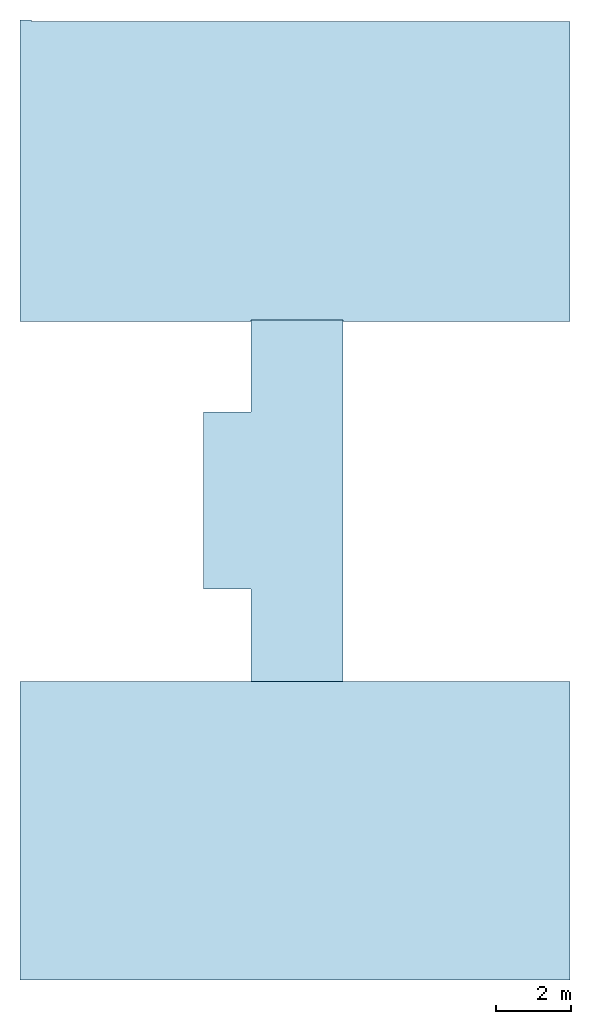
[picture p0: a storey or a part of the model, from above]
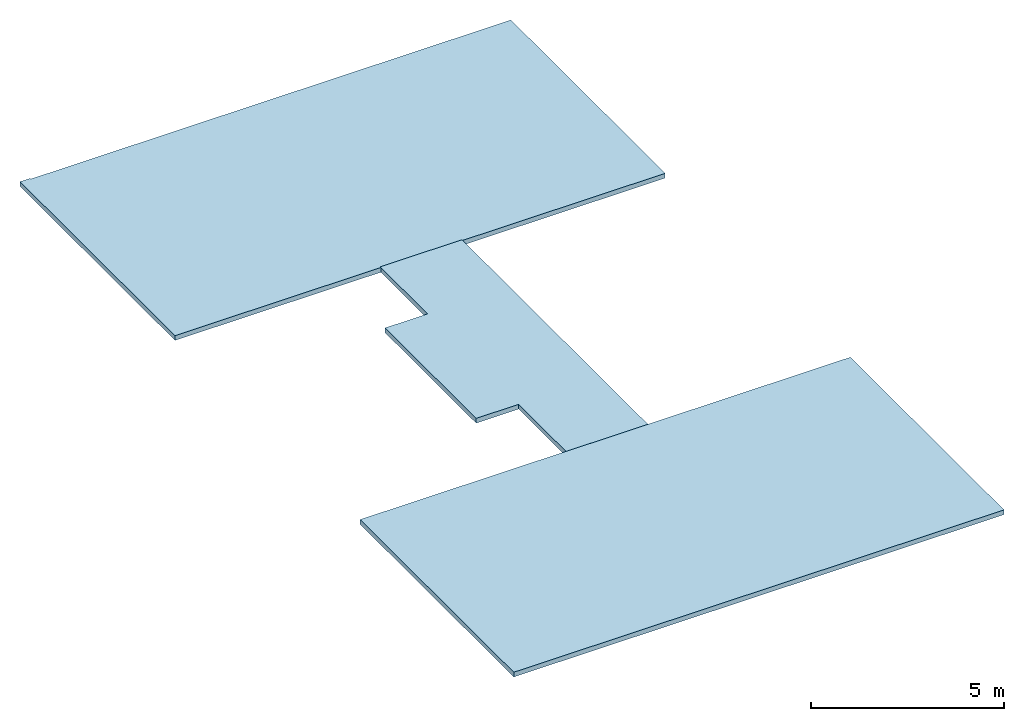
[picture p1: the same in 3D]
Properties of the parts of a building model (IFC2X3), part 1 of 7

# File
Description: ViewDefinition [CoordinationView_V2.0, QuantityTakeOffAddOnView], Option [Elements to export: Visible elements (on all stories)], Option [Partial Structure Display: Entire Model], Option [IFC Domain: All], Option [Structural Function: All Elements], Option [Convert Grid elements: On], Option [Convert IFC Annotations and ARCHICAD 2D elements: Off], Option [Convert 2D symbols of Doors and Windows: Off], Option [Export geometries that Participates in Collision Detection only: On], Option [Split complex elements: Off], Option [Material Preservation: Explode where necessary], Option [Elements in Solid Element Operations: Extruded/revolved], Option [Elements with junctions: Extruded/revolved without junctions], Option [IFC Model position: Survey Point and Project Origin], Option [Curtain Wall export mode: Container Element], Option [Railing export mode: Container Element], Option [Stair export mode: Container Element], Option [Properties To Export: All properties], Option [Space containment: Off], Option [Bounding Box: Off], Option [Geometry to type objects: Off], Option [Element Properties: All], Option [Building Material Properties: Off], Option [Element Parameters: IFC Element Quantities Only], Option [Component Parameters: All], Option [IFC Base Quantities: On], Option [Door Window Parameters: On], Option [IFC Space boundaries: Off], Option [ARCHICAD Zone Categories as IFC Space classification data: Off], Option [Element Classifications: On]
File name: H:\FAU 2022\PUB\entrega 6\CECAP-PMR R06 IFC2X3.ifc
Time: 2022-08-30T10:22:52
Author: Architect
Organization: Building Designer Office
Written by: The EXPRESS Data Manager Version 5.02.0100.09 : 26 Sep 2013
Made in: IFC file generated by GRAPHISOFT ARCHICAD 25.0.0 BRA FULL Windows version (IFC add-on version: 5010 BRA FULL).
Authorization: The authorising person

# IfcProject, CECAP Guarulhos
Description: Residência com Subsídio Governamental

# IfcSite, Local
RefLatitude: -23, -32, 0, 0; RefLongitude: -46, -38, 0, 0; RefElevation: 0 mm
BaseQuantities - GrossPerimeter: 0 mm; GrossArea: 0 m2

# IfcBuilding, Construção
BaseQuantities - GrossFloorArea: 1045.01 m2

# IfcBuildingStorey (5)
In: Construção
BaseQuantities - NetHeight: 2650 mm; GrossHeight: 2650 mm; Height: 2650 mm
Name | Elevation (mm) | GrossFloorArea (m2)
Pavimento Terreo | -2650 | 271.185
Primeiro Pavimento | 0 | 258.197
Segundo Pavimento | 2650 | 257.883
Terceiro Pavimento | 5300 | 257.748
Pavimento Cobertura | 7950 | 0

# IfcSpace: CIRCULAÇÃO (7)
InteriorOrExteriorSpace: INTERNAL
Pset_SpaceCommon - Category: CIRCULAÇÃO
ILUMINAÇÃO E VENTILAÇÃO (Expressão) - Área das Aberturas Projetada: 0; Atende: Atende; Não Atende: Não Atende
REVESTIMENTO DE PAREDE POR ZONA (Expressão) - Número de Linhas: 10; DImensão 1: 0 mm; Dimensão 2: 0 mm; Largura do Rejunte: 10 mm; Altura do Revestimento: 100 mm
RODAPÉ (Expressão) - Comprimento da Barra (m): 2.4; Custo da Barra: 0; Estimativa de Custo: 0
AC_Pset_RenovationAndPhasing - Renovation Status: Existing
BaseQuantities - FinishFloorHeight: 0 mm
ArchiCADQuantities - Elevação ao Piso: 0 mm; Afastamento da Origem: 0 mm; Afastamento do Topo: 0 mm; Perímetro Furos da Planta: 0 mm; Elevação da Base Ao Piso de Origem: 0 mm; Nível Base: 0 mm; Número de Pilares: 0; Número de Luminárias: 0; Número de Objetos: 0; Número de Janelas: 0; Área de Superfície das Janelas: 0 m2; Largura Janelas: 0 mm; Espessura de Pavimento: 0 mm; Redução de área: 1 m2; Extrair Área da Base do Pilar: 0 m2; Extrair Área da Trama: 0 m2; Área Baixa Extraída: 0 m2; Extrair Área da Base da Parede: 0 m2; Área Total Extraída: 0 m2; Inserção da Parede no Lado Posterior da Área de Superfície: 0 m2; Inserção da Parede no Lado da Área de Superfície: 0 m2; Inserção da Parede na Área da Superfície do Topo: 0 m2; Área Extraída da Parede Cortina: 0 m2
AC_Equantity_Selo_de_Zona_01_25 - Perímetro dos Vãos: 0 mm; Largura Combinada das Janelas: 0 mm; Nível do Piso: 0 mm; Espessura do Subpiso: 0 mm; Tamanho de Fonte para Texto de Detalhe (modelo): 300 mm
Name | In | LongName | Classification | Zona - Número de Azulejos Necessários | Quantidade de Barras | ID Dinâmico por Classificação | Height (mm) = FinishCeilingHeight (mm) = ClearHeight (mm) = ArchiCADQuantities, Altura (mm) = Elevação do Topo Ao Piso de Origem (mm) = AC_Equantity_Selo_de_Zona_01_25, Altura (mm) | GrossFloorArea (m2) = NetFloorArea (m2) = SpaceNetFloorAreaBOMA (m2) = SpaceUsableFloorAreaBOMA (m2) = GrossCeilingArea (m2) = NetCeilingArea (m2) = Área (m2) = Área da Superfície do Topo (Líquida) (m2) = Área da Superfície da Base (Líquida) (m2) = Área Calculada (m2) = Área Medida (m2) = Área Líquida Medida (m2) = Área Reduzida (m2) | GrossWallArea (m2) | NetWallArea (m2) = Área de Superfície das Paredes (m2) | GrossPerimeter (mm) = NetPerimeter (mm) = Perímetro Útil da Zona (mm) = Perímetro Bruto Zona (mm) = Perímetro (mm) = Perímetro Útil (mm) | GrossVolume (m3) = NetVolume (m3) = Volume (Líquido) (m3) | Elevação à Origem do Projeto (mm) = Elevação ao 1º Nível de Referência (mm) = Elevação ao 2º Nível de Referência (mm) = Elevação ao Nível do Mar (mm) = Elevação da Base Ao Primeiro Nível de Referência (mm) = Elevação da Base À Cota Zero (mm) = Elevação da Base Ao Nível do Mar (mm) = Elevação da Base Ao Segundo Nível de Referência (mm) | Elevação do Topo ao Primeiro Nível de Referência (mm) = Elevação do Topo À Cota Zero (mm) = Elevação do Topo Ao Nível do Mar (mm) = Elevação do Topo Ao Segundo Nível de Referência (mm) | Área da Superfície da Borda (Líquida) (m2) | Número de Vigas | Número de Portas | Número de Itens de Paredes | Área de Superfície das Portas (m2) | Largura Portas (mm) = Largura Combinada das Portas (mm) | Perímetro Paredes (mm) = Comprimento das Paredes Perímetro (mm) | Número dos Cantos Côncavos | Número de Cantos | Estimativa de Rodapé (ml) (mm)
02 | Pavimento Terreo | ESCADA | Zoneamento (Classificação ARCHICAD); 4A 16 01 04 07 Escada de Uso Comum (NBR 15965-6 4A) | 15630 | 4 | Zoneamento -002 | 2650 | 7.0315 | 21.8576 | 21.8576 | 15630 | 18.6335 | -2650 | 0 | 41.4195 | 2 | 0 | 5 | 0 | 0 | 9050 | 2 | 8 | 9050
33 | Primeiro Pavimento | CORREDOR | Zoneamento (Classificação ARCHICAD); 4A 16 04 01 Corredor (NBR 15965-6 4A) | 25080 | 10 | Zoneamento -004 | 2650 | 20.0698 | 41.925 | 34.365 | 28680 | 53.185 | 0 | 2650 | 76.002 | 6 | 4 | 22 | 7.56 | 3600 | 26812.9 | 10 | 24 | 23212.9
34 | Primeiro Pavimento | ESCADA | Zoneamento (Classificação ARCHICAD); 4A 16 01 04 07 Escada de Uso Comum (NBR 15965-6 4A) | 15630 | 4 | Zoneamento -005 | 5300 | 7.0315 | 21.8576 | 21.8576 | 15630 | 37.2669 | 0 | 5300 | 41.4195 | 2 | 0 | 5 | 0 | 0 | 9050 | 2 | 8 | 9050
33 | Segundo Pavimento | CORREDOR | Zoneamento (Classificação ARCHICAD); 4A 16 04 01 Corredor (NBR 15965-6 4A) | 25080 | 10 | Zoneamento -032 | 2650 | 20.0698 | 41.981 | 34.421 | 28680 | 53.185 | 2650 | 5300 | 76.002 | 6 | 4 | 23 | 7.56 | 3600 | 26812.9 | 10 | 24 | 23212.9
34 | Segundo Pavimento | ESCADA | Zoneamento (Classificação ARCHICAD); 4A 16 01 04 07 Escada de Uso Comum (NBR 15965-6 4A) | 15630 | 4 | Zoneamento -031 | 5300 | 7.0315 | 23.0336 | 23.0336 | 15630 | 37.2669 | 2650 | 7950 | 41.4195 | 2 | 0 | 6 | 0 | 0 | 9050 | 2 | 8 | 9050
33 | Terceiro Pavimento | CORREDOR | Zoneamento (Classificação ARCHICAD); 4A 16 04 01 Corredor (NBR 15965-6 4A) | 25080 | 10 | Zoneamento -060 | 2650 | 20.0698 | 41.292 | 33.732 | 28680 | 53.185 | 5300 | 7950 | 76.002 | 6 | 4 | 22 | 7.56 | 3600 | 26812.9 | 10 | 24 | 23212.9
34 | Terceiro Pavimento | ESCADA | Zoneamento (Classificação ARCHICAD); 4A 16 01 04 07 Escada de Uso Comum (NBR 15965-6 4A) | 15630 | 4 | Zoneamento -041 | 2650 | 7.0315 | 21.29 | 21.29 | 15630 | 18.6335 | 5300 | 7950 | 41.4195 | 3 | 0 | 5 | 0 | 0 | 9050 | 2 | 8 | 9050

# IfcSpace: ESTACIONAMENTO (2)
In: Pavimento Terreo
LongName: ESTACIONAMENTO; InteriorOrExteriorSpace: INTERNAL; Classification: Zoneamento (Classificação ARCHICAD); 4A 19 04 13 Garagem (NBR 15965-6 4A)
Pset_SpaceCommon - Category: ESTACIONAMENTO
ILUMINAÇÃO E VENTILAÇÃO (Expressão) - Área das Aberturas Projetada: 0; Atende: Atende; Não Atende: Não Atende
REVESTIMENTO DE PAREDE POR ZONA (Expressão) - Número de Linhas: 10; Zona - Número de Azulejos Necessários: 45870; DImensão 1: 0 mm; Dimensão 2: 0 mm; Largura do Rejunte: 10 mm; Altura do Revestimento: 100 mm
RODAPÉ (Expressão) - Comprimento da Barra (m): 2.4; Quantidade de Barras: 0; Custo da Barra: 0; Estimativa de Custo: 0; Estimativa de Rodapé (ml): 0 mm
AC_Pset_RenovationAndPhasing - Renovation Status: Existing
BaseQuantities - Height: 2650 mm; FinishCeilingHeight: 2650 mm; FinishFloorHeight: 0 mm; ClearHeight: 2650 mm; GrossFloorArea: 121.248 m2; NetFloorArea: 121.248 m2; SpaceNetFloorAreaBOMA: 121.248 m2; SpaceUsableFloorAreaBOMA: 121.248 m2; GrossCeilingArea: 121.248 m2; NetCeilingArea: 121.248 m2; GrossWallArea: 0 m2; NetWallArea: 0 m2; GrossPerimeter: 45870 mm; NetPerimeter: 45870 mm; GrossVolume: 321.306 m3; NetVolume: 321.306 m3
ArchiCADQuantities - Área: 121.248 m2; Altura: 2650 mm; Volume (Líquido): 321.306 m3; Elevação à Origem do Projeto: -2650 mm; Elevação ao 1º Nível de Referência: -2650 mm; Elevação ao 2º Nível de Referência: -2650 mm; Elevação ao Nível do Mar: -2650 mm; Elevação ao Piso: 0 mm; Afastamento da Origem: 0 mm; Afastamento do Topo: 0 mm; Perímetro Furos da Planta: 0 mm; Elevação do Topo ao Primeiro Nível de Referência: 0 mm; Elevação do Topo Ao Piso de Origem: 2650 mm; Elevação do Topo À Cota Zero: 0 mm; Elevação do Topo Ao Nível do Mar: 0 mm; Elevação do Topo Ao Segundo Nível de Referência: 0 mm; Elevação da Base Ao Primeiro Nível de Referência: -2650 mm; Elevação da Base Ao Piso de Origem: 0 mm; Elevação da Base À Cota Zero: -2650 mm; Elevação da Base Ao Nível do Mar: -2650 mm; Elevação da Base Ao Segundo Nível de Referência: -2650 mm; Área da Superfície do Topo (Líquida): 121.248 m2; Área da Superfície da Borda (Líquida): 121.556 m2; Área da Superfície da Base (Líquida): 121.248 m2; Nível Base: 0 mm; Número de Vigas: 11; Número de Pilares: 6; Número de Portas: 0; Número de Luminárias: 0; Número de Objetos: 0; Número de Janelas: 0; Número de Itens de Paredes: 0; Área Calculada: 121.248 m2; Área Medida: 121.248 m2; Área de Superfície das Janelas: 0 m2; Área de Superfície das Portas: 0 m2; Área de Superfície das Paredes: 0 m2; Largura Portas: 0 mm; Largura Janelas: 0 mm; Perímetro Paredes: 0 mm; Perímetro Útil da Zona: 45870 mm; Perímetro Bruto Zona: 45870 mm; Espessura de Pavimento: 0 mm; Redução de área: 1 m2; Extrair Área da Base do Pilar: 0 m2; Extrair Área da Trama: 0 m2; Área Baixa Extraída: 0 m2; Extrair Área da Base da Parede: 0 m2; Área Líquida Medida: 121.248 m2; Número dos Cantos Côncavos: 0; Número de Cantos: 4; Área Reduzida: 121.248 m2; Área Total Extraída: 0 m2; Inserção da Parede no Lado Posterior da Área de Superfície: 0 m2; Inserção da Parede no Lado da Área de Superfície: 0 m2; Inserção da Parede na Área da Superfície do Topo: 0 m2; Área Extraída da Parede Cortina: 0 m2
AC_Equantity_Selo_de_Zona_01_25 - Perímetro: 45870 mm; Perímetro dos Vãos: 0 mm; Comprimento das Paredes Perímetro: 0 mm; Largura Combinada das Portas: 0 mm; Largura Combinada das Janelas: 0 mm; Nível do Piso: 0 mm; Espessura do Subpiso: 0 mm; Altura: 2650 mm; Perímetro Útil: 45870 mm; Tamanho de Fonte para Texto de Detalhe (modelo): 300 mm
Name | ID Dinâmico por Classificação
04 | Zoneamento -001
03 | Zoneamento -000

# IfcSpace: ÁREA COMUM, 01
In: Pavimento Terreo
LongName: ÁREA COBERTA; InteriorOrExteriorSpace: INTERNAL; Classification: Zoneamento (Classificação ARCHICAD); 4A 16 04 01 Corredor (NBR 15965-6 4A)
Pset_SpaceCommon - Category: ÁREA COMUM
ILUMINAÇÃO E VENTILAÇÃO (Expressão) - Área das Aberturas Projetada: 0; Atende: Atende; Não Atende: Não Atende
REVESTIMENTO DE PAREDE POR ZONA (Expressão) - Número de Linhas: 10; Zona - Número de Azulejos Necessários: 28540; DImensão 1: 0 mm; Dimensão 2: 0 mm; Largura do Rejunte: 10 mm; Altura do Revestimento: 100 mm
RODAPÉ (Expressão) - Comprimento da Barra (m): 2.4; Quantidade de Barras: 11; Custo da Barra: 0; Estimativa de Custo: 0; Estimativa de Rodapé (ml): 26812.9 mm
EXPRESSÕES DE TEXTO (Expressão) - ID Dinâmico por Classificação: Zoneamento -003
AC_Pset_RenovationAndPhasing - Renovation Status: Existing
BaseQuantities - Height: 2650 mm; FinishCeilingHeight: 2650 mm; FinishFloorHeight: 0 mm; ClearHeight: 2650 mm; GrossFloorArea: 20.0831 m2; NetFloorArea: 20.0831 m2; SpaceNetFloorAreaBOMA: 20.0831 m2; SpaceUsableFloorAreaBOMA: 20.0831 m2; GrossCeilingArea: 20.0831 m2; NetCeilingArea: 20.0831 m2; GrossWallArea: 16.991 m2; NetWallArea: 16.991 m2; GrossPerimeter: 28540 mm; NetPerimeter: 28540 mm; GrossVolume: 53.2202 m3; NetVolume: 53.2202 m3
ArchiCADQuantities - Área: 20.0831 m2; Altura: 2650 mm; Volume (Líquido): 53.2202 m3; Elevação à Origem do Projeto: -2650 mm; Elevação ao 1º Nível de Referência: -2650 mm; Elevação ao 2º Nível de Referência: -2650 mm; Elevação ao Nível do Mar: -2650 mm; Elevação ao Piso: 0 mm; Afastamento da Origem: 0 mm; Afastamento do Topo: 0 mm; Perímetro Furos da Planta: 0 mm; Elevação do Topo ao Primeiro Nível de Referência: 0 mm; Elevação do Topo Ao Piso de Origem: 2650 mm; Elevação do Topo À Cota Zero: 0 mm; Elevação do Topo Ao Nível do Mar: 0 mm; Elevação do Topo Ao Segundo Nível de Referência: 0 mm; Elevação da Base Ao Primeiro Nível de Referência: -2650 mm; Elevação da Base Ao Piso de Origem: 0 mm; Elevação da Base À Cota Zero: -2650 mm; Elevação da Base Ao Nível do Mar: -2650 mm; Elevação da Base Ao Segundo Nível de Referência: -2650 mm; Área da Superfície do Topo (Líquida): 20.0831 m2; Área da Superfície da Borda (Líquida): 75.631 m2; Área da Superfície da Base (Líquida): 20.0831 m2; Nível Base: 0 mm; Número de Vigas: 4; Número de Pilares: 0; Número de Portas: 0; Número de Luminárias: 0; Número de Objetos: 0; Número de Janelas: 0; Número de Itens de Paredes: 9; Área Calculada: 20.0831 m2; Área Medida: 20.0831 m2; Área de Superfície das Janelas: 0 m2; Área de Superfície das Portas: 0 m2; Área de Superfície das Paredes: 16.991 m2; Largura Portas: 0 mm; Largura Janelas: 0 mm; Perímetro Paredes: 26812.9 mm; Perímetro Útil da Zona: 28540 mm; Perímetro Bruto Zona: 28540 mm; Espessura de Pavimento: 0 mm; Redução de área: 1 m2; Extrair Área da Base do Pilar: 0 m2; Extrair Área da Trama: 0 m2; Área Baixa Extraída: 0 m2; Extrair Área da Base da Parede: 0 m2; Área Líquida Medida: 20.0831 m2; Número dos Cantos Côncavos: 4; Número de Cantos: 20; Área Reduzida: 20.0831 m2; Área Total Extraída: 0 m2; Inserção da Parede no Lado Posterior da Área de Superfície: 0 m2; Inserção da Parede no Lado da Área de Superfície: 0 m2; Inserção da Parede na Área da Superfície do Topo: 0 m2; Área Extraída da Parede Cortina: 0 m2
AC_Equantity_Selo_de_Zona_01_25 - Perímetro: 28540 mm; Perímetro dos Vãos: 0 mm; Comprimento das Paredes Perímetro: 26812.9 mm; Largura Combinada das Portas: 3600 mm; Largura Combinada das Janelas: 0 mm; Nível do Piso: 0 mm; Espessura do Subpiso: 0 mm; Altura: 2650 mm; Perímetro Útil: 28540 mm; Tamanho de Fonte para Texto de Detalhe (modelo): 300 mm

# IfcSpace: ÁREA PRIVATIVA APTO 01 (7)
In: Primeiro Pavimento
InteriorOrExteriorSpace: INTERNAL
Pset_SpaceCommon - Category: ÁREA PRIVATIVA APTO 01
ILUMINAÇÃO E VENTILAÇÃO (Expressão) - Área das Aberturas Projetada: 0; Atende: Atende; Não Atende: Não Atende
REVESTIMENTO DE PAREDE POR ZONA (Expressão) - Número de Linhas: 10; DImensão 1: 0 mm; Dimensão 2: 0 mm; Largura do Rejunte: 10 mm; Altura do Revestimento: 100 mm
RODAPÉ (Expressão) - Comprimento da Barra (m): 2.4; Custo da Barra: 0; Estimativa de Custo: 0
AC_Pset_RenovationAndPhasing - Renovation Status: Existing
BaseQuantities - Height: 2650 mm; FinishCeilingHeight: 2650 mm; FinishFloorHeight: 0 mm; ClearHeight: 2650 mm
ArchiCADQuantities - Altura: 2650 mm; Elevação à Origem do Projeto: 0 mm; Elevação ao 1º Nível de Referência: 0 mm; Elevação ao 2º Nível de Referência: 0 mm; Elevação ao Nível do Mar: 0 mm; Elevação ao Piso: 0 mm; Afastamento da Origem: 0 mm; Afastamento do Topo: 0 mm; Perímetro Furos da Planta: 0 mm; Elevação do Topo ao Primeiro Nível de Referência: 2650 mm; Elevação do Topo Ao Piso de Origem: 2650 mm; Elevação do Topo À Cota Zero: 2650 mm; Elevação do Topo Ao Nível do Mar: 2650 mm; Elevação do Topo Ao Segundo Nível de Referência: 2650 mm; Elevação da Base Ao Primeiro Nível de Referência: 0 mm; Elevação da Base Ao Piso de Origem: 0 mm; Elevação da Base À Cota Zero: 0 mm; Elevação da Base Ao Nível do Mar: 0 mm; Elevação da Base Ao Segundo Nível de Referência: 0 mm; Nível Base: 0 mm; Número de Pilares: 0; Número de Luminárias: 0; Número de Objetos: 0; Número de Janelas: 0; Área de Superfície das Janelas: 0 m2; Largura Janelas: 0 mm; Espessura de Pavimento: 0 mm; Redução de área: 1 m2; Extrair Área da Base do Pilar: 0 m2; Extrair Área da Trama: 0 m2; Área Baixa Extraída: 0 m2; Extrair Área da Base da Parede: 0 m2; Número dos Cantos Côncavos: 0; Número de Cantos: 4; Área Total Extraída: 0 m2; Inserção da Parede no Lado Posterior da Área de Superfície: 0 m2; Inserção da Parede no Lado da Área de Superfície: 0 m2; Inserção da Parede na Área da Superfície do Topo: 0 m2; Área Extraída da Parede Cortina: 0 m2
AC_Equantity_Selo_de_Zona_01_25 - Perímetro dos Vãos: 0 mm; Nível do Piso: 0 mm; Espessura do Subpiso: 0 mm; Altura: 2650 mm; Tamanho de Fonte para Texto de Detalhe (modelo): 300 mm
Name | LongName | Classification | Zona - Número de Azulejos Necessários | Quantidade de Barras | ID Dinâmico por Classificação | GrossFloorArea (m2) = NetFloorArea (m2) = SpaceNetFloorAreaBOMA (m2) = SpaceUsableFloorAreaBOMA (m2) = GrossCeilingArea (m2) = NetCeilingArea (m2) = Área (m2) = Área da Superfície do Topo (Líquida) (m2) = Área da Superfície da Base (Líquida) (m2) = Área Calculada (m2) = Área Medida (m2) = Área Líquida Medida (m2) = Área Reduzida (m2) | GrossWallArea (m2) | NetWallArea (m2) = Área de Superfície das Paredes (m2) | GrossPerimeter (mm) = NetPerimeter (mm) = Perímetro Útil da Zona (mm) = Perímetro Bruto Zona (mm) = Perímetro (mm) = Perímetro Útil (mm) | GrossVolume (m3) = NetVolume (m3) = Volume (Líquido) (m3) | Área da Superfície da Borda (Líquida) (m2) | Número de Vigas | Número de Portas | Número de Itens de Paredes | Área de Superfície das Portas (m2) | Largura Portas (mm) | Perímetro Paredes (mm) = Comprimento das Paredes Perímetro (mm) | Largura Combinada das Portas (mm) | Largura Combinada das Janelas (mm) | Estimativa de Rodapé (ml) (mm)
06 | SALA | Zoneamento (Classificação ARCHICAD); 4A 19 01 07 Sala de Estar (NBR 15965-6 4A) | 15060 | 4 | Zoneamento -073 | 15.6592 | 23.3628 | 21.4728 | 15959.6 | 41.497 | 42.2928 | 5 | 1 | 5 | 1.89 | 900 | 9809.78 | 710 | 2040 | 8909.78
11 | QUARTO | Zoneamento (Classificação ARCHICAD); 4A 19 01 01 Dormitório (NBR 15965-6 4A) | 11010 | 4 | Zoneamento -074 | 7.12419 | 16.794 | 16.794 | 11010.2 | 18.8791 | 29.177 | 4 | 0 | 2 | 0 | 0 | 8850.18 | 0 | 2080 | 8850.18
10 | QUARTO | Zoneamento (Classificação ARCHICAD); 4A 19 01 01 Dormitório (NBR 15965-6 4A) | 10970 | 4 | Zoneamento -075 | 7.05588 | 16.8413 | 16.8413 | 10970.4 | 18.6981 | 29.0715 | 4 | 0 | 2 | 0 | 0 | 8830.36 | 0 | 2060 | 8830.36
09 | QUARTO | Zoneamento (Classificação ARCHICAD); 4A 19 01 01 Dormitório (NBR 15965-6 4A) | 12311 | 5 | Zoneamento -076 | 9.38311 | 16.6677 | 16.6677 | 12310.4 | 24.8652 | 32.6227 | 3 | 0 | 2 | 0 | 0 | 11330.4 | 0 | 2780 | 11330.4
05 | COZINHA | Zoneamento (Classificação ARCHICAD); 4A 19 01 25 Cozinha (NBR 15965-6 4A) | 12370 | 4 | Zoneamento -077 | 9.17955 | 19.063 | 17.572 | 13079.6 | 24.3258 | 34.6608 | 5 | 1 | 3 | 1.491 | 710 | 9809.78 | 710 | 2040 | 9099.78
07 | WC | Zoneamento (Classificação ARCHICAD); 4A 19 04 07 Banheiro residencial (NBR 15965-6 4A) | 7150 | 3 | Zoneamento -078 | 3.4827 | 19.1359 | 17.6449 | 7859.56 | 9.22916 | 20.8278 | 3 | 1 | 4 | 1.491 | 710 | 7859.56 | 710 | 0 | 7149.56
08 | LAVANDERIA | Zoneamento (Classificação ARCHICAD); 4A 19 04 04 Lavanderia (NBR 15965-6 4A) | 5940 | 2 | Zoneamento -079 | 2.187 | 9.09455 | 9.09455 | 5940 | 5.79555 | 15.741 | 2 | 0 | 3 | 0 | 0 | 3510 | 0 | 0 | 3510

# IfcSpace: ÁREA PRIVATIVA APTO 02 (7)
In: Primeiro Pavimento
InteriorOrExteriorSpace: INTERNAL
Pset_SpaceCommon - Category: ÁREA PRIVATIVA APTO 02
ILUMINAÇÃO E VENTILAÇÃO (Expressão) - Área das Aberturas Projetada: 0; Atende: Atende; Não Atende: Não Atende
REVESTIMENTO DE PAREDE POR ZONA (Expressão) - Número de Linhas: 10; DImensão 1: 0 mm; Dimensão 2: 0 mm; Largura do Rejunte: 10 mm; Altura do Revestimento: 100 mm
RODAPÉ (Expressão) - Comprimento da Barra (m): 2.4; Custo da Barra: 0; Estimativa de Custo: 0
AC_Pset_RenovationAndPhasing - Renovation Status: Existing
BaseQuantities - Height: 2650 mm; FinishCeilingHeight: 2650 mm; FinishFloorHeight: 0 mm; ClearHeight: 2650 mm
ArchiCADQuantities - Altura: 2650 mm; Elevação à Origem do Projeto: 0 mm; Elevação ao 1º Nível de Referência: 0 mm; Elevação ao 2º Nível de Referência: 0 mm; Elevação ao Nível do Mar: 0 mm; Elevação ao Piso: 0 mm; Afastamento da Origem: 0 mm; Afastamento do Topo: 0 mm; Perímetro Furos da Planta: 0 mm; Elevação do Topo ao Primeiro Nível de Referência: 2650 mm; Elevação do Topo Ao Piso de Origem: 2650 mm; Elevação do Topo À Cota Zero: 2650 mm; Elevação do Topo Ao Nível do Mar: 2650 mm; Elevação do Topo Ao Segundo Nível de Referência: 2650 mm; Elevação da Base Ao Primeiro Nível de Referência: 0 mm; Elevação da Base Ao Piso de Origem: 0 mm; Elevação da Base À Cota Zero: 0 mm; Elevação da Base Ao Nível do Mar: 0 mm; Elevação da Base Ao Segundo Nível de Referência: 0 mm; Nível Base: 0 mm; Número de Pilares: 0; Número de Luminárias: 0; Número de Objetos: 0; Número de Janelas: 0; Área de Superfície das Janelas: 0 m2; Largura Janelas: 0 mm; Espessura de Pavimento: 0 mm; Redução de área: 1 m2; Extrair Área da Base do Pilar: 0 m2; Extrair Área da Trama: 0 m2; Área Baixa Extraída: 0 m2; Extrair Área da Base da Parede: 0 m2; Número dos Cantos Côncavos: 0; Número de Cantos: 4; Área Total Extraída: 0 m2; Inserção da Parede no Lado Posterior da Área de Superfície: 0 m2; Inserção da Parede no Lado da Área de Superfície: 0 m2; Inserção da Parede na Área da Superfície do Topo: 0 m2; Área Extraída da Parede Cortina: 0 m2
AC_Equantity_Selo_de_Zona_01_25 - Perímetro dos Vãos: 0 mm; Nível do Piso: 0 mm; Espessura do Subpiso: 0 mm; Altura: 2650 mm; Tamanho de Fonte para Texto de Detalhe (modelo): 300 mm
Name | LongName | Classification | Zona - Número de Azulejos Necessários | Quantidade de Barras | ID Dinâmico por Classificação | GrossFloorArea (m2) = NetFloorArea (m2) = SpaceNetFloorAreaBOMA (m2) = SpaceUsableFloorAreaBOMA (m2) = GrossCeilingArea (m2) = NetCeilingArea (m2) = Área (m2) = Área da Superfície do Topo (Líquida) (m2) = Área da Superfície da Base (Líquida) (m2) = Área Calculada (m2) = Área Medida (m2) = Área Líquida Medida (m2) = Área Reduzida (m2) | GrossWallArea (m2) | NetWallArea (m2) = Área de Superfície das Paredes (m2) | GrossPerimeter (mm) = NetPerimeter (mm) = Perímetro Útil da Zona (mm) = Perímetro Bruto Zona (mm) = Perímetro (mm) = Perímetro Útil (mm) | GrossVolume (m3) = NetVolume (m3) = Volume (Líquido) (m3) | Área da Superfície da Borda (Líquida) (m2) | Número de Vigas | Número de Portas | Número de Itens de Paredes | Área de Superfície das Portas (m2) | Largura Portas (mm) | Perímetro Paredes (mm) = Comprimento das Paredes Perímetro (mm) | Largura Combinada das Portas (mm) | Largura Combinada das Janelas (mm) | Estimativa de Rodapé (ml) (mm)
16 | QUARTO | Zoneamento (Classificação ARCHICAD); 4A 19 01 01 Dormitório (NBR 15965-6 4A) | 12311 | 5 | Zoneamento -066 | 9.38311 | 16.6677 | 16.6677 | 12310.4 | 24.8652 | 32.6227 | 3 | 0 | 2 | 0 | 0 | 11330.4 | 0 | 2780 | 11330.4
17 | QUARTO | Zoneamento (Classificação ARCHICAD); 4A 19 01 01 Dormitório (NBR 15965-6 4A) | 10970 | 4 | Zoneamento -067 | 7.05588 | 16.8413 | 16.8413 | 10970.4 | 18.6981 | 29.0715 | 4 | 0 | 2 | 0 | 0 | 8830.36 | 0 | 2060 | 8830.36
18 | QUARTO | Zoneamento (Classificação ARCHICAD); 4A 19 01 01 Dormitório (NBR 15965-6 4A) | 11010 | 4 | Zoneamento -068 | 7.12419 | 16.794 | 16.794 | 11010.2 | 18.8791 | 29.177 | 4 | 0 | 2 | 0 | 0 | 8850.18 | 0 | 2080 | 8850.18
15 | LAVANDERIA | Zoneamento (Classificação ARCHICAD); 4A 19 04 04 Lavanderia (NBR 15965-6 4A) | 5940 | 2 | Zoneamento -069 | 2.187 | 9.09455 | 9.09455 | 5940 | 5.79555 | 15.741 | 2 | 0 | 3 | 0 | 0 | 3510 | 0 | 0 | 3510
12 | COZINHA | Zoneamento (Classificação ARCHICAD); 4A 19 01 25 Cozinha (NBR 15965-6 4A) | 12370 | 4 | Zoneamento -070 | 9.17955 | 19.063 | 17.572 | 13079.6 | 24.3258 | 34.6608 | 5 | 1 | 3 | 1.491 | 710 | 9809.78 | 710 | 2040 | 9099.78
14 | WC | Zoneamento (Classificação ARCHICAD); 4A 19 04 07 Banheiro residencial (NBR 15965-6 4A) | 7150 | 3 | Zoneamento -071 | 3.4827 | 19.1359 | 17.6449 | 7859.56 | 9.22916 | 20.8278 | 3 | 1 | 4 | 1.491 | 710 | 7859.56 | 710 | 0 | 7149.56
13 | SALA | Zoneamento (Classificação ARCHICAD); 4A 19 01 07 Sala de Estar (NBR 15965-6 4A) | 15060 | 4 | Zoneamento -072 | 15.6592 | 23.3628 | 21.4728 | 15959.6 | 41.497 | 42.2928 | 5 | 1 | 5 | 1.89 | 900 | 9809.78 | 710 | 2040 | 8909.78

# IfcSpace: ÁREA PRIVATIVA APTO 03 (7)
In: Primeiro Pavimento
InteriorOrExteriorSpace: INTERNAL
Pset_SpaceCommon - Category: ÁREA PRIVATIVA APTO 03
ILUMINAÇÃO E VENTILAÇÃO (Expressão) - Área das Aberturas Projetada: 0; Atende: Atende; Não Atende: Não Atende
REVESTIMENTO DE PAREDE POR ZONA (Expressão) - Número de Linhas: 10; DImensão 1: 0 mm; Dimensão 2: 0 mm; Largura do Rejunte: 10 mm; Altura do Revestimento: 100 mm
RODAPÉ (Expressão) - Comprimento da Barra (m): 2.4; Custo da Barra: 0; Estimativa de Custo: 0
AC_Pset_RenovationAndPhasing - Renovation Status: Existing
BaseQuantities - Height: 2650 mm; FinishCeilingHeight: 2650 mm; FinishFloorHeight: 0 mm; ClearHeight: 2650 mm
ArchiCADQuantities - Altura: 2650 mm; Elevação à Origem do Projeto: 0 mm; Elevação ao 1º Nível de Referência: 0 mm; Elevação ao 2º Nível de Referência: 0 mm; Elevação ao Nível do Mar: 0 mm; Elevação ao Piso: 0 mm; Afastamento da Origem: 0 mm; Afastamento do Topo: 0 mm; Perímetro Furos da Planta: 0 mm; Elevação do Topo ao Primeiro Nível de Referência: 2650 mm; Elevação do Topo Ao Piso de Origem: 2650 mm; Elevação do Topo À Cota Zero: 2650 mm; Elevação do Topo Ao Nível do Mar: 2650 mm; Elevação do Topo Ao Segundo Nível de Referência: 2650 mm; Elevação da Base Ao Primeiro Nível de Referência: 0 mm; Elevação da Base Ao Piso de Origem: 0 mm; Elevação da Base À Cota Zero: 0 mm; Elevação da Base Ao Nível do Mar: 0 mm; Elevação da Base Ao Segundo Nível de Referência: 0 mm; Nível Base: 0 mm; Número de Pilares: 0; Número de Luminárias: 0; Número de Objetos: 0; Número de Janelas: 0; Área de Superfície das Janelas: 0 m2; Largura Janelas: 0 mm; Espessura de Pavimento: 0 mm; Redução de área: 1 m2; Extrair Área da Base do Pilar: 0 m2; Extrair Área da Trama: 0 m2; Área Baixa Extraída: 0 m2; Extrair Área da Base da Parede: 0 m2; Número dos Cantos Côncavos: 0; Número de Cantos: 4; Área Total Extraída: 0 m2; Inserção da Parede no Lado Posterior da Área de Superfície: 0 m2; Inserção da Parede no Lado da Área de Superfície: 0 m2; Inserção da Parede na Área da Superfície do Topo: 0 m2; Área Extraída da Parede Cortina: 0 m2
AC_Equantity_Selo_de_Zona_01_25 - Perímetro dos Vãos: 0 mm; Nível do Piso: 0 mm; Espessura do Subpiso: 0 mm; Altura: 2650 mm; Tamanho de Fonte para Texto de Detalhe (modelo): 300 mm
Name | LongName | Classification | Zona - Número de Azulejos Necessários | Quantidade de Barras | ID Dinâmico por Classificação | GrossFloorArea (m2) = NetFloorArea (m2) = SpaceNetFloorAreaBOMA (m2) = SpaceUsableFloorAreaBOMA (m2) = GrossCeilingArea (m2) = NetCeilingArea (m2) = Área (m2) = Área da Superfície do Topo (Líquida) (m2) = Área da Superfície da Base (Líquida) (m2) = Área Calculada (m2) = Área Medida (m2) = Área Líquida Medida (m2) = Área Reduzida (m2) | GrossWallArea (m2) | NetWallArea (m2) = Área de Superfície das Paredes (m2) | GrossPerimeter (mm) = NetPerimeter (mm) = Perímetro Útil da Zona (mm) = Perímetro Bruto Zona (mm) = Perímetro (mm) = Perímetro Útil (mm) | GrossVolume (m3) = NetVolume (m3) = Volume (Líquido) (m3) | Área da Superfície da Borda (Líquida) (m2) | Número de Vigas | Número de Portas | Número de Itens de Paredes | Área de Superfície das Portas (m2) | Largura Portas (mm) | Perímetro Paredes (mm) = Comprimento das Paredes Perímetro (mm) | Largura Combinada das Portas (mm) | Largura Combinada das Janelas (mm) | Estimativa de Rodapé (ml) (mm)
22 | LAVANDERIA | Zoneamento (Classificação ARCHICAD); 4A 19 04 04 Lavanderia (NBR 15965-6 4A) | 5940 | 2 | Zoneamento -093 | 2.187 | 9.09455 | 9.09455 | 5940 | 5.79555 | 15.741 | 2 | 0 | 3 | 0 | 0 | 3510 | 0 | 0 | 3510
19 | COZINHA | Zoneamento (Classificação ARCHICAD); 4A 19 01 25 Cozinha (NBR 15965-6 4A) | 12370 | 4 | Zoneamento -092 | 9.17955 | 19.063 | 17.572 | 13079.6 | 24.3258 | 34.6608 | 5 | 1 | 3 | 1.491 | 710 | 9809.78 | 710 | 2040 | 9099.78
20 | SALA | Zoneamento (Classificação ARCHICAD); 4A 19 01 07 Sala de Estar (NBR 15965-6 4A) | 15060 | 4 | Zoneamento -091 | 15.6592 | 23.4855 | 21.5955 | 15959.6 | 41.497 | 42.2928 | 5 | 1 | 5 | 1.89 | 900 | 9809.78 | 710 | 2040 | 8909.78
25 | QUARTO | Zoneamento (Classificação ARCHICAD); 4A 19 01 01 Dormitório (NBR 15965-6 4A) | 11010 | 4 | Zoneamento -087 | 7.12419 | 16.8871 | 16.8871 | 11010.2 | 18.8791 | 29.177 | 4 | 0 | 2 | 0 | 0 | 8850.18 | 0 | 2080 | 8850.18
24 | QUARTO | Zoneamento (Classificação ARCHICAD); 4A 19 01 01 Dormitório (NBR 15965-6 4A) | 10970 | 4 | Zoneamento -088 | 7.05588 | 16.8413 | 16.8413 | 10970.4 | 18.6981 | 29.0715 | 4 | 0 | 2 | 0 | 0 | 8830.36 | 0 | 2060 | 8830.36
23 | QUARTO | Zoneamento (Classificação ARCHICAD); 4A 19 01 01 Dormitório (NBR 15965-6 4A) | 12311 | 5 | Zoneamento -089 | 9.38311 | 16.6677 | 16.6677 | 12310.4 | 24.8652 | 32.6227 | 3 | 0 | 2 | 0 | 0 | 11330.4 | 0 | 2780 | 11330.4
21 | WC | Zoneamento (Classificação ARCHICAD); 4A 19 04 07 Banheiro residencial (NBR 15965-6 4A) | 7150 | 3 | Zoneamento -090 | 3.4827 | 19.1359 | 17.6449 | 7859.56 | 9.22916 | 20.8278 | 3 | 1 | 4 | 1.491 | 710 | 7859.56 | 710 | 0 | 7149.56

# IfcSpace: ÁREA PRIVATIVA APTO 04 (7)
In: Primeiro Pavimento
InteriorOrExteriorSpace: INTERNAL
Pset_SpaceCommon - Category: ÁREA PRIVATIVA APTO 04
ILUMINAÇÃO E VENTILAÇÃO (Expressão) - Área das Aberturas Projetada: 0; Atende: Atende; Não Atende: Não Atende
REVESTIMENTO DE PAREDE POR ZONA (Expressão) - Número de Linhas: 10; DImensão 1: 0 mm; Dimensão 2: 0 mm; Largura do Rejunte: 10 mm; Altura do Revestimento: 100 mm
RODAPÉ (Expressão) - Comprimento da Barra (m): 2.4; Custo da Barra: 0; Estimativa de Custo: 0
AC_Pset_RenovationAndPhasing - Renovation Status: Existing
BaseQuantities - Height: 2650 mm; FinishCeilingHeight: 2650 mm; FinishFloorHeight: 0 mm; ClearHeight: 2650 mm
ArchiCADQuantities - Altura: 2650 mm; Elevação à Origem do Projeto: 0 mm; Elevação ao 1º Nível de Referência: 0 mm; Elevação ao 2º Nível de Referência: 0 mm; Elevação ao Nível do Mar: 0 mm; Elevação ao Piso: 0 mm; Afastamento da Origem: 0 mm; Afastamento do Topo: 0 mm; Perímetro Furos da Planta: 0 mm; Elevação do Topo ao Primeiro Nível de Referência: 2650 mm; Elevação do Topo Ao Piso de Origem: 2650 mm; Elevação do Topo À Cota Zero: 2650 mm; Elevação do Topo Ao Nível do Mar: 2650 mm; Elevação do Topo Ao Segundo Nível de Referência: 2650 mm; Elevação da Base Ao Primeiro Nível de Referência: 0 mm; Elevação da Base Ao Piso de Origem: 0 mm; Elevação da Base À Cota Zero: 0 mm; Elevação da Base Ao Nível do Mar: 0 mm; Elevação da Base Ao Segundo Nível de Referência: 0 mm; Nível Base: 0 mm; Número de Pilares: 0; Número de Luminárias: 0; Número de Objetos: 0; Número de Janelas: 0; Área de Superfície das Janelas: 0 m2; Largura Janelas: 0 mm; Espessura de Pavimento: 0 mm; Redução de área: 1 m2; Extrair Área da Base do Pilar: 0 m2; Extrair Área da Trama: 0 m2; Área Baixa Extraída: 0 m2; Extrair Área da Base da Parede: 0 m2; Número dos Cantos Côncavos: 0; Número de Cantos: 4; Área Total Extraída: 0 m2; Inserção da Parede no Lado Posterior da Área de Superfície: 0 m2; Inserção da Parede no Lado da Área de Superfície: 0 m2; Inserção da Parede na Área da Superfície do Topo: 0 m2; Área Extraída da Parede Cortina: 0 m2
AC_Equantity_Selo_de_Zona_01_25 - Perímetro dos Vãos: 0 mm; Nível do Piso: 0 mm; Espessura do Subpiso: 0 mm; Altura: 2650 mm; Tamanho de Fonte para Texto de Detalhe (modelo): 300 mm
Name | LongName | Classification | Zona - Número de Azulejos Necessários | Quantidade de Barras | ID Dinâmico por Classificação | GrossFloorArea (m2) = NetFloorArea (m2) = SpaceNetFloorAreaBOMA (m2) = SpaceUsableFloorAreaBOMA (m2) = GrossCeilingArea (m2) = NetCeilingArea (m2) = Área (m2) = Área da Superfície do Topo (Líquida) (m2) = Área da Superfície da Base (Líquida) (m2) = Área Calculada (m2) = Área Medida (m2) = Área Líquida Medida (m2) = Área Reduzida (m2) | GrossWallArea (m2) | NetWallArea (m2) = Área de Superfície das Paredes (m2) | GrossPerimeter (mm) = NetPerimeter (mm) = Perímetro Útil da Zona (mm) = Perímetro Bruto Zona (mm) = Perímetro (mm) = Perímetro Útil (mm) | GrossVolume (m3) = NetVolume (m3) = Volume (Líquido) (m3) | Área da Superfície da Borda (Líquida) (m2) | Número de Vigas | Número de Portas | Número de Itens de Paredes | Área de Superfície das Portas (m2) | Largura Portas (mm) | Perímetro Paredes (mm) = Comprimento das Paredes Perímetro (mm) | Largura Combinada das Portas (mm) | Largura Combinada das Janelas (mm) | Estimativa de Rodapé (ml) (mm)
29 | LAVANDERIA | Zoneamento (Classificação ARCHICAD); 4A 19 04 04 Lavanderia (NBR 15965-6 4A) | 5940 | 2 | Zoneamento -080 | 2.187 | 9.09455 | 9.09455 | 5940 | 5.79555 | 15.741 | 2 | 0 | 3 | 0 | 0 | 3510 | 0 | 0 | 3510
28 | WC | Zoneamento (Classificação ARCHICAD); 4A 19 04 07 Banheiro residencial (NBR 15965-6 4A) | 7150 | 3 | Zoneamento -081 | 3.4827 | 19.1359 | 17.6449 | 7859.56 | 9.22916 | 20.8278 | 3 | 1 | 4 | 1.491 | 710 | 7859.56 | 710 | 0 | 7149.56
26 | COZINHA | Zoneamento (Classificação ARCHICAD); 4A 19 01 25 Cozinha (NBR 15965-6 4A) | 12370 | 4 | Zoneamento -082 | 9.17955 | 19.063 | 17.572 | 13079.6 | 24.3258 | 34.6608 | 5 | 1 | 3 | 1.491 | 710 | 9809.78 | 710 | 2040 | 9099.78
27 | SALA | Zoneamento (Classificação ARCHICAD); 4A 19 01 07 Sala de Estar (NBR 15965-6 4A) | 15060 | 4 | Zoneamento -083 | 15.6592 | 23.4855 | 21.5955 | 15959.6 | 41.497 | 42.2928 | 5 | 1 | 5 | 1.89 | 900 | 9809.78 | 710 | 2040 | 8909.78
30 | QUARTO | Zoneamento (Classificação ARCHICAD); 4A 19 01 01 Dormitório (NBR 15965-6 4A) | 12311 | 5 | Zoneamento -084 | 9.38311 | 16.6677 | 16.6677 | 12310.4 | 24.8652 | 32.6227 | 3 | 0 | 2 | 0 | 0 | 11330.4 | 0 | 2780 | 11330.4
31 | QUARTO | Zoneamento (Classificação ARCHICAD); 4A 19 01 01 Dormitório (NBR 15965-6 4A) | 10970 | 4 | Zoneamento -085 | 7.05588 | 16.8413 | 16.8413 | 10970.4 | 18.6981 | 29.0715 | 4 | 0 | 2 | 0 | 0 | 8830.36 | 0 | 2060 | 8830.36
32 | QUARTO | Zoneamento (Classificação ARCHICAD); 4A 19 01 01 Dormitório (NBR 15965-6 4A) | 11010 | 4 | Zoneamento -086 | 7.12419 | 16.8871 | 16.8871 | 11010.2 | 18.8791 | 29.177 | 4 | 0 | 2 | 0 | 0 | 8850.18 | 0 | 2080 | 8850.18

# IfcSpace: ÁREA PRIVATIVA APTO 05 (7)
In: Segundo Pavimento
InteriorOrExteriorSpace: INTERNAL
Pset_SpaceCommon - Category: ÁREA PRIVATIVA APTO 05
ILUMINAÇÃO E VENTILAÇÃO (Expressão) - Área das Aberturas Projetada: 0; Atende: Atende; Não Atende: Não Atende
REVESTIMENTO DE PAREDE POR ZONA (Expressão) - Número de Linhas: 10; DImensão 1: 0 mm; Dimensão 2: 0 mm; Largura do Rejunte: 10 mm; Altura do Revestimento: 100 mm
RODAPÉ (Expressão) - Comprimento da Barra (m): 2.4; Custo da Barra: 0; Estimativa de Custo: 0
AC_Pset_RenovationAndPhasing - Renovation Status: Existing
BaseQuantities - Height: 2650 mm; FinishCeilingHeight: 2650 mm; FinishFloorHeight: 0 mm; ClearHeight: 2650 mm
ArchiCADQuantities - Altura: 2650 mm; Elevação à Origem do Projeto: 2650 mm; Elevação ao 1º Nível de Referência: 2650 mm; Elevação ao 2º Nível de Referência: 2650 mm; Elevação ao Nível do Mar: 2650 mm; Elevação ao Piso: 0 mm; Afastamento da Origem: 0 mm; Afastamento do Topo: 0 mm; Perímetro Furos da Planta: 0 mm; Elevação do Topo ao Primeiro Nível de Referência: 5300 mm; Elevação do Topo Ao Piso de Origem: 2650 mm; Elevação do Topo À Cota Zero: 5300 mm; Elevação do Topo Ao Nível do Mar: 5300 mm; Elevação do Topo Ao Segundo Nível de Referência: 5300 mm; Elevação da Base Ao Primeiro Nível de Referência: 2650 mm; Elevação da Base Ao Piso de Origem: 0 mm; Elevação da Base À Cota Zero: 2650 mm; Elevação da Base Ao Nível do Mar: 2650 mm; Elevação da Base Ao Segundo Nível de Referência: 2650 mm; Nível Base: 0 mm; Número de Pilares: 0; Número de Luminárias: 0; Número de Objetos: 0; Número de Janelas: 0; Área de Superfície das Janelas: 0 m2; Largura Janelas: 0 mm; Espessura de Pavimento: 0 mm; Redução de área: 1 m2; Extrair Área da Base do Pilar: 0 m2; Extrair Área da Trama: 0 m2; Área Baixa Extraída: 0 m2; Extrair Área da Base da Parede: 0 m2; Número dos Cantos Côncavos: 0; Número de Cantos: 4; Área Total Extraída: 0 m2; Inserção da Parede no Lado Posterior da Área de Superfície: 0 m2; Inserção da Parede no Lado da Área de Superfície: 0 m2; Inserção da Parede na Área da Superfície do Topo: 0 m2; Área Extraída da Parede Cortina: 0 m2
AC_Equantity_Selo_de_Zona_01_25 - Perímetro dos Vãos: 0 mm; Nível do Piso: 0 mm; Espessura do Subpiso: 0 mm; Altura: 2650 mm; Tamanho de Fonte para Texto de Detalhe (modelo): 300 mm
Name | LongName | Classification | Zona - Número de Azulejos Necessários | Quantidade de Barras | ID Dinâmico por Classificação | GrossFloorArea (m2) = NetFloorArea (m2) = SpaceNetFloorAreaBOMA (m2) = SpaceUsableFloorAreaBOMA (m2) = GrossCeilingArea (m2) = NetCeilingArea (m2) = Área (m2) = Área da Superfície do Topo (Líquida) (m2) = Área da Superfície da Base (Líquida) (m2) = Área Calculada (m2) = Área Medida (m2) = Área Líquida Medida (m2) = Área Reduzida (m2) | GrossWallArea (m2) | NetWallArea (m2) = Área de Superfície das Paredes (m2) | GrossPerimeter (mm) = NetPerimeter (mm) = Perímetro Útil da Zona (mm) = Perímetro Bruto Zona (mm) = Perímetro (mm) = Perímetro Útil (mm) | GrossVolume (m3) = NetVolume (m3) = Volume (Líquido) (m3) | Área da Superfície da Borda (Líquida) (m2) | Número de Vigas | Número de Portas | Número de Itens de Paredes | Área de Superfície das Portas (m2) | Largura Portas (mm) | Perímetro Paredes (mm) = Comprimento das Paredes Perímetro (mm) | Largura Combinada das Portas (mm) | Largura Combinada das Janelas (mm) | Estimativa de Rodapé (ml) (mm)
17 | LAVANDERIA | Zoneamento (Classificação ARCHICAD); 4A 19 04 04 Lavanderia (NBR 15965-6 4A) | 5940 | 2 | Zoneamento -025 | 2.187 | 9.09455 | 9.09455 | 5940 | 5.79555 | 15.741 | 2 | 0 | 3 | 0 | 0 | 3510 | 0 | 0 | 3510
09 | SALA | Zoneamento (Classificação ARCHICAD); 4A 19 01 07 Sala de Estar (NBR 15965-6 4A) | 15060 | 4 | Zoneamento -024 | 15.6592 | 23.3628 | 21.4728 | 15959.6 | 41.497 | 42.2928 | 5 | 1 | 5 | 1.89 | 900 | 9809.78 | 710 | 2040 | 8909.78
31 | QUARTO | Zoneamento (Classificação ARCHICAD); 4A 19 01 01 Dormitório (NBR 15965-6 4A) | 11010 | 4 | Zoneamento -028 | 7.12419 | 16.794 | 16.794 | 11010.2 | 18.8791 | 29.177 | 4 | 0 | 2 | 0 | 0 | 8850.18 | 0 | 2080 | 8850.18
13 | WC | Zoneamento (Classificação ARCHICAD); 4A 19 04 07 Banheiro residencial (NBR 15965-6 4A) | 7150 | 3 | Zoneamento -029 | 3.4827 | 19.1359 | 17.6449 | 7859.56 | 9.22916 | 20.8278 | 3 | 1 | 4 | 1.491 | 710 | 7859.56 | 710 | 0 | 7149.56
05 | COZINHA | Zoneamento (Classificação ARCHICAD); 4A 19 01 25 Cozinha (NBR 15965-6 4A) | 12370 | 4 | Zoneamento -026 | 9.17955 | 19.063 | 17.572 | 13079.6 | 24.3258 | 34.6608 | 5 | 1 | 3 | 1.491 | 710 | 9809.78 | 710 | 2040 | 9099.78
27 | QUARTO | Zoneamento (Classificação ARCHICAD); 4A 19 01 01 Dormitório (NBR 15965-6 4A) | 10970 | 4 | Zoneamento -027 | 7.05588 | 16.8413 | 16.8413 | 10970.4 | 18.6981 | 29.0715 | 4 | 0 | 2 | 0 | 0 | 8830.36 | 0 | 2060 | 8830.36
23 | QUARTO | Zoneamento (Classificação ARCHICAD); 4A 19 01 01 Dormitório (NBR 15965-6 4A) | 12311 | 5 | Zoneamento -030 | 9.38311 | 16.6677 | 16.6677 | 12310.4 | 24.8652 | 32.6227 | 3 | 0 | 2 | 0 | 0 | 11330.4 | 0 | 2780 | 11330.4

# IfcSpace: ÁREA PRIVATIVA APTO 06 (7)
In: Segundo Pavimento
InteriorOrExteriorSpace: INTERNAL
Pset_SpaceCommon - Category: ÁREA PRIVATIVA APTO 06
ILUMINAÇÃO E VENTILAÇÃO (Expressão) - Área das Aberturas Projetada: 0; Atende: Atende; Não Atende: Não Atende
REVESTIMENTO DE PAREDE POR ZONA (Expressão) - Número de Linhas: 10; DImensão 1: 0 mm; Dimensão 2: 0 mm; Largura do Rejunte: 10 mm; Altura do Revestimento: 100 mm
RODAPÉ (Expressão) - Comprimento da Barra (m): 2.4; Custo da Barra: 0; Estimativa de Custo: 0
AC_Pset_RenovationAndPhasing - Renovation Status: Existing
BaseQuantities - Height: 2650 mm; FinishCeilingHeight: 2650 mm; FinishFloorHeight: 0 mm; ClearHeight: 2650 mm
ArchiCADQuantities - Altura: 2650 mm; Elevação à Origem do Projeto: 2650 mm; Elevação ao 1º Nível de Referência: 2650 mm; Elevação ao 2º Nível de Referência: 2650 mm; Elevação ao Nível do Mar: 2650 mm; Elevação ao Piso: 0 mm; Afastamento da Origem: 0 mm; Afastamento do Topo: 0 mm; Perímetro Furos da Planta: 0 mm; Elevação do Topo ao Primeiro Nível de Referência: 5300 mm; Elevação do Topo Ao Piso de Origem: 2650 mm; Elevação do Topo À Cota Zero: 5300 mm; Elevação do Topo Ao Nível do Mar: 5300 mm; Elevação do Topo Ao Segundo Nível de Referência: 5300 mm; Elevação da Base Ao Primeiro Nível de Referência: 2650 mm; Elevação da Base Ao Piso de Origem: 0 mm; Elevação da Base À Cota Zero: 2650 mm; Elevação da Base Ao Nível do Mar: 2650 mm; Elevação da Base Ao Segundo Nível de Referência: 2650 mm; Nível Base: 0 mm; Número de Pilares: 0; Número de Luminárias: 0; Número de Objetos: 0; Número de Janelas: 0; Área de Superfície das Janelas: 0 m2; Largura Janelas: 0 mm; Espessura de Pavimento: 0 mm; Redução de área: 1 m2; Extrair Área da Base do Pilar: 0 m2; Extrair Área da Trama: 0 m2; Área Baixa Extraída: 0 m2; Extrair Área da Base da Parede: 0 m2; Número dos Cantos Côncavos: 0; Número de Cantos: 4; Área Total Extraída: 0 m2; Inserção da Parede no Lado Posterior da Área de Superfície: 0 m2; Inserção da Parede no Lado da Área de Superfície: 0 m2; Inserção da Parede na Área da Superfície do Topo: 0 m2; Área Extraída da Parede Cortina: 0 m2
AC_Equantity_Selo_de_Zona_01_25 - Perímetro dos Vãos: 0 mm; Nível do Piso: 0 mm; Espessura do Subpiso: 0 mm; Altura: 2650 mm; Tamanho de Fonte para Texto de Detalhe (modelo): 300 mm
Name | LongName | Classification | Zona - Número de Azulejos Necessários | Quantidade de Barras | ID Dinâmico por Classificação | GrossFloorArea (m2) = NetFloorArea (m2) = SpaceNetFloorAreaBOMA (m2) = SpaceUsableFloorAreaBOMA (m2) = GrossCeilingArea (m2) = NetCeilingArea (m2) = Área (m2) = Área da Superfície do Topo (Líquida) (m2) = Área da Superfície da Base (Líquida) (m2) = Área Calculada (m2) = Área Medida (m2) = Área Líquida Medida (m2) = Área Reduzida (m2) | GrossWallArea (m2) | NetWallArea (m2) = Área de Superfície das Paredes (m2) | GrossPerimeter (mm) = NetPerimeter (mm) = Perímetro Útil da Zona (mm) = Perímetro Bruto Zona (mm) = Perímetro (mm) = Perímetro Útil (mm) | GrossVolume (m3) = NetVolume (m3) = Volume (Líquido) (m3) | Área da Superfície da Borda (Líquida) (m2) | Número de Vigas | Número de Portas | Número de Itens de Paredes | Área de Superfície das Portas (m2) | Largura Portas (mm) | Perímetro Paredes (mm) = Comprimento das Paredes Perímetro (mm) | Largura Combinada das Portas (mm) | Largura Combinada das Janelas (mm) | Estimativa de Rodapé (ml) (mm)
13 | WC | Zoneamento (Classificação ARCHICAD); 4A 19 04 07 Banheiro residencial (NBR 15965-6 4A) | 7150 | 3 | Zoneamento -015 | 3.4827 | 19.1359 | 17.6449 | 7859.56 | 9.22916 | 20.8278 | 3 | 1 | 4 | 1.491 | 710 | 7859.56 | 710 | 0 | 7149.56
23 | QUARTO | Zoneamento (Classificação ARCHICAD); 4A 19 01 01 Dormitório (NBR 15965-6 4A) | 12311 | 5 | Zoneamento -014 | 9.38311 | 16.6677 | 16.6677 | 12310.4 | 24.8652 | 32.6227 | 3 | 0 | 2 | 0 | 0 | 11330.4 | 0 | 2780 | 11330.4
05 | COZINHA | Zoneamento (Classificação ARCHICAD); 4A 19 01 25 Cozinha (NBR 15965-6 4A) | 12370 | 4 | Zoneamento -016 | 9.17955 | 19.063 | 17.572 | 13079.6 | 24.3258 | 34.6608 | 5 | 1 | 3 | 1.491 | 710 | 9809.78 | 710 | 2040 | 9099.78
09 | SALA | Zoneamento (Classificação ARCHICAD); 4A 19 01 07 Sala de Estar (NBR 15965-6 4A) | 15060 | 4 | Zoneamento -017 | 15.6592 | 23.3628 | 21.4728 | 15959.6 | 41.497 | 42.2928 | 5 | 1 | 5 | 1.89 | 900 | 9809.78 | 710 | 2040 | 8909.78
17 | LAVANDERIA | Zoneamento (Classificação ARCHICAD); 4A 19 04 04 Lavanderia (NBR 15965-6 4A) | 5940 | 2 | Zoneamento -035 | 2.187 | 9.09455 | 9.09455 | 5940 | 5.79555 | 15.741 | 2 | 0 | 3 | 0 | 0 | 3510 | 0 | 0 | 3510
27 | QUARTO | Zoneamento (Classificação ARCHICAD); 4A 19 01 01 Dormitório (NBR 15965-6 4A) | 10970 | 4 | Zoneamento -034 | 7.05588 | 16.8413 | 16.8413 | 10970.4 | 18.6981 | 29.0715 | 4 | 0 | 2 | 0 | 0 | 8830.36 | 0 | 2060 | 8830.36
31 | QUARTO | Zoneamento (Classificação ARCHICAD); 4A 19 01 01 Dormitório (NBR 15965-6 4A) | 11010 | 4 | Zoneamento -033 | 7.12419 | 16.794 | 16.794 | 11010.2 | 18.8791 | 29.177 | 4 | 0 | 2 | 0 | 0 | 8850.18 | 0 | 2080 | 8850.18

# IfcSpace: ÁREA PRIVATIVA APTO 07 (7)
In: Segundo Pavimento
InteriorOrExteriorSpace: INTERNAL
Pset_SpaceCommon - Category: ÁREA PRIVATIVA APTO 07
ILUMINAÇÃO E VENTILAÇÃO (Expressão) - Área das Aberturas Projetada: 0; Atende: Atende; Não Atende: Não Atende
REVESTIMENTO DE PAREDE POR ZONA (Expressão) - Número de Linhas: 10; DImensão 1: 0 mm; Dimensão 2: 0 mm; Largura do Rejunte: 10 mm; Altura do Revestimento: 100 mm
RODAPÉ (Expressão) - Comprimento da Barra (m): 2.4; Custo da Barra: 0; Estimativa de Custo: 0
AC_Pset_RenovationAndPhasing - Renovation Status: Existing
BaseQuantities - Height: 2650 mm; FinishCeilingHeight: 2650 mm; FinishFloorHeight: 0 mm; ClearHeight: 2650 mm
ArchiCADQuantities - Altura: 2650 mm; Elevação à Origem do Projeto: 2650 mm; Elevação ao 1º Nível de Referência: 2650 mm; Elevação ao 2º Nível de Referência: 2650 mm; Elevação ao Nível do Mar: 2650 mm; Elevação ao Piso: 0 mm; Afastamento da Origem: 0 mm; Afastamento do Topo: 0 mm; Perímetro Furos da Planta: 0 mm; Elevação do Topo ao Primeiro Nível de Referência: 5300 mm; Elevação do Topo Ao Piso de Origem: 2650 mm; Elevação do Topo À Cota Zero: 5300 mm; Elevação do Topo Ao Nível do Mar: 5300 mm; Elevação do Topo Ao Segundo Nível de Referência: 5300 mm; Elevação da Base Ao Primeiro Nível de Referência: 2650 mm; Elevação da Base Ao Piso de Origem: 0 mm; Elevação da Base À Cota Zero: 2650 mm; Elevação da Base Ao Nível do Mar: 2650 mm; Elevação da Base Ao Segundo Nível de Referência: 2650 mm; Nível Base: 0 mm; Número de Pilares: 0; Número de Luminárias: 0; Número de Objetos: 0; Número de Janelas: 0; Área de Superfície das Janelas: 0 m2; Largura Janelas: 0 mm; Espessura de Pavimento: 0 mm; Redução de área: 1 m2; Extrair Área da Base do Pilar: 0 m2; Extrair Área da Trama: 0 m2; Área Baixa Extraída: 0 m2; Extrair Área da Base da Parede: 0 m2; Número dos Cantos Côncavos: 0; Número de Cantos: 4; Área Total Extraída: 0 m2; Inserção da Parede no Lado Posterior da Área de Superfície: 0 m2; Inserção da Parede no Lado da Área de Superfície: 0 m2; Inserção da Parede na Área da Superfície do Topo: 0 m2; Área Extraída da Parede Cortina: 0 m2
AC_Equantity_Selo_de_Zona_01_25 - Perímetro dos Vãos: 0 mm; Nível do Piso: 0 mm; Espessura do Subpiso: 0 mm; Altura: 2650 mm; Tamanho de Fonte para Texto de Detalhe (modelo): 300 mm
Name | LongName | Classification | Zona - Número de Azulejos Necessários | Quantidade de Barras | ID Dinâmico por Classificação | GrossFloorArea (m2) = NetFloorArea (m2) = SpaceNetFloorAreaBOMA (m2) = SpaceUsableFloorAreaBOMA (m2) = GrossCeilingArea (m2) = NetCeilingArea (m2) = Área (m2) = Área da Superfície do Topo (Líquida) (m2) = Área da Superfície da Base (Líquida) (m2) = Área Calculada (m2) = Área Medida (m2) = Área Líquida Medida (m2) = Área Reduzida (m2) | GrossWallArea (m2) | NetWallArea (m2) = Área de Superfície das Paredes (m2) | GrossPerimeter (mm) = NetPerimeter (mm) = Perímetro Útil da Zona (mm) = Perímetro Bruto Zona (mm) = Perímetro (mm) = Perímetro Útil (mm) | GrossVolume (m3) = NetVolume (m3) = Volume (Líquido) (m3) | Área da Superfície da Borda (Líquida) (m2) | Número de Vigas | Número de Portas | Número de Itens de Paredes | Área de Superfície das Portas (m2) | Largura Portas (mm) | Perímetro Paredes (mm) = Comprimento das Paredes Perímetro (mm) | Largura Combinada das Portas (mm) | Largura Combinada das Janelas (mm) | Estimativa de Rodapé (ml) (mm)
13 | WC | Zoneamento (Classificação ARCHICAD); 4A 19 04 07 Banheiro residencial (NBR 15965-6 4A) | 7150 | 3 | Zoneamento -019 | 3.4827 | 19.1359 | 17.6449 | 7859.56 | 9.22916 | 20.8278 | 3 | 1 | 4 | 1.491 | 710 | 7859.56 | 710 | 0 | 7149.56
05 | COZINHA | Zoneamento (Classificação ARCHICAD); 4A 19 01 25 Cozinha (NBR 15965-6 4A) | 12370 | 4 | Zoneamento -022 | 9.17955 | 19.063 | 17.572 | 13079.6 | 24.3258 | 34.6608 | 5 | 1 | 3 | 1.491 | 710 | 9809.78 | 710 | 2040 | 9099.78
09 | SALA | Zoneamento (Classificação ARCHICAD); 4A 19 01 07 Sala de Estar (NBR 15965-6 4A) | 15060 | 4 | Zoneamento -013 | 15.6592 | 23.4855 | 21.5955 | 15959.6 | 41.497 | 42.2928 | 5 | 1 | 5 | 1.89 | 900 | 9809.78 | 710 | 2040 | 8909.78
27 | QUARTO | Zoneamento (Classificação ARCHICAD); 4A 19 01 01 Dormitório (NBR 15965-6 4A) | 10970 | 4 | Zoneamento -021 | 7.05588 | 16.8413 | 16.8413 | 10970.4 | 18.6981 | 29.0715 | 4 | 0 | 2 | 0 | 0 | 8830.36 | 0 | 2060 | 8830.36
31 | QUARTO | Zoneamento (Classificação ARCHICAD); 4A 19 01 01 Dormitório (NBR 15965-6 4A) | 11010 | 4 | Zoneamento -020 | 7.12419 | 16.8871 | 16.8871 | 11010.2 | 18.8791 | 29.177 | 4 | 0 | 2 | 0 | 0 | 8850.18 | 0 | 2080 | 8850.18
17 | LAVANDERIA | Zoneamento (Classificação ARCHICAD); 4A 19 04 04 Lavanderia (NBR 15965-6 4A) | 5940 | 2 | Zoneamento -023 | 2.187 | 9.09455 | 9.09455 | 5940 | 5.79555 | 15.741 | 2 | 0 | 3 | 0 | 0 | 3510 | 0 | 0 | 3510
23 | QUARTO | Zoneamento (Classificação ARCHICAD); 4A 19 01 01 Dormitório (NBR 15965-6 4A) | 12311 | 5 | Zoneamento -018 | 9.38311 | 16.6677 | 16.6677 | 12310.4 | 24.8652 | 32.6227 | 3 | 0 | 2 | 0 | 0 | 11330.4 | 0 | 2780 | 11330.4

# IfcSpace: ÁREA PRIVATIVA APTO 08 (7)
In: Segundo Pavimento
InteriorOrExteriorSpace: INTERNAL
Pset_SpaceCommon - Category: ÁREA PRIVATIVA APTO 08
ILUMINAÇÃO E VENTILAÇÃO (Expressão) - Área das Aberturas Projetada: 0; Atende: Atende; Não Atende: Não Atende
REVESTIMENTO DE PAREDE POR ZONA (Expressão) - Número de Linhas: 10; DImensão 1: 0 mm; Dimensão 2: 0 mm; Largura do Rejunte: 10 mm; Altura do Revestimento: 100 mm
RODAPÉ (Expressão) - Comprimento da Barra (m): 2.4; Custo da Barra: 0; Estimativa de Custo: 0
AC_Pset_RenovationAndPhasing - Renovation Status: Existing
BaseQuantities - Height: 2650 mm; FinishCeilingHeight: 2650 mm; FinishFloorHeight: 0 mm; ClearHeight: 2650 mm
ArchiCADQuantities - Altura: 2650 mm; Elevação à Origem do Projeto: 2650 mm; Elevação ao 1º Nível de Referência: 2650 mm; Elevação ao 2º Nível de Referência: 2650 mm; Elevação ao Nível do Mar: 2650 mm; Elevação ao Piso: 0 mm; Afastamento da Origem: 0 mm; Afastamento do Topo: 0 mm; Perímetro Furos da Planta: 0 mm; Elevação do Topo ao Primeiro Nível de Referência: 5300 mm; Elevação do Topo Ao Piso de Origem: 2650 mm; Elevação do Topo À Cota Zero: 5300 mm; Elevação do Topo Ao Nível do Mar: 5300 mm; Elevação do Topo Ao Segundo Nível de Referência: 5300 mm; Elevação da Base Ao Primeiro Nível de Referência: 2650 mm; Elevação da Base Ao Piso de Origem: 0 mm; Elevação da Base À Cota Zero: 2650 mm; Elevação da Base Ao Nível do Mar: 2650 mm; Elevação da Base Ao Segundo Nível de Referência: 2650 mm; Nível Base: 0 mm; Número de Pilares: 0; Número de Luminárias: 0; Número de Objetos: 0; Número de Janelas: 0; Área de Superfície das Janelas: 0 m2; Largura Janelas: 0 mm; Espessura de Pavimento: 0 mm; Redução de área: 1 m2; Extrair Área da Base do Pilar: 0 m2; Extrair Área da Trama: 0 m2; Área Baixa Extraída: 0 m2; Extrair Área da Base da Parede: 0 m2; Número dos Cantos Côncavos: 0; Número de Cantos: 4; Área Total Extraída: 0 m2; Inserção da Parede no Lado Posterior da Área de Superfície: 0 m2; Inserção da Parede no Lado da Área de Superfície: 0 m2; Inserção da Parede na Área da Superfície do Topo: 0 m2; Área Extraída da Parede Cortina: 0 m2
AC_Equantity_Selo_de_Zona_01_25 - Perímetro dos Vãos: 0 mm; Nível do Piso: 0 mm; Espessura do Subpiso: 0 mm; Altura: 2650 mm; Tamanho de Fonte para Texto de Detalhe (modelo): 300 mm
Name | LongName | Classification | Zona - Número de Azulejos Necessários | Quantidade de Barras | ID Dinâmico por Classificação | GrossFloorArea (m2) = NetFloorArea (m2) = SpaceNetFloorAreaBOMA (m2) = SpaceUsableFloorAreaBOMA (m2) = GrossCeilingArea (m2) = NetCeilingArea (m2) = Área (m2) = Área da Superfície do Topo (Líquida) (m2) = Área da Superfície da Base (Líquida) (m2) = Área Calculada (m2) = Área Medida (m2) = Área Líquida Medida (m2) = Área Reduzida (m2) | GrossWallArea (m2) | NetWallArea (m2) = Área de Superfície das Paredes (m2) | GrossPerimeter (mm) = NetPerimeter (mm) = Perímetro Útil da Zona (mm) = Perímetro Bruto Zona (mm) = Perímetro (mm) = Perímetro Útil (mm) | GrossVolume (m3) = NetVolume (m3) = Volume (Líquido) (m3) | Área da Superfície da Borda (Líquida) (m2) | Número de Vigas | Número de Portas | Número de Itens de Paredes | Área de Superfície das Portas (m2) | Largura Portas (mm) | Perímetro Paredes (mm) = Comprimento das Paredes Perímetro (mm) | Largura Combinada das Portas (mm) | Largura Combinada das Janelas (mm) | Estimativa de Rodapé (ml) (mm)
31 | QUARTO | Zoneamento (Classificação ARCHICAD); 4A 19 01 01 Dormitório (NBR 15965-6 4A) | 11010 | 4 | Zoneamento -009 | 7.12419 | 16.8871 | 16.8871 | 11010.2 | 18.8791 | 29.177 | 4 | 0 | 2 | 0 | 0 | 8850.18 | 0 | 2080 | 8850.18
27 | QUARTO | Zoneamento (Classificação ARCHICAD); 4A 19 01 01 Dormitório (NBR 15965-6 4A) | 10970 | 4 | Zoneamento -008 | 7.05588 | 16.8413 | 16.8413 | 10970.4 | 18.6981 | 29.0715 | 4 | 0 | 2 | 0 | 0 | 8830.36 | 0 | 2060 | 8830.36
17 | LAVANDERIA | Zoneamento (Classificação ARCHICAD); 4A 19 04 04 Lavanderia (NBR 15965-6 4A) | 5940 | 2 | Zoneamento -007 | 2.187 | 9.09455 | 9.09455 | 5940 | 5.79555 | 15.741 | 2 | 0 | 3 | 0 | 0 | 3510 | 0 | 0 | 3510
23 | QUARTO | Zoneamento (Classificação ARCHICAD); 4A 19 01 01 Dormitório (NBR 15965-6 4A) | 12311 | 5 | Zoneamento -012 | 9.38311 | 16.6677 | 16.6677 | 12310.4 | 24.8652 | 32.6227 | 3 | 0 | 2 | 0 | 0 | 11330.4 | 0 | 2780 | 11330.4
13 | WC | Zoneamento (Classificação ARCHICAD); 4A 19 04 07 Banheiro residencial (NBR 15965-6 4A) | 7150 | 3 | Zoneamento -011 | 3.4827 | 19.1359 | 17.6449 | 7859.56 | 9.22916 | 20.8278 | 3 | 1 | 4 | 1.491 | 710 | 7859.56 | 710 | 0 | 7149.56
09 | SALA | Zoneamento (Classificação ARCHICAD); 4A 19 01 07 Sala de Estar (NBR 15965-6 4A) | 15060 | 4 | Zoneamento -010 | 15.6592 | 23.4855 | 21.5955 | 15959.6 | 41.497 | 42.2928 | 5 | 1 | 5 | 1.89 | 900 | 9809.78 | 710 | 2040 | 8909.78
05 | COZINHA | Zoneamento (Classificação ARCHICAD); 4A 19 01 25 Cozinha (NBR 15965-6 4A) | 12370 | 4 | Zoneamento -006 | 9.17955 | 19.063 | 17.572 | 13079.6 | 24.3258 | 34.6608 | 5 | 1 | 3 | 1.491 | 710 | 9809.78 | 710 | 2040 | 9099.78

# IfcSpace: ÁREA PRIVATIVA APTO 09 (7)
In: Terceiro Pavimento
InteriorOrExteriorSpace: INTERNAL
Pset_SpaceCommon - Category: ÁREA PRIVATIVA APTO 09
ILUMINAÇÃO E VENTILAÇÃO (Expressão) - Área das Aberturas Projetada: 0; Atende: Atende; Não Atende: Não Atende
REVESTIMENTO DE PAREDE POR ZONA (Expressão) - Número de Linhas: 10; DImensão 1: 0 mm; Dimensão 2: 0 mm; Largura do Rejunte: 10 mm; Altura do Revestimento: 100 mm
RODAPÉ (Expressão) - Comprimento da Barra (m): 2.4; Custo da Barra: 0; Estimativa de Custo: 0
AC_Pset_RenovationAndPhasing - Renovation Status: Existing
BaseQuantities - Height: 2650 mm; FinishCeilingHeight: 2650 mm; FinishFloorHeight: 0 mm; ClearHeight: 2650 mm
ArchiCADQuantities - Altura: 2650 mm; Elevação à Origem do Projeto: 5300 mm; Elevação ao 1º Nível de Referência: 5300 mm; Elevação ao 2º Nível de Referência: 5300 mm; Elevação ao Nível do Mar: 5300 mm; Elevação ao Piso: 0 mm; Afastamento da Origem: 0 mm; Afastamento do Topo: 0 mm; Perímetro Furos da Planta: 0 mm; Elevação do Topo ao Primeiro Nível de Referência: 7950 mm; Elevação do Topo Ao Piso de Origem: 2650 mm; Elevação do Topo À Cota Zero: 7950 mm; Elevação do Topo Ao Nível do Mar: 7950 mm; Elevação do Topo Ao Segundo Nível de Referência: 7950 mm; Elevação da Base Ao Primeiro Nível de Referência: 5300 mm; Elevação da Base Ao Piso de Origem: 0 mm; Elevação da Base À Cota Zero: 5300 mm; Elevação da Base Ao Nível do Mar: 5300 mm; Elevação da Base Ao Segundo Nível de Referência: 5300 mm; Nível Base: 0 mm; Número de Pilares: 0; Número de Luminárias: 0; Número de Objetos: 0; Número de Janelas: 0; Área de Superfície das Janelas: 0 m2; Largura Janelas: 0 mm; Espessura de Pavimento: 0 mm; Redução de área: 1 m2; Extrair Área da Base do Pilar: 0 m2; Extrair Área da Trama: 0 m2; Área Baixa Extraída: 0 m2; Extrair Área da Base da Parede: 0 m2; Número dos Cantos Côncavos: 0; Número de Cantos: 4; Área Total Extraída: 0 m2; Inserção da Parede no Lado Posterior da Área de Superfície: 0 m2; Inserção da Parede no Lado da Área de Superfície: 0 m2; Inserção da Parede na Área da Superfície do Topo: 0 m2; Área Extraída da Parede Cortina: 0 m2
AC_Equantity_Selo_de_Zona_01_25 - Perímetro dos Vãos: 0 mm; Nível do Piso: 0 mm; Espessura do Subpiso: 0 mm; Altura: 2650 mm; Tamanho de Fonte para Texto de Detalhe (modelo): 300 mm
Name | LongName | Classification | Zona - Número de Azulejos Necessários | Quantidade de Barras | ID Dinâmico por Classificação | GrossFloorArea (m2) = NetFloorArea (m2) = SpaceNetFloorAreaBOMA (m2) = SpaceUsableFloorAreaBOMA (m2) = GrossCeilingArea (m2) = NetCeilingArea (m2) = Área (m2) = Área da Superfície do Topo (Líquida) (m2) = Área da Superfície da Base (Líquida) (m2) = Área Calculada (m2) = Área Medida (m2) = Área Líquida Medida (m2) = Área Reduzida (m2) | GrossWallArea (m2) | NetWallArea (m2) = Área de Superfície das Paredes (m2) | GrossPerimeter (mm) = NetPerimeter (mm) = Perímetro Útil da Zona (mm) = Perímetro Bruto Zona (mm) = Perímetro (mm) = Perímetro Útil (mm) | GrossVolume (m3) = NetVolume (m3) = Volume (Líquido) (m3) | Área da Superfície da Borda (Líquida) (m2) | Número de Vigas | Número de Portas | Número de Itens de Paredes | Área de Superfície das Portas (m2) | Largura Portas (mm) | Perímetro Paredes (mm) = Comprimento das Paredes Perímetro (mm) | Largura Combinada das Portas (mm) | Largura Combinada das Janelas (mm) | Estimativa de Rodapé (ml) (mm)
13 | WC | Zoneamento (Classificação ARCHICAD); 4A 19 04 07 Banheiro residencial (NBR 15965-6 4A) | 7150 | 3 | Zoneamento -059 | 3.4827 | 19.1359 | 17.6449 | 7859.56 | 9.22916 | 20.8278 | 3 | 1 | 4 | 1.491 | 710 | 7859.56 | 710 | 0 | 7149.56
31 | QUARTO | Zoneamento (Classificação ARCHICAD); 4A 19 01 01 Dormitório (NBR 15965-6 4A) | 11010 | 4 | Zoneamento -058 | 7.12419 | 16.794 | 16.794 | 11010.2 | 18.8791 | 29.177 | 4 | 0 | 2 | 0 | 0 | 8850.18 | 0 | 2080 | 8850.18
23 | QUARTO | Zoneamento (Classificação ARCHICAD); 4A 19 01 01 Dormitório (NBR 15965-6 4A) | 12311 | 5 | Zoneamento -061 | 9.38311 | 16.6677 | 16.6677 | 12310.4 | 24.8652 | 32.6227 | 3 | 0 | 2 | 0 | 0 | 11330.4 | 0 | 2780 | 11330.4
05 | COZINHA | Zoneamento (Classificação ARCHICAD); 4A 19 01 25 Cozinha (NBR 15965-6 4A) | 12370 | 4 | Zoneamento -062 | 9.17955 | 19.063 | 17.572 | 13079.6 | 24.3258 | 34.6608 | 5 | 1 | 3 | 1.491 | 710 | 9809.78 | 710 | 2040 | 9099.78
27 | QUARTO | Zoneamento (Classificação ARCHICAD); 4A 19 01 01 Dormitório (NBR 15965-6 4A) | 10970 | 4 | Zoneamento -057 | 7.05588 | 16.8413 | 16.8413 | 10970.4 | 18.6981 | 29.0715 | 4 | 0 | 2 | 0 | 0 | 8830.36 | 0 | 2060 | 8830.36
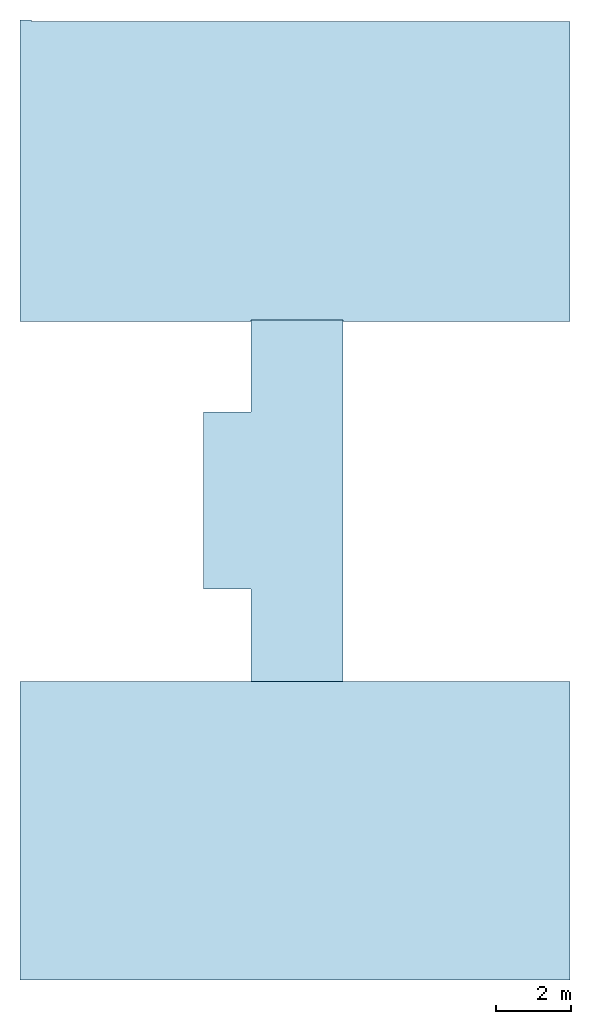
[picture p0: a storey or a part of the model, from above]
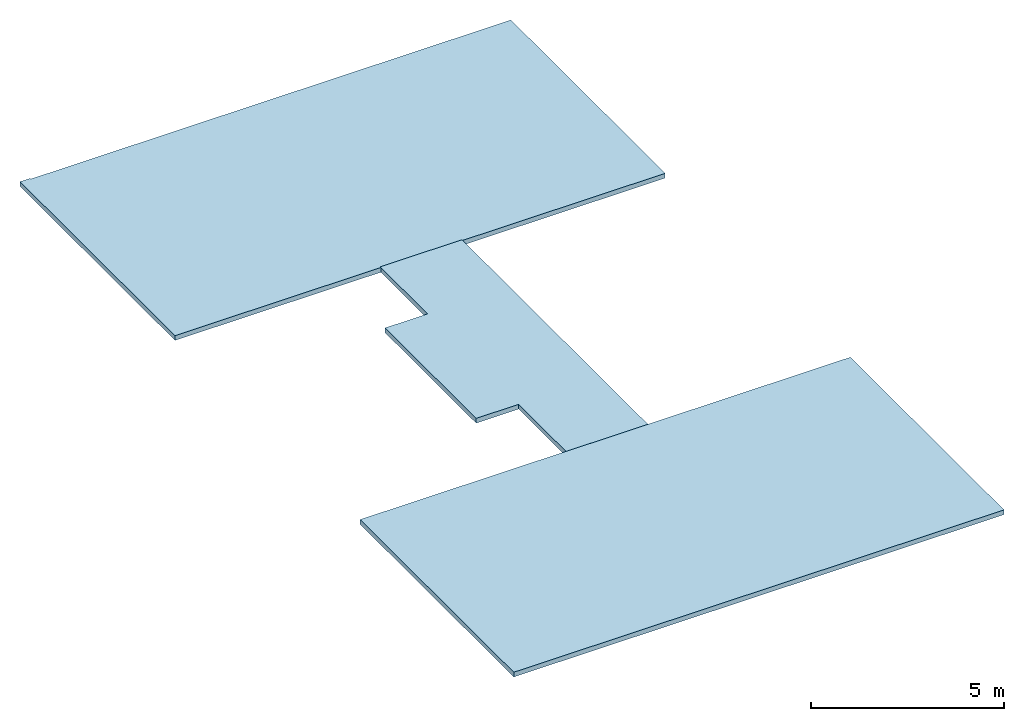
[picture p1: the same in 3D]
Properties of the parts of a building model (IFC2X3), part 2 of 7

# IfcSpace: ÁREA PRIVATIVA APTO 09 (7)
Name | LongName | Classification | Zona - Número de Azulejos Necessários | Quantidade de Barras | ID Dinâmico por Classificação | GrossFloorArea (m2) = NetFloorArea (m2) = SpaceNetFloorAreaBOMA (m2) = SpaceUsableFloorAreaBOMA (m2) = GrossCeilingArea (m2) = NetCeilingArea (m2) = Área (m2) = Área da Superfície do Topo (Líquida) (m2) = Área da Superfície da Base (Líquida) (m2) = Área Calculada (m2) = Área Medida (m2) = Área Líquida Medida (m2) = Área Reduzida (m2) | GrossWallArea (m2) | NetWallArea (m2) = Área de Superfície das Paredes (m2) | GrossPerimeter (mm) = NetPerimeter (mm) = Perímetro Útil da Zona (mm) = Perímetro Bruto Zona (mm) = Perímetro (mm) = Perímetro Útil (mm) | GrossVolume (m3) = NetVolume (m3) = Volume (Líquido) (m3) | Área da Superfície da Borda (Líquida) (m2) | Número de Vigas | Número de Portas | Número de Itens de Paredes | Área de Superfície das Portas (m2) | Largura Portas (mm) | Perímetro Paredes (mm) = Comprimento das Paredes Perímetro (mm) | Largura Combinada das Portas (mm) | Largura Combinada das Janelas (mm) | Estimativa de Rodapé (ml) (mm)
17 | LAVANDERIA | Zoneamento (Classificação ARCHICAD); 4A 19 04 04 Lavanderia (NBR 15965-6 4A) | 5940 | 2 | Zoneamento -056 | 2.187 | 9.09455 | 9.09455 | 5940 | 5.79555 | 15.741 | 2 | 0 | 3 | 0 | 0 | 3510 | 0 | 0 | 3510
09 | SALA | Zoneamento (Classificação ARCHICAD); 4A 19 01 07 Sala de Estar (NBR 15965-6 4A) | 15060 | 4 | Zoneamento -055 | 15.6592 | 23.3628 | 21.4728 | 15959.6 | 41.497 | 42.2928 | 5 | 1 | 5 | 1.89 | 900 | 9809.78 | 710 | 2040 | 8909.78

# IfcSpace: ÁREA PRIVATIVA APTO 10 (7)
In: Terceiro Pavimento
InteriorOrExteriorSpace: INTERNAL
Pset_SpaceCommon - Category: ÁREA PRIVATIVA APTO 10
ILUMINAÇÃO E VENTILAÇÃO (Expressão) - Área das Aberturas Projetada: 0; Atende: Atende; Não Atende: Não Atende
REVESTIMENTO DE PAREDE POR ZONA (Expressão) - Número de Linhas: 10; DImensão 1: 0 mm; Dimensão 2: 0 mm; Largura do Rejunte: 10 mm; Altura do Revestimento: 100 mm
RODAPÉ (Expressão) - Comprimento da Barra (m): 2.4; Custo da Barra: 0; Estimativa de Custo: 0
AC_Pset_RenovationAndPhasing - Renovation Status: Existing
BaseQuantities - Height: 2650 mm; FinishCeilingHeight: 2650 mm; FinishFloorHeight: 0 mm; ClearHeight: 2650 mm
ArchiCADQuantities - Altura: 2650 mm; Elevação à Origem do Projeto: 5300 mm; Elevação ao 1º Nível de Referência: 5300 mm; Elevação ao 2º Nível de Referência: 5300 mm; Elevação ao Nível do Mar: 5300 mm; Elevação ao Piso: 0 mm; Afastamento da Origem: 0 mm; Afastamento do Topo: 0 mm; Perímetro Furos da Planta: 0 mm; Elevação do Topo ao Primeiro Nível de Referência: 7950 mm; Elevação do Topo Ao Piso de Origem: 2650 mm; Elevação do Topo À Cota Zero: 7950 mm; Elevação do Topo Ao Nível do Mar: 7950 mm; Elevação do Topo Ao Segundo Nível de Referência: 7950 mm; Elevação da Base Ao Primeiro Nível de Referência: 5300 mm; Elevação da Base Ao Piso de Origem: 0 mm; Elevação da Base À Cota Zero: 5300 mm; Elevação da Base Ao Nível do Mar: 5300 mm; Elevação da Base Ao Segundo Nível de Referência: 5300 mm; Nível Base: 0 mm; Número de Pilares: 0; Número de Luminárias: 0; Número de Objetos: 0; Número de Janelas: 0; Área de Superfície das Janelas: 0 m2; Largura Janelas: 0 mm; Espessura de Pavimento: 0 mm; Redução de área: 1 m2; Extrair Área da Base do Pilar: 0 m2; Extrair Área da Trama: 0 m2; Área Baixa Extraída: 0 m2; Extrair Área da Base da Parede: 0 m2; Número dos Cantos Côncavos: 0; Número de Cantos: 4; Área Total Extraída: 0 m2; Inserção da Parede no Lado Posterior da Área de Superfície: 0 m2; Inserção da Parede no Lado da Área de Superfície: 0 m2; Inserção da Parede na Área da Superfície do Topo: 0 m2; Área Extraída da Parede Cortina: 0 m2
AC_Equantity_Selo_de_Zona_01_25 - Perímetro dos Vãos: 0 mm; Nível do Piso: 0 mm; Espessura do Subpiso: 0 mm; Altura: 2650 mm; Tamanho de Fonte para Texto de Detalhe (modelo): 300 mm
Name | LongName | Classification | Zona - Número de Azulejos Necessários | Quantidade de Barras | ID Dinâmico por Classificação | GrossFloorArea (m2) = NetFloorArea (m2) = SpaceNetFloorAreaBOMA (m2) = SpaceUsableFloorAreaBOMA (m2) = GrossCeilingArea (m2) = NetCeilingArea (m2) = Área (m2) = Área da Superfície do Topo (Líquida) (m2) = Área da Superfície da Base (Líquida) (m2) = Área Calculada (m2) = Área Medida (m2) = Área Líquida Medida (m2) = Área Reduzida (m2) | GrossWallArea (m2) | NetWallArea (m2) = Área de Superfície das Paredes (m2) | GrossPerimeter (mm) = NetPerimeter (mm) = Perímetro Útil da Zona (mm) = Perímetro Bruto Zona (mm) = Perímetro (mm) = Perímetro Útil (mm) | GrossVolume (m3) = NetVolume (m3) = Volume (Líquido) (m3) | Área da Superfície da Borda (Líquida) (m2) | Número de Vigas | Número de Portas | Número de Itens de Paredes | Área de Superfície das Portas (m2) | Largura Portas (mm) | Perímetro Paredes (mm) = Comprimento das Paredes Perímetro (mm) | Largura Combinada das Portas (mm) | Largura Combinada das Janelas (mm) | Estimativa de Rodapé (ml) (mm)
31 | QUARTO | Zoneamento (Classificação ARCHICAD); 4A 19 01 01 Dormitório (NBR 15965-6 4A) | 11010 | 4 | Zoneamento -064 | 7.12419 | 16.794 | 16.794 | 11010.2 | 18.8791 | 29.177 | 4 | 0 | 2 | 0 | 0 | 8850.18 | 0 | 2080 | 8850.18
13 | WC | Zoneamento (Classificação ARCHICAD); 4A 19 04 07 Banheiro residencial (NBR 15965-6 4A) | 7150 | 3 | Zoneamento -063 | 3.4827 | 19.1359 | 17.6449 | 7859.56 | 9.22916 | 20.8278 | 3 | 1 | 4 | 1.491 | 710 | 7859.56 | 710 | 0 | 7149.56
09 | SALA | Zoneamento (Classificação ARCHICAD); 4A 19 01 07 Sala de Estar (NBR 15965-6 4A) | 15060 | 4 | Zoneamento -049 | 15.6592 | 23.3628 | 21.4728 | 15959.6 | 41.497 | 42.2928 | 5 | 1 | 5 | 1.89 | 900 | 9809.78 | 710 | 2040 | 8909.78
17 | LAVANDERIA | Zoneamento (Classificação ARCHICAD); 4A 19 04 04 Lavanderia (NBR 15965-6 4A) | 5940 | 2 | Zoneamento -048 | 2.187 | 9.09455 | 9.09455 | 5940 | 5.79555 | 15.741 | 2 | 0 | 3 | 0 | 0 | 3510 | 0 | 0 | 3510
05 | COZINHA | Zoneamento (Classificação ARCHICAD); 4A 19 01 25 Cozinha (NBR 15965-6 4A) | 12370 | 4 | Zoneamento -047 | 9.17955 | 19.063 | 17.572 | 13079.6 | 24.3258 | 34.6608 | 5 | 1 | 3 | 1.491 | 710 | 9809.78 | 710 | 2040 | 9099.78
27 | QUARTO | Zoneamento (Classificação ARCHICAD); 4A 19 01 01 Dormitório (NBR 15965-6 4A) | 10970 | 4 | Zoneamento -046 | 7.05588 | 16.8413 | 16.8413 | 10970.4 | 18.6981 | 29.0715 | 4 | 0 | 2 | 0 | 0 | 8830.36 | 0 | 2060 | 8830.36
23 | QUARTO | Zoneamento (Classificação ARCHICAD); 4A 19 01 01 Dormitório (NBR 15965-6 4A) | 12311 | 5 | Zoneamento -045 | 9.38311 | 16.6677 | 16.6677 | 12310.4 | 24.8652 | 32.6227 | 3 | 0 | 2 | 0 | 0 | 11330.4 | 0 | 2780 | 11330.4

# IfcSpace: ÁREA PRIVATIVA APTO 11 (7)
In: Terceiro Pavimento
InteriorOrExteriorSpace: INTERNAL
Pset_SpaceCommon - Category: ÁREA PRIVATIVA APTO 11
ILUMINAÇÃO E VENTILAÇÃO (Expressão) - Área das Aberturas Projetada: 0; Atende: Atende; Não Atende: Não Atende
REVESTIMENTO DE PAREDE POR ZONA (Expressão) - Número de Linhas: 10; DImensão 1: 0 mm; Dimensão 2: 0 mm; Largura do Rejunte: 10 mm; Altura do Revestimento: 100 mm
RODAPÉ (Expressão) - Comprimento da Barra (m): 2.4; Custo da Barra: 0; Estimativa de Custo: 0
AC_Pset_RenovationAndPhasing - Renovation Status: Existing
BaseQuantities - Height: 2650 mm; FinishCeilingHeight: 2650 mm; FinishFloorHeight: 0 mm; ClearHeight: 2650 mm
ArchiCADQuantities - Altura: 2650 mm; Elevação à Origem do Projeto: 5300 mm; Elevação ao 1º Nível de Referência: 5300 mm; Elevação ao 2º Nível de Referência: 5300 mm; Elevação ao Nível do Mar: 5300 mm; Elevação ao Piso: 0 mm; Afastamento da Origem: 0 mm; Afastamento do Topo: 0 mm; Perímetro Furos da Planta: 0 mm; Elevação do Topo ao Primeiro Nível de Referência: 7950 mm; Elevação do Topo Ao Piso de Origem: 2650 mm; Elevação do Topo À Cota Zero: 7950 mm; Elevação do Topo Ao Nível do Mar: 7950 mm; Elevação do Topo Ao Segundo Nível de Referência: 7950 mm; Elevação da Base Ao Primeiro Nível de Referência: 5300 mm; Elevação da Base Ao Piso de Origem: 0 mm; Elevação da Base À Cota Zero: 5300 mm; Elevação da Base Ao Nível do Mar: 5300 mm; Elevação da Base Ao Segundo Nível de Referência: 5300 mm; Nível Base: 0 mm; Número de Pilares: 0; Número de Luminárias: 0; Número de Objetos: 0; Número de Janelas: 0; Área de Superfície das Janelas: 0 m2; Largura Janelas: 0 mm; Espessura de Pavimento: 0 mm; Redução de área: 1 m2; Extrair Área da Base do Pilar: 0 m2; Extrair Área da Trama: 0 m2; Área Baixa Extraída: 0 m2; Extrair Área da Base da Parede: 0 m2; Número dos Cantos Côncavos: 0; Número de Cantos: 4; Área Total Extraída: 0 m2; Inserção da Parede no Lado Posterior da Área de Superfície: 0 m2; Inserção da Parede no Lado da Área de Superfície: 0 m2; Inserção da Parede na Área da Superfície do Topo: 0 m2; Área Extraída da Parede Cortina: 0 m2
AC_Equantity_Selo_de_Zona_01_25 - Perímetro dos Vãos: 0 mm; Nível do Piso: 0 mm; Espessura do Subpiso: 0 mm; Altura: 2650 mm; Tamanho de Fonte para Texto de Detalhe (modelo): 300 mm
Name | LongName | Classification | Zona - Número de Azulejos Necessários | Quantidade de Barras | ID Dinâmico por Classificação | GrossFloorArea (m2) = NetFloorArea (m2) = SpaceNetFloorAreaBOMA (m2) = SpaceUsableFloorAreaBOMA (m2) = GrossCeilingArea (m2) = NetCeilingArea (m2) = Área (m2) = Área da Superfície do Topo (Líquida) (m2) = Área da Superfície da Base (Líquida) (m2) = Área Calculada (m2) = Área Medida (m2) = Área Líquida Medida (m2) = Área Reduzida (m2) | GrossWallArea (m2) | NetWallArea (m2) = Área de Superfície das Paredes (m2) | GrossPerimeter (mm) = NetPerimeter (mm) = Perímetro Útil da Zona (mm) = Perímetro Bruto Zona (mm) = Perímetro (mm) = Perímetro Útil (mm) | GrossVolume (m3) = NetVolume (m3) = Volume (Líquido) (m3) | Área da Superfície da Borda (Líquida) (m2) | Número de Vigas | Número de Portas | Número de Itens de Paredes | Área de Superfície das Portas (m2) | Largura Portas (mm) | Perímetro Paredes (mm) = Comprimento das Paredes Perímetro (mm) | Largura Combinada das Portas (mm) | Largura Combinada das Janelas (mm) | Estimativa de Rodapé (ml) (mm)
27 | QUARTO | Zoneamento (Classificação ARCHICAD); 4A 19 01 01 Dormitório (NBR 15965-6 4A) | 10970 | 4 | Zoneamento -053 | 7.05588 | 16.8415 | 16.8415 | 10970.4 | 18.6981 | 29.0715 | 4 | 0 | 2 | 0 | 0 | 8830.36 | 0 | 2060 | 8830.36
17 | LAVANDERIA | Zoneamento (Classificação ARCHICAD); 4A 19 04 04 Lavanderia (NBR 15965-6 4A) | 5940 | 2 | Zoneamento -065 | 2.187 | 9.09455 | 9.09455 | 5940 | 5.79555 | 15.741 | 2 | 0 | 3 | 0 | 0 | 3510 | 0 | 0 | 3510
05 | COZINHA | Zoneamento (Classificação ARCHICAD); 4A 19 01 25 Cozinha (NBR 15965-6 4A) | 12370 | 4 | Zoneamento -054 | 9.17955 | 19.063 | 17.572 | 13079.6 | 24.3258 | 34.6608 | 5 | 1 | 3 | 1.491 | 710 | 9809.78 | 710 | 2040 | 9099.78
31 | QUARTO | Zoneamento (Classificação ARCHICAD); 4A 19 01 01 Dormitório (NBR 15965-6 4A) | 11010 | 4 | Zoneamento -052 | 7.12419 | 16.8872 | 16.8872 | 11010.2 | 18.8791 | 29.177 | 4 | 0 | 2 | 0 | 0 | 8850.18 | 0 | 2080 | 8850.18
13 | WC | Zoneamento (Classificação ARCHICAD); 4A 19 04 07 Banheiro residencial (NBR 15965-6 4A) | 7150 | 3 | Zoneamento -051 | 3.4827 | 19.1359 | 17.6449 | 7859.56 | 9.22916 | 20.8278 | 3 | 1 | 4 | 1.491 | 710 | 7859.56 | 710 | 0 | 7149.56
23 | QUARTO | Zoneamento (Classificação ARCHICAD); 4A 19 01 01 Dormitório (NBR 15965-6 4A) | 12311 | 5 | Zoneamento -050 | 9.38311 | 16.6678 | 16.6678 | 12310.4 | 24.8652 | 32.6227 | 3 | 0 | 2 | 0 | 0 | 11330.4 | 0 | 2780 | 11330.4
09 | SALA | Zoneamento (Classificação ARCHICAD); 4A 19 01 07 Sala de Estar (NBR 15965-6 4A) | 15060 | 4 | Zoneamento -044 | 15.6592 | 23.4855 | 21.5955 | 15959.6 | 41.497 | 42.2928 | 5 | 1 | 5 | 1.89 | 900 | 9809.78 | 710 | 2040 | 8909.78

# IfcSpace: ÁREA PRIVATIVA APTO 12 (7)
In: Terceiro Pavimento
InteriorOrExteriorSpace: INTERNAL
Pset_SpaceCommon - Category: ÁREA PRIVATIVA APTO 12
ILUMINAÇÃO E VENTILAÇÃO (Expressão) - Área das Aberturas Projetada: 0; Atende: Atende; Não Atende: Não Atende
REVESTIMENTO DE PAREDE POR ZONA (Expressão) - Número de Linhas: 10; DImensão 1: 0 mm; Dimensão 2: 0 mm; Largura do Rejunte: 10 mm; Altura do Revestimento: 100 mm
RODAPÉ (Expressão) - Comprimento da Barra (m): 2.4; Custo da Barra: 0; Estimativa de Custo: 0
AC_Pset_RenovationAndPhasing - Renovation Status: Existing
BaseQuantities - Height: 2650 mm; FinishCeilingHeight: 2650 mm; FinishFloorHeight: 0 mm; ClearHeight: 2650 mm
ArchiCADQuantities - Altura: 2650 mm; Elevação à Origem do Projeto: 5300 mm; Elevação ao 1º Nível de Referência: 5300 mm; Elevação ao 2º Nível de Referência: 5300 mm; Elevação ao Nível do Mar: 5300 mm; Elevação ao Piso: 0 mm; Afastamento da Origem: 0 mm; Afastamento do Topo: 0 mm; Perímetro Furos da Planta: 0 mm; Elevação do Topo ao Primeiro Nível de Referência: 7950 mm; Elevação do Topo Ao Piso de Origem: 2650 mm; Elevação do Topo À Cota Zero: 7950 mm; Elevação do Topo Ao Nível do Mar: 7950 mm; Elevação do Topo Ao Segundo Nível de Referência: 7950 mm; Elevação da Base Ao Primeiro Nível de Referência: 5300 mm; Elevação da Base Ao Piso de Origem: 0 mm; Elevação da Base À Cota Zero: 5300 mm; Elevação da Base Ao Nível do Mar: 5300 mm; Elevação da Base Ao Segundo Nível de Referência: 5300 mm; Nível Base: 0 mm; Número de Pilares: 0; Número de Luminárias: 0; Número de Objetos: 0; Número de Janelas: 0; Área de Superfície das Janelas: 0 m2; Largura Janelas: 0 mm; Espessura de Pavimento: 0 mm; Redução de área: 1 m2; Extrair Área da Base do Pilar: 0 m2; Extrair Área da Trama: 0 m2; Área Baixa Extraída: 0 m2; Extrair Área da Base da Parede: 0 m2; Número dos Cantos Côncavos: 0; Número de Cantos: 4; Área Total Extraída: 0 m2; Inserção da Parede no Lado Posterior da Área de Superfície: 0 m2; Inserção da Parede no Lado da Área de Superfície: 0 m2; Inserção da Parede na Área da Superfície do Topo: 0 m2; Área Extraída da Parede Cortina: 0 m2
AC_Equantity_Selo_de_Zona_01_25 - Perímetro dos Vãos: 0 mm; Nível do Piso: 0 mm; Espessura do Subpiso: 0 mm; Altura: 2650 mm; Tamanho de Fonte para Texto de Detalhe (modelo): 300 mm
Name | LongName | Classification | Zona - Número de Azulejos Necessários | Quantidade de Barras | ID Dinâmico por Classificação | GrossFloorArea (m2) = NetFloorArea (m2) = SpaceNetFloorAreaBOMA (m2) = SpaceUsableFloorAreaBOMA (m2) = GrossCeilingArea (m2) = NetCeilingArea (m2) = Área (m2) = Área da Superfície do Topo (Líquida) (m2) = Área da Superfície da Base (Líquida) (m2) = Área Calculada (m2) = Área Medida (m2) = Área Líquida Medida (m2) = Área Reduzida (m2) | GrossWallArea (m2) | NetWallArea (m2) = Área de Superfície das Paredes (m2) | GrossPerimeter (mm) = NetPerimeter (mm) = Perímetro Útil da Zona (mm) = Perímetro Bruto Zona (mm) = Perímetro (mm) = Perímetro Útil (mm) | GrossVolume (m3) = NetVolume (m3) = Volume (Líquido) (m3) | Área da Superfície da Borda (Líquida) (m2) | Número de Vigas | Número de Portas | Número de Itens de Paredes | Área de Superfície das Portas (m2) | Largura Portas (mm) | Perímetro Paredes (mm) = Comprimento das Paredes Perímetro (mm) | Largura Combinada das Portas (mm) | Largura Combinada das Janelas (mm) | Estimativa de Rodapé (ml) (mm)
23 | QUARTO | Zoneamento (Classificação ARCHICAD); 4A 19 01 01 Dormitório (NBR 15965-6 4A) | 12311 | 5 | Zoneamento -043 | 9.38311 | 16.6677 | 16.6677 | 12310.4 | 24.8652 | 32.6227 | 3 | 0 | 2 | 0 | 0 | 11330.4 | 0 | 2780 | 11330.4
13 | WC | Zoneamento (Classificação ARCHICAD); 4A 19 04 07 Banheiro residencial (NBR 15965-6 4A) | 7150 | 3 | Zoneamento -042 | 3.4827 | 19.1359 | 17.6449 | 7859.56 | 9.22916 | 20.8278 | 3 | 1 | 4 | 1.491 | 710 | 7859.56 | 710 | 0 | 7149.56
09 | SALA | Zoneamento (Classificação ARCHICAD); 4A 19 01 07 Sala de Estar (NBR 15965-6 4A) | 15060 | 4 | Zoneamento -040 | 15.6592 | 23.4855 | 21.5955 | 15959.6 | 41.497 | 42.2928 | 5 | 1 | 5 | 1.89 | 900 | 9809.78 | 710 | 2040 | 8909.78
31 | QUARTO | Zoneamento (Classificação ARCHICAD); 4A 19 01 01 Dormitório (NBR 15965-6 4A) | 11010 | 4 | Zoneamento -039 | 7.12419 | 16.8871 | 16.8871 | 11010.2 | 18.8791 | 29.177 | 4 | 0 | 2 | 0 | 0 | 8850.18 | 0 | 2080 | 8850.18
27 | QUARTO | Zoneamento (Classificação ARCHICAD); 4A 19 01 01 Dormitório (NBR 15965-6 4A) | 10970 | 4 | Zoneamento -038 | 7.05588 | 16.8413 | 16.8413 | 10970.4 | 18.6981 | 29.0715 | 4 | 0 | 2 | 0 | 0 | 8830.36 | 0 | 2060 | 8830.36
17 | LAVANDERIA | Zoneamento (Classificação ARCHICAD); 4A 19 04 04 Lavanderia (NBR 15965-6 4A) | 5940 | 2 | Zoneamento -037 | 2.187 | 9.09455 | 9.09455 | 5940 | 5.79555 | 15.741 | 2 | 0 | 3 | 0 | 0 | 3510 | 0 | 0 | 3510
05 | COZINHA | Zoneamento (Classificação ARCHICAD); 4A 19 01 25 Cozinha (NBR 15965-6 4A) | 12370 | 4 | Zoneamento -036 | 9.17955 | 19.063 | 17.572 | 13079.6 | 24.3258 | 34.6608 | 5 | 1 | 3 | 1.491 | 710 | 9809.78 | 710 | 2040 | 9099.78

# IfcBeam: Concreto Armado Moldado in Loco - Estrutural 150 x 300 (22)
Classification: Viga (Classificação ARCHICAD); 3E 12 06 02 00 Viga (NBR 15965-5 3E); Material: Concreto Armado Moldado in Loco - Estrutural
ESTRUTURA (Expressão) - Custo por Volume (m3): 0; Estimativa de Custo Total por Volume: 0; Estimativa de Custo Total por Volume (R$): 0,00 R$
SUPERFÍCIES (Mapas) - Superfície do Topo (Geral): Concreto - 03; Superfície da Base (Geral): Concreto - 03
AC_Pset_RenovationAndPhasing - Renovation Status: Existing
Pset_BeamCommon - LoadBearing: yes; Reference: Concreto Armado Moldado in Loco - Estrutural 150 x 300
Component Properties - Concreto Armado Moldado in Loco - Estrutural, Tipo de Componente: Núcleo
BaseQuantities - Width: 150 mm; Depth: 300 mm; CrossSectionArea: 0.045 m2
ArchiCADQuantities - Altura: 300 mm; Largura: 150 mm; Elevação ao Piso: 2500 mm; Afastamento da Origem: 2500 mm; Elevação do Topo Ao Piso de Origem: 2500 mm; Elevação da Base Ao Piso de Origem: 2200 mm; Altura do Corte Transversal no Topo/Terminação (perpendicular): 300 mm; Altura do Corte Transversal na Base/Início (perpendicular): 300 mm; Largura do Corte Transversal no Topo/Terminação (perpendicular): 150 mm; Largura do Corte Transversal na Base/Início (perpendicular): 150 mm; Altura do Corte Transversal no Topo/Terminação (corte): 300 mm; Altura do Corte Transversal na Base/Início (corte): 300 mm; Largura do Corte Transversal no Topo/Terminação (corte): 150 mm; Largura do Corte Transversal na Base/Início (corte): 150 mm; Número de Segmentos: 1; Número Furo: 0; Área da Borda do Furo: 0 m2; Área de Superfície dos Furos: 0 m2; Volume Furos: 0 m3; Afastamento Eixo a partir do Centro: 0 mm
Component Quantities - Concreto Armado Moldado in Loco - Estrutural, Espessura do Componente: 150 mm; Concreto Armado Moldado in Loco - Estrutural, Altura do Componente Retangular: 300 mm; Concreto Armado Moldado in Loco - Estrutural, Largura do Componente Retangular: 150 mm; Concreto Armado Moldado in Loco - Estrutural, Área de Seção Transversal do Componente: 0.045 m2
Name | In | ID Dinâmico por Classificação | IsExternal | Concreto Armado Moldado in Loco - Estrutural, Carbono Incorporado | Concreto Armado Moldado in Loco - Estrutural, Energia Incorporada (MJ) | NetSurfaceAreaExtrudedSides (m2) = OuterSurfaceArea (m2) | Length (mm) = Comprimento 3D (mm) | TotalSurfaceArea (m2) = GrossSurfaceArea (m2) = NetSurfaceArea (m2) | GrossVolume (m3) = Volume (Bruto) (m3) | NetVolume (m3) = Volume (Líquido) (m3) = Volume (Condicional) (m3) = Concreto Armado Moldado in Loco - Estrutural, Volume Componente (Líquido) (m3) = Concreto Armado Moldado in Loco - Estrutural, Volume do componente (Bruto) (m3) = Concreto Armado Moldado in Loco - Estrutural, Volume Componente (Condicional) (m3) | Área (m2) = Área da Superfície do Topo (Líquida) (m2) = Área da Superfície da Base (Líquida) (m2) = Área da Superfície do Topo (Geral) (m2) = Área da Superfície da Base (Geral) (m2) | Elevação à Origem do Projeto (mm) = Elevação ao 1º Nível de Referência (mm) = Elevação ao 2º Nível de Referência (mm) = Elevação ao Nível do Mar (mm) = Elevação do Topo ao Primeiro Nível de Referência (mm) = Elevação do Topo À Cota Zero (mm) = Elevação do Topo Ao Nível do Mar (mm) = Elevação do Topo Ao Segundo Nível de Referência (mm) | Área da Superfície (m2) | Elevação da Base Ao Primeiro Nível de Referência (mm) = Elevação da Base À Cota Zero (mm) = Elevação da Base Ao Nível do Mar (mm) = Elevação da Base Ao Segundo Nível de Referência (mm) | Área do Corte Transversal na Base/Início (m2) | Altura do Corte Transversal no Topo/Terminação (m2) | Área da Superfície das Extremidades da Viga (m2) | Área da Superfície do Lado Esquerdo da Viga (Líquida) (m2) | Comprimento Esquerda (mm) | Comprimento Direita (mm) | Área da Superfície do Lado Direito da Viga (Líquida) (m2) | Concreto Armado Moldado in Loco - Estrutural, Massa (kg) | Concreto Armado Moldado in Loco - Estrutural, Área de Componente Projetada (Líquida) (m2) = Concreto Armado Moldado in Loco - Estrutural, Área de Componente Projetada (Bruta) (m2)
VIGA-036 | Pavimento Terreo | Viga -036 | yes | 174.719 (kgCO₂) | 1682.21 | 6.01648 | 6729.98 | 6.10648 | 0.354824 | 0.300824 | 1.00275 | -150 | 6.29396 | -450 | 0.0524786 | 0.045 | 0.0974786 | 2.01899 | 7929.98 | 7839.98 | 1.99199 | 721.978 | 2.01899
VIGA-033 | Pavimento Terreo | Viga -033 | yes | 175.633 (kgCO₂) | 1691.02 | 6.04798 | 6764.98 | 6.13798 | 0.356399 | 0.302399 | 1.008 | -150 | 6.32546 | -450 | 0.045 | 0.0524786 | 0.0974786 | 2.02949 | 7964.98 | 7874.98 | 2.00249 | 725.758 | 2.02949
VIGA-032 | Pavimento Terreo | Viga -032 | yes | 174.457 (kgCO₂) | 1679.69 | 6.00748 | 6674.98 | 6.09748 | 0.358424 | 0.300374 | 1.00125 | -150 | 6.27748 | -450 | 0.045 | 0 | 0.045 | 2.00249 | 7874.98 | 7874.98 | 2.00249 | 720.898 | 2.00249
VIGA-031 | Pavimento Terreo | Viga -031 | yes | 177.725 (kgCO₂) | 1711.15 | 6.12 | 6800 | 6.21 | 0.36 | 0.306 | 1.02 | -150 | 6.39 | -450 | 0.045 | 0.045 | 0.09 | 2.04 | 8000 | 8000 | 2.04 | 734.4 | 2.04
VIGA-035 | Pavimento Terreo | Viga -035 | yes | 173.542 (kgCO₂) | 1670.88 | 5.97598 | 6639.98 | 6.06598 | 0.356849 | 0.298799 | 0.995997 | -150 | 6.24598 | -450 | 0 | 0.045 | 0.045 | 1.99199 | 7839.98 | 7839.98 | 1.99199 | 717.118 | 1.99199
VIGA-034 | Pavimento Terreo | Viga -034 | yes | 173.542 (kgCO₂) | 1670.88 | 5.97598 | 6639.98 | 6.06598 | 0.356849 | 0.298799 | 0.995997 | -150 | 6.24598 | -450 | 0 | 0.045 | 0.045 | 1.99199 | 7839.98 | 7839.98 | 1.99199 | 717.118 | 1.99199
APTO4-VIGA-009 | Primeiro Pavimento | Viga -009 | yes | 174.719 (kgCO₂) | 1682.21 | 6.01648 | 6729.98 | 6.10648 | 0.356849 | 0.300824 | 1.00275 | 2500 | 6.31348 | 2200 | 0.0225 | 0.045 | 0.0675 | 1.99199 | 7929.98 | 7929.98 | 2.01899 | 721.978 | 2.01899
APTO2-VIGA-009 | Primeiro Pavimento | Viga -009 | yes | 174.719 (kgCO₂) | 1682.21 | 6.01648 | 6729.98 | 6.10648 | 0.356849 | 0.300824 | 1.00275 | 2500 | 6.31348 | 2200 | 0.0225 | 0.045 | 0.0675 | 2.01899 | 7929.98 | 7929.98 | 1.99199 | 721.978 | 2.01899
APTO3-VIGA-009 | Primeiro Pavimento | Viga -009 | yes | 174.719 (kgCO₂) | 1682.21 | 6.01648 | 6729.98 | 6.10648 | 0.356849 | 0.300824 | 1.00275 | 2500 | 6.31348 | 2200 | 0.0225 | 0.045 | 0.0675 | 2.01899 | 7929.98 | 7929.98 | 1.99199 | 721.978 | 2.01899
APTO1-VIGA-009 | Primeiro Pavimento | Viga -009 | yes | 174.719 (kgCO₂) | 1682.21 | 6.01648 | 6729.98 | 6.10648 | 0.356849 | 0.300824 | 1.00275 | 2500 | 6.31348 | 2200 | 0.0225 | 0.045 | 0.0675 | 1.99199 | 7929.98 | 7929.98 | 2.01899 | 721.978 | 2.01899
CIRC1-VIGA-012 | Primeiro Pavimento | Viga -012 | no | 174.719 (kgCO₂) | 1682.21 | 6.01648 | 6729.98 | 6.10648 | 0.356849 | 0.300824 | 1.00275 | 2500 | 6.31348 | 2200 | 0.0225 | 0.045 | 0.0675 | 1.99199 | 7929.98 | 7929.98 | 2.01899 | 721.978 | 2.01899
VIGA-037 | Primeiro Pavimento | Viga -037 | no | 156.685 (kgCO₂) | 1508.58 | 5.3955 | 5995 | 5.4855 | 0.352125 | 0.269775 | 0.89925 | 2500 | 6.2055 | 2200 | 0 | 0.045 | 0.045 | 1.7985 | 7825 | 7825 | 1.7985 | 647.46 | 1.7985
APTO5-VIGA-009 | Segundo Pavimento | Viga -009 | yes | 174.719 (kgCO₂) | 1682.21 | 6.01648 | 6729.98 | 6.10648 | 0.356849 | 0.300824 | 1.00275 | 5150 | 6.31348 | 4850 | 0.0225 | 0.045 | 0.0675 | 1.99199 | 7929.98 | 7929.98 | 2.01899 | 721.978 | 2.01899
APTO6-VIGA-009 | Segundo Pavimento | Viga -009 | yes | 174.719 (kgCO₂) | 1682.21 | 6.01648 | 6729.98 | 6.10648 | 0.356849 | 0.300824 | 1.00275 | 5150 | 6.31348 | 4850 | 0.0225 | 0.045 | 0.0675 | 2.01899 | 7929.98 | 7929.98 | 1.99199 | 721.978 | 2.01899
APTO7-VIGA-009 | Segundo Pavimento | Viga -009 | yes | 174.719 (kgCO₂) | 1682.21 | 6.01648 | 6729.98 | 6.10648 | 0.356849 | 0.300824 | 1.00275 | 5150 | 6.31348 | 4850 | 0.0225 | 0.045 | 0.0675 | 2.01899 | 7929.98 | 7929.98 | 1.99199 | 721.978 | 2.01899
APTO8-VIGA-009 | Segundo Pavimento | Viga -009 | yes | 174.719 (kgCO₂) | 1682.21 | 6.01648 | 6729.98 | 6.10648 | 0.356849 | 0.300824 | 1.00275 | 5150 | 6.31348 | 4850 | 0.0225 | 0.045 | 0.0675 | 1.99199 | 7929.98 | 7929.98 | 2.01899 | 721.978 | 2.01899
CIRC2-VIGA-012 | Segundo Pavimento | Viga -012 | no | 174.719 (kgCO₂) | 1682.21 | 6.01648 | 6729.98 | 6.10648 | 0.356849 | 0.300824 | 1.00275 | 5150 | 6.31348 | 4850 | 0.0225 | 0.045 | 0.0675 | 1.99199 | 7929.98 | 7929.98 | 2.01899 | 721.978 | 2.01899
CIRC3-VIGA-012 | Terceiro Pavimento | Viga -012 | no | 174.719 (kgCO₂) | 1682.21 | 6.01648 | 6729.98 | 6.10648 | 0.356849 | 0.300824 | 1.00275 | 7800 | 6.31348 | 7500 | 0.0225 | 0.045 | 0.0675 | 1.99199 | 7929.98 | 7929.98 | 2.01899 | 721.978 | 2.01899
APTO9-VIGA-009 | Terceiro Pavimento | Viga -009 | yes | 174.719 (kgCO₂) | 1682.21 | 6.01648 | 6729.98 | 6.10648 | 0.356849 | 0.300824 | 1.00275 | 7800 | 6.31348 | 7500 | 0.0225 | 0.045 | 0.0675 | 1.99199 | 7929.98 | 7929.98 | 2.01899 | 721.978 | 2.01899
APTO10-VIGA-009 | Terceiro Pavimento | Viga -009 | yes | 174.719 (kgCO₂) | 1682.21 | 6.01648 | 6729.98 | 6.10648 | 0.356849 | 0.300824 | 1.00275 | 7800 | 6.31348 | 7500 | 0.0225 | 0.045 | 0.0675 | 2.01899 | 7929.98 | 7929.98 | 1.99199 | 721.978 | 2.01899
APTO11-VIGA-009 | Terceiro Pavimento | Viga -009 | yes | 174.719 (kgCO₂) | 1682.21 | 6.01648 | 6729.98 | 6.10648 | 0.356849 | 0.300824 | 1.00275 | 7800 | 6.31348 | 7500 | 0.0225 | 0.045 | 0.0675 | 2.01899 | 7929.98 | 7929.98 | 1.99199 | 721.978 | 2.01899
APTO12-VIGA-009 | Terceiro Pavimento | Viga -009 | yes | 174.719 (kgCO₂) | 1682.21 | 6.01648 | 6729.98 | 6.10648 | 0.356849 | 0.300824 | 1.00275 | 7800 | 6.31348 | 7500 | 0.0225 | 0.045 | 0.0675 | 1.99199 | 7929.98 | 7929.98 | 2.01899 | 721.978 | 2.01899

# IfcBeam: Concreto Armado Moldado in Loco - Estrutural 190 x 300 (9)
Classification: Viga (Classificação ARCHICAD); 3E 12 06 02 00 Viga (NBR 15965-5 3E); Material: Concreto Armado Moldado in Loco - Estrutural
ESTRUTURA (Expressão) - Custo por Volume (m3): 0; Estimativa de Custo Total por Volume: 0; Estimativa de Custo Total por Volume (R$): 0,00 R$
SUPERFÍCIES (Mapas) - Superfície do Topo (Geral): Concreto - 03; Superfície da Base (Geral): Concreto - 03
AC_Pset_RenovationAndPhasing - Renovation Status: Existing
Pset_BeamCommon - LoadBearing: yes; IsExternal: yes; Reference: Concreto Armado Moldado in Loco - Estrutural 190 x 300
Component Properties - Concreto Armado Moldado in Loco - Estrutural, Tipo de Componente: Núcleo
BaseQuantities - Width: 190 mm; Depth: 300 mm; CrossSectionArea: 0.057 m2
ArchiCADQuantities - Altura: 300 mm; Largura: 190 mm; Altura do Corte Transversal no Topo/Terminação (perpendicular): 300 mm; Altura do Corte Transversal na Base/Início (perpendicular): 300 mm; Largura do Corte Transversal no Topo/Terminação (perpendicular): 190 mm; Largura do Corte Transversal na Base/Início (perpendicular): 190 mm; Altura do Corte Transversal no Topo/Terminação (corte): 300 mm; Altura do Corte Transversal na Base/Início (corte): 300 mm; Largura do Corte Transversal no Topo/Terminação (corte): 190 mm; Largura do Corte Transversal na Base/Início (corte): 190 mm; Número de Segmentos: 1; Número Furo: 0; Área da Borda do Furo: 0 m2; Área de Superfície dos Furos: 0 m2; Volume Furos: 0 m3; Afastamento Eixo a partir do Centro: 0 mm
Component Quantities - Concreto Armado Moldado in Loco - Estrutural, Espessura do Componente: 190 mm; Concreto Armado Moldado in Loco - Estrutural, Altura do Componente Retangular: 300 mm; Concreto Armado Moldado in Loco - Estrutural, Largura do Componente Retangular: 190 mm; Concreto Armado Moldado in Loco - Estrutural, Área de Seção Transversal do Componente: 0.057 m2
Name | In | ID Dinâmico por Classificação | Concreto Armado Moldado in Loco - Estrutural, Carbono Incorporado | Concreto Armado Moldado in Loco - Estrutural, Energia Incorporada (MJ) | NetSurfaceAreaExtrudedSides (m2) = OuterSurfaceArea (m2) | Length (mm) = Comprimento 3D (mm) = Comprimento Esquerda (mm) = Comprimento Direita (mm) | TotalSurfaceArea (m2) = GrossSurfaceArea (m2) = NetSurfaceArea (m2) = Área da Superfície (m2) | GrossVolume (m3) = Volume (Bruto) (m3) | NetVolume (m3) = Volume (Líquido) (m3) = Volume (Condicional) (m3) = Concreto Armado Moldado in Loco - Estrutural, Volume Componente (Líquido) (m3) = Concreto Armado Moldado in Loco - Estrutural, Volume do componente (Bruto) (m3) = Concreto Armado Moldado in Loco - Estrutural, Volume Componente (Condicional) (m3) | Área (m2) = Área da Superfície do Topo (Líquida) (m2) = Área da Superfície da Base (Líquida) (m2) = Área da Superfície do Topo (Geral) (m2) = Área da Superfície da Base (Geral) (m2) | Elevação à Origem do Projeto (mm) = Elevação ao 1º Nível de Referência (mm) = Elevação ao 2º Nível de Referência (mm) = Elevação ao Nível do Mar (mm) | Elevação ao Piso (mm) = Afastamento da Origem (mm) | Elevação do Topo ao Primeiro Nível de Referência (mm) = Elevação do Topo À Cota Zero (mm) = Elevação do Topo Ao Nível do Mar (mm) = Elevação do Topo Ao Segundo Nível de Referência (mm) | Elevação do Topo Ao Piso de Origem (mm) | Elevação da Base Ao Primeiro Nível de Referência (mm) = Elevação da Base À Cota Zero (mm) = Elevação da Base Ao Nível do Mar (mm) = Elevação da Base Ao Segundo Nível de Referência (mm) | Elevação da Base Ao Piso de Origem (mm) | Área do Corte Transversal na Base/Início (m2) = Altura do Corte Transversal no Topo/Terminação (m2) | Área da Superfície das Extremidades da Viga (m2) | Área da Superfície do Lado Esquerdo da Viga (Líquida) (m2) = Área da Superfície do Lado Direito da Viga (Líquida) (m2) = Concreto Armado Moldado in Loco - Estrutural, Área de Componente Projetada (Líquida) (m2) = Concreto Armado Moldado in Loco - Estrutural, Área de Componente Projetada (Bruta) (m2) | Concreto Armado Moldado in Loco - Estrutural, Massa (kg)
VIGA-030 | Primeiro Pavimento | Viga -030 | 123.153 (kgCO₂) | 1185.73 | 3.6456 | 3720 | 3.7596 | 0.21204 | 0.21204 | 0.7068 | -300 | -300 | -150 | -150 | -450 | -450 | 0.057 | 0.114 | 1.116 | 508.896
VIGA-029 | Primeiro Pavimento | Viga -029 | 123.153 (kgCO₂) | 1185.73 | 3.6456 | 3720 | 3.7596 | 0.21204 | 0.21204 | 0.7068 | -300 | -300 | -150 | -150 | -450 | -450 | 0.057 | 0.114 | 1.116 | 508.896
CIRC1-VIGA-011 | Primeiro Pavimento | Viga -011 | 123.153 (kgCO₂) | 1185.73 | 3.6456 | 3720 | 3.7596 | 0.21204 | 0.21204 | 0.7068 | 2350 | 2350 | 2500 | 2500 | 2200 | 2200 | 0.057 | 0.114 | 1.116 | 508.896
CIRC1-VIGA-010 | Primeiro Pavimento | Viga -010 | 123.153 (kgCO₂) | 1185.73 | 3.6456 | 3720 | 3.7596 | 0.21204 | 0.21204 | 0.7068 | 2350 | 2350 | 2500 | 2500 | 2200 | 2200 | 0.057 | 0.114 | 1.116 | 508.896
CIRC2-VIGA-010 | Segundo Pavimento | Viga -010 | 123.153 (kgCO₂) | 1185.73 | 3.6456 | 3720 | 3.7596 | 0.21204 | 0.21204 | 0.7068 | 5000 | 2350 | 5150 | 2500 | 4850 | 2200 | 0.057 | 0.114 | 1.116 | 508.896
CIRC2-VIGA-011 | Segundo Pavimento | Viga -011 | 123.153 (kgCO₂) | 1185.73 | 3.6456 | 3720 | 3.7596 | 0.21204 | 0.21204 | 0.7068 | 5000 | 2350 | 5150 | 2500 | 4850 | 2200 | 0.057 | 0.114 | 1.116 | 508.896
CIRC3-VIGA-016 | Terceiro Pavimento | Viga -016 | 123.153 (kgCO₂) | 1185.73 | 3.6456 | 3720 | 3.7596 | 0.21204 | 0.21204 | 0.7068 | 7650 | 2350 | 7800 | 2500 | 7500 | 2200 | 0.057 | 0.114 | 1.116 | 508.896
CIRC3-VIGA-018 | Terceiro Pavimento | Viga -018 | 123.153 (kgCO₂) | 1185.73 | 3.6456 | 3720 | 3.7596 | 0.21204 | 0.21204 | 0.7068 | 7650 | 2350 | 7800 | 2500 | 7500 | 2200 | 0.057 | 0.114 | 1.116 | 508.896
CIRC3-VIGA-017 | Terceiro Pavimento | Viga -017 | 143.678 (kgCO₂) | 1383.35 | 4.2532 | 4340 | 4.3672 | 0.26904 | 0.24738 | 0.8246 | 7650 | 2350 | 7800 | 2500 | 7500 | 2200 | 0 | 0 | 1.302 | 593.712

# IfcBeam: Concreto Armado Moldado in Loco - Estrutural 90 x 300 (112)
Classification: Viga (Classificação ARCHICAD); 3E 12 06 02 00 Viga (NBR 15965-5 3E); Material: Concreto Armado Moldado in Loco - Estrutural
ESTRUTURA (Expressão) - Custo por Volume (m3): 0; Estimativa de Custo Total por Volume: 0; Estimativa de Custo Total por Volume (R$): 0,00 R$
SUPERFÍCIES (Mapas) - Superfície do Topo (Geral): Concreto - 03; Superfície da Base (Geral): Concreto - 03
AC_Pset_RenovationAndPhasing - Renovation Status: Existing
Pset_BeamCommon - LoadBearing: yes; Reference: Concreto Armado Moldado in Loco - Estrutural 90 x 300
Component Properties - Concreto Armado Moldado in Loco - Estrutural, Tipo de Componente: Núcleo
BaseQuantities - Width: 90 mm; Depth: 300 mm; CrossSectionArea: 0.027 m2
ArchiCADQuantities - Altura: 300 mm; Largura: 90 mm; Elevação ao Piso: 2500 mm; Afastamento da Origem: 2500 mm; Elevação do Topo Ao Piso de Origem: 2500 mm; Elevação da Base Ao Piso de Origem: 2200 mm; Altura do Corte Transversal no Topo/Terminação (perpendicular): 300 mm; Altura do Corte Transversal na Base/Início (perpendicular): 300 mm; Largura do Corte Transversal no Topo/Terminação (perpendicular): 90 mm; Largura do Corte Transversal na Base/Início (perpendicular): 90 mm; Altura do Corte Transversal no Topo/Terminação (corte): 300 mm; Altura do Corte Transversal na Base/Início (corte): 300 mm; Largura do Corte Transversal no Topo/Terminação (corte): 90 mm; Largura do Corte Transversal na Base/Início (corte): 90 mm; Número de Segmentos: 1; Número Furo: 0; Área da Borda do Furo: 0 m2; Área de Superfície dos Furos: 0 m2; Volume Furos: 0 m3; Afastamento Eixo a partir do Centro: 0 mm
Component Quantities - Concreto Armado Moldado in Loco - Estrutural, Espessura do Componente: 90 mm; Concreto Armado Moldado in Loco - Estrutural, Altura do Componente Retangular: 300 mm; Concreto Armado Moldado in Loco - Estrutural, Largura do Componente Retangular: 90 mm; Concreto Armado Moldado in Loco - Estrutural, Área de Seção Transversal do Componente: 0.027 m2
Name | In | ID Dinâmico por Classificação | IsExternal | Concreto Armado Moldado in Loco - Estrutural, Carbono Incorporado | Concreto Armado Moldado in Loco - Estrutural, Energia Incorporada (MJ) | NetSurfaceAreaExtrudedSides (m2) = OuterSurfaceArea (m2) | Length (mm) = Comprimento 3D (mm) | TotalSurfaceArea (m2) = GrossSurfaceArea (m2) = NetSurfaceArea (m2) | GrossVolume (m3) = Volume (Bruto) (m3) | NetVolume (m3) = Volume (Líquido) (m3) = Volume (Condicional) (m3) = Concreto Armado Moldado in Loco - Estrutural, Volume Componente (Líquido) (m3) = Concreto Armado Moldado in Loco - Estrutural, Volume do componente (Bruto) (m3) = Concreto Armado Moldado in Loco - Estrutural, Volume Componente (Condicional) (m3) | Área (m2) = Área da Superfície do Topo (Líquida) (m2) = Área da Superfície da Base (Líquida) (m2) = Área da Superfície do Topo (Geral) (m2) = Área da Superfície da Base (Geral) (m2) | Elevação à Origem do Projeto (mm) = Elevação ao 1º Nível de Referência (mm) = Elevação ao 2º Nível de Referência (mm) = Elevação ao Nível do Mar (mm) = Elevação do Topo ao Primeiro Nível de Referência (mm) = Elevação do Topo À Cota Zero (mm) = Elevação do Topo Ao Nível do Mar (mm) = Elevação do Topo Ao Segundo Nível de Referência (mm) | Área da Superfície (m2) | Elevação da Base Ao Primeiro Nível de Referência (mm) = Elevação da Base À Cota Zero (mm) = Elevação da Base Ao Nível do Mar (mm) = Elevação da Base Ao Segundo Nível de Referência (mm) | Área do Corte Transversal na Base/Início (m2) | Altura do Corte Transversal no Topo/Terminação (m2) | Área da Superfície das Extremidades da Viga (m2) | Área da Superfície do Lado Esquerdo da Viga (Líquida) (m2) | Comprimento Esquerda (mm) | Comprimento Direita (mm) | Área da Superfície do Lado Direito da Viga (Líquida) (m2) | Concreto Armado Moldado in Loco - Estrutural, Massa (kg) | Concreto Armado Moldado in Loco - Estrutural, Área de Componente Projetada (Líquida) (m2) = Concreto Armado Moldado in Loco - Estrutural, Área de Componente Projetada (Bruta) (m2)
VIGA-041 | Pavimento Terreo | Viga -041 | yes | 226.678 (kgCO₂) | 2182.47 | 11.2749 | 14530 | 11.3289 | 0.390285 | 0.390285 | 1.30095 | -150 | 11.3544 | -450 | 0.027 | 0.0524786 | 0.0794786 | 4.359 | 14530 | 14380 | 4.314 | 936.684 | 4.359
VIGA-042 | Pavimento Terreo | Viga -042 | yes | 220.797 (kgCO₂) | 2125.85 | 10.9824 | 14080 | 11.0364 | 0.39231 | 0.38016 | 1.2672 | -150 | 11.0904 | -450 | 0 | 0 | 0 | 4.224 | 14380 | 14380 | 4.224 | 912.384 | 4.224
VIGA-043 | Pavimento Terreo | Viga -043 | yes | 220.797 (kgCO₂) | 2125.85 | 10.9824 | 14080 | 11.0364 | 0.39231 | 0.38016 | 1.2672 | -150 | 11.0904 | -450 | 0 | 0 | 0 | 4.224 | 14380 | 14380 | 4.224 | 912.384 | 4.224
VIGA-044 | Pavimento Terreo | Viga -044 | yes | 220.797 (kgCO₂) | 2125.85 | 10.9824 | 14080 | 11.0364 | 0.39231 | 0.38016 | 1.2672 | -150 | 11.0904 | -450 | 0 | 0 | 0 | 4.224 | 14380 | 14380 | 4.224 | 912.384 | 4.224
VIGA-045 | Pavimento Terreo | Viga -045 | yes | 220.797 (kgCO₂) | 2125.85 | 10.9824 | 14080 | 11.0364 | 0.39231 | 0.38016 | 1.2672 | -150 | 11.0904 | -450 | 0 | 0 | 0 | 4.224 | 14380 | 14380 | 4.224 | 912.384 | 4.224
VIGA-046 | Pavimento Terreo | Viga -046 | yes | 220.797 (kgCO₂) | 2125.85 | 10.9824 | 14080 | 11.0364 | 0.39231 | 0.38016 | 1.2672 | -150 | 11.0904 | -450 | 0 | 0 | 0 | 4.224 | 14380 | 14380 | 4.224 | 912.384 | 4.224
VIGA-019 | Pavimento Terreo | Viga -019 | yes | 220.797 (kgCO₂) | 2125.85 | 10.9824 | 14080 | 11.0364 | 0.39231 | 0.38016 | 1.2672 | -150 | 11.0904 | -450 | 0 | 0 | 0 | 4.224 | 14380 | 14380 | 4.224 | 912.384 | 4.224
VIGA-020 | Pavimento Terreo | Viga -020 | yes | 223.543 (kgCO₂) | 2152.29 | 11.1489 | 14530 | 11.2029 | 0.39231 | 0.384888 | 1.28296 | -150 | 11.3709 | -450 | 0.0105063 | 0.0105063 | 0.0210126 | 4.224 | 14530 | 14530 | 4.359 | 923.731 | 4.359
VIGA-021 | Pavimento Terreo | Viga -021 | yes | 220.797 (kgCO₂) | 2125.85 | 10.9824 | 14080 | 11.0364 | 0.390285 | 0.38016 | 1.2672 | -150 | 11.0904 | -450 | 0 | 0 | 0 | 4.224 | 14305 | 14305 | 4.224 | 912.384 | 4.224
VIGA-022 | Pavimento Terreo | Viga -022 | yes | 220.797 (kgCO₂) | 2125.85 | 10.9824 | 14080 | 11.0364 | 0.390285 | 0.38016 | 1.2672 | -150 | 11.0904 | -450 | 0 | 0 | 0 | 4.224 | 14305 | 14305 | 4.224 | 912.384 | 4.224
VIGA-023 | Pavimento Terreo | Viga -023 | yes | 220.797 (kgCO₂) | 2125.85 | 10.9824 | 14080 | 11.0364 | 0.390285 | 0.38016 | 1.2672 | -150 | 11.0904 | -450 | 0 | 0 | 0 | 4.224 | 14305 | 14305 | 4.224 | 912.384 | 4.224
VIGA-024 | Pavimento Terreo | Viga -024 | yes | 220.797 (kgCO₂) | 2125.85 | 10.9824 | 14080 | 11.0364 | 0.390285 | 0.38016 | 1.2672 | -150 | 11.0904 | -450 | 0 | 0 | 0 | 4.224 | 14305 | 14305 | 4.224 | 912.384 | 4.224
VIGA-025 | Pavimento Terreo | Viga -025 | yes | 220.797 (kgCO₂) | 2125.85 | 10.9824 | 14080 | 11.0364 | 0.390285 | 0.38016 | 1.2672 | -150 | 11.0904 | -450 | 0 | 0 | 0 | 4.224 | 14305 | 14305 | 4.224 | 912.384 | 4.224
VIGA-026 | Pavimento Terreo | Viga -026 | yes | 220.797 (kgCO₂) | 2125.85 | 10.9824 | 14080 | 11.0364 | 0.390285 | 0.38016 | 1.2672 | -150 | 11.0904 | -450 | 0 | 0 | 0 | 4.224 | 14305 | 14305 | 4.224 | 912.384 | 4.224
VIGA-027 | Pavimento Terreo | Viga -027 | yes | 220.797 (kgCO₂) | 2125.85 | 10.9824 | 14080 | 11.0364 | 0.390285 | 0.38016 | 1.2672 | -150 | 11.0904 | -450 | 0 | 0 | 0 | 4.224 | 14305 | 14305 | 4.224 | 912.384 | 4.224
VIGA-028 | Pavimento Terreo | Viga -028 | yes | 224.325 (kgCO₂) | 2159.83 | 11.1579 | 14380 | 11.2119 | 0.390285 | 0.386235 | 1.28745 | -150 | 11.2374 | -450 | 0 | 0.0524786 | 0.0524786 | 4.269 | 14230 | 14380 | 4.314 | 926.964 | 4.314
APTO4-VIGA-007 | Primeiro Pavimento | Viga -007 | no | 111.575 (kgCO₂) | 1074.25 | 5.5497 | 7115 | 5.6037 | 0.19413 | 0.192105 | 0.64035 | 2500 | 5.6037 | 2200 | 0 | 0.027 | 0.027 | 2.1345 | 7190 | 7190 | 2.1345 | 461.052 | 2.1345
APTO4-VIGA-006 | Primeiro Pavimento | Viga -006 | no | 111.575 (kgCO₂) | 1074.25 | 5.5497 | 7115 | 5.6037 | 0.19413 | 0.192105 | 0.64035 | 2500 | 5.6037 | 2200 | 0 | 0.027 | 0.027 | 2.1345 | 7190 | 7190 | 2.1345 | 461.052 | 2.1345
APTO4-VIGA-008 | Primeiro Pavimento | Viga -008 | yes | 112.751 (kgCO₂) | 1085.57 | 5.6082 | 7190 | 5.6622 | 0.19413 | 0.19413 | 0.6471 | 2500 | 5.6622 | 2200 | 0.027 | 0.027 | 0.054 | 2.157 | 7190 | 7190 | 2.157 | 465.912 | 2.157
APTO4-VIGA-005 | Primeiro Pavimento | Viga -005 | no | 111.575 (kgCO₂) | 1074.25 | 5.5497 | 7115 | 5.6037 | 0.19413 | 0.192105 | 0.64035 | 2500 | 5.6037 | 2200 | 0 | 0.027 | 0.027 | 2.1345 | 7190 | 7190 | 2.1345 | 461.052 | 2.1345
APTO4-VIGA-004 | Primeiro Pavimento | Viga -004 | no | 111.575 (kgCO₂) | 1074.25 | 5.5497 | 7115 | 5.6037 | 0.19413 | 0.192105 | 0.64035 | 2500 | 5.6037 | 2200 | 0 | 0.027 | 0.027 | 2.1345 | 7190 | 7190 | 2.1345 | 461.052 | 2.1345
APTO4-VIGA-003 | Primeiro Pavimento | Viga -003 | no | 111.575 (kgCO₂) | 1074.25 | 5.5497 | 7115 | 5.6037 | 0.19413 | 0.192105 | 0.64035 | 2500 | 5.6037 | 2200 | 0 | 0.027 | 0.027 | 2.1345 | 7190 | 7190 | 2.1345 | 461.052 | 2.1345
APTO4-VIGA-002 | Primeiro Pavimento | Viga -002 | no | 111.575 (kgCO₂) | 1074.25 | 5.5497 | 7115 | 5.6037 | 0.19413 | 0.192105 | 0.64035 | 2500 | 5.6037 | 2200 | 0 | 0.027 | 0.027 | 2.1345 | 7190 | 7190 | 2.1345 | 461.052 | 2.1345
APTO4-VIGA-001 | Primeiro Pavimento | Viga -001 | yes | 112.032 (kgCO₂) | 1078.66 | 5.57745 | 7190 | 5.63145 | 0.19413 | 0.192893 | 0.642977 | 2500 | 5.65395 | 2200 | 0.0105063 | 0.027 | 0.0375063 | 2.1345 | 7190 | 7190 | 2.157 | 462.943 | 2.157
APTO2-VIGA-001 | Primeiro Pavimento | Viga -001 | yes | 111.314 (kgCO₂) | 1071.74 | 5.54671 | 7190 | 5.60071 | 0.19413 | 0.191656 | 0.638853 | 2500 | 5.64571 | 2200 | 0.0105063 | 0.0105063 | 0.0210126 | 2.157 | 7190 | 7190 | 2.112 | 459.974 | 2.157
APTO2-VIGA-002 | Primeiro Pavimento | Viga -002 | no | 110.398 (kgCO₂) | 1062.93 | 5.4912 | 7040 | 5.5452 | 0.19413 | 0.19008 | 0.6336 | 2500 | 5.5452 | 2200 | 0 | 0 | 0 | 2.112 | 7190 | 7190 | 2.112 | 456.192 | 2.112
APTO2-VIGA-003 | Primeiro Pavimento | Viga -003 | no | 110.398 (kgCO₂) | 1062.93 | 5.4912 | 7040 | 5.5452 | 0.19413 | 0.19008 | 0.6336 | 2500 | 5.5452 | 2200 | 0 | 0 | 0 | 2.112 | 7190 | 7190 | 2.112 | 456.192 | 2.112
APTO2-VIGA-004 | Primeiro Pavimento | Viga -004 | no | 110.398 (kgCO₂) | 1062.93 | 5.4912 | 7040 | 5.5452 | 0.19413 | 0.19008 | 0.6336 | 2500 | 5.5452 | 2200 | 0 | 0 | 0 | 2.112 | 7190 | 7190 | 2.112 | 456.192 | 2.112
APTO2-VIGA-005 | Primeiro Pavimento | Viga -005 | no | 110.398 (kgCO₂) | 1062.93 | 5.4912 | 7040 | 5.5452 | 0.19413 | 0.19008 | 0.6336 | 2500 | 5.5452 | 2200 | 0 | 0 | 0 | 2.112 | 7190 | 7190 | 2.112 | 456.192 | 2.112
APTO2-VIGA-008 | Primeiro Pavimento | Viga -008 | yes | 112.751 (kgCO₂) | 1085.57 | 5.6082 | 7190 | 5.6622 | 0.19413 | 0.19413 | 0.6471 | 2500 | 5.6622 | 2200 | 0.027 | 0.027 | 0.054 | 2.157 | 7190 | 7190 | 2.157 | 465.912 | 2.157
APTO2-VIGA-006 | Primeiro Pavimento | Viga -006 | no | 110.398 (kgCO₂) | 1062.93 | 5.4912 | 7040 | 5.5452 | 0.19413 | 0.19008 | 0.6336 | 2500 | 5.5452 | 2200 | 0 | 0 | 0 | 2.112 | 7190 | 7190 | 2.112 | 456.192 | 2.112
APTO2-VIGA-007 | Primeiro Pavimento | Viga -007 | no | 110.398 (kgCO₂) | 1062.93 | 5.4912 | 7040 | 5.5452 | 0.19413 | 0.19008 | 0.6336 | 2500 | 5.5452 | 2200 | 0 | 0 | 0 | 2.112 | 7190 | 7190 | 2.112 | 456.192 | 2.112
APTO3-VIGA-001 | Primeiro Pavimento | Viga -001 | yes | 112.032 (kgCO₂) | 1078.66 | 5.57745 | 7190 | 5.63145 | 0.19413 | 0.192893 | 0.642977 | 2500 | 5.65395 | 2200 | 0.0105063 | 0.027 | 0.0375063 | 2.157 | 7190 | 7190 | 2.1345 | 462.943 | 2.157
APTO3-VIGA-002 | Primeiro Pavimento | Viga -002 | no | 111.575 (kgCO₂) | 1074.25 | 5.5497 | 7115 | 5.6037 | 0.19413 | 0.192105 | 0.64035 | 2500 | 5.6037 | 2200 | 0 | 0.027 | 0.027 | 2.1345 | 7190 | 7190 | 2.1345 | 461.052 | 2.1345
APTO3-VIGA-003 | Primeiro Pavimento | Viga -003 | no | 111.575 (kgCO₂) | 1074.25 | 5.5497 | 7115 | 5.6037 | 0.19413 | 0.192105 | 0.64035 | 2500 | 5.6037 | 2200 | 0 | 0.027 | 0.027 | 2.1345 | 7190 | 7190 | 2.1345 | 461.052 | 2.1345
APTO3-VIGA-004 | Primeiro Pavimento | Viga -004 | no | 111.575 (kgCO₂) | 1074.25 | 5.5497 | 7115 | 5.6037 | 0.19413 | 0.192105 | 0.64035 | 2500 | 5.6037 | 2200 | 0 | 0.027 | 0.027 | 2.1345 | 7190 | 7190 | 2.1345 | 461.052 | 2.1345
APTO3-VIGA-005 | Primeiro Pavimento | Viga -005 | no | 111.575 (kgCO₂) | 1074.25 | 5.5497 | 7115 | 5.6037 | 0.19413 | 0.192105 | 0.64035 | 2500 | 5.6037 | 2200 | 0 | 0.027 | 0.027 | 2.1345 | 7190 | 7190 | 2.1345 | 461.052 | 2.1345
APTO3-VIGA-008 | Primeiro Pavimento | Viga -008 | yes | 112.751 (kgCO₂) | 1085.57 | 5.6082 | 7190 | 5.6622 | 0.19413 | 0.19413 | 0.6471 | 2500 | 5.6622 | 2200 | 0.027 | 0.027 | 0.054 | 2.157 | 7190 | 7190 | 2.157 | 465.912 | 2.157
APTO3-VIGA-006 | Primeiro Pavimento | Viga -006 | no | 111.575 (kgCO₂) | 1074.25 | 5.5497 | 7115 | 5.6037 | 0.19413 | 0.192105 | 0.64035 | 2500 | 5.6037 | 2200 | 0 | 0.027 | 0.027 | 2.1345 | 7190 | 7190 | 2.1345 | 461.052 | 2.1345
APTO3-VIGA-007 | Primeiro Pavimento | Viga -007 | no | 111.575 (kgCO₂) | 1074.25 | 5.5497 | 7115 | 5.6037 | 0.19413 | 0.192105 | 0.64035 | 2500 | 5.6037 | 2200 | 0 | 0.027 | 0.027 | 2.1345 | 7190 | 7190 | 2.1345 | 461.052 | 2.1345
APTO1-VIGA-007 | Primeiro Pavimento | Viga -007 | no | 110.398 (kgCO₂) | 1062.93 | 5.4912 | 7040 | 5.5452 | 0.19413 | 0.19008 | 0.6336 | 2500 | 5.5452 | 2200 | 0 | 0 | 0 | 2.112 | 7190 | 7190 | 2.112 | 456.192 | 2.112
APTO1-VIGA-006 | Primeiro Pavimento | Viga -006 | no | 110.398 (kgCO₂) | 1062.93 | 5.4912 | 7040 | 5.5452 | 0.19413 | 0.19008 | 0.6336 | 2500 | 5.5452 | 2200 | 0 | 0 | 0 | 2.112 | 7190 | 7190 | 2.112 | 456.192 | 2.112
APTO1-VIGA-008 | Primeiro Pavimento | Viga -008 | yes | 111.575 (kgCO₂) | 1074.25 | 5.5497 | 7115 | 5.6037 | 0.19413 | 0.192105 | 0.64035 | 2500 | 5.6037 | 2200 | 0.027 | 0 | 0.027 | 2.1345 | 7190 | 7190 | 2.1345 | 461.052 | 2.1345
APTO1-VIGA-005 | Primeiro Pavimento | Viga -005 | no | 110.398 (kgCO₂) | 1062.93 | 5.4912 | 7040 | 5.5452 | 0.19413 | 0.19008 | 0.6336 | 2500 | 5.5452 | 2200 | 0 | 0 | 0 | 2.112 | 7190 | 7190 | 2.112 | 456.192 | 2.112
APTO1-VIGA-004 | Primeiro Pavimento | Viga -004 | no | 110.398 (kgCO₂) | 1062.93 | 5.4912 | 7040 | 5.5452 | 0.19413 | 0.19008 | 0.6336 | 2500 | 5.5452 | 2200 | 0 | 0 | 0 | 2.112 | 7190 | 7190 | 2.112 | 456.192 | 2.112
APTO1-VIGA-003 | Primeiro Pavimento | Viga -003 | no | 110.398 (kgCO₂) | 1062.93 | 5.4912 | 7040 | 5.5452 | 0.19413 | 0.19008 | 0.6336 | 2500 | 5.5452 | 2200 | 0 | 0 | 0 | 2.112 | 7190 | 7190 | 2.112 | 456.192 | 2.112
APTO1-VIGA-002 | Primeiro Pavimento | Viga -002 | no | 110.398 (kgCO₂) | 1062.93 | 5.4912 | 7040 | 5.5452 | 0.19413 | 0.19008 | 0.6336 | 2500 | 5.5452 | 2200 | 0 | 0 | 0 | 2.112 | 7190 | 7190 | 2.112 | 456.192 | 2.112
APTO1-VIGA-001 | Primeiro Pavimento | Viga -001 | yes | 111.314 (kgCO₂) | 1071.74 | 5.54671 | 7190 | 5.60071 | 0.19413 | 0.191656 | 0.638853 | 2500 | 5.64571 | 2200 | 0.0105063 | 0.0105063 | 0.0210126 | 2.112 | 7190 | 7190 | 2.157 | 459.974 | 2.157
APTO5-VIGA-001 | Segundo Pavimento | Viga -001 | yes | 111.314 (kgCO₂) | 1071.74 | 5.54671 | 7190 | 5.60071 | 0.19413 | 0.191656 | 0.638853 | 5150 | 5.64571 | 4850 | 0.0105063 | 0.0105063 | 0.0210126 | 2.112 | 7190 | 7190 | 2.157 | 459.974 | 2.157
APTO5-VIGA-002 | Segundo Pavimento | Viga -002 | no | 110.398 (kgCO₂) | 1062.93 | 5.4912 | 7040 | 5.5452 | 0.19413 | 0.19008 | 0.6336 | 5150 | 5.5452 | 4850 | 0 | 0 | 0 | 2.112 | 7190 | 7190 | 2.112 | 456.192 | 2.112
APTO5-VIGA-003 | Segundo Pavimento | Viga -003 | no | 110.398 (kgCO₂) | 1062.93 | 5.4912 | 7040 | 5.5452 | 0.19413 | 0.19008 | 0.6336 | 5150 | 5.5452 | 4850 | 0 | 0 | 0 | 2.112 | 7190 | 7190 | 2.112 | 456.192 | 2.112
APTO5-VIGA-004 | Segundo Pavimento | Viga -004 | no | 110.398 (kgCO₂) | 1062.93 | 5.4912 | 7040 | 5.5452 | 0.19413 | 0.19008 | 0.6336 | 5150 | 5.5452 | 4850 | 0 | 0 | 0 | 2.112 | 7190 | 7190 | 2.112 | 456.192 | 2.112
APTO5-VIGA-005 | Segundo Pavimento | Viga -005 | no | 110.398 (kgCO₂) | 1062.93 | 5.4912 | 7040 | 5.5452 | 0.19413 | 0.19008 | 0.6336 | 5150 | 5.5452 | 4850 | 0 | 0 | 0 | 2.112 | 7190 | 7190 | 2.112 | 456.192 | 2.112
APTO5-VIGA-008 | Segundo Pavimento | Viga -008 | yes | 111.575 (kgCO₂) | 1074.25 | 5.5497 | 7115 | 5.6037 | 0.19413 | 0.192105 | 0.64035 | 5150 | 5.6037 | 4850 | 0.027 | 0 | 0.027 | 2.1345 | 7190 | 7190 | 2.1345 | 461.052 | 2.1345
APTO5-VIGA-006 | Segundo Pavimento | Viga -006 | no | 110.398 (kgCO₂) | 1062.93 | 5.4912 | 7040 | 5.5452 | 0.19413 | 0.19008 | 0.6336 | 5150 | 5.5452 | 4850 | 0 | 0 | 0 | 2.112 | 7190 | 7190 | 2.112 | 456.192 | 2.112
APTO5-VIGA-007 | Segundo Pavimento | Viga -007 | no | 110.398 (kgCO₂) | 1062.93 | 5.4912 | 7040 | 5.5452 | 0.19413 | 0.19008 | 0.6336 | 5150 | 5.5452 | 4850 | 0 | 0 | 0 | 2.112 | 7190 | 7190 | 2.112 | 456.192 | 2.112
APTO6-VIGA-001 | Segundo Pavimento | Viga -001 | yes | 111.314 (kgCO₂) | 1071.74 | 5.54671 | 7190 | 5.60071 | 0.19413 | 0.191656 | 0.638853 | 5150 | 5.64571 | 4850 | 0.0105063 | 0.0105063 | 0.0210126 | 2.157 | 7190 | 7190 | 2.112 | 459.974 | 2.157
APTO6-VIGA-002 | Segundo Pavimento | Viga -002 | no | 110.398 (kgCO₂) | 1062.93 | 5.4912 | 7040 | 5.5452 | 0.19413 | 0.19008 | 0.6336 | 5150 | 5.5452 | 4850 | 0 | 0 | 0 | 2.112 | 7190 | 7190 | 2.112 | 456.192 | 2.112
APTO6-VIGA-003 | Segundo Pavimento | Viga -003 | no | 110.398 (kgCO₂) | 1062.93 | 5.4912 | 7040 | 5.5452 | 0.19413 | 0.19008 | 0.6336 | 5150 | 5.5452 | 4850 | 0 | 0 | 0 | 2.112 | 7190 | 7190 | 2.112 | 456.192 | 2.112
APTO6-VIGA-004 | Segundo Pavimento | Viga -004 | no | 110.398 (kgCO₂) | 1062.93 | 5.4912 | 7040 | 5.5452 | 0.19413 | 0.19008 | 0.6336 | 5150 | 5.5452 | 4850 | 0 | 0 | 0 | 2.112 | 7190 | 7190 | 2.112 | 456.192 | 2.112
APTO6-VIGA-005 | Segundo Pavimento | Viga -005 | no | 110.398 (kgCO₂) | 1062.93 | 5.4912 | 7040 | 5.5452 | 0.19413 | 0.19008 | 0.6336 | 5150 | 5.5452 | 4850 | 0 | 0 | 0 | 2.112 | 7190 | 7190 | 2.112 | 456.192 | 2.112
APTO6-VIGA-008 | Segundo Pavimento | Viga -008 | yes | 112.751 (kgCO₂) | 1085.57 | 5.6082 | 7190 | 5.6622 | 0.19413 | 0.19413 | 0.6471 | 5150 | 5.6622 | 4850 | 0.027 | 0.027 | 0.054 | 2.157 | 7190 | 7190 | 2.157 | 465.912 | 2.157
APTO6-VIGA-006 | Segundo Pavimento | Viga -006 | no | 110.398 (kgCO₂) | 1062.93 | 5.4912 | 7040 | 5.5452 | 0.19413 | 0.19008 | 0.6336 | 5150 | 5.5452 | 4850 | 0 | 0 | 0 | 2.112 | 7190 | 7190 | 2.112 | 456.192 | 2.112
APTO6-VIGA-007 | Segundo Pavimento | Viga -007 | no | 110.398 (kgCO₂) | 1062.93 | 5.4912 | 7040 | 5.5452 | 0.19413 | 0.19008 | 0.6336 | 5150 | 5.5452 | 4850 | 0 | 0 | 0 | 2.112 | 7190 | 7190 | 2.112 | 456.192 | 2.112
APTO7-VIGA-001 | Segundo Pavimento | Viga -001 | yes | 112.032 (kgCO₂) | 1078.66 | 5.57745 | 7190 | 5.63145 | 0.19413 | 0.192893 | 0.642977 | 5150 | 5.65395 | 4850 | 0.0105063 | 0.027 | 0.0375063 | 2.157 | 7190 | 7190 | 2.1345 | 462.943 | 2.157
APTO7-VIGA-002 | Segundo Pavimento | Viga -002 | no | 111.575 (kgCO₂) | 1074.25 | 5.5497 | 7115 | 5.6037 | 0.19413 | 0.192105 | 0.64035 | 5150 | 5.6037 | 4850 | 0 | 0.027 | 0.027 | 2.1345 | 7190 | 7190 | 2.1345 | 461.052 | 2.1345
APTO7-VIGA-003 | Segundo Pavimento | Viga -003 | no | 111.575 (kgCO₂) | 1074.25 | 5.5497 | 7115 | 5.6037 | 0.19413 | 0.192105 | 0.64035 | 5150 | 5.6037 | 4850 | 0 | 0.027 | 0.027 | 2.1345 | 7190 | 7190 | 2.1345 | 461.052 | 2.1345
APTO7-VIGA-004 | Segundo Pavimento | Viga -004 | no | 111.575 (kgCO₂) | 1074.25 | 5.5497 | 7115 | 5.6037 | 0.19413 | 0.192105 | 0.64035 | 5150 | 5.6037 | 4850 | 0 | 0.027 | 0.027 | 2.1345 | 7190 | 7190 | 2.1345 | 461.052 | 2.1345
APTO7-VIGA-005 | Segundo Pavimento | Viga -005 | no | 111.575 (kgCO₂) | 1074.25 | 5.5497 | 7115 | 5.6037 | 0.19413 | 0.192105 | 0.64035 | 5150 | 5.6037 | 4850 | 0 | 0.027 | 0.027 | 2.1345 | 7190 | 7190 | 2.1345 | 461.052 | 2.1345
APTO7-VIGA-008 | Segundo Pavimento | Viga -008 | yes | 112.751 (kgCO₂) | 1085.57 | 5.6082 | 7190 | 5.6622 | 0.19413 | 0.19413 | 0.6471 | 5150 | 5.6622 | 4850 | 0.027 | 0.027 | 0.054 | 2.157 | 7190 | 7190 | 2.157 | 465.912 | 2.157
APTO7-VIGA-006 | Segundo Pavimento | Viga -006 | no | 111.575 (kgCO₂) | 1074.25 | 5.5497 | 7115 | 5.6037 | 0.19413 | 0.192105 | 0.64035 | 5150 | 5.6037 | 4850 | 0 | 0.027 | 0.027 | 2.1345 | 7190 | 7190 | 2.1345 | 461.052 | 2.1345
APTO7-VIGA-007 | Segundo Pavimento | Viga -007 | no | 111.575 (kgCO₂) | 1074.25 | 5.5497 | 7115 | 5.6037 | 0.19413 | 0.192105 | 0.64035 | 5150 | 5.6037 | 4850 | 0 | 0.027 | 0.027 | 2.1345 | 7190 | 7190 | 2.1345 | 461.052 | 2.1345
APTO8-VIGA-001 | Segundo Pavimento | Viga -001 | yes | 112.032 (kgCO₂) | 1078.66 | 5.57745 | 7190 | 5.63145 | 0.19413 | 0.192893 | 0.642977 | 5150 | 5.65395 | 4850 | 0.0105063 | 0.027 | 0.0375063 | 2.1345 | 7190 | 7190 | 2.157 | 462.943 | 2.157
APTO8-VIGA-002 | Segundo Pavimento | Viga -002 | no | 111.575 (kgCO₂) | 1074.25 | 5.5497 | 7115 | 5.6037 | 0.19413 | 0.192105 | 0.64035 | 5150 | 5.6037 | 4850 | 0 | 0.027 | 0.027 | 2.1345 | 7190 | 7190 | 2.1345 | 461.052 | 2.1345
APTO8-VIGA-003 | Segundo Pavimento | Viga -003 | no | 111.575 (kgCO₂) | 1074.25 | 5.5497 | 7115 | 5.6037 | 0.19413 | 0.192105 | 0.64035 | 5150 | 5.6037 | 4850 | 0 | 0.027 | 0.027 | 2.1345 | 7190 | 7190 | 2.1345 | 461.052 | 2.1345
APTO8-VIGA-004 | Segundo Pavimento | Viga -004 | no | 111.575 (kgCO₂) | 1074.25 | 5.5497 | 7115 | 5.6037 | 0.19413 | 0.192105 | 0.64035 | 5150 | 5.6037 | 4850 | 0 | 0.027 | 0.027 | 2.1345 | 7190 | 7190 | 2.1345 | 461.052 | 2.1345
APTO8-VIGA-005 | Segundo Pavimento | Viga -005 | no | 111.575 (kgCO₂) | 1074.25 | 5.5497 | 7115 | 5.6037 | 0.19413 | 0.192105 | 0.64035 | 5150 | 5.6037 | 4850 | 0 | 0.027 | 0.027 | 2.1345 | 7190 | 7190 | 2.1345 | 461.052 | 2.1345
APTO8-VIGA-008 | Segundo Pavimento | Viga -008 | yes | 112.751 (kgCO₂) | 1085.57 | 5.6082 | 7190 | 5.6622 | 0.19413 | 0.19413 | 0.6471 | 5150 | 5.6622 | 4850 | 0.027 | 0.027 | 0.054 | 2.157 | 7190 | 7190 | 2.157 | 465.912 | 2.157
APTO8-VIGA-006 | Segundo Pavimento | Viga -006 | no | 111.575 (kgCO₂) | 1074.25 | 5.5497 | 7115 | 5.6037 | 0.19413 | 0.192105 | 0.64035 | 5150 | 5.6037 | 4850 | 0 | 0.027 | 0.027 | 2.1345 | 7190 | 7190 | 2.1345 | 461.052 | 2.1345
APTO8-VIGA-007 | Segundo Pavimento | Viga -007 | no | 111.575 (kgCO₂) | 1074.25 | 5.5497 | 7115 | 5.6037 | 0.19413 | 0.192105 | 0.64035 | 5150 | 5.6037 | 4850 | 0 | 0.027 | 0.027 | 2.1345 | 7190 | 7190 | 2.1345 | 461.052 | 2.1345
APTO9-VIGA-001 | Terceiro Pavimento | Viga -001 | yes | 111.314 (kgCO₂) | 1071.74 | 5.54671 | 7190 | 5.60071 | 0.19413 | 0.191656 | 0.638853 | 7800 | 5.64571 | 7500 | 0.0105063 | 0.0105063 | 0.0210126 | 2.112 | 7190 | 7190 | 2.157 | 459.974 | 2.157
APTO9-VIGA-002 | Terceiro Pavimento | Viga -002 | no | 110.398 (kgCO₂) | 1062.93 | 5.4912 | 7040 | 5.5452 | 0.19413 | 0.19008 | 0.6336 | 7800 | 5.5452 | 7500 | 0 | 0 | 0 | 2.112 | 7190 | 7190 | 2.112 | 456.192 | 2.112
APTO9-VIGA-003 | Terceiro Pavimento | Viga -003 | no | 110.398 (kgCO₂) | 1062.93 | 5.4912 | 7040 | 5.5452 | 0.19413 | 0.19008 | 0.6336 | 7800 | 5.5452 | 7500 | 0 | 0 | 0 | 2.112 | 7190 | 7190 | 2.112 | 456.192 | 2.112
APTO9-VIGA-004 | Terceiro Pavimento | Viga -004 | no | 110.398 (kgCO₂) | 1062.93 | 5.4912 | 7040 | 5.5452 | 0.19413 | 0.19008 | 0.6336 | 7800 | 5.5452 | 7500 | 0 | 0 | 0 | 2.112 | 7190 | 7190 | 2.112 | 456.192 | 2.112
APTO9-VIGA-005 | Terceiro Pavimento | Viga -005 | no | 110.398 (kgCO₂) | 1062.93 | 5.4912 | 7040 | 5.5452 | 0.19413 | 0.19008 | 0.6336 | 7800 | 5.5452 | 7500 | 0 | 0 | 0 | 2.112 | 7190 | 7190 | 2.112 | 456.192 | 2.112
APTO9-VIGA-008 | Terceiro Pavimento | Viga -008 | yes | 111.575 (kgCO₂) | 1074.25 | 5.5497 | 7115 | 5.6037 | 0.19413 | 0.192105 | 0.64035 | 7800 | 5.6037 | 7500 | 0.027 | 0 | 0.027 | 2.1345 | 7190 | 7190 | 2.1345 | 461.052 | 2.1345
APTO9-VIGA-006 | Terceiro Pavimento | Viga -006 | no | 110.398 (kgCO₂) | 1062.93 | 5.4912 | 7040 | 5.5452 | 0.19413 | 0.19008 | 0.6336 | 7800 | 5.5452 | 7500 | 0 | 0 | 0 | 2.112 | 7190 | 7190 | 2.112 | 456.192 | 2.112
APTO9-VIGA-007 | Terceiro Pavimento | Viga -007 | no | 110.398 (kgCO₂) | 1062.93 | 5.4912 | 7040 | 5.5452 | 0.19413 | 0.19008 | 0.6336 | 7800 | 5.5452 | 7500 | 0 | 0 | 0 | 2.112 | 7190 | 7190 | 2.112 | 456.192 | 2.112
APTO10-VIGA-001 | Terceiro Pavimento | Viga -001 | yes | 111.314 (kgCO₂) | 1071.74 | 5.54671 | 7190 | 5.60071 | 0.19413 | 0.191656 | 0.638853 | 7800 | 5.64571 | 7500 | 0.0105063 | 0.0105063 | 0.0210126 | 2.157 | 7190 | 7190 | 2.112 | 459.974 | 2.157
APTO10-VIGA-002 | Terceiro Pavimento | Viga -002 | no | 110.398 (kgCO₂) | 1062.93 | 5.4912 | 7040 | 5.5452 | 0.19413 | 0.19008 | 0.6336 | 7800 | 5.5452 | 7500 | 0 | 0 | 0 | 2.112 | 7190 | 7190 | 2.112 | 456.192 | 2.112
APTO10-VIGA-003 | Terceiro Pavimento | Viga -003 | no | 110.398 (kgCO₂) | 1062.93 | 5.4912 | 7040 | 5.5452 | 0.19413 | 0.19008 | 0.6336 | 7800 | 5.5452 | 7500 | 0 | 0 | 0 | 2.112 | 7190 | 7190 | 2.112 | 456.192 | 2.112
APTO10-VIGA-004 | Terceiro Pavimento | Viga -004 | no | 110.398 (kgCO₂) | 1062.93 | 5.4912 | 7040 | 5.5452 | 0.19413 | 0.19008 | 0.6336 | 7800 | 5.5452 | 7500 | 0 | 0 | 0 | 2.112 | 7190 | 7190 | 2.112 | 456.192 | 2.112
APTO10-VIGA-005 | Terceiro Pavimento | Viga -005 | no | 110.398 (kgCO₂) | 1062.93 | 5.4912 | 7040 | 5.5452 | 0.19413 | 0.19008 | 0.6336 | 7800 | 5.5452 | 7500 | 0 | 0 | 0 | 2.112 | 7190 | 7190 | 2.112 | 456.192 | 2.112
APTO10-VIGA-008 | Terceiro Pavimento | Viga -008 | yes | 112.751 (kgCO₂) | 1085.57 | 5.6082 | 7190 | 5.6622 | 0.19413 | 0.19413 | 0.6471 | 7800 | 5.6622 | 7500 | 0.027 | 0.027 | 0.054 | 2.157 | 7190 | 7190 | 2.157 | 465.912 | 2.157
APTO10-VIGA-006 | Terceiro Pavimento | Viga -006 | no | 110.398 (kgCO₂) | 1062.93 | 5.4912 | 7040 | 5.5452 | 0.19413 | 0.19008 | 0.6336 | 7800 | 5.5452 | 7500 | 0 | 0 | 0 | 2.112 | 7190 | 7190 | 2.112 | 456.192 | 2.112
APTO10-VIGA-007 | Terceiro Pavimento | Viga -007 | no | 110.398 (kgCO₂) | 1062.93 | 5.4912 | 7040 | 5.5452 | 0.19413 | 0.19008 | 0.6336 | 7800 | 5.5452 | 7500 | 0 | 0 | 0 | 2.112 | 7190 | 7190 | 2.112 | 456.192 | 2.112
APTO11-VIGA-001 | Terceiro Pavimento | Viga -001 | yes | 112.032 (kgCO₂) | 1078.66 | 5.57745 | 7190 | 5.63145 | 0.19413 | 0.192893 | 0.642977 | 7800 | 5.65395 | 7500 | 0.0105063 | 0.027 | 0.0375063 | 2.157 | 7190 | 7190 | 2.1345 | 462.943 | 2.157
APTO11-VIGA-002 | Terceiro Pavimento | Viga -002 | no | 111.575 (kgCO₂) | 1074.25 | 5.5497 | 7115 | 5.6037 | 0.19413 | 0.192105 | 0.64035 | 7800 | 5.6037 | 7500 | 0 | 0.027 | 0.027 | 2.1345 | 7190 | 7190 | 2.1345 | 461.052 | 2.1345
APTO11-VIGA-003 | Terceiro Pavimento | Viga -003 | no | 111.575 (kgCO₂) | 1074.25 | 5.5497 | 7115 | 5.6037 | 0.19413 | 0.192105 | 0.64035 | 7800 | 5.6037 | 7500 | 0 | 0.027 | 0.027 | 2.1345 | 7190 | 7190 | 2.1345 | 461.052 | 2.1345
APTO11-VIGA-004 | Terceiro Pavimento | Viga -004 | no | 111.575 (kgCO₂) | 1074.25 | 5.5497 | 7115 | 5.6037 | 0.19413 | 0.192105 | 0.64035 | 7800 | 5.6037 | 7500 | 0 | 0.027 | 0.027 | 2.1345 | 7190 | 7190 | 2.1345 | 461.052 | 2.1345
APTO11-VIGA-005 | Terceiro Pavimento | Viga -005 | no | 111.575 (kgCO₂) | 1074.25 | 5.5497 | 7115 | 5.6037 | 0.19413 | 0.192105 | 0.64035 | 7800 | 5.6037 | 7500 | 0 | 0.027 | 0.027 | 2.1345 | 7190 | 7190 | 2.1345 | 461.052 | 2.1345
APTO11-VIGA-008 | Terceiro Pavimento | Viga -008 | yes | 112.751 (kgCO₂) | 1085.57 | 5.6082 | 7190 | 5.6622 | 0.19413 | 0.19413 | 0.6471 | 7800 | 5.6622 | 7500 | 0.027 | 0.027 | 0.054 | 2.157 | 7190 | 7190 | 2.157 | 465.912 | 2.157
APTO11-VIGA-006 | Terceiro Pavimento | Viga -006 | no | 111.575 (kgCO₂) | 1074.25 | 5.5497 | 7115 | 5.6037 | 0.19413 | 0.192105 | 0.64035 | 7800 | 5.6037 | 7500 | 0 | 0.027 | 0.027 | 2.1345 | 7190 | 7190 | 2.1345 | 461.052 | 2.1345
APTO11-VIGA-007 | Terceiro Pavimento | Viga -007 | no | 111.575 (kgCO₂) | 1074.25 | 5.5497 | 7115 | 5.6037 | 0.19413 | 0.192105 | 0.64035 | 7800 | 5.6037 | 7500 | 0 | 0.027 | 0.027 | 2.1345 | 7190 | 7190 | 2.1345 | 461.052 | 2.1345
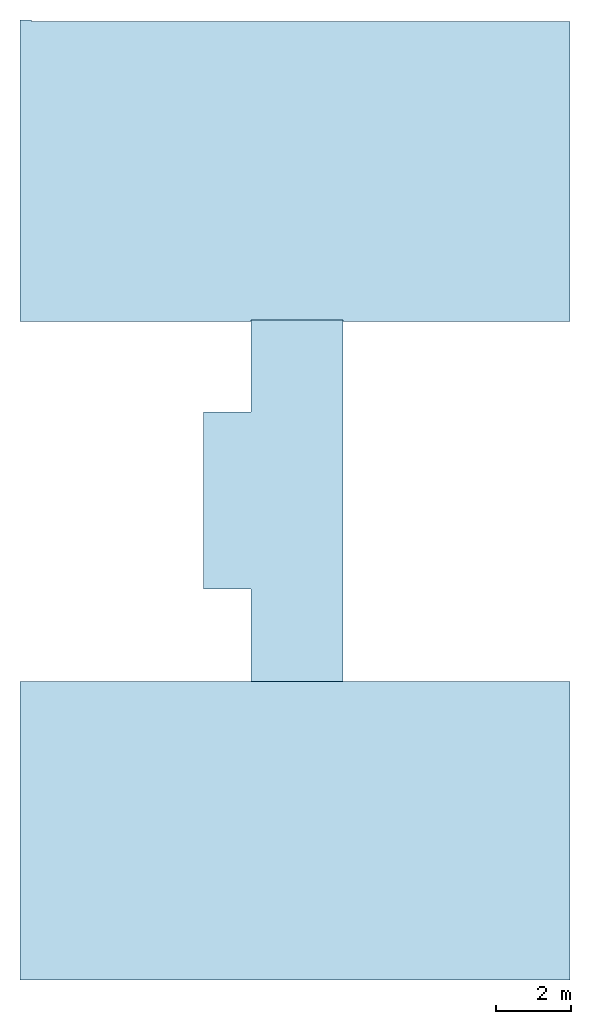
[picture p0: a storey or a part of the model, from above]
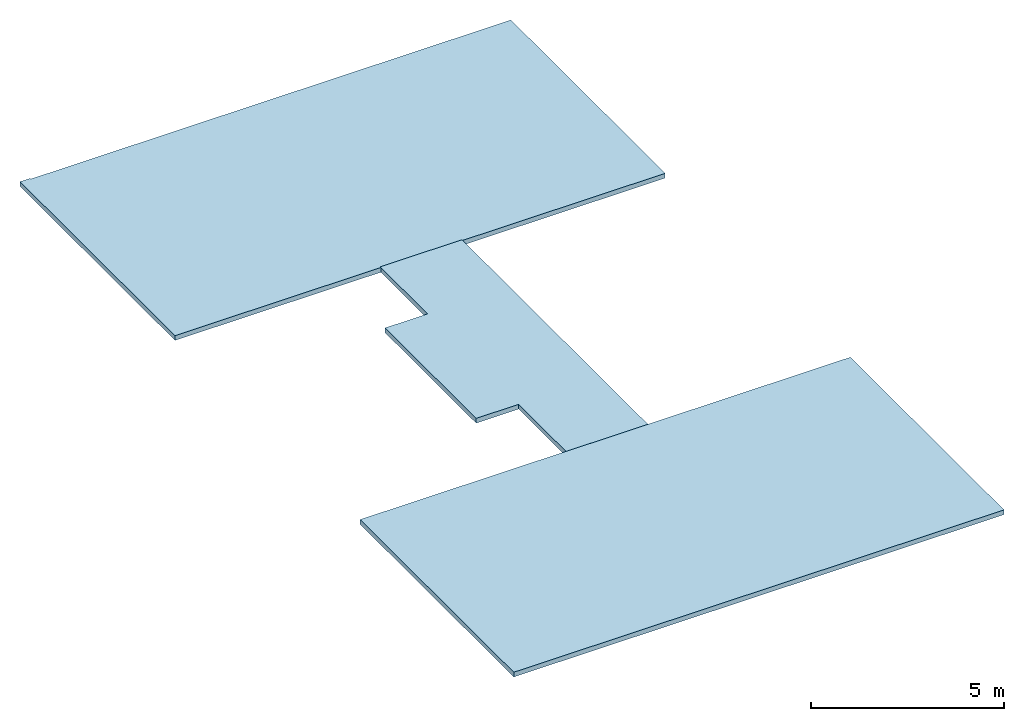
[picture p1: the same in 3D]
Properties of the parts of a building model (IFC2X3), part 3 of 7

# IfcBeam: Concreto Armado Moldado in Loco - Estrutural 90 x 300 (112)
Name | In | ID Dinâmico por Classificação | IsExternal | Concreto Armado Moldado in Loco - Estrutural, Carbono Incorporado | Concreto Armado Moldado in Loco - Estrutural, Energia Incorporada (MJ) | NetSurfaceAreaExtrudedSides (m2) = OuterSurfaceArea (m2) | Length (mm) = Comprimento 3D (mm) | TotalSurfaceArea (m2) = GrossSurfaceArea (m2) = NetSurfaceArea (m2) | GrossVolume (m3) = Volume (Bruto) (m3) | NetVolume (m3) = Volume (Líquido) (m3) = Volume (Condicional) (m3) = Concreto Armado Moldado in Loco - Estrutural, Volume Componente (Líquido) (m3) = Concreto Armado Moldado in Loco - Estrutural, Volume do componente (Bruto) (m3) = Concreto Armado Moldado in Loco - Estrutural, Volume Componente (Condicional) (m3) | Área (m2) = Área da Superfície do Topo (Líquida) (m2) = Área da Superfície da Base (Líquida) (m2) = Área da Superfície do Topo (Geral) (m2) = Área da Superfície da Base (Geral) (m2) | Elevação à Origem do Projeto (mm) = Elevação ao 1º Nível de Referência (mm) = Elevação ao 2º Nível de Referência (mm) = Elevação ao Nível do Mar (mm) = Elevação do Topo ao Primeiro Nível de Referência (mm) = Elevação do Topo À Cota Zero (mm) = Elevação do Topo Ao Nível do Mar (mm) = Elevação do Topo Ao Segundo Nível de Referência (mm) | Área da Superfície (m2) | Elevação da Base Ao Primeiro Nível de Referência (mm) = Elevação da Base À Cota Zero (mm) = Elevação da Base Ao Nível do Mar (mm) = Elevação da Base Ao Segundo Nível de Referência (mm) | Área do Corte Transversal na Base/Início (m2) | Altura do Corte Transversal no Topo/Terminação (m2) | Área da Superfície das Extremidades da Viga (m2) | Área da Superfície do Lado Esquerdo da Viga (Líquida) (m2) | Comprimento Esquerda (mm) | Comprimento Direita (mm) | Área da Superfície do Lado Direito da Viga (Líquida) (m2) | Concreto Armado Moldado in Loco - Estrutural, Massa (kg) | Concreto Armado Moldado in Loco - Estrutural, Área de Componente Projetada (Líquida) (m2) = Concreto Armado Moldado in Loco - Estrutural, Área de Componente Projetada (Bruta) (m2)
APTO12-VIGA-001 | Terceiro Pavimento | Viga -001 | yes | 112.032 (kgCO₂) | 1078.66 | 5.57745 | 7190 | 5.63145 | 0.19413 | 0.192893 | 0.642977 | 7800 | 5.65395 | 7500 | 0.0105063 | 0.027 | 0.0375063 | 2.1345 | 7190 | 7190 | 2.157 | 462.943 | 2.157
APTO12-VIGA-002 | Terceiro Pavimento | Viga -002 | no | 111.575 (kgCO₂) | 1074.25 | 5.5497 | 7115 | 5.6037 | 0.19413 | 0.192105 | 0.64035 | 7800 | 5.6037 | 7500 | 0 | 0.027 | 0.027 | 2.1345 | 7190 | 7190 | 2.1345 | 461.052 | 2.1345
APTO12-VIGA-003 | Terceiro Pavimento | Viga -003 | no | 111.575 (kgCO₂) | 1074.25 | 5.5497 | 7115 | 5.6037 | 0.19413 | 0.192105 | 0.64035 | 7800 | 5.6037 | 7500 | 0 | 0.027 | 0.027 | 2.1345 | 7190 | 7190 | 2.1345 | 461.052 | 2.1345
APTO12-VIGA-004 | Terceiro Pavimento | Viga -004 | no | 111.575 (kgCO₂) | 1074.25 | 5.5497 | 7115 | 5.6037 | 0.19413 | 0.192105 | 0.64035 | 7800 | 5.6037 | 7500 | 0 | 0.027 | 0.027 | 2.1345 | 7190 | 7190 | 2.1345 | 461.052 | 2.1345
APTO12-VIGA-005 | Terceiro Pavimento | Viga -005 | no | 111.575 (kgCO₂) | 1074.25 | 5.5497 | 7115 | 5.6037 | 0.19413 | 0.192105 | 0.64035 | 7800 | 5.6037 | 7500 | 0 | 0.027 | 0.027 | 2.1345 | 7190 | 7190 | 2.1345 | 461.052 | 2.1345
APTO12-VIGA-008 | Terceiro Pavimento | Viga -008 | yes | 112.751 (kgCO₂) | 1085.57 | 5.6082 | 7190 | 5.6622 | 0.19413 | 0.19413 | 0.6471 | 7800 | 5.6622 | 7500 | 0.027 | 0.027 | 0.054 | 2.157 | 7190 | 7190 | 2.157 | 465.912 | 2.157
APTO12-VIGA-006 | Terceiro Pavimento | Viga -006 | no | 111.575 (kgCO₂) | 1074.25 | 5.5497 | 7115 | 5.6037 | 0.19413 | 0.192105 | 0.64035 | 7800 | 5.6037 | 7500 | 0 | 0.027 | 0.027 | 2.1345 | 7190 | 7190 | 2.1345 | 461.052 | 2.1345
APTO12-VIGA-007 | Terceiro Pavimento | Viga -007 | no | 111.575 (kgCO₂) | 1074.25 | 5.5497 | 7115 | 5.6037 | 0.19413 | 0.192105 | 0.64035 | 7800 | 5.6037 | 7500 | 0 | 0.027 | 0.027 | 2.1345 | 7190 | 7190 | 2.1345 | 461.052 | 2.1345

# IfcBuildingElementPart (432)
Name | In | Material | Carbono Incorporado | Energia Incorporada (MJ) | Massa (kg) | Volume Componente (Líquido) (m3) = Volume do componente (Bruto) (m3)
64 x Alumínio | Primeiro Pavimento | Alumínio | 276.408 (kgCO₂) | 4677.22 | 30.1756 | 0.010777
64 x Vidro | Primeiro Pavimento | Vidro | 13.5335 (kgCO₂) | 223.08 | 14.872 | 0.0059488
4 x Alumínio | Primeiro Pavimento | Alumínio | 270.586 (kgCO₂) | 4578.7 | 29.54 | 0.01055
4 x Vidro | Primeiro Pavimento | Vidro | 13.9239 (kgCO₂) | 229.515 | 15.301 | 0.0061204
4 x Alumínio | Primeiro Pavimento | Alumínio | 272.484 (kgCO₂) | 4610.82 | 29.7472 | 0.010624
4 x Vidro | Primeiro Pavimento | Vidro | 14.1842 (kgCO₂) | 233.805 | 15.587 | 0.0062348
64 x Alumínio | Segundo Pavimento | Alumínio | 276.408 (kgCO₂) | 4677.22 | 30.1756 | 0.010777
64 x Vidro | Segundo Pavimento | Vidro | 13.5335 (kgCO₂) | 223.08 | 14.872 | 0.0059488
4 x Alumínio | Segundo Pavimento | Alumínio | 270.586 (kgCO₂) | 4578.7 | 29.54 | 0.01055
4 x Vidro | Segundo Pavimento | Vidro | 13.9239 (kgCO₂) | 229.515 | 15.301 | 0.0061204
4 x Alumínio | Segundo Pavimento | Alumínio | 272.484 (kgCO₂) | 4610.82 | 29.7472 | 0.010624
4 x Vidro | Segundo Pavimento | Vidro | 14.1842 (kgCO₂) | 233.805 | 15.587 | 0.0062348
64 x Alumínio | Terceiro Pavimento | Alumínio | 276.408 (kgCO₂) | 4677.22 | 30.1756 | 0.010777
64 x Vidro | Terceiro Pavimento | Vidro | 13.5335 (kgCO₂) | 223.08 | 14.872 | 0.0059488
4 x Alumínio | Terceiro Pavimento | Alumínio | 272.484 (kgCO₂) | 4610.82 | 29.7472 | 0.010624
4 x Vidro | Terceiro Pavimento | Vidro | 14.1842 (kgCO₂) | 233.805 | 15.587 | 0.0062348
4 x Alumínio | Terceiro Pavimento | Alumínio | 270.586 (kgCO₂) | 4578.7 | 29.54 | 0.01055
4 x Vidro | Terceiro Pavimento | Vidro | 13.9239 (kgCO₂) | 229.515 | 15.301 | 0.0061204

# IfcColumn: Concreto Armado Moldado in Loco - Estrutural 600 x 150 (48)
Classification: Pilar (Classificação ARCHICAD); 3E 12 10 02 02 Pilar (NBR 15965-5 3E); Material: Concreto Armado Moldado in Loco - Estrutural
ESTRUTURA (Expressão) - Custo por Volume (m3): 0
AC_Pset_RenovationAndPhasing - Renovation Status: Existing
Pset_ColumnCommon - LoadBearing: yes; Reference: Concreto Armado Moldado in Loco - Estrutural 600 x 150
Component Properties - Concreto Armado Moldado in Loco - Estrutural, Carbono Incorporado: 138.521 (kgCO₂); Concreto Armado Moldado in Loco - Estrutural, Energia Incorporada: 1333.69 MJ; Concreto Armado Moldado in Loco - Estrutural, Tipo de Componente: Núcleo
BaseQuantities - Length: 2650 mm; Width: 600 mm; Depth: 150 mm; CrossSectionArea: 0.09 m2; OuterSurfaceArea: 3.975 m2; TotalSurfaceArea: 4.155 m2; GrossSurfaceArea: 4.155 m2; GrossVolume: 0.2385 m3; NetVolume: 0.2385 m3
ArchiCADQuantities - Área: 0.09 m2; Altura: 2650 mm; Volume (Líquido): 0.2385 m3; Largura: 600 mm; Elevação ao Piso: 0 mm; Afastamento da Origem: 0 mm; Afastamento do Topo: 0 mm; Área da Superfície: 3.975 m2; Comprimento 3D: 2650 mm; Volume (Bruto): 0.2385 m3; Elevação do Topo Ao Piso de Origem: 2650 mm; Elevação da Base Ao Piso de Origem: 0 mm; Altura do Corte Transversal no Topo/Terminação (perpendicular): 150 mm; Altura do Corte Transversal na Base/Início (perpendicular): 150 mm; Largura do Corte Transversal no Topo/Terminação (perpendicular): 600 mm; Largura do Corte Transversal na Base/Início (perpendicular): 600 mm; Altura do Corte Transversal no Topo/Terminação (corte): 150 mm; Altura do Corte Transversal na Base/Início (corte): 150 mm; Largura do Corte Transversal no Topo/Terminação (corte): 600 mm; Largura do Corte Transversal na Base/Início (corte): 600 mm; Área do Corte Transversal na Base/Início: 0.09 m2; Altura do Corte Transversal no Topo/Terminação: 0.09 m2; Número de Segmentos: 1; Área da Superfície do Topo (Líquida): 0.09 m2; Área da Superfície da Base (Líquida): 3.975 m2; Área da Superfície do Topo (Bruta): 0.09 m2; Diâmetro / Altura do Núcleo: 150 mm; Volume do Núcleo do Pilar (Líquido): 0.2385 m3; Largura Núcleo: 600 mm; Área da Superfície do Núcleo do Pilar (Bruta, sem Topo/Base): 3.975 m2; Área da Superfície do Topo do Núcleo do Pilar (Bruta): 0.09 m2; Área da Superfície da Base do Núcleo do Pilar (Bruta): 0.09 m2; Volume do Núcleo do Pilar (Bruto): 0.2385 m3; Área de Superfície do Revestimento do Pilar (Bruta, sem Topo/Base): 0 m2; Área da Superfície do Topo do Revestimento do Pilar (Bruta): 0 m2; Área da Superfíciena da Base do Revestimento do Pilar (Bruta): 0 m2; Volume do Revestimento do Pilar (Bruto): 0 m3; Altura máxima do pilar: 2650 mm; Altura mínima do pilar: 2650 mm; Área da Superfície da Base do Núcleo do Pilar (Líquida): 0.09 m2; Área da Superfície do Núcleo do Pilar (Líquida, sem Topo/Base): 3.975 m2; Área da Superfície do Topo do Núcleo do Pilar (Líquida): 0.09 m2; Área da Superfície da Base do Revestimento do Pilar (Líquida): 0 m2; Área da Superfície do Revestimento do Pilar (Líquida): 0 m2; Área da Superfície do Topo do Revestimento do Pilar (Líquida): 0 m2; Perímetro do Perfil da Coluna (base): 1500 mm; Volume do Revestimento do Pilar (Líquido): 0 m3
Component Quantities - Concreto Armado Moldado in Loco - Estrutural, Massa: 572.4 kg; Concreto Armado Moldado in Loco - Estrutural, Espessura do Componente: 600 mm; Concreto Armado Moldado in Loco - Estrutural, Altura do Componente Retangular: 150 mm; Concreto Armado Moldado in Loco - Estrutural, Largura do Componente Retangular: 600 mm; Concreto Armado Moldado in Loco - Estrutural, Área de Seção Transversal do Componente: 0.09 m2; Concreto Armado Moldado in Loco - Estrutural, Volume Componente (Líquido): 0.2385 m3; Concreto Armado Moldado in Loco - Estrutural, Volume do componente (Bruto): 0.2385 m3
Name | In | ID Dinâmico por Classificação | IsExternal | Elevação à Origem do Projeto (mm) = Elevação ao 1º Nível de Referência (mm) = Elevação ao 2º Nível de Referência (mm) = Elevação ao Nível do Mar (mm) = Elevação da Base Ao Primeiro Nível de Referência (mm) = Elevação da Base À Cota Zero (mm) = Elevação da Base Ao Nível do Mar (mm) = Elevação da Base Ao Segundo Nível de Referência (mm) | Elevação do Topo ao Primeiro Nível de Referência (mm) = Elevação do Topo À Cota Zero (mm) = Elevação do Topo Ao Nível do Mar (mm) = Elevação do Topo Ao Segundo Nível de Referência (mm)
PILAR-017 | Pavimento Terreo | Pilar -017 | yes | -2650 | 0
PILAR-015 | Pavimento Terreo | Pilar -015 | yes | -2650 | 0
PILAR-006 | Pavimento Terreo | Pilar -006 | yes | -2650 | 0
PILAR-007 | Pavimento Terreo | Pilar -007 | yes | -2650 | 0
PILAR-016 | Pavimento Terreo | Pilar -016 | yes | -2650 | 0
PILAR-011 | Pavimento Terreo | Pilar -011 | yes | -2650 | 0
PILAR-010 | Pavimento Terreo | Pilar -010 | yes | -2650 | 0
PILAR-009 | Pavimento Terreo | Pilar -009 | yes | -2650 | 0
PILAR-008 | Pavimento Terreo | Pilar -008 | yes | -2650 | 0
PILAR-013 | Pavimento Terreo | Pilar -013 | yes | -2650 | 0
PILAR-014 | Pavimento Terreo | Pilar -014 | yes | -2650 | 0
PILAR-012 | Pavimento Terreo | Pilar -012 | yes | -2650 | 0
APTO4-PILAR-001 | Primeiro Pavimento | Pilar -001 | yes | 0 | 2650
APTO4-PILAR-000 | Primeiro Pavimento | Pilar -000 | yes | 0 | 2650
APTO2-PILAR-000 | Primeiro Pavimento | Pilar -000 | yes | 0 | 2650
APTO2-PILAR-001 | Primeiro Pavimento | Pilar -001 | yes | 0 | 2650
APTO3-PILAR-000 | Primeiro Pavimento | Pilar -000 | yes | 0 | 2650
APTO3-PILAR-001 | Primeiro Pavimento | Pilar -001 | yes | 0 | 2650
APTO1-PILAR-001 | Primeiro Pavimento | Pilar -001 | yes | 0 | 2650
APTO1-PILAR-000 | Primeiro Pavimento | Pilar -000 | yes | 0 | 2650
CIRC1-PILAR-004 | Primeiro Pavimento | Pilar -004 | no | 0 | 2650
CIRC1-PILAR-002 | Primeiro Pavimento | Pilar -002 | no | 0 | 2650
CIRC1-PILAR-003 | Primeiro Pavimento | Pilar -003 | no | 0 | 2650
CIRC1-PILAR-005 | Primeiro Pavimento | Pilar -005 | no | 0 | 2650
CIRC2-PILAR-004 | Segundo Pavimento | Pilar -004 | no | 2650 | 5300
APTO5-PILAR-000 | Segundo Pavimento | Pilar -000 | yes | 2650 | 5300
APTO5-PILAR-001 | Segundo Pavimento | Pilar -001 | yes | 2650 | 5300
CIRC2-PILAR-003 | Segundo Pavimento | Pilar -003 | no | 2650 | 5300
CIRC2-PILAR-005 | Segundo Pavimento | Pilar -005 | no | 2650 | 5300
APTO6-PILAR-000 | Segundo Pavimento | Pilar -000 | yes | 2650 | 5300
APTO6-PILAR-001 | Segundo Pavimento | Pilar -001 | yes | 2650 | 5300
APTO7-PILAR-000 | Segundo Pavimento | Pilar -000 | yes | 2650 | 5300
APTO7-PILAR-001 | Segundo Pavimento | Pilar -001 | yes | 2650 | 5300
APTO8-PILAR-000 | Segundo Pavimento | Pilar -000 | yes | 2650 | 5300
APTO8-PILAR-001 | Segundo Pavimento | Pilar -001 | yes | 2650 | 5300
CIRC2-PILAR-002 | Segundo Pavimento | Pilar -002 | no | 2650 | 5300
CIRC3-PILAR-002 | Terceiro Pavimento | Pilar -002 | no | 5300 | 7950
CIRC3-PILAR-004 | Terceiro Pavimento | Pilar -004 | no | 5300 | 7950
CIRC3-PILAR-003 | Terceiro Pavimento | Pilar -003 | no | 5300 | 7950
CIRC3-PILAR-005 | Terceiro Pavimento | Pilar -005 | no | 5300 | 7950
APTO9-PILAR-000 | Terceiro Pavimento | Pilar -000 | yes | 5300 | 7950
APTO9-PILAR-001 | Terceiro Pavimento | Pilar -001 | yes | 5300 | 7950
APTO10-PILAR-000 | Terceiro Pavimento | Pilar -000 | yes | 5300 | 7950
APTO10-PILAR-001 | Terceiro Pavimento | Pilar -001 | yes | 5300 | 7950
APTO11-PILAR-000 | Terceiro Pavimento | Pilar -000 | yes | 5300 | 7950
APTO11-PILAR-001 | Terceiro Pavimento | Pilar -001 | yes | 5300 | 7950
APTO12-PILAR-000 | Terceiro Pavimento | Pilar -000 | yes | 5300 | 7950
APTO12-PILAR-001 | Terceiro Pavimento | Pilar -001 | yes | 5300 | 7950

# IfcDoor: Porta 25 (30)
Type - OperationType: SINGLE_SWING_LEFT; ParameterTakesPrecedence: no; Sizeable: no
Type - Door Lining Properties - LiningThickness: 50 mm
Type - Door Panel Properties - Panel 1 - PanelDepth: 30 mm; PanelOperation: SWINGING; PanelWidth: 1; PanelPosition: MIDDLE
OverallHeight: 2100 mm; Classification: Porta (Classificação ARCHICAD); 3E 20 02 02 04 Porta de girar (NBR 15965-5 3E)
Pset_DoorCommon - ThermalTransmittance: 0
CLASSIFICAÇÕES GERAIS - Transmissão Sonora: 0
INFORMAÇÕES DO PRODUTO - Data de Aquisição: DD/MM/YYYY
FABRICAÇÃO - Data de Fabricação: DD/MM/YYYY; Site do Produto: www.graphisoft.com
GARANTIA - Ínicio da Garantia: DD/MM/YYYY; Fim da Garantia: DD/MM/YYYY
AC_Pset_RenovationAndPhasing - Renovation Status: Existing
BaseQuantities - Height: 2100 mm
ArchiCADQuantities - Altura: 2100 mm; Elevação ao Piso: 0 mm; Afastamento da Origem: 0 mm; Elevação do Topo Ao Piso de Origem: 2100 mm; P/J Altura do Vão no Lado Oposto do Requadro: 2100 mm; P/J Altura do Vão no Lado do Requadro: 2100 mm; P/J Altura do Vão Nominal no Lado Oposto do Requadro: 2100 mm; P/J Altura do Vão Nominal no Lado do Requadro: 2100 mm; Altura da Soleira/Peitoril ou Padieira: 0 mm; P/J Altura Nominal do Parapeito: 0 mm; P/J Altura do Parapeito no Lado do Requadro: 0 mm; P/J Altura do Parapeito no Lado Oposto do Requadro: 0 mm; P/J Altura Nominal da Padieira: 2100 mm; P/J Altura da Padiera no Lado Oposto do Requadro: 2100 mm; P/J Altura da Padiera no Lado do Requadro: 2100 mm
AC_Equantity_Porta_25 - Altura: 2100 mm; Dimensão Z: 1000 mm; Nível da Base: 1000 mm; Nível do Topo: 0 mm; Altura Peitoril ao Piso Atual: 0 mm; Abertura para o Núcleo da Parede: 0 mm; Nova Largura Direita da Trama de Parede: 150 mm; Nova Largura Esquerda da Trama de Parede: 150 mm; Altura Ombro: 1840 mm; Luz Lateral com 1 Largura (gs_sidelight_width_right): 0 mm; Luz Lateral com 1 Largura (gs_sidelight_width_right_half): 150 mm; Luz Lateral com 1 Largura (gs_sidelight_width_right_orig): 300 mm; Luz Lateral com 1 Altura de Soleira: 0 mm; Luz Lateral com 2 Larguras (gs_sidelight_width_left): 0 mm; Luz Lateral com 2 Larguras (gs_sidelight_width_left_half): 300 mm; Luz Lateral com 2 Larguras (gs_sidelight_width_left_orig): 600 mm; Luz Lateral com 2 Alturas de Soleira: 0 mm; Altura Bandeira: 300 mm; Distância Eixo Pivot: 275 mm; Tolerância Lateral 1: 0 mm; Tolerância Lateral 1 Inferior: 0 mm; Tolerância Base Luz Lateral Base1: 0 mm; Tolerância Lateral 2: 0 mm; Tolerância Lateral 2 Inferior: 0 mm; Tolerância Base 2 Luz Lateral: 0 mm; Tolerância Superior: 0 mm; Tolerância Inferior: 0 mm; Altura de Vão: 2100 mm; Altura Face de Vão: 2100 mm; Altura Unidade: 2100 mm; Altura Saída: 2050 mm; Altura Nominal da Folha: 2060 mm; Espessura Batente: 115 mm; Espessura Interior Moldura: 115 mm; Afastam. Folha: 0 mm; Largura Batente: 50 mm; Batente Sobredimensionado: 10 mm; Espessura do Batente Externo: 10 mm; Largura Moldura Lado 1: 40 mm; Largura Moldura Meio Lado 1: 40 mm; Largura Moldura Inferior Lado 1: 40 mm; Largura Batente Lado 2: 40 mm; Largura Moldura Meio Lado 2: 40 mm; Largura Moldura Inferior Lado 2: 40 mm; Largura Moldura Bandeira (gs_frame_width_transom): 40 mm; Largura Batente Cimo: 40 mm; Espessura Porta de Paragem: 32 mm; Largura Porta de Paragem: 16 mm; Largura Rebaixo: 10 mm; Profundidade do Rebaixo da folha em 3D: 30 mm; Largura do Rebaixo da Luz Lateral e Bandeira: 10 mm; Profund. de Rebaixo da Luz Lateral e Bandeira: 18 mm; Espessura Folha: 30 mm; Largura Batente Folha Lateral: 100 mm; Largura Moldura Folha Direita: 100 mm; Largura Moldura Folha Esquerda: 100 mm; Largura Batente Folha Inferior: 200 mm; Largura Batente Folha Superior: 100 mm; Largura Folha Interna: 25 mm; Recorte inferior da folha: 0 mm; Largura Grelha (gs_grid_w): 12 mm; Espessura Grelha (gs_grid_thk): 25 mm; Espessura Vidro: 12 mm; Altura Maçaneta: 1000 mm; Posição Maçaneta: 50 mm; Altura Proteção Borda: 100 mm; Altura Divisão Horizontal Luz Lateral Lado 1: 900 mm; Altura Divisão Horizontal Luz Lateral Lado 2: 900 mm; Altura Divisão Horizontal Bandeira Meio: 900 mm; Altura Divisão Horizontal Bandeira Lado 1: 900 mm; Altura Divisão Horizontal Bandeira Lado 2: 900 mm; Espessura Batente Luz Lateral e Bandeira: 44 mm; Largura Moldura Bandeira (gs_sash_width): 67 mm; Largura batente Painel Lateral: 67 mm; Largura Grelha (gw): 20 mm; Espessura Grelha (gth): 25 mm; Largura Divisão Luz Lateral: 40 mm; Espessura Divisão Luz Lateral: 40 mm; Largura Arquitrave Principal: 20 mm; Largura Lado 1 (gs_tw_right_out): 70 mm; Largura Lado 2 (gs_tw_left_out): 50 mm; Largura Topo (gs_tw_top_out): 50 mm; Espessura de Parede (gs_trim_thk_out): 19 mm; Espessura na Abertura da Parede (gs_trim_width_out): 25 mm; Paralelas (gs_trim_offs_out): 15 mm; Bordo (gs_trim_jambext_nosing_out): 50 mm; Saliência Superior (gs_trimov_top_left_out): 0 mm; Saliência Superior (gs_trimov_top_right_out): 0 mm; Largura Lado 1 (gs_tw_right_in): 70 mm; Largura Lado 2 (gs_tw_left_in): 50 mm; Largura Topo (gs_tw_top_in): 50 mm; Espessura de Parede (gs_trim_thk_in): 19 mm; Espessura na Abertura da Parede (gs_trim_width_in): 25 mm; Paralelas (gs_trim_offs_in): 15 mm; Bordo (gs_trim_jambext_nosing_in): 50 mm; Saliência Superior (gs_trimov_top_left_in): 0 mm; Saliência Superior (gs_trimov_top_right_in): 0 mm; Espessura Soleira: 12 mm; Largura Soleira: 10 mm; Espessura Externa Soleira: 5.80738 mm; Testeira Externa Soleira: 10 mm; Avanço Soleira Interna: 10 mm; Saliência Lateral Externo: 0 mm; Saliência Lateral Interno: 0 mm; Espessura Peitoril: 100 mm; Espessura Lateral da Frente Peitoril: 15 mm; Elevação Peitoril: 5 mm; Recobrimento Goteira Peitoril: 20 mm; Largura Goteira Peitoril: 30 mm; Testeira Peitoril: 45 mm; Avanço Lateral Peitoril 1: 0 mm; Avanço Lateral Peitoril 2: 0 mm; Inclinação do Parapeito: 35 mm; Largura Topo Parapeito: 10 mm; Altura Topo Peitoril: 10 mm; Inclin. Peitoril da Parede: 0 mm; Profund. Vão Posterior (gs_sill_holeDepthBehind): 0 mm; Largura Peitoril: 80 mm; Espessura do Tijolo (gs_brick_sill_br_thk): 65 mm; Espessura de Argamassa (gs_brick_sill_mort_thk): 15 mm; Largura Peitoril Int.: 100 mm; Espessura Peitoril Int.: 25 mm; Peitoril Int. Arredondado: 30 mm; Avanço Lateral Peitoril Interno 1: 0 mm; Avanço Lateral Peitoril Interno 2: 0 mm; Inclinação do Parapeito Int.: 0 mm; Altura Perfil: 65 mm; Espessura Perfil: 110 mm; Altura Painel: 2088 mm; Afast. Interior: 20 mm; Profund. Fechamento: 0 mm; Largura Batente Extra: 40 mm; Espess. Batente Extra: 30 mm; Largura Barra:: 30 mm; Comprim. Vara Suspensa: 20 mm; Raio Vara Suspensa: 5 mm; Distância Painel: 6 mm; Saliência Exterior: 0 mm; Largura Painel Interior: 120 mm; Comprim. Abertura 3D: 1500 mm; Comprim. Fechado 3D: 0 mm; Comprimento 1 Abertura 3D: 560 mm; Comprimento 2 Abertura 3D: 140 mm; Altura Abertura 3D: 1500 mm; Altura Fechado 3D: 0 mm; Espessura Painel: 50 mm; Largura Estrutura Painel: 50 mm; Largura Moldura Inferior: 50 mm; Largura Painel: 388 mm; Espess. de Enchimento de Painel: 10 mm; Espessura da Veneziana: 10 mm; Largura Grelha Ventilação: 40 mm; Largura Divisor Moldura Horiz.: 50 mm; Largura de Divisor Moldura Vert.: 50 mm; Raio do Vão: 10 mm; Largura Bordo Vertical: 100 mm; Largura Estrutura Z: 50 mm; Espessura Estrutura Z: 25 mm; Espess. Placas Verticais: 25 mm; Espess. Placas Horizontais: 25 mm; Largura Aprox. Placas Verticais: 80 mm; Largura Aprox. Placas Horizontais: 115 mm; Altura Caixa (gs_shutRoll_boxHeight): 200 mm; Profund. Caixa (gs_shutRoll_boxWidth): 150 mm; Afast. Caixa Esq.: 0 mm; Afast. Caixa Dir.: 0 mm; Profund. Anteparos: 72.5 mm; Distância da Parede (gs_shutRoll_distFromWall): 0 mm; Distância da Padieira (gs_shutRoll_distFromHead): 0 mm; Largura da Ripa: 50 mm; Altura Caixa (gs_shutLam_boxHeight): 200 mm; Profund. Caixa (gs_shutLam_boxWidth): 150 mm; Largura Capa: 0 mm; Distância da Parede (gs_shutLam_distFromWall): 0 mm; Distância da Padieira (gs_shutLam_distFromHead): 0 mm; Largura Segmento (gs_shutLam_segmentWidth): 60 mm; Altura Caixa (gs_shutLam2_boxHeight): 60 mm; Largura Caixa: 60 mm; Distância da Janela: 60 mm; Distância da Padieira (gs_shutLam2_distFromHead): 60 mm; Altura do Eixo da Caixa da Padieira: 0 mm; Largura Segmento (gs_shutLam2_segmentWidth): 60 mm; Distância entre Arco e Porta: 0 mm; Arco Alvenaria Avanço Lado 1: 0 mm; Arco Alvenaria Avanço Lado 2: 0 mm; Espelho do Arco de Alvenaria: 30 mm; Projeção do Arco de Alvenaria: 0 mm; Altura do Arco de Alvenaria: 250 mm; Profundidade do Arco de Alvenaria: 120 mm; Profund. Vão Posterior (gs_masonry_arch_rearHoleDepth): 0 mm; Espessura do Tijolo (gs_masonry_arch_brick_thk): 65 mm; Espessura de Argamassa (gs_masonry_arch_mort_thk): 10 mm; Largura Fecho: 100 mm; Sobredimensão Fecho: 0 mm; Projeção Fecho: 10 mm; Profund. Face de Vão (gs_wido_sill): 0 mm; Profund. Face de Vão (AC_wido_sill): 0 mm; Profund. Ombreira: 60 mm; Profund. Ombreira Lado 2: 60 mm; Profund. Ombreira Inferior Lado 1: 60 mm; Profund. Ombreira Inferior Lado 2: 60 mm; Profund. Ombreira Interior Lado 2 (gs_reveal_splayed_innerLeft): 60 mm; Profund. Ombreira Interior (gs_reveal_splayed_innerRight): 60 mm; Profund. Ombreira Interior (gs_reveal_double_innerRight): 60 mm; Profund. Ombreira Interior Lado 2 (gs_reveal_double_innerLeft): 60 mm; Profund. Ombreira Interior Inferior Lado 1: 60 mm; Profund. Ombreira Interior Inferior Lado 2: 60 mm; Profund. do Topo: 60 mm; Profundidade Peitoril: 60 mm; Profund. Peitoril Lado 1: 60 mm; Profund. Peitoril Lado 2: 60 mm; Profundidade Padieira Interior (gs_reveal_splayed_innerTop): 60 mm; Profundidade Peitoril Interior (gs_reveal_splayed_innerBottom): 0 mm; Profundidade Padieira Interior (gs_reveal_double_innerTop): 60 mm; Profundidade Peitoril Interior (gs_reveal_double_innerBottom): 0 mm; Profund. Peitoril Interior Lado 1: 0 mm; Profund. Peitoril Interior Lado 2: 0 mm; Profund. Batente Exterior: 80 mm; Limite Espess. Reboco: 40 mm; Distância de Camada do Encerram.: 0 mm; Largura do Fecho: 38 mm; Espessura do Fecho: 100 mm; Espessura da Camada: 25 mm; Espessura do Perfil: 150 mm; Espessura Personal.: 15 mm; Saliência Camada para Espess. Batente: 0 mm; Sobred. Abertura Esquerda: 0 mm; Sobred. Direita Abertura: 0 mm; Sobred. Topo Abertura: 0 mm; Sobred. Base Abertura: 0 mm; Largura Abertura 3D: 0 mm; Largura Abertura em 3D no Lado 2: 0 mm; Largura Abertura 2D: 0 mm; Largura Abertura em 2D no Lado 2: 0 mm; Distância Abertura 1 Caixilho Principal Lado 1: 0 mm; Distância Abertura 2 Caixilho Principal Lado 1: 0 mm; Distância Abertura 1 Caixilho Principal Lado 2: 0 mm; Distância Abertura 2 Caixilho Principal Lado 2: 0 mm; Distância Abertura 1 Bandeira Meio: 0 mm; Distância Abertura 2 Bandeira Meio: 0 mm; Distância Abertura 1 Bandeira Lado 1: 0 mm; Distância Abertura 2 Bandeira Lado 1: 0 mm; Distância Abertura 1 Bandeira Lado 2: 0 mm; Distância Abertura 2 Bandeira Lado 2: 0 mm; Largura 2 de Lado de Abertura: 200 mm; Largura 1 de Lado de Abertura: 100 mm; Profund. Lado de Abertura: 1000 mm; Largura 2 de Lado Oposto: 100 mm; Largura 1 de Lado Oposto: 100 mm; Profund. Lado Oposto: 1000 mm; Sobred. Abertura Esq. AC: 0 mm; Sobred. Abertura Dir. AC: 0 mm; Sobred. Padieira AC: 0 mm; Sobred. Abertura Base AC: 0 mm; ID Afastamento X: 0 mm; ID Afastamento Y: 0 mm; Afastamento X Texto Personalizado: 0 mm; Afastasmento Y Texto Personalizado: 0 mm; Afastamento X Largura da Folha: 0 mm; Afastamento Y Largura da Folha: 0 mm
Name | In | OverallWidth (mm) = Width (mm) = ArchiCADQuantities, Largura (mm) = P/J Largura do Vão no Lado Oposto do Requadro (mm) = P/J Largura do Vão no Lado do Requadro (mm) = P/J Largura do Vão Nominal no Lado Oposto do Requadro (mm) = P/J Largura do Vão Nominal no Lado do Requadro (mm) = AC_Equantity_Porta_25, Largura (mm) = Largura de Vão (mm) = Largura Face de Vão (mm) = Largura Unidade (mm) | IsExternal | Localização do Produto no Projeto | ID de Aberturas com Master ID | ID Dinâmico por Classificação | Perimeter (mm) | Area (m2) = P/J Área de Superfície Nominal do Vão (m2) = Área da Superfície da Abertura no Lado do Requadro da J/P (m2) = Área da Superfície da Abertura no Lado Oposto ao Requadro da J/P (m2) = P/J Área da Superfície do Vão Nominal no Lado do Requadro (m2) = P/J Área da Superfície do Vão Nominal no Lado Oposto do Requadro (m2) | Volume (m3) = NetVolume (m3) = Volume (Líquido) (m3) = Component, Volume Componente (Líquido) (m3) = Component, Volume do componente (Bruto) (m3) | Depth (mm) = Espessura da Parede (mm) = Espessura do Batente (mm) = Espessura Moldura Real (mm) | Elevação à Origem do Projeto (mm) = Elevação ao 1º Nível de Referência (mm) = Elevação ao 2º Nível de Referência (mm) = Elevação ao Nível do Mar (mm) | Área da Superfície (m2) = Área da Superfície da Base (Líquida) (m2) = Abertura Área da Superfície L/D (m2) | Elevação do Topo ao Primeiro Nível de Referência (mm) = Elevação do Topo À Cota Zero (mm) = Elevação do Topo Ao Nível do Mar (mm) = Elevação do Topo Ao Segundo Nível de Referência (mm) | Elevação da Base Ao Primeiro Nível de Referência (mm) = Elevação da Base À Cota Zero (mm) = Elevação da Base Ao Nível do Mar (mm) = Elevação da Base Ao Segundo Nível de Referência (mm) | Elevação da Base Ao Piso de Origem (mm) | Abertura Volume de Vão L/D (m3) = P/J Volume Nominal da Abertura (m3) | Largura Saída (mm) | Largura Nominal da Folha (mm) | Largura Nominal da Folha no Lado 1 (mm)
APTO4-PORTA-001 | Primeiro Pavimento | 900 | no | Projeto: CECAP GuarulhosLocal: Piso: Primeiro Pavimento Cômodo: | APTO4-001 | Porta -001 | 6000 | 1.89 | 0.0592503 | 40 | 0 | 4.51191 | 2100 | -2.44929e-15 | -2.44929e-15 | 0.0756 | 800 | 820 | 360
APTO4-PORTA-003 | Primeiro Pavimento | 710 | no | Projeto: CECAP GuarulhosLocal: Piso: Primeiro Pavimento Cômodo: WC | APTO4-28003 | Porta -003 | 5620 | 1.491 | 0.0592103 | 90 | 0 | 4.17951 | 2100 | -5.51091e-15 | -5.51091e-15 | 0.13419 | 610 | 630 | 315
APTO4-PORTA-004 | Primeiro Pavimento | 900 | yes | Projeto: CECAP GuarulhosLocal: Piso: Primeiro Pavimento Cômodo: SALA | APTO4-27004 | Porta -004 | 6000 | 1.89 | 0.0842503 | 140 | 0 | 5.54191 | 2100 | -8.57253e-15 | -8.57253e-15 | 0.2646 | 800 | 820 | 360
APTO3-PORTA-002 | Primeiro Pavimento | 900 | no | Projeto: CECAP GuarulhosLocal: Piso: Primeiro Pavimento Cômodo: | APTO3-002 | Porta -002 | 6000 | 1.89 | 0.0592503 | 40 | 0 | 4.51191 | 2100 | -2.44929e-15 | -2.44929e-15 | 0.0756 | 800 | 820 | 360
APTO3-PORTA-000 | Primeiro Pavimento | 900 | no | Projeto: CECAP GuarulhosLocal: Piso: Primeiro Pavimento Cômodo: | APTO3-000 | Porta -000 | 6000 | 1.89 | 0.0592503 | 40 | 0 | 4.51191 | 2100 | -2.44929e-15 | -2.44929e-15 | 0.0756 | 800 | 820 | 360
APTO2-PORTA-002 | Primeiro Pavimento | 900 | no | Projeto: CECAP GuarulhosLocal: Piso: Primeiro Pavimento Cômodo: | APTO2-002 | Porta -002 | 6000 | 1.89 | 0.0592503 | 40 | 0 | 4.51191 | 2100 | -2.44929e-15 | -2.44929e-15 | 0.0756 | 800 | 820 | 360
APTO2-PORTA-000 | Primeiro Pavimento | 900 | no | Projeto: CECAP GuarulhosLocal: Piso: Primeiro Pavimento Cômodo: | APTO2-000 | Porta -000 | 6000 | 1.89 | 0.0592503 | 40 | 0 | 4.51191 | 2100 | -2.44929e-15 | -2.44929e-15 | 0.0756 | 800 | 820 | 360
APTO1-PORTA-001 | Primeiro Pavimento | 900 | no | Projeto: CECAP GuarulhosLocal: Piso: Primeiro Pavimento Cômodo: | APTO1-001 | Porta -001 | 6000 | 1.89 | 0.0592503 | 40 | 0 | 4.51191 | 2100 | -2.44929e-15 | -2.44929e-15 | 0.0756 | 800 | 820 | 360
APTO1-PORTA-004 | Primeiro Pavimento | 900 | yes | Projeto: CECAP GuarulhosLocal: Piso: Primeiro Pavimento Cômodo: SALA | APTO1-06004 | Porta -004 | 6000 | 1.89 | 0.0842503 | 140 | 0 | 5.54191 | 2100 | -8.57253e-15 | -8.57253e-15 | 0.2646 | 800 | 820 | 360
APTO1-PORTA-003 | Primeiro Pavimento | 710 | no | Projeto: CECAP GuarulhosLocal: Piso: Primeiro Pavimento Cômodo: WC | APTO1-07003 | Porta -003 | 5620 | 1.491 | 0.0592103 | 90 | 0 | 4.17951 | 2100 | -5.51091e-15 | -5.51091e-15 | 0.13419 | 610 | 630 | 315
APTO5-PORTA-001 | Segundo Pavimento | 900 | no | Projeto: CECAP GuarulhosLocal: Piso: Segundo Pavimento Cômodo: | APTO5-001 | Porta -001 | 6000 | 1.89 | 0.0592503 | 40 | 2650 | 4.51191 | 4750 | 2650 | 0 | 0.0756 | 800 | 820 | 360
APTO5-PORTA-003 | Segundo Pavimento | 710 | no | Projeto: CECAP GuarulhosLocal: Piso: Segundo Pavimento Cômodo: WC | APTO5-13003 | Porta -003 | 5620 | 1.491 | 0.0592103 | 90 | 2650 | 4.17951 | 4750 | 2650 | 0 | 0.13419 | 610 | 630 | 315
APTO5-PORTA-004 | Segundo Pavimento | 900 | yes | Projeto: CECAP GuarulhosLocal: Piso: Segundo Pavimento Cômodo: SALA | APTO5-09004 | Porta -004 | 6000 | 1.89 | 0.0842503 | 140 | 2650 | 5.54191 | 4750 | 2650 | 0 | 0.2646 | 800 | 820 | 360
APTO6-PORTA-002 | Segundo Pavimento | 900 | no | Projeto: CECAP GuarulhosLocal: Piso: Segundo Pavimento Cômodo: | APTO6-002 | Porta -002 | 6000 | 1.89 | 0.0592503 | 40 | 2650 | 4.51191 | 4750 | 2650 | 0 | 0.0756 | 800 | 820 | 360
APTO6-PORTA-000 | Segundo Pavimento | 900 | no | Projeto: CECAP GuarulhosLocal: Piso: Segundo Pavimento Cômodo: | APTO6-000 | Porta -000 | 6000 | 1.89 | 0.0592503 | 40 | 2650 | 4.51191 | 4750 | 2650 | 0 | 0.0756 | 800 | 820 | 360
APTO7-PORTA-002 | Segundo Pavimento | 900 | no | Projeto: CECAP GuarulhosLocal: Piso: Segundo Pavimento Cômodo: | APTO7-002 | Porta -002 | 6000 | 1.89 | 0.0592503 | 40 | 2650 | 4.51191 | 4750 | 2650 | 0 | 0.0756 | 800 | 820 | 360
APTO7-PORTA-000 | Segundo Pavimento | 900 | no | Projeto: CECAP GuarulhosLocal: Piso: Segundo Pavimento Cômodo: | APTO7-000 | Porta -000 | 6000 | 1.89 | 0.0592503 | 40 | 2650 | 4.51191 | 4750 | 2650 | 0 | 0.0756 | 800 | 820 | 360
APTO8-PORTA-003 | Segundo Pavimento | 710 | no | Projeto: CECAP GuarulhosLocal: Piso: Segundo Pavimento Cômodo: WC | APTO8-13003 | Porta -003 | 5620 | 1.491 | 0.0592103 | 90 | 2650 | 4.17951 | 4750 | 2650 | 0 | 0.13419 | 610 | 630 | 315
APTO8-PORTA-004 | Segundo Pavimento | 900 | yes | Projeto: CECAP GuarulhosLocal: Piso: Segundo Pavimento Cômodo: CORREDOR | APTO8-33004 | Porta -004 | 6000 | 1.89 | 0.0842503 | 140 | 2650 | 5.54191 | 4750 | 2650 | 0 | 0.2646 | 800 | 820 | 360
APTO8-PORTA-001 | Segundo Pavimento | 900 | no | Projeto: CECAP GuarulhosLocal: Piso: Segundo Pavimento Cômodo: | APTO8-001 | Porta -001 | 6000 | 1.89 | 0.0592503 | 40 | 2650 | 4.51191 | 4750 | 2650 | 0 | 0.0756 | 800 | 820 | 360
APTO9-PORTA-003 | Terceiro Pavimento | 710 | no | Projeto: CECAP GuarulhosLocal: Piso: Terceiro Pavimento Cômodo: WC | APTO9-13003 | Porta -003 | 5620 | 1.491 | 0.0592103 | 90 | 5300 | 4.17951 | 7400 | 5300 | 0 | 0.13419 | 610 | 630 | 315
APTO9-PORTA-004 | Terceiro Pavimento | 900 | yes | Projeto: CECAP GuarulhosLocal: Piso: Terceiro Pavimento Cômodo: SALA | APTO9-09004 | Porta -004 | 6000 | 1.89 | 0.0842503 | 140 | 5300 | 5.54191 | 7400 | 5300 | 0 | 0.2646 | 800 | 820 | 360
APTO9-PORTA-001 | Terceiro Pavimento | 900 | no | Projeto: CECAP GuarulhosLocal: Piso: Terceiro Pavimento Cômodo: | APTO9-001 | Porta -001 | 6000 | 1.89 | 0.0592503 | 40 | 5300 | 4.51191 | 7400 | 5300 | 0 | 0.0756 | 800 | 820 | 360
APTO10-PORTA-002 | Terceiro Pavimento | 900 | no | Projeto: CECAP GuarulhosLocal: Piso: Terceiro Pavimento Cômodo: | APTO10-002 | Porta -002 | 6000 | 1.89 | 0.0592503 | 40 | 5300 | 4.51191 | 7400 | 5300 | 0 | 0.0756 | 800 | 820 | 360
APTO10-PORTA-000 | Terceiro Pavimento | 900 | no | Projeto: CECAP GuarulhosLocal: Piso: Terceiro Pavimento Cômodo: | APTO10-000 | Porta -000 | 6000 | 1.89 | 0.0592503 | 40 | 5300 | 4.51191 | 7400 | 5300 | 0 | 0.0756 | 800 | 820 | 360
APTO11-PORTA-002 | Terceiro Pavimento | 900 | no | Projeto: CECAP GuarulhosLocal: Piso: Terceiro Pavimento Cômodo: | APTO11-002 | Porta -002 | 6000 | 1.89 | 0.0592503 | 40 | 5300 | 4.51191 | 7400 | 5300 | 0 | 0.0756 | 800 | 820 | 360
APTO11-PORTA-000 | Terceiro Pavimento | 900 | no | Projeto: CECAP GuarulhosLocal: Piso: Terceiro Pavimento Cômodo: | APTO11-000 | Porta -000 | 6000 | 1.89 | 0.0592503 | 40 | 5300 | 4.51191 | 7400 | 5300 | 0 | 0.0756 | 800 | 820 | 360
APTO12-PORTA-003 | Terceiro Pavimento | 710 | no | Projeto: CECAP GuarulhosLocal: Piso: Terceiro Pavimento Cômodo: WC | APTO12-13003 | Porta -003 | 5620 | 1.491 | 0.0592103 | 90 | 5300 | 4.17951 | 7400 | 5300 | 0 | 0.13419 | 610 | 630 | 315
APTO12-PORTA-004 | Terceiro Pavimento | 900 | yes | Projeto: CECAP GuarulhosLocal: Piso: Terceiro Pavimento Cômodo: SALA | APTO12-09004 | Porta -004 | 6000 | 1.89 | 0.0842503 | 140 | 5300 | 5.54191 | 7400 | 5300 | 0 | 0.2646 | 800 | 820 | 360
APTO12-PORTA-001 | Terceiro Pavimento | 900 | no | Projeto: CECAP GuarulhosLocal: Piso: Terceiro Pavimento Cômodo: | APTO12-001 | Porta -001 | 6000 | 1.89 | 0.0592503 | 40 | 5300 | 4.51191 | 7400 | 5300 | 0 | 0.0756 | 800 | 820 | 360

# IfcDoor: Porta 25 (30)
Type - OperationType: SINGLE_SWING_RIGHT; ParameterTakesPrecedence: no; Sizeable: no
Type - Door Lining Properties - LiningThickness: 50 mm
Type - Door Panel Properties - Panel 1 - PanelDepth: 30 mm; PanelOperation: SWINGING; PanelWidth: 1; PanelPosition: MIDDLE
OverallHeight: 2100 mm; Classification: Porta (Classificação ARCHICAD); 3E 20 02 02 04 Porta de girar (NBR 15965-5 3E)
Pset_DoorCommon - ThermalTransmittance: 0
CLASSIFICAÇÕES GERAIS - Transmissão Sonora: 0
INFORMAÇÕES DO PRODUTO - Data de Aquisição: DD/MM/YYYY
FABRICAÇÃO - Data de Fabricação: DD/MM/YYYY; Site do Produto: www.graphisoft.com
GARANTIA - Ínicio da Garantia: DD/MM/YYYY; Fim da Garantia: DD/MM/YYYY
AC_Pset_RenovationAndPhasing - Renovation Status: Existing
BaseQuantities - Height: 2100 mm
ArchiCADQuantities - Altura: 2100 mm; Elevação ao Piso: 0 mm; Afastamento da Origem: 0 mm; Elevação do Topo Ao Piso de Origem: 2100 mm; P/J Altura do Vão no Lado Oposto do Requadro: 2100 mm; P/J Altura do Vão no Lado do Requadro: 2100 mm; P/J Altura do Vão Nominal no Lado Oposto do Requadro: 2100 mm; P/J Altura do Vão Nominal no Lado do Requadro: 2100 mm; Altura da Soleira/Peitoril ou Padieira: 0 mm; P/J Altura Nominal do Parapeito: 0 mm; P/J Altura do Parapeito no Lado do Requadro: 0 mm; P/J Altura do Parapeito no Lado Oposto do Requadro: 0 mm; P/J Altura Nominal da Padieira: 2100 mm; P/J Altura da Padiera no Lado Oposto do Requadro: 2100 mm; P/J Altura da Padiera no Lado do Requadro: 2100 mm
AC_Equantity_Porta_25 - Altura: 2100 mm; Dimensão Z: 1000 mm; Nível da Base: 1000 mm; Nível do Topo: 0 mm; Altura Peitoril ao Piso Atual: 0 mm; Abertura para o Núcleo da Parede: 0 mm; Nova Largura Direita da Trama de Parede: 150 mm; Nova Largura Esquerda da Trama de Parede: 150 mm; Altura Ombro: 1840 mm; Luz Lateral com 1 Largura (gs_sidelight_width_right): 0 mm; Luz Lateral com 1 Largura (gs_sidelight_width_right_half): 150 mm; Luz Lateral com 1 Largura (gs_sidelight_width_right_orig): 300 mm; Luz Lateral com 1 Altura de Soleira: 0 mm; Luz Lateral com 2 Larguras (gs_sidelight_width_left): 0 mm; Luz Lateral com 2 Larguras (gs_sidelight_width_left_half): 300 mm; Luz Lateral com 2 Larguras (gs_sidelight_width_left_orig): 600 mm; Luz Lateral com 2 Alturas de Soleira: 0 mm; Altura Bandeira: 300 mm; Distância Eixo Pivot: 275 mm; Tolerância Lateral 1: 0 mm; Tolerância Lateral 1 Inferior: 0 mm; Tolerância Base Luz Lateral Base1: 0 mm; Tolerância Lateral 2: 0 mm; Tolerância Lateral 2 Inferior: 0 mm; Tolerância Base 2 Luz Lateral: 0 mm; Tolerância Superior: 0 mm; Tolerância Inferior: 0 mm; Altura de Vão: 2100 mm; Altura Face de Vão: 2100 mm; Altura Unidade: 2100 mm; Altura Saída: 2050 mm; Altura Nominal da Folha: 2060 mm; Espessura Batente: 115 mm; Espessura Interior Moldura: 115 mm; Afastam. Folha: 0 mm; Largura Batente: 50 mm; Batente Sobredimensionado: 10 mm; Espessura do Batente Externo: 10 mm; Largura Moldura Lado 1: 40 mm; Largura Moldura Meio Lado 1: 40 mm; Largura Moldura Inferior Lado 1: 40 mm; Largura Batente Lado 2: 40 mm; Largura Moldura Meio Lado 2: 40 mm; Largura Moldura Inferior Lado 2: 40 mm; Largura Moldura Bandeira (gs_frame_width_transom): 40 mm; Largura Batente Cimo: 40 mm; Espessura Porta de Paragem: 32 mm; Largura Porta de Paragem: 16 mm; Largura Rebaixo: 10 mm; Profundidade do Rebaixo da folha em 3D: 30 mm; Largura do Rebaixo da Luz Lateral e Bandeira: 10 mm; Profund. de Rebaixo da Luz Lateral e Bandeira: 18 mm; Espessura Folha: 30 mm; Largura Batente Folha Lateral: 100 mm; Largura Moldura Folha Direita: 100 mm; Largura Moldura Folha Esquerda: 100 mm; Largura Batente Folha Inferior: 200 mm; Largura Batente Folha Superior: 100 mm; Largura Folha Interna: 25 mm; Recorte inferior da folha: 0 mm; Largura Grelha (gs_grid_w): 12 mm; Espessura Grelha (gs_grid_thk): 25 mm; Espessura Vidro: 12 mm; Altura Maçaneta: 1000 mm; Posição Maçaneta: 50 mm; Altura Proteção Borda: 100 mm; Altura Divisão Horizontal Luz Lateral Lado 1: 900 mm; Altura Divisão Horizontal Luz Lateral Lado 2: 900 mm; Altura Divisão Horizontal Bandeira Meio: 900 mm; Altura Divisão Horizontal Bandeira Lado 1: 900 mm; Altura Divisão Horizontal Bandeira Lado 2: 900 mm; Espessura Batente Luz Lateral e Bandeira: 44 mm; Largura Moldura Bandeira (gs_sash_width): 67 mm; Largura batente Painel Lateral: 67 mm; Largura Grelha (gw): 20 mm; Espessura Grelha (gth): 25 mm; Largura Divisão Luz Lateral: 40 mm; Espessura Divisão Luz Lateral: 40 mm; Largura Arquitrave Principal: 20 mm; Largura Lado 1 (gs_tw_right_out): 70 mm; Largura Lado 2 (gs_tw_left_out): 50 mm; Largura Topo (gs_tw_top_out): 50 mm; Espessura de Parede (gs_trim_thk_out): 19 mm; Espessura na Abertura da Parede (gs_trim_width_out): 25 mm; Paralelas (gs_trim_offs_out): 15 mm; Bordo (gs_trim_jambext_nosing_out): 50 mm; Saliência Superior (gs_trimov_top_left_out): 0 mm; Saliência Superior (gs_trimov_top_right_out): 0 mm; Largura Lado 1 (gs_tw_right_in): 70 mm; Largura Lado 2 (gs_tw_left_in): 50 mm; Largura Topo (gs_tw_top_in): 50 mm; Espessura de Parede (gs_trim_thk_in): 19 mm; Espessura na Abertura da Parede (gs_trim_width_in): 25 mm; Paralelas (gs_trim_offs_in): 15 mm; Bordo (gs_trim_jambext_nosing_in): 50 mm; Saliência Superior (gs_trimov_top_left_in): 0 mm; Saliência Superior (gs_trimov_top_right_in): 0 mm; Espessura Soleira: 12 mm; Largura Soleira: 10 mm; Espessura Externa Soleira: 5.80738 mm; Testeira Externa Soleira: 10 mm; Avanço Soleira Interna: 10 mm; Saliência Lateral Externo: 0 mm; Saliência Lateral Interno: 0 mm; Espessura Peitoril: 100 mm; Espessura Lateral da Frente Peitoril: 15 mm; Elevação Peitoril: 5 mm; Recobrimento Goteira Peitoril: 20 mm; Largura Goteira Peitoril: 30 mm; Testeira Peitoril: 45 mm; Avanço Lateral Peitoril 1: 0 mm; Avanço Lateral Peitoril 2: 0 mm; Inclinação do Parapeito: 35 mm; Largura Topo Parapeito: 10 mm; Altura Topo Peitoril: 10 mm; Inclin. Peitoril da Parede: 0 mm; Profund. Vão Posterior (gs_sill_holeDepthBehind): 0 mm; Largura Peitoril: 80 mm; Espessura do Tijolo (gs_brick_sill_br_thk): 65 mm; Espessura de Argamassa (gs_brick_sill_mort_thk): 15 mm; Largura Peitoril Int.: 100 mm; Espessura Peitoril Int.: 25 mm; Peitoril Int. Arredondado: 30 mm; Avanço Lateral Peitoril Interno 1: 0 mm; Avanço Lateral Peitoril Interno 2: 0 mm; Inclinação do Parapeito Int.: 0 mm; Altura Perfil: 65 mm; Espessura Perfil: 110 mm; Altura Painel: 2088 mm; Afast. Interior: 20 mm; Profund. Fechamento: 0 mm; Largura Batente Extra: 40 mm; Espess. Batente Extra: 30 mm; Largura Barra:: 30 mm; Comprim. Vara Suspensa: 20 mm; Raio Vara Suspensa: 5 mm; Distância Painel: 6 mm; Saliência Exterior: 0 mm; Largura Painel Interior: 120 mm; Comprim. Abertura 3D: 1500 mm; Comprim. Fechado 3D: 0 mm; Comprimento 1 Abertura 3D: 560 mm; Comprimento 2 Abertura 3D: 140 mm; Altura Abertura 3D: 1500 mm; Altura Fechado 3D: 0 mm; Espessura Painel: 50 mm; Largura Estrutura Painel: 50 mm; Largura Moldura Inferior: 50 mm; Largura Painel: 388 mm; Espess. de Enchimento de Painel: 10 mm; Espessura da Veneziana: 10 mm; Largura Grelha Ventilação: 40 mm; Largura Divisor Moldura Horiz.: 50 mm; Largura de Divisor Moldura Vert.: 50 mm; Raio do Vão: 10 mm; Largura Bordo Vertical: 100 mm; Largura Estrutura Z: 50 mm; Espessura Estrutura Z: 25 mm; Espess. Placas Verticais: 25 mm; Espess. Placas Horizontais: 25 mm; Largura Aprox. Placas Verticais: 80 mm; Largura Aprox. Placas Horizontais: 115 mm; Altura Caixa (gs_shutRoll_boxHeight): 200 mm; Profund. Caixa (gs_shutRoll_boxWidth): 150 mm; Afast. Caixa Esq.: 0 mm; Afast. Caixa Dir.: 0 mm; Profund. Anteparos: 72.5 mm; Distância da Parede (gs_shutRoll_distFromWall): 0 mm; Distância da Padieira (gs_shutRoll_distFromHead): 0 mm; Largura da Ripa: 50 mm; Altura Caixa (gs_shutLam_boxHeight): 200 mm; Profund. Caixa (gs_shutLam_boxWidth): 150 mm; Largura Capa: 0 mm; Distância da Parede (gs_shutLam_distFromWall): 0 mm; Distância da Padieira (gs_shutLam_distFromHead): 0 mm; Largura Segmento (gs_shutLam_segmentWidth): 60 mm; Altura Caixa (gs_shutLam2_boxHeight): 60 mm; Largura Caixa: 60 mm; Distância da Janela: 60 mm; Distância da Padieira (gs_shutLam2_distFromHead): 60 mm; Altura do Eixo da Caixa da Padieira: 0 mm; Largura Segmento (gs_shutLam2_segmentWidth): 60 mm; Distância entre Arco e Porta: 0 mm; Arco Alvenaria Avanço Lado 1: 0 mm; Arco Alvenaria Avanço Lado 2: 0 mm; Espelho do Arco de Alvenaria: 30 mm; Projeção do Arco de Alvenaria: 0 mm; Altura do Arco de Alvenaria: 250 mm; Profundidade do Arco de Alvenaria: 120 mm; Profund. Vão Posterior (gs_masonry_arch_rearHoleDepth): 0 mm; Espessura do Tijolo (gs_masonry_arch_brick_thk): 65 mm; Espessura de Argamassa (gs_masonry_arch_mort_thk): 10 mm; Largura Fecho: 100 mm; Sobredimensão Fecho: 0 mm; Projeção Fecho: 10 mm; Profund. Face de Vão (gs_wido_sill): 0 mm; Profund. Face de Vão (AC_wido_sill): 0 mm; Profund. Ombreira: 60 mm; Profund. Ombreira Lado 2: 60 mm; Profund. Ombreira Inferior Lado 1: 60 mm; Profund. Ombreira Inferior Lado 2: 60 mm; Profund. Ombreira Interior Lado 2 (gs_reveal_splayed_innerLeft): 60 mm; Profund. Ombreira Interior (gs_reveal_splayed_innerRight): 60 mm; Profund. Ombreira Interior (gs_reveal_double_innerRight): 60 mm; Profund. Ombreira Interior Lado 2 (gs_reveal_double_innerLeft): 60 mm; Profund. Ombreira Interior Inferior Lado 1: 60 mm; Profund. Ombreira Interior Inferior Lado 2: 60 mm; Profund. do Topo: 60 mm; Profundidade Peitoril: 60 mm; Profund. Peitoril Lado 1: 60 mm; Profund. Peitoril Lado 2: 60 mm; Profundidade Padieira Interior (gs_reveal_splayed_innerTop): 60 mm; Profundidade Peitoril Interior (gs_reveal_splayed_innerBottom): 0 mm; Profundidade Padieira Interior (gs_reveal_double_innerTop): 60 mm; Profundidade Peitoril Interior (gs_reveal_double_innerBottom): 0 mm; Profund. Peitoril Interior Lado 1: 0 mm; Profund. Peitoril Interior Lado 2: 0 mm; Profund. Batente Exterior: 80 mm; Limite Espess. Reboco: 40 mm; Distância de Camada do Encerram.: 0 mm; Largura do Fecho: 38 mm; Espessura do Fecho: 100 mm; Espessura da Camada: 25 mm; Espessura do Perfil: 150 mm; Espessura Personal.: 15 mm; Saliência Camada para Espess. Batente: 0 mm; Sobred. Abertura Esquerda: 0 mm; Sobred. Direita Abertura: 0 mm; Sobred. Topo Abertura: 0 mm; Sobred. Base Abertura: 0 mm; Largura Abertura 3D: 0 mm; Largura Abertura em 3D no Lado 2: 0 mm; Largura Abertura 2D: 0 mm; Largura Abertura em 2D no Lado 2: 0 mm; Distância Abertura 1 Caixilho Principal Lado 1: 0 mm; Distância Abertura 2 Caixilho Principal Lado 1: 0 mm; Distância Abertura 1 Caixilho Principal Lado 2: 0 mm; Distância Abertura 2 Caixilho Principal Lado 2: 0 mm; Distância Abertura 1 Bandeira Meio: 0 mm; Distância Abertura 2 Bandeira Meio: 0 mm; Distância Abertura 1 Bandeira Lado 1: 0 mm; Distância Abertura 2 Bandeira Lado 1: 0 mm; Distância Abertura 1 Bandeira Lado 2: 0 mm; Distância Abertura 2 Bandeira Lado 2: 0 mm; Largura 2 de Lado de Abertura: 200 mm; Largura 1 de Lado de Abertura: 100 mm; Profund. Lado de Abertura: 1000 mm; Largura 2 de Lado Oposto: 100 mm; Largura 1 de Lado Oposto: 100 mm; Profund. Lado Oposto: 1000 mm; Sobred. Abertura Esq. AC: 0 mm; Sobred. Abertura Dir. AC: 0 mm; Sobred. Padieira AC: 0 mm; Sobred. Abertura Base AC: 0 mm; ID Afastamento X: 0 mm; ID Afastamento Y: 0 mm; Afastamento X Texto Personalizado: 0 mm; Afastasmento Y Texto Personalizado: 0 mm; Afastamento X Largura da Folha: 0 mm; Afastamento Y Largura da Folha: 0 mm
Name | In | OverallWidth (mm) = Width (mm) = ArchiCADQuantities, Largura (mm) = P/J Largura do Vão no Lado Oposto do Requadro (mm) = P/J Largura do Vão no Lado do Requadro (mm) = P/J Largura do Vão Nominal no Lado Oposto do Requadro (mm) = P/J Largura do Vão Nominal no Lado do Requadro (mm) = AC_Equantity_Porta_25, Largura (mm) = Largura de Vão (mm) = Largura Face de Vão (mm) = Largura Unidade (mm) | IsExternal | Localização do Produto no Projeto | ID de Aberturas com Master ID | ID Dinâmico por Classificação | Perimeter (mm) | Area (m2) = P/J Área de Superfície Nominal do Vão (m2) = Área da Superfície da Abertura no Lado do Requadro da J/P (m2) = Área da Superfície da Abertura no Lado Oposto ao Requadro da J/P (m2) = P/J Área da Superfície do Vão Nominal no Lado do Requadro (m2) = P/J Área da Superfície do Vão Nominal no Lado Oposto do Requadro (m2) | Volume (m3) = NetVolume (m3) = Volume (Líquido) (m3) = Component, Volume Componente (Líquido) (m3) = Component, Volume do componente (Bruto) (m3) | Depth (mm) = Espessura da Parede (mm) = Espessura do Batente (mm) = Espessura Moldura Real (mm) | Elevação à Origem do Projeto (mm) = Elevação ao 1º Nível de Referência (mm) = Elevação ao 2º Nível de Referência (mm) = Elevação ao Nível do Mar (mm) | Área da Superfície (m2) = Área da Superfície da Base (Líquida) (m2) = Abertura Área da Superfície L/D (m2) | Elevação do Topo ao Primeiro Nível de Referência (mm) = Elevação do Topo À Cota Zero (mm) = Elevação do Topo Ao Nível do Mar (mm) = Elevação do Topo Ao Segundo Nível de Referência (mm) | Elevação da Base Ao Primeiro Nível de Referência (mm) = Elevação da Base À Cota Zero (mm) = Elevação da Base Ao Nível do Mar (mm) = Elevação da Base Ao Segundo Nível de Referência (mm) | Elevação da Base Ao Piso de Origem (mm) | Abertura Volume de Vão L/D (m3) = P/J Volume Nominal da Abertura (m3) | Largura Saída (mm) | Largura Nominal da Folha (mm) | Largura Nominal da Folha no Lado 1 (mm)
APTO4-PORTA-002 | Primeiro Pavimento | 900 | no | Projeto: CECAP GuarulhosLocal: Piso: Primeiro Pavimento Cômodo: | APTO4-002 | Porta -002 | 6000 | 1.89 | 0.0592503 | 40 | 0 | 4.51191 | 2100 | -2.44929e-15 | -2.44929e-15 | 0.0756 | 800 | 820 | 360
APTO4-PORTA-000 | Primeiro Pavimento | 900 | no | Projeto: CECAP GuarulhosLocal: Piso: Primeiro Pavimento Cômodo: | APTO4-000 | Porta -000 | 6000 | 1.89 | 0.0592503 | 40 | 0 | 4.51191 | 2100 | -2.44929e-15 | -2.44929e-15 | 0.0756 | 800 | 820 | 360
APTO3-PORTA-001 | Primeiro Pavimento | 900 | no | Projeto: CECAP GuarulhosLocal: Piso: Primeiro Pavimento Cômodo: | APTO3-001 | Porta -001 | 6000 | 1.89 | 0.0592503 | 40 | 0 | 4.51191 | 2100 | -2.44929e-15 | -2.44929e-15 | 0.0756 | 800 | 820 | 360
APTO2-PORTA-003 | Primeiro Pavimento | 710 | no | Projeto: CECAP GuarulhosLocal: Piso: Primeiro Pavimento Cômodo: WC | APTO2-14003 | Porta -003 | 5620 | 1.491 | 0.0592103 | 90 | 0 | 4.17951 | 2100 | -5.51091e-15 | -5.51091e-15 | 0.13419 | 610 | 630 | 315
APTO2-PORTA-004 | Primeiro Pavimento | 900 | yes | Projeto: CECAP GuarulhosLocal: Piso: Primeiro Pavimento Cômodo: SALA | APTO2-13004 | Porta -004 | 6000 | 1.89 | 0.0842503 | 140 | 0 | 5.54191 | 2100 | -8.57253e-15 | -8.57253e-15 | 0.2646 | 800 | 820 | 360
APTO2-PORTA-001 | Primeiro Pavimento | 900 | no | Projeto: CECAP GuarulhosLocal: Piso: Primeiro Pavimento Cômodo: | APTO2-001 | Porta -001 | 6000 | 1.89 | 0.0592503 | 40 | 0 | 4.51191 | 2100 | -2.44929e-15 | -2.44929e-15 | 0.0756 | 800 | 820 | 360
APTO3-PORTA-003 | Primeiro Pavimento | 710 | no | Projeto: CECAP GuarulhosLocal: Piso: Primeiro Pavimento Cômodo: WC | APTO3-21003 | Porta -003 | 5620 | 1.491 | 0.0592103 | 90 | 0 | 4.17951 | 2100 | -5.51091e-15 | -5.51091e-15 | 0.13419 | 610 | 630 | 315
APTO3-PORTA-004 | Primeiro Pavimento | 900 | yes | Projeto: CECAP GuarulhosLocal: Piso: Primeiro Pavimento Cômodo: SALA | APTO3-20004 | Porta -004 | 6000 | 1.89 | 0.0842503 | 140 | 0 | 5.54191 | 2100 | -8.57253e-15 | -8.57253e-15 | 0.2646 | 800 | 820 | 360
APTO1-PORTA-002 | Primeiro Pavimento | 900 | no | Projeto: CECAP GuarulhosLocal: Piso: Primeiro Pavimento Cômodo: | APTO1-002 | Porta -002 | 6000 | 1.89 | 0.0592503 | 40 | 0 | 4.51191 | 2100 | -2.44929e-15 | -2.44929e-15 | 0.0756 | 800 | 820 | 360
APTO1-PORTA-000 | Primeiro Pavimento | 900 | no | Projeto: CECAP GuarulhosLocal: Piso: Primeiro Pavimento Cômodo: | APTO1-000 | Porta -000 | 6000 | 1.89 | 0.0592503 | 40 | 0 | 4.51191 | 2100 | -2.44929e-15 | -2.44929e-15 | 0.0756 | 800 | 820 | 360
APTO5-PORTA-002 | Segundo Pavimento | 900 | no | Projeto: CECAP GuarulhosLocal: Piso: Segundo Pavimento Cômodo: | APTO5-002 | Porta -002 | 6000 | 1.89 | 0.0592503 | 40 | 2650 | 4.51191 | 4750 | 2650 | 0 | 0.0756 | 800 | 820 | 360
APTO5-PORTA-000 | Segundo Pavimento | 900 | no | Projeto: CECAP GuarulhosLocal: Piso: Segundo Pavimento Cômodo: | APTO5-000 | Porta -000 | 6000 | 1.89 | 0.0592503 | 40 | 2650 | 4.51191 | 4750 | 2650 | 0 | 0.0756 | 800 | 820 | 360
APTO6-PORTA-003 | Segundo Pavimento | 710 | no | Projeto: CECAP GuarulhosLocal: Piso: Segundo Pavimento Cômodo: WC | APTO6-13003 | Porta -003 | 5620 | 1.491 | 0.0592103 | 90 | 2650 | 4.17951 | 4750 | 2650 | 0 | 0.13419 | 610 | 630 | 315
APTO6-PORTA-004 | Segundo Pavimento | 900 | yes | Projeto: CECAP GuarulhosLocal: Piso: Segundo Pavimento Cômodo: SALA | APTO6-09004 | Porta -004 | 6000 | 1.89 | 0.0842503 | 140 | 2650 | 5.54191 | 4750 | 2650 | 0 | 0.2646 | 800 | 820 | 360
APTO6-PORTA-001 | Segundo Pavimento | 900 | no | Projeto: CECAP GuarulhosLocal: Piso: Segundo Pavimento Cômodo: | APTO6-001 | Porta -001 | 6000 | 1.89 | 0.0592503 | 40 | 2650 | 4.51191 | 4750 | 2650 | 0 | 0.0756 | 800 | 820 | 360
APTO7-PORTA-003 | Segundo Pavimento | 710 | no | Projeto: CECAP GuarulhosLocal: Piso: Segundo Pavimento Cômodo: WC | APTO7-13003 | Porta -003 | 5620 | 1.491 | 0.0592103 | 90 | 2650 | 4.17951 | 4750 | 2650 | 0 | 0.13419 | 610 | 630 | 315
APTO7-PORTA-004 | Segundo Pavimento | 900 | yes | Projeto: CECAP GuarulhosLocal: Piso: Segundo Pavimento Cômodo: SALA | APTO7-09004 | Porta -004 | 6000 | 1.89 | 0.0842503 | 140 | 2650 | 5.54191 | 4750 | 2650 | 0 | 0.2646 | 800 | 820 | 360
APTO7-PORTA-001 | Segundo Pavimento | 900 | no | Projeto: CECAP GuarulhosLocal: Piso: Segundo Pavimento Cômodo: | APTO7-001 | Porta -001 | 6000 | 1.89 | 0.0592503 | 40 | 2650 | 4.51191 | 4750 | 2650 | 0 | 0.0756 | 800 | 820 | 360
APTO8-PORTA-002 | Segundo Pavimento | 900 | no | Projeto: CECAP GuarulhosLocal: Piso: Segundo Pavimento Cômodo: | APTO8-002 | Porta -002 | 6000 | 1.89 | 0.0592503 | 40 | 2650 | 4.51191 | 4750 | 2650 | 0 | 0.0756 | 800 | 820 | 360
APTO8-PORTA-000 | Segundo Pavimento | 900 | no | Projeto: CECAP GuarulhosLocal: Piso: Segundo Pavimento Cômodo: | APTO8-000 | Porta -000 | 6000 | 1.89 | 0.0592503 | 40 | 2650 | 4.51191 | 4750 | 2650 | 0 | 0.0756 | 800 | 820 | 360
APTO9-PORTA-002 | Terceiro Pavimento | 900 | no | Projeto: CECAP GuarulhosLocal: Piso: Terceiro Pavimento Cômodo: | APTO9-002 | Porta -002 | 6000 | 1.89 | 0.0592503 | 40 | 5300 | 4.51191 | 7400 | 5300 | 0 | 0.0756 | 800 | 820 | 360
APTO9-PORTA-000 | Terceiro Pavimento | 900 | no | Projeto: CECAP GuarulhosLocal: Piso: Terceiro Pavimento Cômodo: | APTO9-000 | Porta -000 | 6000 | 1.89 | 0.0592503 | 40 | 5300 | 4.51191 | 7400 | 5300 | 0 | 0.0756 | 800 | 820 | 360
APTO10-PORTA-003 | Terceiro Pavimento | 710 | no | Projeto: CECAP GuarulhosLocal: Piso: Terceiro Pavimento Cômodo: WC | APTO10-13003 | Porta -003 | 5620 | 1.491 | 0.0592103 | 90 | 5300 | 4.17951 | 7400 | 5300 | 0 | 0.13419 | 610 | 630 | 315
APTO10-PORTA-004 | Terceiro Pavimento | 900 | yes | Projeto: CECAP GuarulhosLocal: Piso: Terceiro Pavimento Cômodo: SALA | APTO10-09004 | Porta -004 | 6000 | 1.89 | 0.0842503 | 140 | 5300 | 5.54191 | 7400 | 5300 | 0 | 0.2646 | 800 | 820 | 360
APTO10-PORTA-001 | Terceiro Pavimento | 900 | no | Projeto: CECAP GuarulhosLocal: Piso: Terceiro Pavimento Cômodo: | APTO10-001 | Porta -001 | 6000 | 1.89 | 0.0592503 | 40 | 5300 | 4.51191 | 7400 | 5300 | 0 | 0.0756 | 800 | 820 | 360
APTO11-PORTA-003 | Terceiro Pavimento | 710 | no | Projeto: CECAP GuarulhosLocal: Piso: Terceiro Pavimento Cômodo: WC | APTO11-13003 | Porta -003 | 5620 | 1.491 | 0.0592103 | 90 | 5300 | 4.17951 | 7400 | 5300 | 0 | 0.13419 | 610 | 630 | 315
APTO11-PORTA-004 | Terceiro Pavimento | 900 | yes | Projeto: CECAP GuarulhosLocal: Piso: Terceiro Pavimento Cômodo: SALA | APTO11-09004 | Porta -004 | 6000 | 1.89 | 0.0842503 | 140 | 5300 | 5.54191 | 7400 | 5300 | 0 | 0.2646 | 800 | 820 | 360
APTO11-PORTA-001 | Terceiro Pavimento | 900 | no | Projeto: CECAP GuarulhosLocal: Piso: Terceiro Pavimento Cômodo: | APTO11-001 | Porta -001 | 6000 | 1.89 | 0.0592503 | 40 | 5300 | 4.51191 | 7400 | 5300 | 0 | 0.0756 | 800 | 820 | 360
APTO12-PORTA-002 | Terceiro Pavimento | 900 | no | Projeto: CECAP GuarulhosLocal: Piso: Terceiro Pavimento Cômodo: | APTO12-002 | Porta -002 | 6000 | 1.89 | 0.0592503 | 40 | 5300 | 4.51191 | 7400 | 5300 | 0 | 0.0756 | 800 | 820 | 360
APTO12-PORTA-000 | Terceiro Pavimento | 900 | no | Projeto: CECAP GuarulhosLocal: Piso: Terceiro Pavimento Cômodo: | APTO12-000 | Porta -000 | 6000 | 1.89 | 0.0592503 | 40 | 5300 | 4.51191 | 7400 | 5300 | 0 | 0.0756 | 800 | 820 | 360

# IfcMember: IfcMember (9)
Classification: Estrutura de Escada (Classificação ARCHICAD); Material: Concreto - Estrutural
AC_Pset_RenovationAndPhasing - Renovation Status: Existing
ArchiCADQuantities - Espessura: 150 mm; Espessura Secundária: 150 mm
Name | In | Localização do Produto no Projeto | ID Dinâmico por Classificação | Concreto - Estrutural, Carbono Incorporado | Concreto - Estrutural, Energia Incorporada (MJ) | GrossVolume (m3) = NetVolume (m3) = Volume (Líquido) (m3) = Concreto - Estrutural, Volume Componente (Líquido) (m3) = Concreto - Estrutural, Volume do componente (Bruto) (m3) | Largura (mm) | Elevação à Origem do Projeto (mm) = Elevação ao 1º Nível de Referência (mm) = Elevação ao 2º Nível de Referência (mm) = Elevação ao Nível do Mar (mm) | Elevação ao Piso (mm) = Afastamento da Origem (mm) | Afastamento do Topo (mm) | Área da Superfície (m2) = Área da Superfície da Base (Líquida) (m2) = Área da Superfície Total (m2) | Comprimento 3D (mm) | Elevação do Topo ao Primeiro Nível de Referência (mm) = Elevação do Topo À Cota Zero (mm) = Elevação do Topo Ao Nível do Mar (mm) = Elevação do Topo Ao Segundo Nível de Referência (mm) | Elevação do Topo Ao Piso de Origem (mm) | Elevação da Base Ao Primeiro Nível de Referência (mm) = Elevação da Base À Cota Zero (mm) = Elevação da Base Ao Nível do Mar (mm) = Elevação da Base Ao Segundo Nível de Referência (mm) | Elevação da Base Ao Piso de Origem (mm) | Altura 3D Estrutura da Escada (mm) | Concreto - Estrutural, Massa (kg)
Lance - 005 | Pavimento Terreo | Projeto: CECAP GuarulhosLocal: Piso: Pavimento Terreo Cômodo: ESCADA | Estrutura de Escada - 005 | 150.64 (kgCO₂) | 1460.75 | 0.330787 | 1120 | -139.667 | 2510.33 | 2.22045e-13 | 4.89426 | 1569.11 | -239.667 | 2410.33 | -939.429 | 1710.57 | 699.762 | 760.81
Lance - 007 | Pavimento Terreo | Projeto: CECAP GuarulhosLocal: Piso: Pavimento Terreo Cômodo: ESCADA | Estrutura de Escada - 007 | 171.083 (kgCO₂) | 1658.99 | 0.375676 | 975 | -1052.48 | 1597.52 | -3351.24 | 5.37195 | 1932.54 | -976.857 | 1673.14 | -1930.57 | 719.429 | 953.714 | 864.056
Lance - 005 | Pavimento Terreo | Projeto: CECAP GuarulhosLocal: Piso: Pavimento Terreo Cômodo: ESCADA | Estrutura de Escada - 005 | 126.338 (kgCO₂) | 1225.09 | 0.277421 | 1120 | -2152.5 | 497.5 | -1787.5 | 4.1049 | 977.679 | -2070 | 580 | -2700 | -50 | 630 | 638.068
CIRC1-Lance - 005 | Primeiro Pavimento | Projeto: CECAP GuarulhosLocal: Piso: Primeiro Pavimento Cômodo: ESCADA | Estrutura de Escada - 005 | 150.64 (kgCO₂) | 1460.75 | 0.330787 | 1120 | 2510.33 | 2510.33 | 0 | 4.89426 | 1569.11 | 2410.33 | 2410.33 | 1710.57 | 1710.57 | 699.762 | 760.81
CIRC1-Lance - 007 | Primeiro Pavimento | Projeto: CECAP GuarulhosLocal: Piso: Primeiro Pavimento Cômodo: ESCADA | Estrutura de Escada - 007 | 171.777 (kgCO₂) | 1665.72 | 0.3772 | 975 | 1563.81 | 1563.81 | -762.667 | 5.38476 | 1936.29 | 1640.57 | 1640.57 | 680 | 680 | 960.571 | 867.561
CIRC1-Lance - 005 | Primeiro Pavimento | Projeto: CECAP GuarulhosLocal: Piso: Primeiro Pavimento Cômodo: ESCADA | Estrutura de Escada - 005 | 126.338 (kgCO₂) | 1225.09 | 0.277421 | 1120 | 497.5 | 497.5 | -1787.5 | 4.1049 | 977.679 | 580 | 580 | -50 | -50 | 630 | 638.068
CIRC2-Lance - 005 | Segundo Pavimento | Projeto: CECAP GuarulhosLocal: Piso: Segundo Pavimento Cômodo: ESCADA | Estrutura de Escada - 005 | 150.64 (kgCO₂) | 1460.75 | 0.330787 | 1120 | 5160.33 | 2510.33 | 0 | 4.89426 | 1569.11 | 5060.33 | 2410.33 | 4360.57 | 1710.57 | 699.762 | 760.81
CIRC2-Lance - 007 | Segundo Pavimento | Projeto: CECAP GuarulhosLocal: Piso: Segundo Pavimento Cômodo: ESCADA | Estrutura de Escada - 007 | 171.777 (kgCO₂) | 1665.72 | 0.3772 | 975 | 4213.81 | 1563.81 | -762.667 | 5.38476 | 1936.29 | 4290.57 | 1640.57 | 3330 | 680 | 960.571 | 867.561
CIRC2-Lance - 005 | Segundo Pavimento | Projeto: CECAP GuarulhosLocal: Piso: Segundo Pavimento Cômodo: ESCADA | Estrutura de Escada - 005 | 126.338 (kgCO₂) | 1225.09 | 0.277421 | 1120 | 3147.5 | 497.5 | -1787.5 | 4.1049 | 977.679 | 3230 | 580 | 2600 | -50 | 630 | 638.068

# IfcMember: Montante 50 x 50 (216)
Type - PredefinedType: MULLION
Classification: Estrutura de Parede Cortina (Classificação ARCHICAD); Material: Alumínio
INFORMAÇÕES DO PRODUTO - Data de Aquisição: DD/MM/YYYY
FABRICAÇÃO - Data de Fabricação: DD/MM/YYYY; Site do Produto: www.graphisoft.com
GARANTIA - Ínicio da Garantia: DD/MM/YYYY; Fim da Garantia: DD/MM/YYYY
AC_Pset_RenovationAndPhasing - Renovation Status: Não definido
Component Properties - Alumínio, Carbono Incorporado: 54.1814 (kgCO₂); Alumínio, Energia Incorporada: 916.825 MJ
BaseQuantities - Length: 845 mm; CrossSectionArea: 0.0025 m2; OuterSurfaceArea: 0.169 m2; TotalSurfaceArea: 0.174 m2; GrossSurfaceArea: 0.174 m2; GrossVolume: 0.0021125 m3; NetVolume: 0.0021125 m3
ArchiCADQuantities - Volume (Líquido): 0.0021125 m3; Largura: 50 mm; Área da Superfície: 0.174 m2; Área da Superfície da Base (Líquida): 0.174 m2; Profundidade da Moldura: 50 mm; Comprimento de Moldura: 845 mm
AC_Equantity_Perfil_Pele_de_Vidro - Dimensão 1: 50 mm; Dimensão 2: 50 mm; Altura: 845 mm; Nível da Base: 1000 mm; Nível do Topo: 0 mm; Espessura Conexão: 0 mm; Profundidade da Conexão: 20 mm; Largura Moldura: 50 mm; Espessura Estrutura: 50 mm; Profundidade Fundo Estrutura: 50 mm; Afastamento Lado Estrutura: 25 mm
Component Quantities - Alumínio, Massa: 5.915 kg; Alumínio, Volume Componente (Líquido): 0.0021125 m3; Alumínio, Volume do componente (Bruto): 0.0021125 m3
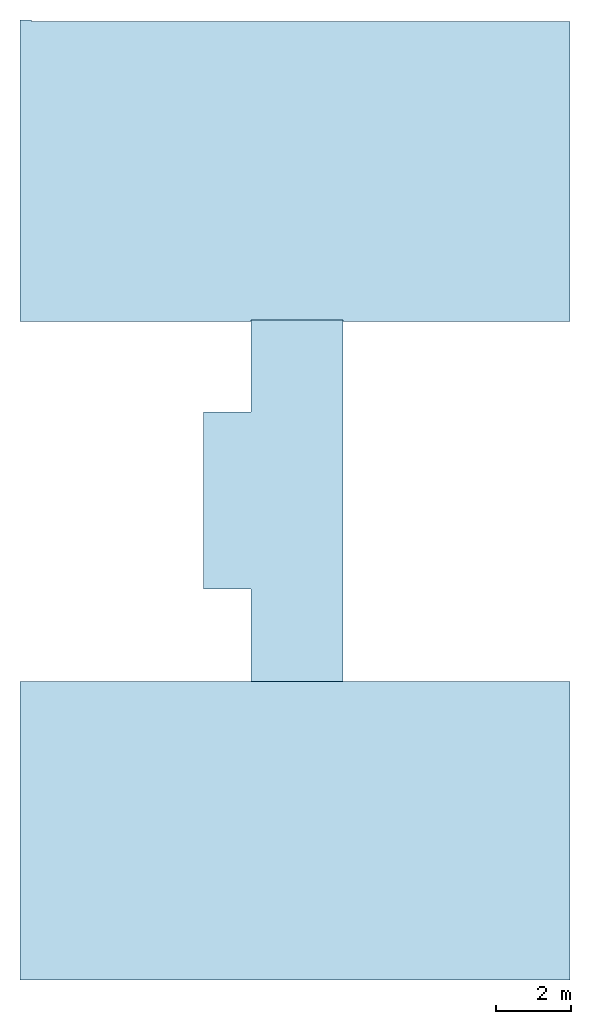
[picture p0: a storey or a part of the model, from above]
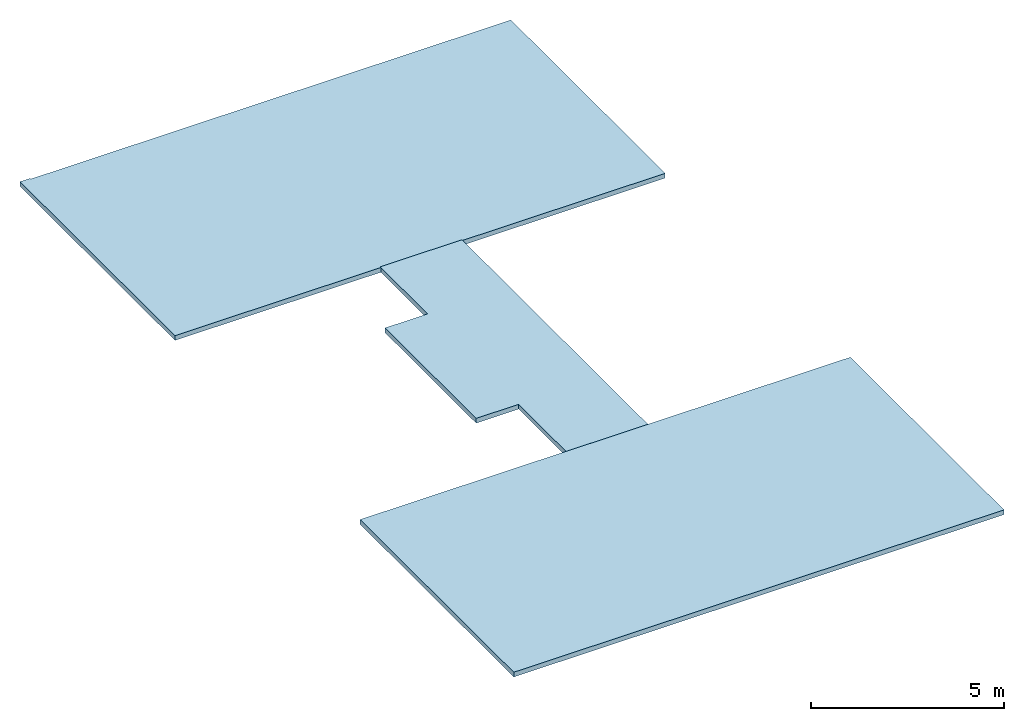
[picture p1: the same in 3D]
Properties of the parts of a building model (IFC2X3), part 4 of 7

# IfcMember: Montante 50 x 50 (216)
Name | In | Localização do Produto no Projeto | ID Dinâmico por Classificação | Elevação à Origem do Projeto (mm) = Elevação ao 1º Nível de Referência (mm) = Elevação ao 2º Nível de Referência (mm) = Elevação ao Nível do Mar (mm) = Elevação da Base Ao Primeiro Nível de Referência (mm) = Elevação da Base À Cota Zero (mm) = Elevação da Base Ao Nível do Mar (mm) = Elevação da Base Ao Segundo Nível de Referência (mm) | Elevação ao Piso (mm) = Afastamento da Origem (mm) = Elevação da Base Ao Piso de Origem (mm) | Elevação do Topo ao Primeiro Nível de Referência (mm) = Elevação do Topo À Cota Zero (mm) = Elevação do Topo Ao Nível do Mar (mm) = Elevação do Topo Ao Segundo Nível de Referência (mm) | Elevação do Topo Ao Piso de Origem (mm)
APTO4-PC-Est-Mnt-430 | Primeiro Pavimento | Projeto: CECAP GuarulhosLocal: Piso: Primeiro Pavimento Cômodo: | Estrutura de Parede Cortina -Est-Mnt-430 | 1355.02 | 1355.02 | 2200.02 | 2200.02
APTO4-PC-Est-Mnt-485 | Primeiro Pavimento | Projeto: CECAP GuarulhosLocal: Piso: Primeiro Pavimento Cômodo: | Estrutura de Parede Cortina -Est-Mnt-485 | 1355.02 | 1355.02 | 2200.02 | 2200.02
APTO4-PC-Est-Mnt-486 | Primeiro Pavimento | Projeto: CECAP GuarulhosLocal: Piso: Primeiro Pavimento Cômodo: | Estrutura de Parede Cortina -Est-Mnt-486 | 1355.02 | 1355.02 | 2200.02 | 2200.02
APTO4-PC-Est-Mnt-428 | Primeiro Pavimento | Projeto: CECAP GuarulhosLocal: Piso: Primeiro Pavimento Cômodo: | Estrutura de Parede Cortina -Est-Mnt-428 | 1355.02 | 1355.02 | 2200.02 | 2200.02
APTO4-PC-Est-Mnt-487 | Primeiro Pavimento | Projeto: CECAP GuarulhosLocal: Piso: Primeiro Pavimento Cômodo: | Estrutura de Parede Cortina -Est-Mnt-487 | 1355.02 | 1355.02 | 2200.02 | 2200.02
APTO4-PC-Est-Mnt-488 | Primeiro Pavimento | Projeto: CECAP GuarulhosLocal: Piso: Primeiro Pavimento Cômodo: | Estrutura de Parede Cortina -Est-Mnt-488 | 1355.02 | 1355.02 | 2200.02 | 2200.02
APTO4-PC-Est-Mnt-522 | Primeiro Pavimento | Projeto: CECAP GuarulhosLocal: Piso: Primeiro Pavimento Cômodo: | Estrutura de Parede Cortina -Est-Mnt-522 | 1355.02 | 1355.02 | 2200.02 | 2200.02
APTO4-PC-Est-Mnt-429 | Primeiro Pavimento | Projeto: CECAP GuarulhosLocal: Piso: Primeiro Pavimento Cômodo: | Estrutura de Parede Cortina -Est-Mnt-429 | 1355.02 | 1355.02 | 2200.02 | 2200.02
APTO4-PC-Est-Mnt-427 | Primeiro Pavimento | Projeto: CECAP GuarulhosLocal: Piso: Primeiro Pavimento Cômodo: | Estrutura de Parede Cortina -Est-Mnt-427 | 1355.02 | 1355.02 | 2200.02 | 2200.02
APTO4-PC-Est-Mnt-426 | Primeiro Pavimento | Projeto: CECAP GuarulhosLocal: Piso: Primeiro Pavimento Cômodo: | Estrutura de Parede Cortina -Est-Mnt-426 | 1355.02 | 1355.02 | 2200.02 | 2200.02
APTO4-PC-Est-Mnt-430 | Primeiro Pavimento | Projeto: CECAP GuarulhosLocal: Piso: Primeiro Pavimento Cômodo: | Estrutura de Parede Cortina -Est-Mnt-430 | 1355 | 1355 | 2200 | 2200
APTO4-PC-Est-Mnt-485 | Primeiro Pavimento | Projeto: CECAP GuarulhosLocal: Piso: Primeiro Pavimento Cômodo: | Estrutura de Parede Cortina -Est-Mnt-485 | 1355 | 1355 | 2200 | 2200
APTO4-PC-Est-Mnt-486 | Primeiro Pavimento | Projeto: CECAP GuarulhosLocal: Piso: Primeiro Pavimento Cômodo: | Estrutura de Parede Cortina -Est-Mnt-486 | 1355 | 1355 | 2200 | 2200
APTO4-PC-Est-Mnt-428 | Primeiro Pavimento | Projeto: CECAP GuarulhosLocal: Piso: Primeiro Pavimento Cômodo: | Estrutura de Parede Cortina -Est-Mnt-428 | 1355 | 1355 | 2200 | 2200
APTO4-PC-Est-Mnt-560 | Primeiro Pavimento | Projeto: CECAP GuarulhosLocal: Piso: Primeiro Pavimento Cômodo: | Estrutura de Parede Cortina -Est-Mnt-560 | 1355 | 1355 | 2200 | 2200
APTO4-PC-Est-Mnt-429 | Primeiro Pavimento | Projeto: CECAP GuarulhosLocal: Piso: Primeiro Pavimento Cômodo: | Estrutura de Parede Cortina -Est-Mnt-429 | 1355 | 1355 | 2200 | 2200
APTO4-PC-Est-Mnt-427 | Primeiro Pavimento | Projeto: CECAP GuarulhosLocal: Piso: Primeiro Pavimento Cômodo: | Estrutura de Parede Cortina -Est-Mnt-427 | 1355 | 1355 | 2200 | 2200
APTO4-PC-Est-Mnt-426 | Primeiro Pavimento | Projeto: CECAP GuarulhosLocal: Piso: Primeiro Pavimento Cômodo: | Estrutura de Parede Cortina -Est-Mnt-426 | 1355 | 1355 | 2200 | 2200
APTO3-PC-Est-Mnt-430 | Primeiro Pavimento | Projeto: CECAP GuarulhosLocal: Piso: Primeiro Pavimento Cômodo: | Estrutura de Parede Cortina -Est-Mnt-430 | 1355.02 | 1355.02 | 2200.02 | 2200.02
APTO3-PC-Est-Mnt-485 | Primeiro Pavimento | Projeto: CECAP GuarulhosLocal: Piso: Primeiro Pavimento Cômodo: | Estrutura de Parede Cortina -Est-Mnt-485 | 1355.02 | 1355.02 | 2200.02 | 2200.02
APTO3-PC-Est-Mnt-486 | Primeiro Pavimento | Projeto: CECAP GuarulhosLocal: Piso: Primeiro Pavimento Cômodo: | Estrutura de Parede Cortina -Est-Mnt-486 | 1355.02 | 1355.02 | 2200.02 | 2200.02
APTO3-PC-Est-Mnt-428 | Primeiro Pavimento | Projeto: CECAP GuarulhosLocal: Piso: Primeiro Pavimento Cômodo: | Estrutura de Parede Cortina -Est-Mnt-428 | 1355.02 | 1355.02 | 2200.02 | 2200.02
APTO3-PC-Est-Mnt-487 | Primeiro Pavimento | Projeto: CECAP GuarulhosLocal: Piso: Primeiro Pavimento Cômodo: | Estrutura de Parede Cortina -Est-Mnt-487 | 1355.02 | 1355.02 | 2200.02 | 2200.02
APTO3-PC-Est-Mnt-488 | Primeiro Pavimento | Projeto: CECAP GuarulhosLocal: Piso: Primeiro Pavimento Cômodo: | Estrutura de Parede Cortina -Est-Mnt-488 | 1355.02 | 1355.02 | 2200.02 | 2200.02
APTO3-PC-Est-Mnt-522 | Primeiro Pavimento | Projeto: CECAP GuarulhosLocal: Piso: Primeiro Pavimento Cômodo: | Estrutura de Parede Cortina -Est-Mnt-522 | 1355.02 | 1355.02 | 2200.02 | 2200.02
APTO3-PC-Est-Mnt-429 | Primeiro Pavimento | Projeto: CECAP GuarulhosLocal: Piso: Primeiro Pavimento Cômodo: | Estrutura de Parede Cortina -Est-Mnt-429 | 1355.02 | 1355.02 | 2200.02 | 2200.02
APTO3-PC-Est-Mnt-427 | Primeiro Pavimento | Projeto: CECAP GuarulhosLocal: Piso: Primeiro Pavimento Cômodo: | Estrutura de Parede Cortina -Est-Mnt-427 | 1355.02 | 1355.02 | 2200.02 | 2200.02
APTO3-PC-Est-Mnt-426 | Primeiro Pavimento | Projeto: CECAP GuarulhosLocal: Piso: Primeiro Pavimento Cômodo: | Estrutura de Parede Cortina -Est-Mnt-426 | 1355.02 | 1355.02 | 2200.02 | 2200.02
APTO2-PC-Est-Mnt-430 | Primeiro Pavimento | Projeto: CECAP GuarulhosLocal: Piso: Primeiro Pavimento Cômodo: | Estrutura de Parede Cortina -Est-Mnt-430 | 1355 | 1355 | 2200 | 2200
APTO2-PC-Est-Mnt-485 | Primeiro Pavimento | Projeto: CECAP GuarulhosLocal: Piso: Primeiro Pavimento Cômodo: | Estrutura de Parede Cortina -Est-Mnt-485 | 1355 | 1355 | 2200 | 2200
APTO2-PC-Est-Mnt-486 | Primeiro Pavimento | Projeto: CECAP GuarulhosLocal: Piso: Primeiro Pavimento Cômodo: | Estrutura de Parede Cortina -Est-Mnt-486 | 1355 | 1355 | 2200 | 2200
APTO2-PC-Est-Mnt-428 | Primeiro Pavimento | Projeto: CECAP GuarulhosLocal: Piso: Primeiro Pavimento Cômodo: | Estrutura de Parede Cortina -Est-Mnt-428 | 1355 | 1355 | 2200 | 2200
APTO2-PC-Est-Mnt-560 | Primeiro Pavimento | Projeto: CECAP GuarulhosLocal: Piso: Primeiro Pavimento Cômodo: | Estrutura de Parede Cortina -Est-Mnt-560 | 1355 | 1355 | 2200 | 2200
APTO2-PC-Est-Mnt-429 | Primeiro Pavimento | Projeto: CECAP GuarulhosLocal: Piso: Primeiro Pavimento Cômodo: | Estrutura de Parede Cortina -Est-Mnt-429 | 1355 | 1355 | 2200 | 2200
APTO2-PC-Est-Mnt-427 | Primeiro Pavimento | Projeto: CECAP GuarulhosLocal: Piso: Primeiro Pavimento Cômodo: | Estrutura de Parede Cortina -Est-Mnt-427 | 1355 | 1355 | 2200 | 2200
APTO2-PC-Est-Mnt-426 | Primeiro Pavimento | Projeto: CECAP GuarulhosLocal: Piso: Primeiro Pavimento Cômodo: | Estrutura de Parede Cortina -Est-Mnt-426 | 1355 | 1355 | 2200 | 2200
APTO2-PC-Est-Mnt-430 | Primeiro Pavimento | Projeto: CECAP GuarulhosLocal: Piso: Primeiro Pavimento Cômodo: | Estrutura de Parede Cortina -Est-Mnt-430 | 1355.02 | 1355.02 | 2200.02 | 2200.02
APTO2-PC-Est-Mnt-485 | Primeiro Pavimento | Projeto: CECAP GuarulhosLocal: Piso: Primeiro Pavimento Cômodo: | Estrutura de Parede Cortina -Est-Mnt-485 | 1355.02 | 1355.02 | 2200.02 | 2200.02
APTO2-PC-Est-Mnt-486 | Primeiro Pavimento | Projeto: CECAP GuarulhosLocal: Piso: Primeiro Pavimento Cômodo: | Estrutura de Parede Cortina -Est-Mnt-486 | 1355.02 | 1355.02 | 2200.02 | 2200.02
APTO2-PC-Est-Mnt-428 | Primeiro Pavimento | Projeto: CECAP GuarulhosLocal: Piso: Primeiro Pavimento Cômodo: | Estrutura de Parede Cortina -Est-Mnt-428 | 1355.02 | 1355.02 | 2200.02 | 2200.02
APTO2-PC-Est-Mnt-487 | Primeiro Pavimento | Projeto: CECAP GuarulhosLocal: Piso: Primeiro Pavimento Cômodo: | Estrutura de Parede Cortina -Est-Mnt-487 | 1355.02 | 1355.02 | 2200.02 | 2200.02
APTO2-PC-Est-Mnt-488 | Primeiro Pavimento | Projeto: CECAP GuarulhosLocal: Piso: Primeiro Pavimento Cômodo: | Estrutura de Parede Cortina -Est-Mnt-488 | 1355.02 | 1355.02 | 2200.02 | 2200.02
APTO2-PC-Est-Mnt-522 | Primeiro Pavimento | Projeto: CECAP GuarulhosLocal: Piso: Primeiro Pavimento Cômodo: | Estrutura de Parede Cortina -Est-Mnt-522 | 1355.02 | 1355.02 | 2200.02 | 2200.02
APTO2-PC-Est-Mnt-429 | Primeiro Pavimento | Projeto: CECAP GuarulhosLocal: Piso: Primeiro Pavimento Cômodo: | Estrutura de Parede Cortina -Est-Mnt-429 | 1355.02 | 1355.02 | 2200.02 | 2200.02
APTO2-PC-Est-Mnt-427 | Primeiro Pavimento | Projeto: CECAP GuarulhosLocal: Piso: Primeiro Pavimento Cômodo: | Estrutura de Parede Cortina -Est-Mnt-427 | 1355.02 | 1355.02 | 2200.02 | 2200.02
APTO2-PC-Est-Mnt-426 | Primeiro Pavimento | Projeto: CECAP GuarulhosLocal: Piso: Primeiro Pavimento Cômodo: | Estrutura de Parede Cortina -Est-Mnt-426 | 1355.02 | 1355.02 | 2200.02 | 2200.02
APTO3-PC-Est-Mnt-430 | Primeiro Pavimento | Projeto: CECAP GuarulhosLocal: Piso: Primeiro Pavimento Cômodo: | Estrutura de Parede Cortina -Est-Mnt-430 | 1355 | 1355 | 2200 | 2200
APTO3-PC-Est-Mnt-485 | Primeiro Pavimento | Projeto: CECAP GuarulhosLocal: Piso: Primeiro Pavimento Cômodo: | Estrutura de Parede Cortina -Est-Mnt-485 | 1355 | 1355 | 2200 | 2200
APTO3-PC-Est-Mnt-486 | Primeiro Pavimento | Projeto: CECAP GuarulhosLocal: Piso: Primeiro Pavimento Cômodo: | Estrutura de Parede Cortina -Est-Mnt-486 | 1355 | 1355 | 2200 | 2200
APTO3-PC-Est-Mnt-428 | Primeiro Pavimento | Projeto: CECAP GuarulhosLocal: Piso: Primeiro Pavimento Cômodo: | Estrutura de Parede Cortina -Est-Mnt-428 | 1355 | 1355 | 2200 | 2200
APTO3-PC-Est-Mnt-560 | Primeiro Pavimento | Projeto: CECAP GuarulhosLocal: Piso: Primeiro Pavimento Cômodo: | Estrutura de Parede Cortina -Est-Mnt-560 | 1355 | 1355 | 2200 | 2200
APTO3-PC-Est-Mnt-429 | Primeiro Pavimento | Projeto: CECAP GuarulhosLocal: Piso: Primeiro Pavimento Cômodo: | Estrutura de Parede Cortina -Est-Mnt-429 | 1355 | 1355 | 2200 | 2200
APTO3-PC-Est-Mnt-427 | Primeiro Pavimento | Projeto: CECAP GuarulhosLocal: Piso: Primeiro Pavimento Cômodo: | Estrutura de Parede Cortina -Est-Mnt-427 | 1355 | 1355 | 2200 | 2200
APTO3-PC-Est-Mnt-426 | Primeiro Pavimento | Projeto: CECAP GuarulhosLocal: Piso: Primeiro Pavimento Cômodo: | Estrutura de Parede Cortina -Est-Mnt-426 | 1355 | 1355 | 2200 | 2200
APTO1-PC-Est-Mnt-426 | Primeiro Pavimento | Projeto: CECAP GuarulhosLocal: Piso: Primeiro Pavimento Cômodo: | Estrutura de Parede Cortina -Est-Mnt-426 | 1355.02 | 1355.02 | 2200.02 | 2200.02
APTO1-PC-Est-Mnt-427 | Primeiro Pavimento | Projeto: CECAP GuarulhosLocal: Piso: Primeiro Pavimento Cômodo: | Estrutura de Parede Cortina -Est-Mnt-427 | 1355.02 | 1355.02 | 2200.02 | 2200.02
APTO1-PC-Est-Mnt-429 | Primeiro Pavimento | Projeto: CECAP GuarulhosLocal: Piso: Primeiro Pavimento Cômodo: | Estrutura de Parede Cortina -Est-Mnt-429 | 1355.02 | 1355.02 | 2200.02 | 2200.02
APTO1-PC-Est-Mnt-522 | Primeiro Pavimento | Projeto: CECAP GuarulhosLocal: Piso: Primeiro Pavimento Cômodo: | Estrutura de Parede Cortina -Est-Mnt-522 | 1355.02 | 1355.02 | 2200.02 | 2200.02
APTO1-PC-Est-Mnt-488 | Primeiro Pavimento | Projeto: CECAP GuarulhosLocal: Piso: Primeiro Pavimento Cômodo: | Estrutura de Parede Cortina -Est-Mnt-488 | 1355.02 | 1355.02 | 2200.02 | 2200.02
APTO1-PC-Est-Mnt-487 | Primeiro Pavimento | Projeto: CECAP GuarulhosLocal: Piso: Primeiro Pavimento Cômodo: | Estrutura de Parede Cortina -Est-Mnt-487 | 1355.02 | 1355.02 | 2200.02 | 2200.02
APTO1-PC-Est-Mnt-428 | Primeiro Pavimento | Projeto: CECAP GuarulhosLocal: Piso: Primeiro Pavimento Cômodo: | Estrutura de Parede Cortina -Est-Mnt-428 | 1355.02 | 1355.02 | 2200.02 | 2200.02
APTO1-PC-Est-Mnt-486 | Primeiro Pavimento | Projeto: CECAP GuarulhosLocal: Piso: Primeiro Pavimento Cômodo: | Estrutura de Parede Cortina -Est-Mnt-486 | 1355.02 | 1355.02 | 2200.02 | 2200.02
APTO1-PC-Est-Mnt-485 | Primeiro Pavimento | Projeto: CECAP GuarulhosLocal: Piso: Primeiro Pavimento Cômodo: | Estrutura de Parede Cortina -Est-Mnt-485 | 1355.02 | 1355.02 | 2200.02 | 2200.02
APTO1-PC-Est-Mnt-430 | Primeiro Pavimento | Projeto: CECAP GuarulhosLocal: Piso: Primeiro Pavimento Cômodo: | Estrutura de Parede Cortina -Est-Mnt-430 | 1355.02 | 1355.02 | 2200.02 | 2200.02
APTO1-PC-Est-Mnt-426 | Primeiro Pavimento | Projeto: CECAP GuarulhosLocal: Piso: Primeiro Pavimento Cômodo: | Estrutura de Parede Cortina -Est-Mnt-426 | 1355 | 1355 | 2200 | 2200
APTO1-PC-Est-Mnt-427 | Primeiro Pavimento | Projeto: CECAP GuarulhosLocal: Piso: Primeiro Pavimento Cômodo: | Estrutura de Parede Cortina -Est-Mnt-427 | 1355 | 1355 | 2200 | 2200
APTO1-PC-Est-Mnt-429 | Primeiro Pavimento | Projeto: CECAP GuarulhosLocal: Piso: Primeiro Pavimento Cômodo: | Estrutura de Parede Cortina -Est-Mnt-429 | 1355 | 1355 | 2200 | 2200
APTO1-PC-Est-Mnt-560 | Primeiro Pavimento | Projeto: CECAP GuarulhosLocal: Piso: Primeiro Pavimento Cômodo: | Estrutura de Parede Cortina -Est-Mnt-560 | 1355 | 1355 | 2200 | 2200
APTO1-PC-Est-Mnt-428 | Primeiro Pavimento | Projeto: CECAP GuarulhosLocal: Piso: Primeiro Pavimento Cômodo: | Estrutura de Parede Cortina -Est-Mnt-428 | 1355 | 1355 | 2200 | 2200
APTO1-PC-Est-Mnt-486 | Primeiro Pavimento | Projeto: CECAP GuarulhosLocal: Piso: Primeiro Pavimento Cômodo: | Estrutura de Parede Cortina -Est-Mnt-486 | 1355 | 1355 | 2200 | 2200
APTO1-PC-Est-Mnt-485 | Primeiro Pavimento | Projeto: CECAP GuarulhosLocal: Piso: Primeiro Pavimento Cômodo: | Estrutura de Parede Cortina -Est-Mnt-485 | 1355 | 1355 | 2200 | 2200
APTO1-PC-Est-Mnt-430 | Primeiro Pavimento | Projeto: CECAP GuarulhosLocal: Piso: Primeiro Pavimento Cômodo: | Estrutura de Parede Cortina -Est-Mnt-430 | 1355 | 1355 | 2200 | 2200
APTO5-PC-Est-Mnt-430 | Segundo Pavimento | Projeto: CECAP GuarulhosLocal: Piso: Segundo Pavimento Cômodo: | Estrutura de Parede Cortina -Est-Mnt-430 | 4005.02 | 1355.02 | 4850.02 | 2200.02
APTO5-PC-Est-Mnt-485 | Segundo Pavimento | Projeto: CECAP GuarulhosLocal: Piso: Segundo Pavimento Cômodo: | Estrutura de Parede Cortina -Est-Mnt-485 | 4005.02 | 1355.02 | 4850.02 | 2200.02
APTO5-PC-Est-Mnt-486 | Segundo Pavimento | Projeto: CECAP GuarulhosLocal: Piso: Segundo Pavimento Cômodo: | Estrutura de Parede Cortina -Est-Mnt-486 | 4005.02 | 1355.02 | 4850.02 | 2200.02
APTO5-PC-Est-Mnt-428 | Segundo Pavimento | Projeto: CECAP GuarulhosLocal: Piso: Segundo Pavimento Cômodo: | Estrutura de Parede Cortina -Est-Mnt-428 | 4005.02 | 1355.02 | 4850.02 | 2200.02
APTO5-PC-Est-Mnt-487 | Segundo Pavimento | Projeto: CECAP GuarulhosLocal: Piso: Segundo Pavimento Cômodo: | Estrutura de Parede Cortina -Est-Mnt-487 | 4005.02 | 1355.02 | 4850.02 | 2200.02
APTO5-PC-Est-Mnt-488 | Segundo Pavimento | Projeto: CECAP GuarulhosLocal: Piso: Segundo Pavimento Cômodo: | Estrutura de Parede Cortina -Est-Mnt-488 | 4005.02 | 1355.02 | 4850.02 | 2200.02
APTO5-PC-Est-Mnt-522 | Segundo Pavimento | Projeto: CECAP GuarulhosLocal: Piso: Segundo Pavimento Cômodo: | Estrutura de Parede Cortina -Est-Mnt-522 | 4005.02 | 1355.02 | 4850.02 | 2200.02
APTO5-PC-Est-Mnt-429 | Segundo Pavimento | Projeto: CECAP GuarulhosLocal: Piso: Segundo Pavimento Cômodo: | Estrutura de Parede Cortina -Est-Mnt-429 | 4005.02 | 1355.02 | 4850.02 | 2200.02
APTO5-PC-Est-Mnt-427 | Segundo Pavimento | Projeto: CECAP GuarulhosLocal: Piso: Segundo Pavimento Cômodo: | Estrutura de Parede Cortina -Est-Mnt-427 | 4005.02 | 1355.02 | 4850.02 | 2200.02
APTO5-PC-Est-Mnt-426 | Segundo Pavimento | Projeto: CECAP GuarulhosLocal: Piso: Segundo Pavimento Cômodo: | Estrutura de Parede Cortina -Est-Mnt-426 | 4005.02 | 1355.02 | 4850.02 | 2200.02
APTO5-PC-Est-Mnt-430 | Segundo Pavimento | Projeto: CECAP GuarulhosLocal: Piso: Segundo Pavimento Cômodo: | Estrutura de Parede Cortina -Est-Mnt-430 | 4005 | 1355 | 4850 | 2200
APTO5-PC-Est-Mnt-485 | Segundo Pavimento | Projeto: CECAP GuarulhosLocal: Piso: Segundo Pavimento Cômodo: | Estrutura de Parede Cortina -Est-Mnt-485 | 4005 | 1355 | 4850 | 2200
APTO5-PC-Est-Mnt-486 | Segundo Pavimento | Projeto: CECAP GuarulhosLocal: Piso: Segundo Pavimento Cômodo: | Estrutura de Parede Cortina -Est-Mnt-486 | 4005 | 1355 | 4850 | 2200
APTO5-PC-Est-Mnt-428 | Segundo Pavimento | Projeto: CECAP GuarulhosLocal: Piso: Segundo Pavimento Cômodo: | Estrutura de Parede Cortina -Est-Mnt-428 | 4005 | 1355 | 4850 | 2200
APTO5-PC-Est-Mnt-560 | Segundo Pavimento | Projeto: CECAP GuarulhosLocal: Piso: Segundo Pavimento Cômodo: | Estrutura de Parede Cortina -Est-Mnt-560 | 4005 | 1355 | 4850 | 2200
APTO5-PC-Est-Mnt-429 | Segundo Pavimento | Projeto: CECAP GuarulhosLocal: Piso: Segundo Pavimento Cômodo: | Estrutura de Parede Cortina -Est-Mnt-429 | 4005 | 1355 | 4850 | 2200
APTO5-PC-Est-Mnt-427 | Segundo Pavimento | Projeto: CECAP GuarulhosLocal: Piso: Segundo Pavimento Cômodo: | Estrutura de Parede Cortina -Est-Mnt-427 | 4005 | 1355 | 4850 | 2200
APTO5-PC-Est-Mnt-426 | Segundo Pavimento | Projeto: CECAP GuarulhosLocal: Piso: Segundo Pavimento Cômodo: | Estrutura de Parede Cortina -Est-Mnt-426 | 4005 | 1355 | 4850 | 2200
APTO6-PC-Est-Mnt-430 | Segundo Pavimento | Projeto: CECAP GuarulhosLocal: Piso: Segundo Pavimento Cômodo: | Estrutura de Parede Cortina -Est-Mnt-430 | 4005 | 1355 | 4850 | 2200
APTO6-PC-Est-Mnt-485 | Segundo Pavimento | Projeto: CECAP GuarulhosLocal: Piso: Segundo Pavimento Cômodo: | Estrutura de Parede Cortina -Est-Mnt-485 | 4005 | 1355 | 4850 | 2200
APTO6-PC-Est-Mnt-486 | Segundo Pavimento | Projeto: CECAP GuarulhosLocal: Piso: Segundo Pavimento Cômodo: | Estrutura de Parede Cortina -Est-Mnt-486 | 4005 | 1355 | 4850 | 2200
APTO6-PC-Est-Mnt-428 | Segundo Pavimento | Projeto: CECAP GuarulhosLocal: Piso: Segundo Pavimento Cômodo: | Estrutura de Parede Cortina -Est-Mnt-428 | 4005 | 1355 | 4850 | 2200
APTO6-PC-Est-Mnt-560 | Segundo Pavimento | Projeto: CECAP GuarulhosLocal: Piso: Segundo Pavimento Cômodo: | Estrutura de Parede Cortina -Est-Mnt-560 | 4005 | 1355 | 4850 | 2200
APTO6-PC-Est-Mnt-429 | Segundo Pavimento | Projeto: CECAP GuarulhosLocal: Piso: Segundo Pavimento Cômodo: | Estrutura de Parede Cortina -Est-Mnt-429 | 4005 | 1355 | 4850 | 2200
APTO6-PC-Est-Mnt-427 | Segundo Pavimento | Projeto: CECAP GuarulhosLocal: Piso: Segundo Pavimento Cômodo: | Estrutura de Parede Cortina -Est-Mnt-427 | 4005 | 1355 | 4850 | 2200
APTO6-PC-Est-Mnt-426 | Segundo Pavimento | Projeto: CECAP GuarulhosLocal: Piso: Segundo Pavimento Cômodo: | Estrutura de Parede Cortina -Est-Mnt-426 | 4005 | 1355 | 4850 | 2200
APTO6-PC-Est-Mnt-430 | Segundo Pavimento | Projeto: CECAP GuarulhosLocal: Piso: Segundo Pavimento Cômodo: | Estrutura de Parede Cortina -Est-Mnt-430 | 4005.02 | 1355.02 | 4850.02 | 2200.02
APTO6-PC-Est-Mnt-485 | Segundo Pavimento | Projeto: CECAP GuarulhosLocal: Piso: Segundo Pavimento Cômodo: | Estrutura de Parede Cortina -Est-Mnt-485 | 4005.02 | 1355.02 | 4850.02 | 2200.02
APTO6-PC-Est-Mnt-486 | Segundo Pavimento | Projeto: CECAP GuarulhosLocal: Piso: Segundo Pavimento Cômodo: | Estrutura de Parede Cortina -Est-Mnt-486 | 4005.02 | 1355.02 | 4850.02 | 2200.02
APTO6-PC-Est-Mnt-428 | Segundo Pavimento | Projeto: CECAP GuarulhosLocal: Piso: Segundo Pavimento Cômodo: | Estrutura de Parede Cortina -Est-Mnt-428 | 4005.02 | 1355.02 | 4850.02 | 2200.02
APTO6-PC-Est-Mnt-487 | Segundo Pavimento | Projeto: CECAP GuarulhosLocal: Piso: Segundo Pavimento Cômodo: | Estrutura de Parede Cortina -Est-Mnt-487 | 4005.02 | 1355.02 | 4850.02 | 2200.02
APTO6-PC-Est-Mnt-488 | Segundo Pavimento | Projeto: CECAP GuarulhosLocal: Piso: Segundo Pavimento Cômodo: | Estrutura de Parede Cortina -Est-Mnt-488 | 4005.02 | 1355.02 | 4850.02 | 2200.02
APTO6-PC-Est-Mnt-522 | Segundo Pavimento | Projeto: CECAP GuarulhosLocal: Piso: Segundo Pavimento Cômodo: | Estrutura de Parede Cortina -Est-Mnt-522 | 4005.02 | 1355.02 | 4850.02 | 2200.02
APTO6-PC-Est-Mnt-429 | Segundo Pavimento | Projeto: CECAP GuarulhosLocal: Piso: Segundo Pavimento Cômodo: | Estrutura de Parede Cortina -Est-Mnt-429 | 4005.02 | 1355.02 | 4850.02 | 2200.02
APTO6-PC-Est-Mnt-427 | Segundo Pavimento | Projeto: CECAP GuarulhosLocal: Piso: Segundo Pavimento Cômodo: | Estrutura de Parede Cortina -Est-Mnt-427 | 4005.02 | 1355.02 | 4850.02 | 2200.02
APTO6-PC-Est-Mnt-426 | Segundo Pavimento | Projeto: CECAP GuarulhosLocal: Piso: Segundo Pavimento Cômodo: | Estrutura de Parede Cortina -Est-Mnt-426 | 4005.02 | 1355.02 | 4850.02 | 2200.02
APTO7-PC-Est-Mnt-430 | Segundo Pavimento | Projeto: CECAP GuarulhosLocal: Piso: Segundo Pavimento Cômodo: | Estrutura de Parede Cortina -Est-Mnt-430 | 4005 | 1355 | 4850 | 2200
APTO7-PC-Est-Mnt-485 | Segundo Pavimento | Projeto: CECAP GuarulhosLocal: Piso: Segundo Pavimento Cômodo: | Estrutura de Parede Cortina -Est-Mnt-485 | 4005 | 1355 | 4850 | 2200
APTO7-PC-Est-Mnt-486 | Segundo Pavimento | Projeto: CECAP GuarulhosLocal: Piso: Segundo Pavimento Cômodo: | Estrutura de Parede Cortina -Est-Mnt-486 | 4005 | 1355 | 4850 | 2200
APTO7-PC-Est-Mnt-428 | Segundo Pavimento | Projeto: CECAP GuarulhosLocal: Piso: Segundo Pavimento Cômodo: | Estrutura de Parede Cortina -Est-Mnt-428 | 4005 | 1355 | 4850 | 2200
APTO7-PC-Est-Mnt-560 | Segundo Pavimento | Projeto: CECAP GuarulhosLocal: Piso: Segundo Pavimento Cômodo: | Estrutura de Parede Cortina -Est-Mnt-560 | 4005 | 1355 | 4850 | 2200
APTO7-PC-Est-Mnt-429 | Segundo Pavimento | Projeto: CECAP GuarulhosLocal: Piso: Segundo Pavimento Cômodo: | Estrutura de Parede Cortina -Est-Mnt-429 | 4005 | 1355 | 4850 | 2200
APTO7-PC-Est-Mnt-427 | Segundo Pavimento | Projeto: CECAP GuarulhosLocal: Piso: Segundo Pavimento Cômodo: | Estrutura de Parede Cortina -Est-Mnt-427 | 4005 | 1355 | 4850 | 2200
APTO7-PC-Est-Mnt-426 | Segundo Pavimento | Projeto: CECAP GuarulhosLocal: Piso: Segundo Pavimento Cômodo: | Estrutura de Parede Cortina -Est-Mnt-426 | 4005 | 1355 | 4850 | 2200
APTO7-PC-Est-Mnt-430 | Segundo Pavimento | Projeto: CECAP GuarulhosLocal: Piso: Segundo Pavimento Cômodo: | Estrutura de Parede Cortina -Est-Mnt-430 | 4005.02 | 1355.02 | 4850.02 | 2200.02
APTO7-PC-Est-Mnt-485 | Segundo Pavimento | Projeto: CECAP GuarulhosLocal: Piso: Segundo Pavimento Cômodo: | Estrutura de Parede Cortina -Est-Mnt-485 | 4005.02 | 1355.02 | 4850.02 | 2200.02
APTO7-PC-Est-Mnt-486 | Segundo Pavimento | Projeto: CECAP GuarulhosLocal: Piso: Segundo Pavimento Cômodo: | Estrutura de Parede Cortina -Est-Mnt-486 | 4005.02 | 1355.02 | 4850.02 | 2200.02
APTO7-PC-Est-Mnt-428 | Segundo Pavimento | Projeto: CECAP GuarulhosLocal: Piso: Segundo Pavimento Cômodo: | Estrutura de Parede Cortina -Est-Mnt-428 | 4005.02 | 1355.02 | 4850.02 | 2200.02
APTO7-PC-Est-Mnt-487 | Segundo Pavimento | Projeto: CECAP GuarulhosLocal: Piso: Segundo Pavimento Cômodo: | Estrutura de Parede Cortina -Est-Mnt-487 | 4005.02 | 1355.02 | 4850.02 | 2200.02
APTO7-PC-Est-Mnt-488 | Segundo Pavimento | Projeto: CECAP GuarulhosLocal: Piso: Segundo Pavimento Cômodo: | Estrutura de Parede Cortina -Est-Mnt-488 | 4005.02 | 1355.02 | 4850.02 | 2200.02
APTO7-PC-Est-Mnt-522 | Segundo Pavimento | Projeto: CECAP GuarulhosLocal: Piso: Segundo Pavimento Cômodo: | Estrutura de Parede Cortina -Est-Mnt-522 | 4005.02 | 1355.02 | 4850.02 | 2200.02
APTO7-PC-Est-Mnt-429 | Segundo Pavimento | Projeto: CECAP GuarulhosLocal: Piso: Segundo Pavimento Cômodo: | Estrutura de Parede Cortina -Est-Mnt-429 | 4005.02 | 1355.02 | 4850.02 | 2200.02
APTO7-PC-Est-Mnt-427 | Segundo Pavimento | Projeto: CECAP GuarulhosLocal: Piso: Segundo Pavimento Cômodo: | Estrutura de Parede Cortina -Est-Mnt-427 | 4005.02 | 1355.02 | 4850.02 | 2200.02
APTO7-PC-Est-Mnt-426 | Segundo Pavimento | Projeto: CECAP GuarulhosLocal: Piso: Segundo Pavimento Cômodo: | Estrutura de Parede Cortina -Est-Mnt-426 | 4005.02 | 1355.02 | 4850.02 | 2200.02
APTO8-PC-Est-Mnt-430 | Segundo Pavimento | Projeto: CECAP GuarulhosLocal: Piso: Segundo Pavimento Cômodo: | Estrutura de Parede Cortina -Est-Mnt-430 | 4005 | 1355 | 4850 | 2200
APTO8-PC-Est-Mnt-485 | Segundo Pavimento | Projeto: CECAP GuarulhosLocal: Piso: Segundo Pavimento Cômodo: | Estrutura de Parede Cortina -Est-Mnt-485 | 4005 | 1355 | 4850 | 2200
APTO8-PC-Est-Mnt-486 | Segundo Pavimento | Projeto: CECAP GuarulhosLocal: Piso: Segundo Pavimento Cômodo: | Estrutura de Parede Cortina -Est-Mnt-486 | 4005 | 1355 | 4850 | 2200
APTO8-PC-Est-Mnt-428 | Segundo Pavimento | Projeto: CECAP GuarulhosLocal: Piso: Segundo Pavimento Cômodo: | Estrutura de Parede Cortina -Est-Mnt-428 | 4005 | 1355 | 4850 | 2200
APTO8-PC-Est-Mnt-560 | Segundo Pavimento | Projeto: CECAP GuarulhosLocal: Piso: Segundo Pavimento Cômodo: | Estrutura de Parede Cortina -Est-Mnt-560 | 4005 | 1355 | 4850 | 2200
APTO8-PC-Est-Mnt-429 | Segundo Pavimento | Projeto: CECAP GuarulhosLocal: Piso: Segundo Pavimento Cômodo: | Estrutura de Parede Cortina -Est-Mnt-429 | 4005 | 1355 | 4850 | 2200
APTO8-PC-Est-Mnt-427 | Segundo Pavimento | Projeto: CECAP GuarulhosLocal: Piso: Segundo Pavimento Cômodo: | Estrutura de Parede Cortina -Est-Mnt-427 | 4005 | 1355 | 4850 | 2200
APTO8-PC-Est-Mnt-426 | Segundo Pavimento | Projeto: CECAP GuarulhosLocal: Piso: Segundo Pavimento Cômodo: | Estrutura de Parede Cortina -Est-Mnt-426 | 4005 | 1355 | 4850 | 2200
APTO8-PC-Est-Mnt-430 | Segundo Pavimento | Projeto: CECAP GuarulhosLocal: Piso: Segundo Pavimento Cômodo: | Estrutura de Parede Cortina -Est-Mnt-430 | 4005.02 | 1355.02 | 4850.02 | 2200.02
APTO8-PC-Est-Mnt-485 | Segundo Pavimento | Projeto: CECAP GuarulhosLocal: Piso: Segundo Pavimento Cômodo: | Estrutura de Parede Cortina -Est-Mnt-485 | 4005.02 | 1355.02 | 4850.02 | 2200.02
APTO8-PC-Est-Mnt-486 | Segundo Pavimento | Projeto: CECAP GuarulhosLocal: Piso: Segundo Pavimento Cômodo: | Estrutura de Parede Cortina -Est-Mnt-486 | 4005.02 | 1355.02 | 4850.02 | 2200.02
APTO8-PC-Est-Mnt-428 | Segundo Pavimento | Projeto: CECAP GuarulhosLocal: Piso: Segundo Pavimento Cômodo: | Estrutura de Parede Cortina -Est-Mnt-428 | 4005.02 | 1355.02 | 4850.02 | 2200.02
APTO8-PC-Est-Mnt-487 | Segundo Pavimento | Projeto: CECAP GuarulhosLocal: Piso: Segundo Pavimento Cômodo: | Estrutura de Parede Cortina -Est-Mnt-487 | 4005.02 | 1355.02 | 4850.02 | 2200.02
APTO8-PC-Est-Mnt-488 | Segundo Pavimento | Projeto: CECAP GuarulhosLocal: Piso: Segundo Pavimento Cômodo: | Estrutura de Parede Cortina -Est-Mnt-488 | 4005.02 | 1355.02 | 4850.02 | 2200.02
APTO8-PC-Est-Mnt-522 | Segundo Pavimento | Projeto: CECAP GuarulhosLocal: Piso: Segundo Pavimento Cômodo: | Estrutura de Parede Cortina -Est-Mnt-522 | 4005.02 | 1355.02 | 4850.02 | 2200.02
APTO8-PC-Est-Mnt-429 | Segundo Pavimento | Projeto: CECAP GuarulhosLocal: Piso: Segundo Pavimento Cômodo: | Estrutura de Parede Cortina -Est-Mnt-429 | 4005.02 | 1355.02 | 4850.02 | 2200.02
APTO8-PC-Est-Mnt-427 | Segundo Pavimento | Projeto: CECAP GuarulhosLocal: Piso: Segundo Pavimento Cômodo: | Estrutura de Parede Cortina -Est-Mnt-427 | 4005.02 | 1355.02 | 4850.02 | 2200.02
APTO8-PC-Est-Mnt-426 | Segundo Pavimento | Projeto: CECAP GuarulhosLocal: Piso: Segundo Pavimento Cômodo: | Estrutura de Parede Cortina -Est-Mnt-426 | 4005.02 | 1355.02 | 4850.02 | 2200.02
APTO9-PC-Est-Mnt-430 | Terceiro Pavimento | Projeto: CECAP GuarulhosLocal: Piso: Terceiro Pavimento Cômodo: | Estrutura de Parede Cortina -Est-Mnt-430 | 6655 | 1355 | 7500 | 2200
APTO9-PC-Est-Mnt-485 | Terceiro Pavimento | Projeto: CECAP GuarulhosLocal: Piso: Terceiro Pavimento Cômodo: | Estrutura de Parede Cortina -Est-Mnt-485 | 6655 | 1355 | 7500 | 2200
APTO9-PC-Est-Mnt-486 | Terceiro Pavimento | Projeto: CECAP GuarulhosLocal: Piso: Terceiro Pavimento Cômodo: | Estrutura de Parede Cortina -Est-Mnt-486 | 6655 | 1355 | 7500 | 2200
APTO9-PC-Est-Mnt-428 | Terceiro Pavimento | Projeto: CECAP GuarulhosLocal: Piso: Terceiro Pavimento Cômodo: | Estrutura de Parede Cortina -Est-Mnt-428 | 6655 | 1355 | 7500 | 2200
APTO9-PC-Est-Mnt-560 | Terceiro Pavimento | Projeto: CECAP GuarulhosLocal: Piso: Terceiro Pavimento Cômodo: | Estrutura de Parede Cortina -Est-Mnt-560 | 6655 | 1355 | 7500 | 2200
APTO9-PC-Est-Mnt-429 | Terceiro Pavimento | Projeto: CECAP GuarulhosLocal: Piso: Terceiro Pavimento Cômodo: | Estrutura de Parede Cortina -Est-Mnt-429 | 6655 | 1355 | 7500 | 2200
APTO9-PC-Est-Mnt-427 | Terceiro Pavimento | Projeto: CECAP GuarulhosLocal: Piso: Terceiro Pavimento Cômodo: | Estrutura de Parede Cortina -Est-Mnt-427 | 6655 | 1355 | 7500 | 2200
APTO9-PC-Est-Mnt-426 | Terceiro Pavimento | Projeto: CECAP GuarulhosLocal: Piso: Terceiro Pavimento Cômodo: | Estrutura de Parede Cortina -Est-Mnt-426 | 6655 | 1355 | 7500 | 2200
APTO9-PC-Est-Mnt-430 | Terceiro Pavimento | Projeto: CECAP GuarulhosLocal: Piso: Terceiro Pavimento Cômodo: | Estrutura de Parede Cortina -Est-Mnt-430 | 6655.02 | 1355.02 | 7500.02 | 2200.02
APTO9-PC-Est-Mnt-485 | Terceiro Pavimento | Projeto: CECAP GuarulhosLocal: Piso: Terceiro Pavimento Cômodo: | Estrutura de Parede Cortina -Est-Mnt-485 | 6655.02 | 1355.02 | 7500.02 | 2200.02
APTO9-PC-Est-Mnt-486 | Terceiro Pavimento | Projeto: CECAP GuarulhosLocal: Piso: Terceiro Pavimento Cômodo: | Estrutura de Parede Cortina -Est-Mnt-486 | 6655.02 | 1355.02 | 7500.02 | 2200.02
APTO9-PC-Est-Mnt-428 | Terceiro Pavimento | Projeto: CECAP GuarulhosLocal: Piso: Terceiro Pavimento Cômodo: | Estrutura de Parede Cortina -Est-Mnt-428 | 6655.02 | 1355.02 | 7500.02 | 2200.02
APTO9-PC-Est-Mnt-487 | Terceiro Pavimento | Projeto: CECAP GuarulhosLocal: Piso: Terceiro Pavimento Cômodo: | Estrutura de Parede Cortina -Est-Mnt-487 | 6655.02 | 1355.02 | 7500.02 | 2200.02
APTO9-PC-Est-Mnt-488 | Terceiro Pavimento | Projeto: CECAP GuarulhosLocal: Piso: Terceiro Pavimento Cômodo: | Estrutura de Parede Cortina -Est-Mnt-488 | 6655.02 | 1355.02 | 7500.02 | 2200.02
APTO9-PC-Est-Mnt-522 | Terceiro Pavimento | Projeto: CECAP GuarulhosLocal: Piso: Terceiro Pavimento Cômodo: | Estrutura de Parede Cortina -Est-Mnt-522 | 6655.02 | 1355.02 | 7500.02 | 2200.02
APTO9-PC-Est-Mnt-429 | Terceiro Pavimento | Projeto: CECAP GuarulhosLocal: Piso: Terceiro Pavimento Cômodo: | Estrutura de Parede Cortina -Est-Mnt-429 | 6655.02 | 1355.02 | 7500.02 | 2200.02
APTO9-PC-Est-Mnt-427 | Terceiro Pavimento | Projeto: CECAP GuarulhosLocal: Piso: Terceiro Pavimento Cômodo: | Estrutura de Parede Cortina -Est-Mnt-427 | 6655.02 | 1355.02 | 7500.02 | 2200.02
APTO9-PC-Est-Mnt-426 | Terceiro Pavimento | Projeto: CECAP GuarulhosLocal: Piso: Terceiro Pavimento Cômodo: | Estrutura de Parede Cortina -Est-Mnt-426 | 6655.02 | 1355.02 | 7500.02 | 2200.02
APTO10-PC-Est-Mnt-430 | Terceiro Pavimento | Projeto: CECAP GuarulhosLocal: Piso: Terceiro Pavimento Cômodo: | Estrutura de Parede Cortina -Est-Mnt-430 | 6655 | 1355 | 7500 | 2200
APTO10-PC-Est-Mnt-485 | Terceiro Pavimento | Projeto: CECAP GuarulhosLocal: Piso: Terceiro Pavimento Cômodo: | Estrutura de Parede Cortina -Est-Mnt-485 | 6655 | 1355 | 7500 | 2200
APTO10-PC-Est-Mnt-486 | Terceiro Pavimento | Projeto: CECAP GuarulhosLocal: Piso: Terceiro Pavimento Cômodo: | Estrutura de Parede Cortina -Est-Mnt-486 | 6655 | 1355 | 7500 | 2200
APTO10-PC-Est-Mnt-428 | Terceiro Pavimento | Projeto: CECAP GuarulhosLocal: Piso: Terceiro Pavimento Cômodo: | Estrutura de Parede Cortina -Est-Mnt-428 | 6655 | 1355 | 7500 | 2200
APTO10-PC-Est-Mnt-560 | Terceiro Pavimento | Projeto: CECAP GuarulhosLocal: Piso: Terceiro Pavimento Cômodo: | Estrutura de Parede Cortina -Est-Mnt-560 | 6655 | 1355 | 7500 | 2200
APTO10-PC-Est-Mnt-429 | Terceiro Pavimento | Projeto: CECAP GuarulhosLocal: Piso: Terceiro Pavimento Cômodo: | Estrutura de Parede Cortina -Est-Mnt-429 | 6655 | 1355 | 7500 | 2200
APTO10-PC-Est-Mnt-427 | Terceiro Pavimento | Projeto: CECAP GuarulhosLocal: Piso: Terceiro Pavimento Cômodo: | Estrutura de Parede Cortina -Est-Mnt-427 | 6655 | 1355 | 7500 | 2200
APTO10-PC-Est-Mnt-426 | Terceiro Pavimento | Projeto: CECAP GuarulhosLocal: Piso: Terceiro Pavimento Cômodo: | Estrutura de Parede Cortina -Est-Mnt-426 | 6655 | 1355 | 7500 | 2200
APTO10-PC-Est-Mnt-430 | Terceiro Pavimento | Projeto: CECAP GuarulhosLocal: Piso: Terceiro Pavimento Cômodo: | Estrutura de Parede Cortina -Est-Mnt-430 | 6655.02 | 1355.02 | 7500.02 | 2200.02
APTO10-PC-Est-Mnt-485 | Terceiro Pavimento | Projeto: CECAP GuarulhosLocal: Piso: Terceiro Pavimento Cômodo: | Estrutura de Parede Cortina -Est-Mnt-485 | 6655.02 | 1355.02 | 7500.02 | 2200.02
APTO10-PC-Est-Mnt-486 | Terceiro Pavimento | Projeto: CECAP GuarulhosLocal: Piso: Terceiro Pavimento Cômodo: | Estrutura de Parede Cortina -Est-Mnt-486 | 6655.02 | 1355.02 | 7500.02 | 2200.02
APTO10-PC-Est-Mnt-428 | Terceiro Pavimento | Projeto: CECAP GuarulhosLocal: Piso: Terceiro Pavimento Cômodo: | Estrutura de Parede Cortina -Est-Mnt-428 | 6655.02 | 1355.02 | 7500.02 | 2200.02
APTO10-PC-Est-Mnt-487 | Terceiro Pavimento | Projeto: CECAP GuarulhosLocal: Piso: Terceiro Pavimento Cômodo: | Estrutura de Parede Cortina -Est-Mnt-487 | 6655.02 | 1355.02 | 7500.02 | 2200.02
APTO10-PC-Est-Mnt-488 | Terceiro Pavimento | Projeto: CECAP GuarulhosLocal: Piso: Terceiro Pavimento Cômodo: | Estrutura de Parede Cortina -Est-Mnt-488 | 6655.02 | 1355.02 | 7500.02 | 2200.02
APTO10-PC-Est-Mnt-522 | Terceiro Pavimento | Projeto: CECAP GuarulhosLocal: Piso: Terceiro Pavimento Cômodo: | Estrutura de Parede Cortina -Est-Mnt-522 | 6655.02 | 1355.02 | 7500.02 | 2200.02
APTO10-PC-Est-Mnt-429 | Terceiro Pavimento | Projeto: CECAP GuarulhosLocal: Piso: Terceiro Pavimento Cômodo: | Estrutura de Parede Cortina -Est-Mnt-429 | 6655.02 | 1355.02 | 7500.02 | 2200.02
APTO10-PC-Est-Mnt-427 | Terceiro Pavimento | Projeto: CECAP GuarulhosLocal: Piso: Terceiro Pavimento Cômodo: | Estrutura de Parede Cortina -Est-Mnt-427 | 6655.02 | 1355.02 | 7500.02 | 2200.02
APTO10-PC-Est-Mnt-426 | Terceiro Pavimento | Projeto: CECAP GuarulhosLocal: Piso: Terceiro Pavimento Cômodo: | Estrutura de Parede Cortina -Est-Mnt-426 | 6655.02 | 1355.02 | 7500.02 | 2200.02
APTO11-PC-Est-Mnt-430 | Terceiro Pavimento | Projeto: CECAP GuarulhosLocal: Piso: Terceiro Pavimento Cômodo: | Estrutura de Parede Cortina -Est-Mnt-430 | 6655 | 1355 | 7500 | 2200
APTO11-PC-Est-Mnt-485 | Terceiro Pavimento | Projeto: CECAP GuarulhosLocal: Piso: Terceiro Pavimento Cômodo: | Estrutura de Parede Cortina -Est-Mnt-485 | 6655 | 1355 | 7500 | 2200
APTO11-PC-Est-Mnt-486 | Terceiro Pavimento | Projeto: CECAP GuarulhosLocal: Piso: Terceiro Pavimento Cômodo: | Estrutura de Parede Cortina -Est-Mnt-486 | 6655 | 1355 | 7500 | 2200
APTO11-PC-Est-Mnt-428 | Terceiro Pavimento | Projeto: CECAP GuarulhosLocal: Piso: Terceiro Pavimento Cômodo: | Estrutura de Parede Cortina -Est-Mnt-428 | 6655 | 1355 | 7500 | 2200
APTO11-PC-Est-Mnt-560 | Terceiro Pavimento | Projeto: CECAP GuarulhosLocal: Piso: Terceiro Pavimento Cômodo: | Estrutura de Parede Cortina -Est-Mnt-560 | 6655 | 1355 | 7500 | 2200
APTO11-PC-Est-Mnt-429 | Terceiro Pavimento | Projeto: CECAP GuarulhosLocal: Piso: Terceiro Pavimento Cômodo: | Estrutura de Parede Cortina -Est-Mnt-429 | 6655 | 1355 | 7500 | 2200
APTO11-PC-Est-Mnt-427 | Terceiro Pavimento | Projeto: CECAP GuarulhosLocal: Piso: Terceiro Pavimento Cômodo: | Estrutura de Parede Cortina -Est-Mnt-427 | 6655 | 1355 | 7500 | 2200
APTO11-PC-Est-Mnt-426 | Terceiro Pavimento | Projeto: CECAP GuarulhosLocal: Piso: Terceiro Pavimento Cômodo: | Estrutura de Parede Cortina -Est-Mnt-426 | 6655 | 1355 | 7500 | 2200
APTO11-PC-Est-Mnt-430 | Terceiro Pavimento | Projeto: CECAP GuarulhosLocal: Piso: Terceiro Pavimento Cômodo: | Estrutura de Parede Cortina -Est-Mnt-430 | 6655.02 | 1355.02 | 7500.02 | 2200.02
APTO11-PC-Est-Mnt-485 | Terceiro Pavimento | Projeto: CECAP GuarulhosLocal: Piso: Terceiro Pavimento Cômodo: | Estrutura de Parede Cortina -Est-Mnt-485 | 6655.02 | 1355.02 | 7500.02 | 2200.02
APTO11-PC-Est-Mnt-486 | Terceiro Pavimento | Projeto: CECAP GuarulhosLocal: Piso: Terceiro Pavimento Cômodo: | Estrutura de Parede Cortina -Est-Mnt-486 | 6655.02 | 1355.02 | 7500.02 | 2200.02
APTO11-PC-Est-Mnt-428 | Terceiro Pavimento | Projeto: CECAP GuarulhosLocal: Piso: Terceiro Pavimento Cômodo: | Estrutura de Parede Cortina -Est-Mnt-428 | 6655.02 | 1355.02 | 7500.02 | 2200.02
APTO11-PC-Est-Mnt-487 | Terceiro Pavimento | Projeto: CECAP GuarulhosLocal: Piso: Terceiro Pavimento Cômodo: | Estrutura de Parede Cortina -Est-Mnt-487 | 6655.02 | 1355.02 | 7500.02 | 2200.02
APTO11-PC-Est-Mnt-488 | Terceiro Pavimento | Projeto: CECAP GuarulhosLocal: Piso: Terceiro Pavimento Cômodo: | Estrutura de Parede Cortina -Est-Mnt-488 | 6655.02 | 1355.02 | 7500.02 | 2200.02
APTO11-PC-Est-Mnt-522 | Terceiro Pavimento | Projeto: CECAP GuarulhosLocal: Piso: Terceiro Pavimento Cômodo: | Estrutura de Parede Cortina -Est-Mnt-522 | 6655.02 | 1355.02 | 7500.02 | 2200.02
APTO11-PC-Est-Mnt-429 | Terceiro Pavimento | Projeto: CECAP GuarulhosLocal: Piso: Terceiro Pavimento Cômodo: | Estrutura de Parede Cortina -Est-Mnt-429 | 6655.02 | 1355.02 | 7500.02 | 2200.02
APTO11-PC-Est-Mnt-427 | Terceiro Pavimento | Projeto: CECAP GuarulhosLocal: Piso: Terceiro Pavimento Cômodo: | Estrutura de Parede Cortina -Est-Mnt-427 | 6655.02 | 1355.02 | 7500.02 | 2200.02
APTO11-PC-Est-Mnt-426 | Terceiro Pavimento | Projeto: CECAP GuarulhosLocal: Piso: Terceiro Pavimento Cômodo: | Estrutura de Parede Cortina -Est-Mnt-426 | 6655.02 | 1355.02 | 7500.02 | 2200.02
APTO12-PC-Est-Mnt-430 | Terceiro Pavimento | Projeto: CECAP GuarulhosLocal: Piso: Terceiro Pavimento Cômodo: | Estrutura de Parede Cortina -Est-Mnt-430 | 6655 | 1355 | 7500 | 2200
APTO12-PC-Est-Mnt-485 | Terceiro Pavimento | Projeto: CECAP GuarulhosLocal: Piso: Terceiro Pavimento Cômodo: | Estrutura de Parede Cortina -Est-Mnt-485 | 6655 | 1355 | 7500 | 2200
APTO12-PC-Est-Mnt-486 | Terceiro Pavimento | Projeto: CECAP GuarulhosLocal: Piso: Terceiro Pavimento Cômodo: | Estrutura de Parede Cortina -Est-Mnt-486 | 6655 | 1355 | 7500 | 2200
APTO12-PC-Est-Mnt-428 | Terceiro Pavimento | Projeto: CECAP GuarulhosLocal: Piso: Terceiro Pavimento Cômodo: | Estrutura de Parede Cortina -Est-Mnt-428 | 6655 | 1355 | 7500 | 2200
APTO12-PC-Est-Mnt-560 | Terceiro Pavimento | Projeto: CECAP GuarulhosLocal: Piso: Terceiro Pavimento Cômodo: | Estrutura de Parede Cortina -Est-Mnt-560 | 6655 | 1355 | 7500 | 2200
APTO12-PC-Est-Mnt-429 | Terceiro Pavimento | Projeto: CECAP GuarulhosLocal: Piso: Terceiro Pavimento Cômodo: | Estrutura de Parede Cortina -Est-Mnt-429 | 6655 | 1355 | 7500 | 2200
APTO12-PC-Est-Mnt-427 | Terceiro Pavimento | Projeto: CECAP GuarulhosLocal: Piso: Terceiro Pavimento Cômodo: | Estrutura de Parede Cortina -Est-Mnt-427 | 6655 | 1355 | 7500 | 2200
APTO12-PC-Est-Mnt-426 | Terceiro Pavimento | Projeto: CECAP GuarulhosLocal: Piso: Terceiro Pavimento Cômodo: | Estrutura de Parede Cortina -Est-Mnt-426 | 6655 | 1355 | 7500 | 2200
APTO12-PC-Est-Mnt-430 | Terceiro Pavimento | Projeto: CECAP GuarulhosLocal: Piso: Terceiro Pavimento Cômodo: | Estrutura de Parede Cortina -Est-Mnt-430 | 6655.02 | 1355.02 | 7500.02 | 2200.02
APTO12-PC-Est-Mnt-485 | Terceiro Pavimento | Projeto: CECAP GuarulhosLocal: Piso: Terceiro Pavimento Cômodo: | Estrutura de Parede Cortina -Est-Mnt-485 | 6655.02 | 1355.02 | 7500.02 | 2200.02
APTO12-PC-Est-Mnt-486 | Terceiro Pavimento | Projeto: CECAP GuarulhosLocal: Piso: Terceiro Pavimento Cômodo: | Estrutura de Parede Cortina -Est-Mnt-486 | 6655.02 | 1355.02 | 7500.02 | 2200.02
APTO12-PC-Est-Mnt-428 | Terceiro Pavimento | Projeto: CECAP GuarulhosLocal: Piso: Terceiro Pavimento Cômodo: | Estrutura de Parede Cortina -Est-Mnt-428 | 6655.02 | 1355.02 | 7500.02 | 2200.02
APTO12-PC-Est-Mnt-487 | Terceiro Pavimento | Projeto: CECAP GuarulhosLocal: Piso: Terceiro Pavimento Cômodo: | Estrutura de Parede Cortina -Est-Mnt-487 | 6655.02 | 1355.02 | 7500.02 | 2200.02
APTO12-PC-Est-Mnt-488 | Terceiro Pavimento | Projeto: CECAP GuarulhosLocal: Piso: Terceiro Pavimento Cômodo: | Estrutura de Parede Cortina -Est-Mnt-488 | 6655.02 | 1355.02 | 7500.02 | 2200.02
APTO12-PC-Est-Mnt-522 | Terceiro Pavimento | Projeto: CECAP GuarulhosLocal: Piso: Terceiro Pavimento Cômodo: | Estrutura de Parede Cortina -Est-Mnt-522 | 6655.02 | 1355.02 | 7500.02 | 2200.02
APTO12-PC-Est-Mnt-429 | Terceiro Pavimento | Projeto: CECAP GuarulhosLocal: Piso: Terceiro Pavimento Cômodo: | Estrutura de Parede Cortina -Est-Mnt-429 | 6655.02 | 1355.02 | 7500.02 | 2200.02
APTO12-PC-Est-Mnt-427 | Terceiro Pavimento | Projeto: CECAP GuarulhosLocal: Piso: Terceiro Pavimento Cômodo: | Estrutura de Parede Cortina -Est-Mnt-427 | 6655.02 | 1355.02 | 7500.02 | 2200.02
APTO12-PC-Est-Mnt-426 | Terceiro Pavimento | Projeto: CECAP GuarulhosLocal: Piso: Terceiro Pavimento Cômodo: | Estrutura de Parede Cortina -Est-Mnt-426 | 6655.02 | 1355.02 | 7500.02 | 2200.02

# IfcOpeningElement (60)
BaseQuantities - Height: 2100 mm
Name | In | Depth (mm) | Width (mm) | Area (m2) | Volume (m3)
APTO4-PORTA-002 | Primeiro Pavimento | 40 | 900 | 1.89 | 0.0592503
APTO4-PORTA-001 | Primeiro Pavimento | 40 | 900 | 1.89 | 0.0592503
APTO4-PORTA-000 | Primeiro Pavimento | 40 | 900 | 1.89 | 0.0592503
APTO4-PORTA-003 | Primeiro Pavimento | 90 | 710 | 1.491 | 0.0592103
APTO4-PORTA-004 | Primeiro Pavimento | 140 | 900 | 1.89 | 0.0842503
APTO3-PORTA-002 | Primeiro Pavimento | 40 | 900 | 1.89 | 0.0592503
APTO3-PORTA-001 | Primeiro Pavimento | 40 | 900 | 1.89 | 0.0592503
APTO3-PORTA-000 | Primeiro Pavimento | 40 | 900 | 1.89 | 0.0592503
APTO2-PORTA-003 | Primeiro Pavimento | 90 | 710 | 1.491 | 0.0592103
APTO2-PORTA-004 | Primeiro Pavimento | 140 | 900 | 1.89 | 0.0842503
APTO2-PORTA-002 | Primeiro Pavimento | 40 | 900 | 1.89 | 0.0592503
APTO2-PORTA-001 | Primeiro Pavimento | 40 | 900 | 1.89 | 0.0592503
APTO2-PORTA-000 | Primeiro Pavimento | 40 | 900 | 1.89 | 0.0592503
APTO3-PORTA-003 | Primeiro Pavimento | 90 | 710 | 1.491 | 0.0592103
APTO3-PORTA-004 | Primeiro Pavimento | 140 | 900 | 1.89 | 0.0842503
APTO1-PORTA-002 | Primeiro Pavimento | 40 | 900 | 1.89 | 0.0592503
APTO1-PORTA-001 | Primeiro Pavimento | 40 | 900 | 1.89 | 0.0592503
APTO1-PORTA-000 | Primeiro Pavimento | 40 | 900 | 1.89 | 0.0592503
APTO1-PORTA-004 | Primeiro Pavimento | 140 | 900 | 1.89 | 0.0842503
APTO1-PORTA-003 | Primeiro Pavimento | 90 | 710 | 1.491 | 0.0592103
APTO5-PORTA-002 | Segundo Pavimento | 40 | 900 | 1.89 | 0.0592503
APTO5-PORTA-001 | Segundo Pavimento | 40 | 900 | 1.89 | 0.0592503
APTO5-PORTA-000 | Segundo Pavimento | 40 | 900 | 1.89 | 0.0592503
APTO5-PORTA-003 | Segundo Pavimento | 90 | 710 | 1.491 | 0.0592103
APTO5-PORTA-004 | Segundo Pavimento | 140 | 900 | 1.89 | 0.0842503
APTO6-PORTA-003 | Segundo Pavimento | 90 | 710 | 1.491 | 0.0592103
APTO6-PORTA-004 | Segundo Pavimento | 140 | 900 | 1.89 | 0.0842503
APTO6-PORTA-002 | Segundo Pavimento | 40 | 900 | 1.89 | 0.0592503
APTO6-PORTA-001 | Segundo Pavimento | 40 | 900 | 1.89 | 0.0592503
APTO6-PORTA-000 | Segundo Pavimento | 40 | 900 | 1.89 | 0.0592503
APTO7-PORTA-003 | Segundo Pavimento | 90 | 710 | 1.491 | 0.0592103
APTO7-PORTA-004 | Segundo Pavimento | 140 | 900 | 1.89 | 0.0842503
APTO7-PORTA-002 | Segundo Pavimento | 40 | 900 | 1.89 | 0.0592503
APTO7-PORTA-001 | Segundo Pavimento | 40 | 900 | 1.89 | 0.0592503
APTO7-PORTA-000 | Segundo Pavimento | 40 | 900 | 1.89 | 0.0592503
APTO8-PORTA-003 | Segundo Pavimento | 90 | 710 | 1.491 | 0.0592103
APTO8-PORTA-004 | Segundo Pavimento | 140 | 900 | 1.89 | 0.0842503
APTO8-PORTA-002 | Segundo Pavimento | 40 | 900 | 1.89 | 0.0592503
APTO8-PORTA-001 | Segundo Pavimento | 40 | 900 | 1.89 | 0.0592503
APTO8-PORTA-000 | Segundo Pavimento | 40 | 900 | 1.89 | 0.0592503
APTO9-PORTA-003 | Terceiro Pavimento | 90 | 710 | 1.491 | 0.0592103
APTO9-PORTA-004 | Terceiro Pavimento | 140 | 900 | 1.89 | 0.0842503
APTO9-PORTA-002 | Terceiro Pavimento | 40 | 900 | 1.89 | 0.0592503
APTO9-PORTA-001 | Terceiro Pavimento | 40 | 900 | 1.89 | 0.0592503
APTO9-PORTA-000 | Terceiro Pavimento | 40 | 900 | 1.89 | 0.0592503
APTO10-PORTA-003 | Terceiro Pavimento | 90 | 710 | 1.491 | 0.0592103
APTO10-PORTA-004 | Terceiro Pavimento | 140 | 900 | 1.89 | 0.0842503
APTO10-PORTA-002 | Terceiro Pavimento | 40 | 900 | 1.89 | 0.0592503
APTO10-PORTA-001 | Terceiro Pavimento | 40 | 900 | 1.89 | 0.0592503
APTO10-PORTA-000 | Terceiro Pavimento | 40 | 900 | 1.89 | 0.0592503
APTO11-PORTA-003 | Terceiro Pavimento | 90 | 710 | 1.491 | 0.0592103
APTO11-PORTA-004 | Terceiro Pavimento | 140 | 900 | 1.89 | 0.0842503
APTO11-PORTA-002 | Terceiro Pavimento | 40 | 900 | 1.89 | 0.0592503
APTO11-PORTA-001 | Terceiro Pavimento | 40 | 900 | 1.89 | 0.0592503
APTO11-PORTA-000 | Terceiro Pavimento | 40 | 900 | 1.89 | 0.0592503
APTO12-PORTA-003 | Terceiro Pavimento | 90 | 710 | 1.491 | 0.0592103
APTO12-PORTA-004 | Terceiro Pavimento | 140 | 900 | 1.89 | 0.0842503
APTO12-PORTA-002 | Terceiro Pavimento | 40 | 900 | 1.89 | 0.0592503
APTO12-PORTA-001 | Terceiro Pavimento | 40 | 900 | 1.89 | 0.0592503
APTO12-PORTA-000 | Terceiro Pavimento | 40 | 900 | 1.89 | 0.0592503

# IfcPlate: Painel Principal 685 x 845 x 20 (12)
Type - PredefinedType: CURTAIN_PANEL
Classification: Painel de Parede Cortina (Classificação ARCHICAD)
Pset_ManufacturerOccurrence - SerialNumber: Desligado
INFORMAÇÕES DO PRODUTO - Data de Aquisição: DD/MM/YYYY
FABRICAÇÃO - Data de Fabricação: DD/MM/YYYY; Site do Produto: www.graphisoft.com
GARANTIA - Ínicio da Garantia: DD/MM/YYYY; Fim da Garantia: DD/MM/YYYY
EXPRESSÕES DE TEXTO (Expressão) - ID Dinâmico por Classificação: Painel de Parede Cortina -Prin-031
SUPERFÍCIES (Mapas) - Superfície da Face (Geral): Metal - Alumínio
AC_Pset_RenovationAndPhasing - Renovation Status: Não definido
BaseQuantities - Width: 665 mm; Perimeter: 3020 mm; GrossArea: 0.578825 m2; NetArea: 0.561925 m2; GrossVolume: 0.0115765 m3; NetVolume: 0.0112385 m3
ArchiCADQuantities - Altura: 845 mm; Volume (Líquido): 0.0166704 m3; Largura: 665 mm; Elevação ao Piso: 1355.02 mm; Afastamento da Origem: 1355.02 mm; Área da Superfície: 0.561925 m2; Espessura: 20 mm; Perímetro em 3D: 3020 mm; Elevação do Topo Ao Piso de Origem: 2200.02 mm; Elevação da Base Ao Piso de Origem: 1355.02 mm; Área da Superfície da Base (Líquida): 0.561925 m2; Área do Painel com Grampos: 0.578825 m2; Altura Nominal: 845 mm; Área do Painel sem Grampos: 0.561925 m2; Largura Nominal: 665 mm
AC_Equantity_Janela_PC_25 - Dimensão 1: 1000 mm; Dimensão 2: 1000 mm; Altura (ZZYZX): 1000 mm; Nível da Base: 1000 mm; Nível do Topo: 0 mm; Largura Cinta: 20 mm; Afastamento Painel: 0 mm; Espessura: 55 mm; Largura: 665 mm; Largura Nominal: 665 mm; Altura (ac_height): 845 mm; Altura Nominal: 845 mm; Largura Batente: 45 mm; Espessura Batente: 55 mm; Largura Reentrância Estrutura: 25 mm; Espessura Reentrância Estrutura: 50 mm; Largura Adaptador: 25 mm; Espessura Adaptador: 60 mm; Espessura Estrutura Caixilho: 55 mm; Largura Caixilho: 45 mm; Espessura Vidro: 16 mm; Afastamento Vidro: 10 mm; Espessura Grelha: 20 mm; Largura Grelha Horizontal: 10 mm; Largura Grelha Vertical: 10 mm
Name | In | Localização do Produto no Projeto | ID de Aberturas com Master ID | Elevação à Origem do Projeto (mm) = Elevação ao 1º Nível de Referência (mm) = Elevação ao 2º Nível de Referência (mm) = Elevação ao Nível do Mar (mm) = Elevação da Base Ao Primeiro Nível de Referência (mm) = Elevação da Base À Cota Zero (mm) = Elevação da Base Ao Nível do Mar (mm) = Elevação da Base Ao Segundo Nível de Referência (mm) | Elevação do Topo ao Primeiro Nível de Referência (mm) = Elevação do Topo À Cota Zero (mm) = Elevação do Topo Ao Nível do Mar (mm) = Elevação do Topo Ao Segundo Nível de Referência (mm)
APTO4-Painel-Prin-031 | Primeiro Pavimento | Projeto: CECAP GuarulhosLocal: Piso: Primeiro Pavimento Cômodo: | APTO4-Prin-031 | 1355.02 | 2200.02
APTO3-Painel-Prin-031 | Primeiro Pavimento | Projeto: CECAP GuarulhosLocal: Piso: Primeiro Pavimento Cômodo: | APTO3-Prin-031 | 1355.02 | 2200.02
APTO2-Painel-Prin-031 | Primeiro Pavimento | Projeto: CECAP GuarulhosLocal: Piso: Primeiro Pavimento Cômodo: | APTO2-Prin-031 | 1355.02 | 2200.02
APTO1-Painel-Prin-031 | Primeiro Pavimento | Projeto: CECAP GuarulhosLocal: Piso: Primeiro Pavimento Cômodo: | APTO1-Prin-031 | 1355.02 | 2200.02
APTO5-Painel-Prin-031 | Segundo Pavimento | Projeto: CECAP GuarulhosLocal: Piso: Segundo Pavimento Cômodo: | APTO5-Prin-031 | 4005.02 | 4850.02
APTO6-Painel-Prin-031 | Segundo Pavimento | Projeto: CECAP GuarulhosLocal: Piso: Segundo Pavimento Cômodo: | APTO6-Prin-031 | 4005.02 | 4850.02
APTO7-Painel-Prin-031 | Segundo Pavimento | Projeto: CECAP GuarulhosLocal: Piso: Segundo Pavimento Cômodo: | APTO7-Prin-031 | 4005.02 | 4850.02
APTO8-Painel-Prin-031 | Segundo Pavimento | Projeto: CECAP GuarulhosLocal: Piso: Segundo Pavimento Cômodo: | APTO8-Prin-031 | 4005.02 | 4850.02
APTO9-Painel-Prin-031 | Terceiro Pavimento | Projeto: CECAP GuarulhosLocal: Piso: Terceiro Pavimento Cômodo: | APTO9-Prin-031 | 6655.02 | 7500.02
APTO10-Painel-Prin-031 | Terceiro Pavimento | Projeto: CECAP GuarulhosLocal: Piso: Terceiro Pavimento Cômodo: | APTO10-Prin-031 | 6655.02 | 7500.02
APTO11-Painel-Prin-031 | Terceiro Pavimento | Projeto: CECAP GuarulhosLocal: Piso: Terceiro Pavimento Cômodo: | APTO11-Prin-031 | 6655.02 | 7500.02
APTO12-Painel-Prin-031 | Terceiro Pavimento | Projeto: CECAP GuarulhosLocal: Piso: Terceiro Pavimento Cômodo: | APTO12-Prin-031 | 6655.02 | 7500.02

# IfcPlate: Painel Principal 690 x 845 x 20 (192)
Type - PredefinedType: CURTAIN_PANEL
Classification: Painel de Parede Cortina (Classificação ARCHICAD)
Pset_ManufacturerOccurrence - SerialNumber: Desligado
INFORMAÇÕES DO PRODUTO - Data de Aquisição: DD/MM/YYYY
FABRICAÇÃO - Data de Fabricação: DD/MM/YYYY; Site do Produto: www.graphisoft.com
GARANTIA - Ínicio da Garantia: DD/MM/YYYY; Fim da Garantia: DD/MM/YYYY
SUPERFÍCIES (Mapas) - Superfície da Face (Geral): Metal - Alumínio
AC_Pset_RenovationAndPhasing - Renovation Status: Não definido
BaseQuantities - Width: 650 mm; Perimeter: 2990 mm; GrossArea: 0.58305 m2; NetArea: 0.54925 m2; GrossVolume: 0.011661 m3; NetVolume: 0.010985 m3
ArchiCADQuantities - Altura: 845 mm; Volume (Líquido): 0.0167258 m3; Largura: 650 mm; Área da Superfície: 0.54925 m2; Espessura: 20 mm; Perímetro em 3D: 2990 mm; Área da Superfície da Base (Líquida): 0.54925 m2; Área do Painel com Grampos: 0.58305 m2; Altura Nominal: 845 mm; Área do Painel sem Grampos: 0.54925 m2; Largura Nominal: 650 mm
AC_Equantity_Janela_PC_25 - Dimensão 1: 1000 mm; Dimensão 2: 1000 mm; Altura (ZZYZX): 1000 mm; Nível da Base: 1000 mm; Nível do Topo: 0 mm; Largura Cinta: 20 mm; Afastamento Painel: 0 mm; Espessura: 55 mm; Largura: 650 mm; Largura Nominal: 650 mm; Altura (ac_height): 845 mm; Altura Nominal: 845 mm; Largura Batente: 45 mm; Espessura Batente: 55 mm; Largura Reentrância Estrutura: 25 mm; Espessura Reentrância Estrutura: 50 mm; Largura Adaptador: 25 mm; Espessura Adaptador: 60 mm; Espessura Estrutura Caixilho: 55 mm; Largura Caixilho: 45 mm; Espessura Vidro: 16 mm; Afastamento Vidro: 10 mm; Espessura Grelha: 20 mm; Largura Grelha Horizontal: 10 mm; Largura Grelha Vertical: 10 mm
Name | In | Localização do Produto no Projeto | ID de Aberturas com Master ID | ID Dinâmico por Classificação | Elevação à Origem do Projeto (mm) = Elevação ao 1º Nível de Referência (mm) = Elevação ao 2º Nível de Referência (mm) = Elevação ao Nível do Mar (mm) = Elevação da Base Ao Primeiro Nível de Referência (mm) = Elevação da Base À Cota Zero (mm) = Elevação da Base Ao Nível do Mar (mm) = Elevação da Base Ao Segundo Nível de Referência (mm) | Elevação ao Piso (mm) = Afastamento da Origem (mm) = Elevação da Base Ao Piso de Origem (mm) | Elevação do Topo ao Primeiro Nível de Referência (mm) = Elevação do Topo À Cota Zero (mm) = Elevação do Topo Ao Nível do Mar (mm) = Elevação do Topo Ao Segundo Nível de Referência (mm) | Elevação do Topo Ao Piso de Origem (mm)
APTO4-Painel-Prin-030 | Primeiro Pavimento | Projeto: CECAP GuarulhosLocal: Piso: Primeiro Pavimento Cômodo: | APTO4-Prin-030 | Painel de Parede Cortina -Prin-030 | 1355.02 | 1355.02 | 2200.02 | 2200.02
5 x APTO4-Painel-Prin-013 | Primeiro Pavimento | Projeto: CECAP GuarulhosLocal: Piso: Primeiro Pavimento Cômodo: | APTO4-Prin-013 | Painel de Parede Cortina -Prin-013 | 1355.02 | 1355.02 | 2200.02 | 2200.02
APTO4-Painel-Prin-025 | Primeiro Pavimento | Projeto: CECAP GuarulhosLocal: Piso: Primeiro Pavimento Cômodo: | APTO4-Prin-025 | Painel de Parede Cortina -Prin-025 | 1355.02 | 1355.02 | 2200.02 | 2200.02
APTO4-Painel-Prin-020 | Primeiro Pavimento | Projeto: CECAP GuarulhosLocal: Piso: Primeiro Pavimento Cômodo: | APTO4-Prin-020 | Painel de Parede Cortina -Prin-020 | 1355.02 | 1355.02 | 2200.02 | 2200.02
APTO4-Painel-Prin-029 | Primeiro Pavimento | Projeto: CECAP GuarulhosLocal: Piso: Primeiro Pavimento Cômodo: | APTO4-Prin-029 | Painel de Parede Cortina -Prin-029 | 1355.02 | 1355.02 | 2200.02 | 2200.02
5 x APTO4-Painel-Prin-013 | Primeiro Pavimento | Projeto: CECAP GuarulhosLocal: Piso: Primeiro Pavimento Cômodo: | APTO4-Prin-013 | Painel de Parede Cortina -Prin-013 | 1355 | 1355 | 2200 | 2200
APTO4-Painel-Prin-029 | Primeiro Pavimento | Projeto: CECAP GuarulhosLocal: Piso: Primeiro Pavimento Cômodo: | APTO4-Prin-029 | Painel de Parede Cortina -Prin-029 | 1355 | 1355 | 2200 | 2200
APTO4-Painel-Prin-025 | Primeiro Pavimento | Projeto: CECAP GuarulhosLocal: Piso: Primeiro Pavimento Cômodo: | APTO4-Prin-025 | Painel de Parede Cortina -Prin-025 | 1355 | 1355 | 2200 | 2200
APTO3-Painel-Prin-030 | Primeiro Pavimento | Projeto: CECAP GuarulhosLocal: Piso: Primeiro Pavimento Cômodo: | APTO3-Prin-030 | Painel de Parede Cortina -Prin-030 | 1355.02 | 1355.02 | 2200.02 | 2200.02
5 x APTO3-Painel-Prin-013 | Primeiro Pavimento | Projeto: CECAP GuarulhosLocal: Piso: Primeiro Pavimento Cômodo: | APTO3-Prin-013 | Painel de Parede Cortina -Prin-013 | 1355.02 | 1355.02 | 2200.02 | 2200.02
APTO3-Painel-Prin-025 | Primeiro Pavimento | Projeto: CECAP GuarulhosLocal: Piso: Primeiro Pavimento Cômodo: | APTO3-Prin-025 | Painel de Parede Cortina -Prin-025 | 1355.02 | 1355.02 | 2200.02 | 2200.02
APTO3-Painel-Prin-020 | Primeiro Pavimento | Projeto: CECAP GuarulhosLocal: Piso: Primeiro Pavimento Cômodo: | APTO3-Prin-020 | Painel de Parede Cortina -Prin-020 | 1355.02 | 1355.02 | 2200.02 | 2200.02
APTO3-Painel-Prin-029 | Primeiro Pavimento | Projeto: CECAP GuarulhosLocal: Piso: Primeiro Pavimento Cômodo: | APTO3-Prin-029 | Painel de Parede Cortina -Prin-029 | 1355.02 | 1355.02 | 2200.02 | 2200.02
5 x APTO2-Painel-Prin-013 | Primeiro Pavimento | Projeto: CECAP GuarulhosLocal: Piso: Primeiro Pavimento Cômodo: | APTO2-Prin-013 | Painel de Parede Cortina -Prin-013 | 1355 | 1355 | 2200 | 2200
APTO2-Painel-Prin-029 | Primeiro Pavimento | Projeto: CECAP GuarulhosLocal: Piso: Primeiro Pavimento Cômodo: | APTO2-Prin-029 | Painel de Parede Cortina -Prin-029 | 1355 | 1355 | 2200 | 2200
APTO2-Painel-Prin-025 | Primeiro Pavimento | Projeto: CECAP GuarulhosLocal: Piso: Primeiro Pavimento Cômodo: | APTO2-Prin-025 | Painel de Parede Cortina -Prin-025 | 1355 | 1355 | 2200 | 2200
APTO2-Painel-Prin-030 | Primeiro Pavimento | Projeto: CECAP GuarulhosLocal: Piso: Primeiro Pavimento Cômodo: | APTO2-Prin-030 | Painel de Parede Cortina -Prin-030 | 1355.02 | 1355.02 | 2200.02 | 2200.02
5 x APTO2-Painel-Prin-013 | Primeiro Pavimento | Projeto: CECAP GuarulhosLocal: Piso: Primeiro Pavimento Cômodo: | APTO2-Prin-013 | Painel de Parede Cortina -Prin-013 | 1355.02 | 1355.02 | 2200.02 | 2200.02
APTO2-Painel-Prin-025 | Primeiro Pavimento | Projeto: CECAP GuarulhosLocal: Piso: Primeiro Pavimento Cômodo: | APTO2-Prin-025 | Painel de Parede Cortina -Prin-025 | 1355.02 | 1355.02 | 2200.02 | 2200.02
APTO2-Painel-Prin-020 | Primeiro Pavimento | Projeto: CECAP GuarulhosLocal: Piso: Primeiro Pavimento Cômodo: | APTO2-Prin-020 | Painel de Parede Cortina -Prin-020 | 1355.02 | 1355.02 | 2200.02 | 2200.02
APTO2-Painel-Prin-029 | Primeiro Pavimento | Projeto: CECAP GuarulhosLocal: Piso: Primeiro Pavimento Cômodo: | APTO2-Prin-029 | Painel de Parede Cortina -Prin-029 | 1355.02 | 1355.02 | 2200.02 | 2200.02
5 x APTO3-Painel-Prin-013 | Primeiro Pavimento | Projeto: CECAP GuarulhosLocal: Piso: Primeiro Pavimento Cômodo: | APTO3-Prin-013 | Painel de Parede Cortina -Prin-013 | 1355 | 1355 | 2200 | 2200
APTO3-Painel-Prin-029 | Primeiro Pavimento | Projeto: CECAP GuarulhosLocal: Piso: Primeiro Pavimento Cômodo: | APTO3-Prin-029 | Painel de Parede Cortina -Prin-029 | 1355 | 1355 | 2200 | 2200
APTO3-Painel-Prin-025 | Primeiro Pavimento | Projeto: CECAP GuarulhosLocal: Piso: Primeiro Pavimento Cômodo: | APTO3-Prin-025 | Painel de Parede Cortina -Prin-025 | 1355 | 1355 | 2200 | 2200
5 x APTO1-Painel-Prin-013 | Primeiro Pavimento | Projeto: CECAP GuarulhosLocal: Piso: Primeiro Pavimento Cômodo: | APTO1-Prin-013 | Painel de Parede Cortina -Prin-013 | 1355.02 | 1355.02 | 2200.02 | 2200.02
APTO1-Painel-Prin-029 | Primeiro Pavimento | Projeto: CECAP GuarulhosLocal: Piso: Primeiro Pavimento Cômodo: | APTO1-Prin-029 | Painel de Parede Cortina -Prin-029 | 1355.02 | 1355.02 | 2200.02 | 2200.02
APTO1-Painel-Prin-020 | Primeiro Pavimento | Projeto: CECAP GuarulhosLocal: Piso: Primeiro Pavimento Cômodo: | APTO1-Prin-020 | Painel de Parede Cortina -Prin-020 | 1355.02 | 1355.02 | 2200.02 | 2200.02
APTO1-Painel-Prin-025 | Primeiro Pavimento | Projeto: CECAP GuarulhosLocal: Piso: Primeiro Pavimento Cômodo: | APTO1-Prin-025 | Painel de Parede Cortina -Prin-025 | 1355.02 | 1355.02 | 2200.02 | 2200.02
APTO1-Painel-Prin-030 | Primeiro Pavimento | Projeto: CECAP GuarulhosLocal: Piso: Primeiro Pavimento Cômodo: | APTO1-Prin-030 | Painel de Parede Cortina -Prin-030 | 1355.02 | 1355.02 | 2200.02 | 2200.02
5 x APTO1-Painel-Prin-013 | Primeiro Pavimento | Projeto: CECAP GuarulhosLocal: Piso: Primeiro Pavimento Cômodo: | APTO1-Prin-013 | Painel de Parede Cortina -Prin-013 | 1355 | 1355 | 2200 | 2200
APTO1-Painel-Prin-025 | Primeiro Pavimento | Projeto: CECAP GuarulhosLocal: Piso: Primeiro Pavimento Cômodo: | APTO1-Prin-025 | Painel de Parede Cortina -Prin-025 | 1355 | 1355 | 2200 | 2200
APTO1-Painel-Prin-029 | Primeiro Pavimento | Projeto: CECAP GuarulhosLocal: Piso: Primeiro Pavimento Cômodo: | APTO1-Prin-029 | Painel de Parede Cortina -Prin-029 | 1355 | 1355 | 2200 | 2200
APTO5-Painel-Prin-030 | Segundo Pavimento | Projeto: CECAP GuarulhosLocal: Piso: Segundo Pavimento Cômodo: | APTO5-Prin-030 | Painel de Parede Cortina -Prin-030 | 4005.02 | 1355.02 | 4850.02 | 2200.02
5 x APTO5-Painel-Prin-013 | Segundo Pavimento | Projeto: CECAP GuarulhosLocal: Piso: Segundo Pavimento Cômodo: | APTO5-Prin-013 | Painel de Parede Cortina -Prin-013 | 4005.02 | 1355.02 | 4850.02 | 2200.02
APTO5-Painel-Prin-025 | Segundo Pavimento | Projeto: CECAP GuarulhosLocal: Piso: Segundo Pavimento Cômodo: | APTO5-Prin-025 | Painel de Parede Cortina -Prin-025 | 4005.02 | 1355.02 | 4850.02 | 2200.02
APTO5-Painel-Prin-020 | Segundo Pavimento | Projeto: CECAP GuarulhosLocal: Piso: Segundo Pavimento Cômodo: | APTO5-Prin-020 | Painel de Parede Cortina -Prin-020 | 4005.02 | 1355.02 | 4850.02 | 2200.02
APTO5-Painel-Prin-029 | Segundo Pavimento | Projeto: CECAP GuarulhosLocal: Piso: Segundo Pavimento Cômodo: | APTO5-Prin-029 | Painel de Parede Cortina -Prin-029 | 4005.02 | 1355.02 | 4850.02 | 2200.02
5 x APTO5-Painel-Prin-013 | Segundo Pavimento | Projeto: CECAP GuarulhosLocal: Piso: Segundo Pavimento Cômodo: | APTO5-Prin-013 | Painel de Parede Cortina -Prin-013 | 4005 | 1355 | 4850 | 2200
APTO5-Painel-Prin-029 | Segundo Pavimento | Projeto: CECAP GuarulhosLocal: Piso: Segundo Pavimento Cômodo: | APTO5-Prin-029 | Painel de Parede Cortina -Prin-029 | 4005 | 1355 | 4850 | 2200
APTO5-Painel-Prin-025 | Segundo Pavimento | Projeto: CECAP GuarulhosLocal: Piso: Segundo Pavimento Cômodo: | APTO5-Prin-025 | Painel de Parede Cortina -Prin-025 | 4005 | 1355 | 4850 | 2200
5 x APTO6-Painel-Prin-013 | Segundo Pavimento | Projeto: CECAP GuarulhosLocal: Piso: Segundo Pavimento Cômodo: | APTO6-Prin-013 | Painel de Parede Cortina -Prin-013 | 4005 | 1355 | 4850 | 2200
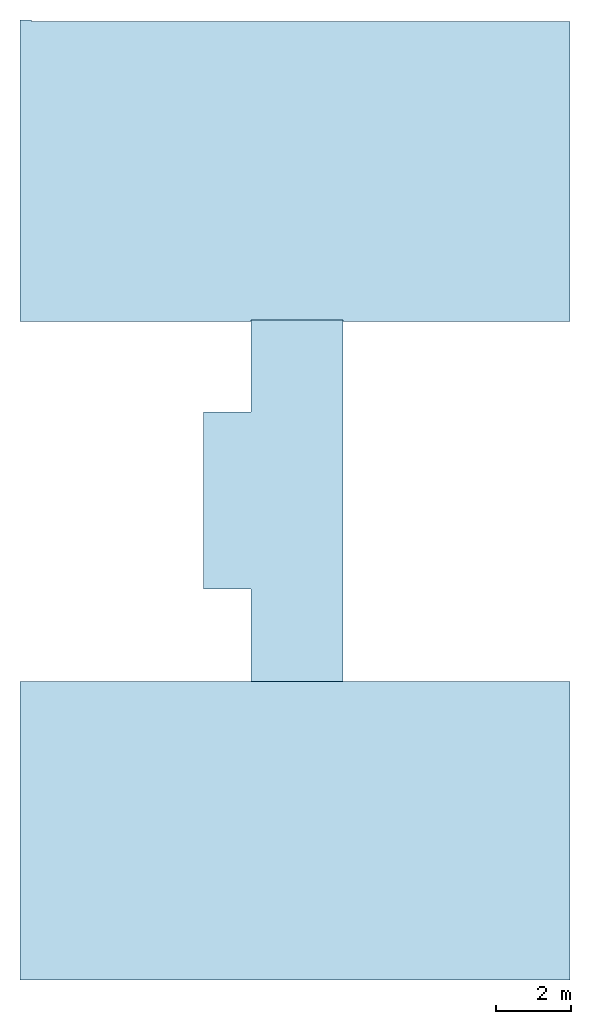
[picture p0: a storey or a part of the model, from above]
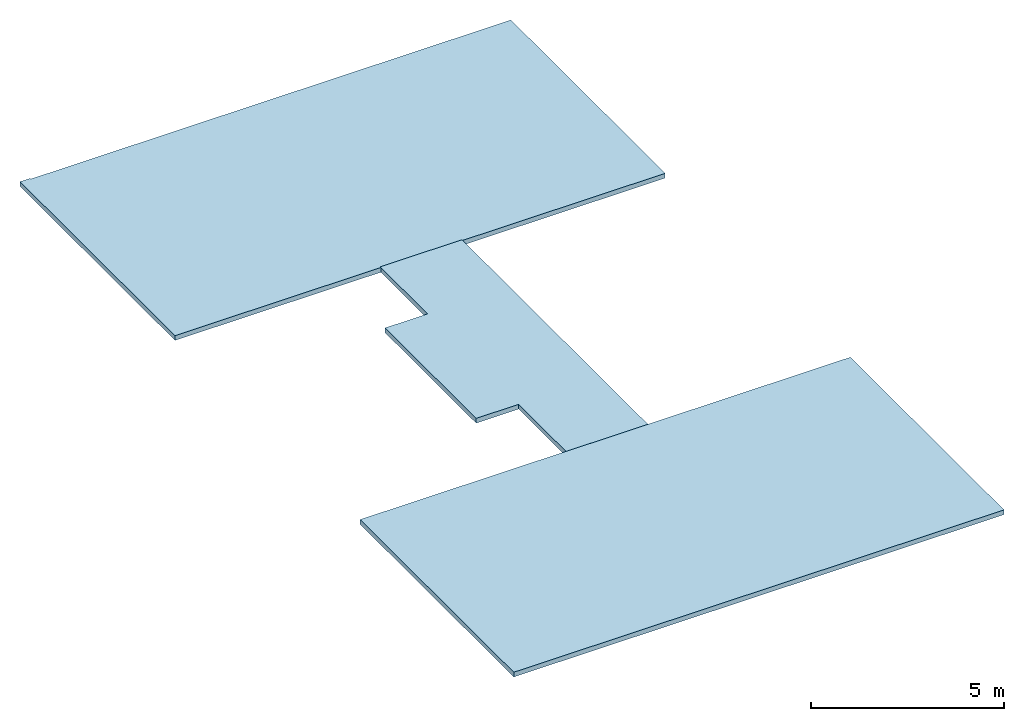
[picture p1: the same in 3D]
Properties of the parts of a building model (IFC2X3), part 5 of 7

# IfcPlate: Painel Principal 690 x 845 x 20 (192)
Name | In | Localização do Produto no Projeto | ID de Aberturas com Master ID | ID Dinâmico por Classificação | Elevação à Origem do Projeto (mm) = Elevação ao 1º Nível de Referência (mm) = Elevação ao 2º Nível de Referência (mm) = Elevação ao Nível do Mar (mm) = Elevação da Base Ao Primeiro Nível de Referência (mm) = Elevação da Base À Cota Zero (mm) = Elevação da Base Ao Nível do Mar (mm) = Elevação da Base Ao Segundo Nível de Referência (mm) | Elevação ao Piso (mm) = Afastamento da Origem (mm) = Elevação da Base Ao Piso de Origem (mm) | Elevação do Topo ao Primeiro Nível de Referência (mm) = Elevação do Topo À Cota Zero (mm) = Elevação do Topo Ao Nível do Mar (mm) = Elevação do Topo Ao Segundo Nível de Referência (mm) | Elevação do Topo Ao Piso de Origem (mm)
APTO6-Painel-Prin-029 | Segundo Pavimento | Projeto: CECAP GuarulhosLocal: Piso: Segundo Pavimento Cômodo: | APTO6-Prin-029 | Painel de Parede Cortina -Prin-029 | 4005 | 1355 | 4850 | 2200
APTO6-Painel-Prin-025 | Segundo Pavimento | Projeto: CECAP GuarulhosLocal: Piso: Segundo Pavimento Cômodo: | APTO6-Prin-025 | Painel de Parede Cortina -Prin-025 | 4005 | 1355 | 4850 | 2200
APTO6-Painel-Prin-030 | Segundo Pavimento | Projeto: CECAP GuarulhosLocal: Piso: Segundo Pavimento Cômodo: | APTO6-Prin-030 | Painel de Parede Cortina -Prin-030 | 4005.02 | 1355.02 | 4850.02 | 2200.02
5 x APTO6-Painel-Prin-013 | Segundo Pavimento | Projeto: CECAP GuarulhosLocal: Piso: Segundo Pavimento Cômodo: | APTO6-Prin-013 | Painel de Parede Cortina -Prin-013 | 4005.02 | 1355.02 | 4850.02 | 2200.02
APTO6-Painel-Prin-025 | Segundo Pavimento | Projeto: CECAP GuarulhosLocal: Piso: Segundo Pavimento Cômodo: | APTO6-Prin-025 | Painel de Parede Cortina -Prin-025 | 4005.02 | 1355.02 | 4850.02 | 2200.02
APTO6-Painel-Prin-020 | Segundo Pavimento | Projeto: CECAP GuarulhosLocal: Piso: Segundo Pavimento Cômodo: | APTO6-Prin-020 | Painel de Parede Cortina -Prin-020 | 4005.02 | 1355.02 | 4850.02 | 2200.02
APTO6-Painel-Prin-029 | Segundo Pavimento | Projeto: CECAP GuarulhosLocal: Piso: Segundo Pavimento Cômodo: | APTO6-Prin-029 | Painel de Parede Cortina -Prin-029 | 4005.02 | 1355.02 | 4850.02 | 2200.02
5 x APTO7-Painel-Prin-013 | Segundo Pavimento | Projeto: CECAP GuarulhosLocal: Piso: Segundo Pavimento Cômodo: | APTO7-Prin-013 | Painel de Parede Cortina -Prin-013 | 4005 | 1355 | 4850 | 2200
APTO7-Painel-Prin-029 | Segundo Pavimento | Projeto: CECAP GuarulhosLocal: Piso: Segundo Pavimento Cômodo: | APTO7-Prin-029 | Painel de Parede Cortina -Prin-029 | 4005 | 1355 | 4850 | 2200
APTO7-Painel-Prin-025 | Segundo Pavimento | Projeto: CECAP GuarulhosLocal: Piso: Segundo Pavimento Cômodo: | APTO7-Prin-025 | Painel de Parede Cortina -Prin-025 | 4005 | 1355 | 4850 | 2200
APTO7-Painel-Prin-030 | Segundo Pavimento | Projeto: CECAP GuarulhosLocal: Piso: Segundo Pavimento Cômodo: | APTO7-Prin-030 | Painel de Parede Cortina -Prin-030 | 4005.02 | 1355.02 | 4850.02 | 2200.02
5 x APTO7-Painel-Prin-013 | Segundo Pavimento | Projeto: CECAP GuarulhosLocal: Piso: Segundo Pavimento Cômodo: | APTO7-Prin-013 | Painel de Parede Cortina -Prin-013 | 4005.02 | 1355.02 | 4850.02 | 2200.02
APTO7-Painel-Prin-025 | Segundo Pavimento | Projeto: CECAP GuarulhosLocal: Piso: Segundo Pavimento Cômodo: | APTO7-Prin-025 | Painel de Parede Cortina -Prin-025 | 4005.02 | 1355.02 | 4850.02 | 2200.02
APTO7-Painel-Prin-020 | Segundo Pavimento | Projeto: CECAP GuarulhosLocal: Piso: Segundo Pavimento Cômodo: | APTO7-Prin-020 | Painel de Parede Cortina -Prin-020 | 4005.02 | 1355.02 | 4850.02 | 2200.02
APTO7-Painel-Prin-029 | Segundo Pavimento | Projeto: CECAP GuarulhosLocal: Piso: Segundo Pavimento Cômodo: | APTO7-Prin-029 | Painel de Parede Cortina -Prin-029 | 4005.02 | 1355.02 | 4850.02 | 2200.02
5 x APTO8-Painel-Prin-013 | Segundo Pavimento | Projeto: CECAP GuarulhosLocal: Piso: Segundo Pavimento Cômodo: | APTO8-Prin-013 | Painel de Parede Cortina -Prin-013 | 4005 | 1355 | 4850 | 2200
APTO8-Painel-Prin-029 | Segundo Pavimento | Projeto: CECAP GuarulhosLocal: Piso: Segundo Pavimento Cômodo: | APTO8-Prin-029 | Painel de Parede Cortina -Prin-029 | 4005 | 1355 | 4850 | 2200
APTO8-Painel-Prin-025 | Segundo Pavimento | Projeto: CECAP GuarulhosLocal: Piso: Segundo Pavimento Cômodo: | APTO8-Prin-025 | Painel de Parede Cortina -Prin-025 | 4005 | 1355 | 4850 | 2200
APTO8-Painel-Prin-030 | Segundo Pavimento | Projeto: CECAP GuarulhosLocal: Piso: Segundo Pavimento Cômodo: | APTO8-Prin-030 | Painel de Parede Cortina -Prin-030 | 4005.02 | 1355.02 | 4850.02 | 2200.02
5 x APTO8-Painel-Prin-013 | Segundo Pavimento | Projeto: CECAP GuarulhosLocal: Piso: Segundo Pavimento Cômodo: | APTO8-Prin-013 | Painel de Parede Cortina -Prin-013 | 4005.02 | 1355.02 | 4850.02 | 2200.02
APTO8-Painel-Prin-025 | Segundo Pavimento | Projeto: CECAP GuarulhosLocal: Piso: Segundo Pavimento Cômodo: | APTO8-Prin-025 | Painel de Parede Cortina -Prin-025 | 4005.02 | 1355.02 | 4850.02 | 2200.02
APTO8-Painel-Prin-020 | Segundo Pavimento | Projeto: CECAP GuarulhosLocal: Piso: Segundo Pavimento Cômodo: | APTO8-Prin-020 | Painel de Parede Cortina -Prin-020 | 4005.02 | 1355.02 | 4850.02 | 2200.02
APTO8-Painel-Prin-029 | Segundo Pavimento | Projeto: CECAP GuarulhosLocal: Piso: Segundo Pavimento Cômodo: | APTO8-Prin-029 | Painel de Parede Cortina -Prin-029 | 4005.02 | 1355.02 | 4850.02 | 2200.02
5 x APTO9-Painel-Prin-013 | Terceiro Pavimento | Projeto: CECAP GuarulhosLocal: Piso: Terceiro Pavimento Cômodo: | APTO9-Prin-013 | Painel de Parede Cortina -Prin-013 | 6655 | 1355 | 7500 | 2200
APTO9-Painel-Prin-029 | Terceiro Pavimento | Projeto: CECAP GuarulhosLocal: Piso: Terceiro Pavimento Cômodo: | APTO9-Prin-029 | Painel de Parede Cortina -Prin-029 | 6655 | 1355 | 7500 | 2200
APTO9-Painel-Prin-025 | Terceiro Pavimento | Projeto: CECAP GuarulhosLocal: Piso: Terceiro Pavimento Cômodo: | APTO9-Prin-025 | Painel de Parede Cortina -Prin-025 | 6655 | 1355 | 7500 | 2200
APTO9-Painel-Prin-030 | Terceiro Pavimento | Projeto: CECAP GuarulhosLocal: Piso: Terceiro Pavimento Cômodo: | APTO9-Prin-030 | Painel de Parede Cortina -Prin-030 | 6655.02 | 1355.02 | 7500.02 | 2200.02
5 x APTO9-Painel-Prin-013 | Terceiro Pavimento | Projeto: CECAP GuarulhosLocal: Piso: Terceiro Pavimento Cômodo: | APTO9-Prin-013 | Painel de Parede Cortina -Prin-013 | 6655.02 | 1355.02 | 7500.02 | 2200.02
APTO9-Painel-Prin-025 | Terceiro Pavimento | Projeto: CECAP GuarulhosLocal: Piso: Terceiro Pavimento Cômodo: | APTO9-Prin-025 | Painel de Parede Cortina -Prin-025 | 6655.02 | 1355.02 | 7500.02 | 2200.02
APTO9-Painel-Prin-020 | Terceiro Pavimento | Projeto: CECAP GuarulhosLocal: Piso: Terceiro Pavimento Cômodo: | APTO9-Prin-020 | Painel de Parede Cortina -Prin-020 | 6655.02 | 1355.02 | 7500.02 | 2200.02
APTO9-Painel-Prin-029 | Terceiro Pavimento | Projeto: CECAP GuarulhosLocal: Piso: Terceiro Pavimento Cômodo: | APTO9-Prin-029 | Painel de Parede Cortina -Prin-029 | 6655.02 | 1355.02 | 7500.02 | 2200.02
5 x APTO10-Painel-Prin-013 | Terceiro Pavimento | Projeto: CECAP GuarulhosLocal: Piso: Terceiro Pavimento Cômodo: | APTO10-Prin-013 | Painel de Parede Cortina -Prin-013 | 6655 | 1355 | 7500 | 2200
APTO10-Painel-Prin-029 | Terceiro Pavimento | Projeto: CECAP GuarulhosLocal: Piso: Terceiro Pavimento Cômodo: | APTO10-Prin-029 | Painel de Parede Cortina -Prin-029 | 6655 | 1355 | 7500 | 2200
APTO10-Painel-Prin-025 | Terceiro Pavimento | Projeto: CECAP GuarulhosLocal: Piso: Terceiro Pavimento Cômodo: | APTO10-Prin-025 | Painel de Parede Cortina -Prin-025 | 6655 | 1355 | 7500 | 2200
APTO10-Painel-Prin-030 | Terceiro Pavimento | Projeto: CECAP GuarulhosLocal: Piso: Terceiro Pavimento Cômodo: | APTO10-Prin-030 | Painel de Parede Cortina -Prin-030 | 6655.02 | 1355.02 | 7500.02 | 2200.02
5 x APTO10-Painel-Prin-013 | Terceiro Pavimento | Projeto: CECAP GuarulhosLocal: Piso: Terceiro Pavimento Cômodo: | APTO10-Prin-013 | Painel de Parede Cortina -Prin-013 | 6655.02 | 1355.02 | 7500.02 | 2200.02
APTO10-Painel-Prin-025 | Terceiro Pavimento | Projeto: CECAP GuarulhosLocal: Piso: Terceiro Pavimento Cômodo: | APTO10-Prin-025 | Painel de Parede Cortina -Prin-025 | 6655.02 | 1355.02 | 7500.02 | 2200.02
APTO10-Painel-Prin-020 | Terceiro Pavimento | Projeto: CECAP GuarulhosLocal: Piso: Terceiro Pavimento Cômodo: | APTO10-Prin-020 | Painel de Parede Cortina -Prin-020 | 6655.02 | 1355.02 | 7500.02 | 2200.02
APTO10-Painel-Prin-029 | Terceiro Pavimento | Projeto: CECAP GuarulhosLocal: Piso: Terceiro Pavimento Cômodo: | APTO10-Prin-029 | Painel de Parede Cortina -Prin-029 | 6655.02 | 1355.02 | 7500.02 | 2200.02
5 x APTO11-Painel-Prin-013 | Terceiro Pavimento | Projeto: CECAP GuarulhosLocal: Piso: Terceiro Pavimento Cômodo: | APTO11-Prin-013 | Painel de Parede Cortina -Prin-013 | 6655 | 1355 | 7500 | 2200
APTO11-Painel-Prin-029 | Terceiro Pavimento | Projeto: CECAP GuarulhosLocal: Piso: Terceiro Pavimento Cômodo: | APTO11-Prin-029 | Painel de Parede Cortina -Prin-029 | 6655 | 1355 | 7500 | 2200
APTO11-Painel-Prin-025 | Terceiro Pavimento | Projeto: CECAP GuarulhosLocal: Piso: Terceiro Pavimento Cômodo: | APTO11-Prin-025 | Painel de Parede Cortina -Prin-025 | 6655 | 1355 | 7500 | 2200
APTO11-Painel-Prin-030 | Terceiro Pavimento | Projeto: CECAP GuarulhosLocal: Piso: Terceiro Pavimento Cômodo: | APTO11-Prin-030 | Painel de Parede Cortina -Prin-030 | 6655.02 | 1355.02 | 7500.02 | 2200.02
5 x APTO11-Painel-Prin-013 | Terceiro Pavimento | Projeto: CECAP GuarulhosLocal: Piso: Terceiro Pavimento Cômodo: | APTO11-Prin-013 | Painel de Parede Cortina -Prin-013 | 6655.02 | 1355.02 | 7500.02 | 2200.02
APTO11-Painel-Prin-025 | Terceiro Pavimento | Projeto: CECAP GuarulhosLocal: Piso: Terceiro Pavimento Cômodo: | APTO11-Prin-025 | Painel de Parede Cortina -Prin-025 | 6655.02 | 1355.02 | 7500.02 | 2200.02
APTO11-Painel-Prin-020 | Terceiro Pavimento | Projeto: CECAP GuarulhosLocal: Piso: Terceiro Pavimento Cômodo: | APTO11-Prin-020 | Painel de Parede Cortina -Prin-020 | 6655.02 | 1355.02 | 7500.02 | 2200.02
APTO11-Painel-Prin-029 | Terceiro Pavimento | Projeto: CECAP GuarulhosLocal: Piso: Terceiro Pavimento Cômodo: | APTO11-Prin-029 | Painel de Parede Cortina -Prin-029 | 6655.02 | 1355.02 | 7500.02 | 2200.02
5 x APTO12-Painel-Prin-013 | Terceiro Pavimento | Projeto: CECAP GuarulhosLocal: Piso: Terceiro Pavimento Cômodo: | APTO12-Prin-013 | Painel de Parede Cortina -Prin-013 | 6655 | 1355 | 7500 | 2200
APTO12-Painel-Prin-029 | Terceiro Pavimento | Projeto: CECAP GuarulhosLocal: Piso: Terceiro Pavimento Cômodo: | APTO12-Prin-029 | Painel de Parede Cortina -Prin-029 | 6655 | 1355 | 7500 | 2200
APTO12-Painel-Prin-025 | Terceiro Pavimento | Projeto: CECAP GuarulhosLocal: Piso: Terceiro Pavimento Cômodo: | APTO12-Prin-025 | Painel de Parede Cortina -Prin-025 | 6655 | 1355 | 7500 | 2200
APTO12-Painel-Prin-030 | Terceiro Pavimento | Projeto: CECAP GuarulhosLocal: Piso: Terceiro Pavimento Cômodo: | APTO12-Prin-030 | Painel de Parede Cortina -Prin-030 | 6655.02 | 1355.02 | 7500.02 | 2200.02
5 x APTO12-Painel-Prin-013 | Terceiro Pavimento | Projeto: CECAP GuarulhosLocal: Piso: Terceiro Pavimento Cômodo: | APTO12-Prin-013 | Painel de Parede Cortina -Prin-013 | 6655.02 | 1355.02 | 7500.02 | 2200.02
APTO12-Painel-Prin-025 | Terceiro Pavimento | Projeto: CECAP GuarulhosLocal: Piso: Terceiro Pavimento Cômodo: | APTO12-Prin-025 | Painel de Parede Cortina -Prin-025 | 6655.02 | 1355.02 | 7500.02 | 2200.02
APTO12-Painel-Prin-020 | Terceiro Pavimento | Projeto: CECAP GuarulhosLocal: Piso: Terceiro Pavimento Cômodo: | APTO12-Prin-020 | Painel de Parede Cortina -Prin-020 | 6655.02 | 1355.02 | 7500.02 | 2200.02
APTO12-Painel-Prin-029 | Terceiro Pavimento | Projeto: CECAP GuarulhosLocal: Piso: Terceiro Pavimento Cômodo: | APTO12-Prin-029 | Painel de Parede Cortina -Prin-029 | 6655.02 | 1355.02 | 7500.02 | 2200.02

# IfcPlate: Painel Principal 695 x 845 x 20 (12)
Type - PredefinedType: CURTAIN_PANEL
Classification: Painel de Parede Cortina (Classificação ARCHICAD)
Pset_ManufacturerOccurrence - SerialNumber: Desligado
INFORMAÇÕES DO PRODUTO - Data de Aquisição: DD/MM/YYYY
FABRICAÇÃO - Data de Fabricação: DD/MM/YYYY; Site do Produto: www.graphisoft.com
GARANTIA - Ínicio da Garantia: DD/MM/YYYY; Fim da Garantia: DD/MM/YYYY
EXPRESSÕES DE TEXTO (Expressão) - ID Dinâmico por Classificação: Painel de Parede Cortina -Prin-020
SUPERFÍCIES (Mapas) - Superfície da Face (Geral): Metal - Alumínio
AC_Pset_RenovationAndPhasing - Renovation Status: Não definido
BaseQuantities - Width: 675 mm; Perimeter: 3040 mm; GrossArea: 0.587275 m2; NetArea: 0.570375 m2; GrossVolume: 0.0117455 m3; NetVolume: 0.0114075 m3
ArchiCADQuantities - Altura: 845 mm; Volume (Líquido): 0.0168588 m3; Largura: 675 mm; Elevação ao Piso: 1355 mm; Afastamento da Origem: 1355 mm; Área da Superfície: 0.570375 m2; Espessura: 20 mm; Perímetro em 3D: 3040 mm; Elevação do Topo Ao Piso de Origem: 2200 mm; Elevação da Base Ao Piso de Origem: 1355 mm; Área da Superfície da Base (Líquida): 0.570375 m2; Área do Painel com Grampos: 0.587275 m2; Altura Nominal: 845 mm; Área do Painel sem Grampos: 0.570375 m2; Largura Nominal: 675 mm
AC_Equantity_Janela_PC_25 - Dimensão 1: 1000 mm; Dimensão 2: 1000 mm; Altura (ZZYZX): 1000 mm; Nível da Base: 1000 mm; Nível do Topo: 0 mm; Largura Cinta: 20 mm; Afastamento Painel: 0 mm; Espessura: 55 mm; Largura: 675 mm; Largura Nominal: 675 mm; Altura (ac_height): 845 mm; Altura Nominal: 845 mm; Largura Batente: 45 mm; Espessura Batente: 55 mm; Largura Reentrância Estrutura: 25 mm; Espessura Reentrância Estrutura: 50 mm; Largura Adaptador: 25 mm; Espessura Adaptador: 60 mm; Espessura Estrutura Caixilho: 55 mm; Largura Caixilho: 45 mm; Espessura Vidro: 16 mm; Afastamento Vidro: 10 mm; Espessura Grelha: 20 mm; Largura Grelha Horizontal: 10 mm; Largura Grelha Vertical: 10 mm
Name | In | Localização do Produto no Projeto | ID de Aberturas com Master ID | Elevação à Origem do Projeto (mm) = Elevação ao 1º Nível de Referência (mm) = Elevação ao 2º Nível de Referência (mm) = Elevação ao Nível do Mar (mm) = Elevação da Base Ao Primeiro Nível de Referência (mm) = Elevação da Base À Cota Zero (mm) = Elevação da Base Ao Nível do Mar (mm) = Elevação da Base Ao Segundo Nível de Referência (mm) | Elevação do Topo ao Primeiro Nível de Referência (mm) = Elevação do Topo À Cota Zero (mm) = Elevação do Topo Ao Nível do Mar (mm) = Elevação do Topo Ao Segundo Nível de Referência (mm)
APTO4-Painel-Prin-020 | Primeiro Pavimento | Projeto: CECAP GuarulhosLocal: Piso: Primeiro Pavimento Cômodo: | APTO4-Prin-020 | 1355 | 2200
APTO2-Painel-Prin-020 | Primeiro Pavimento | Projeto: CECAP GuarulhosLocal: Piso: Primeiro Pavimento Cômodo: | APTO2-Prin-020 | 1355 | 2200
APTO3-Painel-Prin-020 | Primeiro Pavimento | Projeto: CECAP GuarulhosLocal: Piso: Primeiro Pavimento Cômodo: | APTO3-Prin-020 | 1355 | 2200
APTO1-Painel-Prin-020 | Primeiro Pavimento | Projeto: CECAP GuarulhosLocal: Piso: Primeiro Pavimento Cômodo: | APTO1-Prin-020 | 1355 | 2200
APTO5-Painel-Prin-020 | Segundo Pavimento | Projeto: CECAP GuarulhosLocal: Piso: Segundo Pavimento Cômodo: | APTO5-Prin-020 | 4005 | 4850
APTO6-Painel-Prin-020 | Segundo Pavimento | Projeto: CECAP GuarulhosLocal: Piso: Segundo Pavimento Cômodo: | APTO6-Prin-020 | 4005 | 4850
APTO7-Painel-Prin-020 | Segundo Pavimento | Projeto: CECAP GuarulhosLocal: Piso: Segundo Pavimento Cômodo: | APTO7-Prin-020 | 4005 | 4850
APTO8-Painel-Prin-020 | Segundo Pavimento | Projeto: CECAP GuarulhosLocal: Piso: Segundo Pavimento Cômodo: | APTO8-Prin-020 | 4005 | 4850
APTO9-Painel-Prin-020 | Terceiro Pavimento | Projeto: CECAP GuarulhosLocal: Piso: Terceiro Pavimento Cômodo: | APTO9-Prin-020 | 6655 | 7500
APTO10-Painel-Prin-020 | Terceiro Pavimento | Projeto: CECAP GuarulhosLocal: Piso: Terceiro Pavimento Cômodo: | APTO10-Prin-020 | 6655 | 7500
APTO11-Painel-Prin-020 | Terceiro Pavimento | Projeto: CECAP GuarulhosLocal: Piso: Terceiro Pavimento Cômodo: | APTO11-Prin-020 | 6655 | 7500
APTO12-Painel-Prin-020 | Terceiro Pavimento | Projeto: CECAP GuarulhosLocal: Piso: Terceiro Pavimento Cômodo: | APTO12-Prin-020 | 6655 | 7500

# IfcRailing: Tipo de Guarda-Corpo (3)
Classification: 3E 08 04 10 Guarda-corpo (NBR 15965-5 3E); Guarda-Corpo (Classificação ARCHICAD)
Pset_ManufacturerTypeInformation - ProductionYear: DD/MM/YYYY
INFORMAÇÕES DO PRODUTO - Data de Aquisição: DD/MM/YYYY
FABRICAÇÃO - Data de Fabricação: DD/MM/YYYY; Site do Produto: www.graphisoft.com
AC_Pset_RenovationAndPhasing - Renovation Status: Existing
Pset_RailingCommon - IsExternal: yes
BaseQuantities - GrossVolume: 1.19699 m3; Length: 4688.4 mm; NetVolume: 1.19699 m3
ArchiCADQuantities - Área: 0.890184 m2; Altura: 1250 mm; Volume (Líquido): 1.19699 m3; Elevação ao Piso: 500 mm; Afastamento da Origem: 500 mm; Comprimento 3D: 4688.4 mm; Elevação do Topo Ao Piso de Origem: 2780.57 mm; Elevação da Base Ao Piso de Origem: 500 mm; Área da Superfície do Topo (Líquida): 0.890184 m2; Número de Balaústres: 0; Número de Corrimãos: 0; Número de Postes Internos: 0; Número de Painéis: 0; Número de Postes: 4; Número de Barras: 0; Número de Barras Superiores: 3; Comprimento Horizontal da Linha de Referência: 4340 mm
Name | In | Localização do Produto no Projeto | ID Dinâmico por Classificação | Elevação à Origem do Projeto (mm) = Elevação ao 1º Nível de Referência (mm) = Elevação ao 2º Nível de Referência (mm) = Elevação ao Nível do Mar (mm) = Elevação da Base Ao Primeiro Nível de Referência (mm) = Elevação da Base À Cota Zero (mm) = Elevação da Base Ao Nível do Mar (mm) = Elevação da Base Ao Segundo Nível de Referência (mm) | Elevação do Topo ao Primeiro Nível de Referência (mm) = Elevação do Topo À Cota Zero (mm) = Elevação do Topo Ao Nível do Mar (mm) = Elevação do Topo Ao Segundo Nível de Referência (mm)
GC-001 | Pavimento Terreo | Projeto: CECAP GuarulhosLocal: Piso: Pavimento Terreo Cômodo: | Guarda-Corpo -001 | -2150 | 130.571
CIRC1-GC-002 | Primeiro Pavimento | Projeto: CECAP GuarulhosLocal: Piso: Primeiro Pavimento Cômodo: | Guarda-Corpo -002 | 500 | 2780.57
CIRC2-GC-002 | Segundo Pavimento | Projeto: CECAP GuarulhosLocal: Piso: Segundo Pavimento Cômodo: | Guarda-Corpo -002 | 3150 | 5430.57

# IfcSlab: Concreto Armado Moldado in Loco - Estrutural 100 (27)
Type - PredefinedType: FLOOR
Classification: Laje (Classificação ARCHICAD); 3E 12 06 08 Laje (NBR 15965-5 3E); Material: Concreto Armado Moldado in Loco - Estrutural 100 mm
PISOS (Expressão) - Índice de Perda (%): 10
ESTRUTURA (Expressão) - Custo por Volume (m3): 0; Estimativa de Custo Total por Volume: 0; Estimativa de Custo Total por Volume (R$): 0,00 R$
SUPERFÍCIES (Mapas) - Superfície do Topo (Geral): Concreto - 03; Superfície da Face (Geral): Concreto - 03; Superfície da Base (Geral): Concreto - 03
AC_Pset_RenovationAndPhasing - Renovation Status: Existing
Pset_SlabCommon - LoadBearing: yes; IsExternal: yes
Component Properties - Concreto Armado Moldado in Loco - Estrutural, Tipo de Componente: Nenhum
BaseQuantities - Width: 100 mm
ArchiCADQuantities - Altura: 100 mm; Espessura: 100 mm; Perímetro Furos da Planta: 0 mm; Área de Superfície dos Furos: 0 m2
Component Quantities - Concreto Armado Moldado in Loco - Estrutural, Espessura do Componente: 100 mm
Name | In | ID Dinâmico por Classificação | Concreto Armado Moldado in Loco - Estrutural, Carbono Incorporado | Concreto Armado Moldado in Loco - Estrutural, Energia Incorporada (MJ) | Perimeter (mm) = Perímetro na Planta (mm) | GrossArea (m2) = NetArea (m2) = Área (m2) = Área da Superfície (m2) = Área da Superfície do Topo (Líquida) (m2) = Área da Superfície do Topo (Condicional) (m2) = Área da Superfície da Base (Líquida) (m2) = Área da Superfície da Base (Condicional) (m2) = Área da Superfície da Base (Bruta) (m2) = Área da Superfície do Topo (Bruta) (m2) = Área da Superfície do Topo da Laje (Condicional) (m2) = Área da Superfície da Base da Laje (Bruta) (m2) = Área da Superfície da Base da Laje (Bruta, com os furos) (m2) = Área da Superfície do Topo da Laje (Bruta) (m2) = Área da Superfície do Topo da Laje (Bruta, com os furos) (m2) = Área da Superfície do Topo (Geral) (m2) = Área da Superfície da Base (Geral) (m2) = Área Condicional da Superfície do Topo (Geral) (m2) = Área Condicional da Superfície da Base (Geral) (m2) = Concreto Armado Moldado in Loco - Estrutural, Área de Componente Projetada (Líquida) (m2) = Concreto Armado Moldado in Loco - Estrutural, Área de Componente Projetada (Bruta) (m2) = Concreto Armado Moldado in Loco - Estrutural, Área de Componente Projetada (Condicional) (m2) | GrossVolume (m3) = NetVolume (m3) = Volume (Líquido) (m3) = Volume (Condicional) (m3) = Volume (Bruto) (m3) = Concreto Armado Moldado in Loco - Estrutural, Volume Componente (Líquido) (m3) = Concreto Armado Moldado in Loco - Estrutural, Volume do componente (Bruto) (m3) = Concreto Armado Moldado in Loco - Estrutural, Volume Componente (Condicional) (m3) | Elevação à Origem do Projeto (mm) = Elevação ao 1º Nível de Referência (mm) = Elevação ao 2º Nível de Referência (mm) = Elevação ao Nível do Mar (mm) | Elevação ao Piso (mm) = Afastamento da Origem (mm) | Elevação do Topo ao Primeiro Nível de Referência (mm) = Elevação do Topo À Cota Zero (mm) = Elevação do Topo Ao Nível do Mar (mm) = Elevação do Topo Ao Segundo Nível de Referência (mm) = Topo da Elevação (mm) | Elevação do Topo Ao Piso de Origem (mm) | Elevação da Base Ao Primeiro Nível de Referência (mm) = Elevação da Base À Cota Zero (mm) = Elevação da Base Ao Nível do Mar (mm) = Elevação da Base Ao Segundo Nível de Referência (mm) | Elevação da Base Ao Piso de Origem (mm) | Área da Superfície da Borda (Líquida) (m2) = Área da Superfície das Bordas (Bruta) (m2) = Área da Superfície das Bordas da Laje (Bruta) (m2) = Área da Superfície das Bordas da Laje (Bruta, com as bordas dos furos) (m2) = Área da Superfície da Face (Geral) (m2) | Elevação da Base (mm) | Concreto Armado Moldado in Loco - Estrutural, Massa (kg)
APTO4-LAJE-004 | Primeiro Pavimento | Laje -004 | 165.876 (kgCO₂) | 1597.08 | 12220 | 2.856 | 0.2856 | 100 | 100 | 100 | 100 | 0 | 0 | 1.222 | 3.63598e-12 | 685.44
APTO4-LAJE-001 | Primeiro Pavimento | Laje -001 | 206.753 (kgCO₂) | 1990.64 | 14980 | 3.5598 | 0.35598 | 100 | 100 | 100 | 100 | 0 | 0 | 1.498 | 3.63598e-12 | 854.352
APTO2-LAJE-001 | Primeiro Pavimento | Laje -001 | 206.753 (kgCO₂) | 1990.64 | 14980 | 3.5598 | 0.35598 | 100 | 100 | 100 | 100 | 0 | 0 | 1.498 | 3.63598e-12 | 854.352
APTO2-LAJE-004 | Primeiro Pavimento | Laje -004 | 165.876 (kgCO₂) | 1597.08 | 12220 | 2.856 | 0.2856 | 100 | 100 | 100 | 100 | 0 | 0 | 1.222 | 3.63598e-12 | 685.44
APTO3-LAJE-001 | Primeiro Pavimento | Laje -001 | 206.753 (kgCO₂) | 1990.64 | 14980 | 3.5598 | 0.35598 | 100 | 100 | 100 | 100 | 0 | 0 | 1.498 | 3.63598e-12 | 854.352
APTO3-LAJE-004 | Primeiro Pavimento | Laje -004 | 165.876 (kgCO₂) | 1597.08 | 12220 | 2.856 | 0.2856 | 100 | 100 | 100 | 100 | 0 | 0 | 1.222 | 3.63598e-12 | 685.44
APTO1-LAJE-004 | Primeiro Pavimento | Laje -004 | 165.876 (kgCO₂) | 1597.08 | 12220 | 2.856 | 0.2856 | 100 | 100 | 100 | 100 | 0 | 0 | 1.222 | 3.63598e-12 | 685.44
APTO1-LAJE-001 | Primeiro Pavimento | Laje -001 | 206.753 (kgCO₂) | 1990.64 | 14980 | 3.5598 | 0.35598 | 100 | 100 | 100 | 100 | 0 | 0 | 1.498 | 3.63598e-12 | 854.352
CIRC1-LAJE-007 | Primeiro Pavimento | Laje -007 | 1166.43 (kgCO₂) | 11230.5 | 28540 | 20.0831 | 2.00831 | -150 | -150 | -50 | -50 | -150 | -150 | 2.854 | -150 | 4819.94
APTO5-LAJE-001 | Segundo Pavimento | Laje -001 | 206.753 (kgCO₂) | 1990.64 | 14980 | 3.5598 | 0.35598 | 2750 | 100 | 2750 | 100 | 2650 | 3.55271e-12 | 1.498 | 2650 | 854.352
APTO5-LAJE-004 | Segundo Pavimento | Laje -004 | 165.876 (kgCO₂) | 1597.08 | 12220 | 2.856 | 0.2856 | 2750 | 100 | 2750 | 100 | 2650 | 3.55271e-12 | 1.222 | 2650 | 685.44
APTO6-LAJE-001 | Segundo Pavimento | Laje -001 | 206.753 (kgCO₂) | 1990.64 | 14980 | 3.5598 | 0.35598 | 2750 | 100 | 2750 | 100 | 2650 | 3.55271e-12 | 1.498 | 2650 | 854.352
APTO6-LAJE-004 | Segundo Pavimento | Laje -004 | 165.876 (kgCO₂) | 1597.08 | 12220 | 2.856 | 0.2856 | 2750 | 100 | 2750 | 100 | 2650 | 3.55271e-12 | 1.222 | 2650 | 685.44
APTO7-LAJE-001 | Segundo Pavimento | Laje -001 | 206.753 (kgCO₂) | 1990.64 | 14980 | 3.5598 | 0.35598 | 2750 | 100 | 2750 | 100 | 2650 | 3.55271e-12 | 1.498 | 2650 | 854.352
APTO7-LAJE-004 | Segundo Pavimento | Laje -004 | 165.876 (kgCO₂) | 1597.08 | 12220 | 2.856 | 0.2856 | 2750 | 100 | 2750 | 100 | 2650 | 3.55271e-12 | 1.222 | 2650 | 685.44
APTO8-LAJE-001 | Segundo Pavimento | Laje -001 | 206.753 (kgCO₂) | 1990.64 | 14980 | 3.5598 | 0.35598 | 2750 | 100 | 2750 | 100 | 2650 | 3.55271e-12 | 1.498 | 2650 | 854.352
APTO8-LAJE-004 | Segundo Pavimento | Laje -004 | 165.876 (kgCO₂) | 1597.08 | 12220 | 2.856 | 0.2856 | 2750 | 100 | 2750 | 100 | 2650 | 3.55271e-12 | 1.222 | 2650 | 685.44
CIRC2-LAJE-007 | Segundo Pavimento | Laje -007 | 1166.43 (kgCO₂) | 11230.5 | 28540 | 20.0831 | 2.00831 | 2500 | -150 | 2600 | -50 | 2500 | -150 | 2.854 | 2500 | 4819.94
CIRC3-LAJE-008 | Terceiro Pavimento | Laje -008 | 1166.43 (kgCO₂) | 11230.5 | 28540 | 20.0831 | 2.00831 | 5150 | -150 | 5250 | -50 | 5150 | -150 | 2.854 | 5150 | 4819.94
APTO9-LAJE-001 | Terceiro Pavimento | Laje -001 | 206.753 (kgCO₂) | 1990.64 | 14980 | 3.5598 | 0.35598 | 5400 | 100 | 5400 | 100 | 5300 | 4.44089e-12 | 1.498 | 5300 | 854.352
APTO9-LAJE-004 | Terceiro Pavimento | Laje -004 | 165.876 (kgCO₂) | 1597.08 | 12220 | 2.856 | 0.2856 | 5400 | 100 | 5400 | 100 | 5300 | 4.44089e-12 | 1.222 | 5300 | 685.44
APTO10-LAJE-001 | Terceiro Pavimento | Laje -001 | 206.753 (kgCO₂) | 1990.64 | 14980 | 3.5598 | 0.35598 | 5400 | 100 | 5400 | 100 | 5300 | 4.44089e-12 | 1.498 | 5300 | 854.352
APTO10-LAJE-004 | Terceiro Pavimento | Laje -004 | 165.876 (kgCO₂) | 1597.08 | 12220 | 2.856 | 0.2856 | 5400 | 100 | 5400 | 100 | 5300 | 4.44089e-12 | 1.222 | 5300 | 685.44
APTO11-LAJE-001 | Terceiro Pavimento | Laje -001 | 206.753 (kgCO₂) | 1990.64 | 14980 | 3.5598 | 0.35598 | 5400 | 100 | 5400 | 100 | 5300 | 4.44089e-12 | 1.498 | 5300 | 854.352
APTO11-LAJE-004 | Terceiro Pavimento | Laje -004 | 165.876 (kgCO₂) | 1597.08 | 12220 | 2.856 | 0.2856 | 5400 | 100 | 5400 | 100 | 5300 | 4.44089e-12 | 1.222 | 5300 | 685.44
APTO12-LAJE-001 | Terceiro Pavimento | Laje -001 | 206.753 (kgCO₂) | 1990.64 | 14980 | 3.5598 | 0.35598 | 5400 | 100 | 5400 | 100 | 5300 | 4.44089e-12 | 1.498 | 5300 | 854.352
APTO12-LAJE-004 | Terceiro Pavimento | Laje -004 | 165.876 (kgCO₂) | 1597.08 | 12220 | 2.856 | 0.2856 | 5400 | 100 | 5400 | 100 | 5300 | 4.44089e-12 | 1.222 | 5300 | 685.44

# IfcSlab: Concreto Armado Moldado in Loco - Estrutural 120 (24)
Type - PredefinedType: FLOOR
Classification: Laje (Classificação ARCHICAD); 3E 12 06 08 Laje (NBR 15965-5 3E); Material: Concreto Armado Moldado in Loco - Estrutural 120 mm
PISOS (Expressão) - Índice de Perda (%): 10
ESTRUTURA (Expressão) - Custo por Volume (m3): 0; Estimativa de Custo Total por Volume: 0; Estimativa de Custo Total por Volume (R$): 0,00 R$
SUPERFÍCIES (Mapas) - Superfície do Topo (Geral): Concreto - 03; Superfície da Face (Geral): Concreto - 03; Superfície da Base (Geral): Concreto - 03
AC_Pset_RenovationAndPhasing - Renovation Status: Existing
Pset_SlabCommon - LoadBearing: yes; IsExternal: yes
Component Properties - Concreto Armado Moldado in Loco - Estrutural, Tipo de Componente: Nenhum
BaseQuantities - Width: 120 mm
ArchiCADQuantities - Altura: 120 mm; Elevação ao Piso: 1355 mm; Afastamento da Origem: 1355 mm; Espessura: 120 mm; Perímetro Furos da Planta: 0 mm; Elevação do Topo Ao Piso de Origem: 1355 mm; Elevação da Base Ao Piso de Origem: 1235 mm; Área de Superfície dos Furos: 0 m2
Component Quantities - Concreto Armado Moldado in Loco - Estrutural, Espessura do Componente: 120 mm
Name | In | ID Dinâmico por Classificação | Concreto Armado Moldado in Loco - Estrutural, Carbono Incorporado | Concreto Armado Moldado in Loco - Estrutural, Energia Incorporada (MJ) | Perimeter (mm) = Perímetro na Planta (mm) | GrossArea (m2) = NetArea (m2) = Área (m2) = Área da Superfície (m2) = Área da Superfície do Topo (Líquida) (m2) = Área da Superfície do Topo (Condicional) (m2) = Área da Superfície da Base (Líquida) (m2) = Área da Superfície da Base (Condicional) (m2) = Área da Superfície da Base (Bruta) (m2) = Área da Superfície do Topo (Bruta) (m2) = Área da Superfície do Topo da Laje (Condicional) (m2) = Área da Superfície da Base da Laje (Bruta) (m2) = Área da Superfície da Base da Laje (Bruta, com os furos) (m2) = Área da Superfície do Topo da Laje (Bruta) (m2) = Área da Superfície do Topo da Laje (Bruta, com os furos) (m2) = Área da Superfície do Topo (Geral) (m2) = Área da Superfície da Base (Geral) (m2) = Área Condicional da Superfície do Topo (Geral) (m2) = Área Condicional da Superfície da Base (Geral) (m2) = Concreto Armado Moldado in Loco - Estrutural, Área de Componente Projetada (Líquida) (m2) = Concreto Armado Moldado in Loco - Estrutural, Área de Componente Projetada (Bruta) (m2) = Concreto Armado Moldado in Loco - Estrutural, Área de Componente Projetada (Condicional) (m2) | GrossVolume (m3) = NetVolume (m3) = Volume (Líquido) (m3) = Volume (Condicional) (m3) = Volume (Bruto) (m3) = Concreto Armado Moldado in Loco - Estrutural, Volume Componente (Líquido) (m3) = Concreto Armado Moldado in Loco - Estrutural, Volume do componente (Bruto) (m3) = Concreto Armado Moldado in Loco - Estrutural, Volume Componente (Condicional) (m3) | Elevação à Origem do Projeto (mm) = Elevação ao 1º Nível de Referência (mm) = Elevação ao 2º Nível de Referência (mm) = Elevação ao Nível do Mar (mm) = Elevação do Topo ao Primeiro Nível de Referência (mm) = Elevação do Topo À Cota Zero (mm) = Elevação do Topo Ao Nível do Mar (mm) = Elevação do Topo Ao Segundo Nível de Referência (mm) = Topo da Elevação (mm) | Elevação da Base Ao Primeiro Nível de Referência (mm) = Elevação da Base À Cota Zero (mm) = Elevação da Base Ao Nível do Mar (mm) = Elevação da Base Ao Segundo Nível de Referência (mm) = Elevação da Base (mm) | Área da Superfície da Borda (Líquida) (m2) = Área da Superfície das Bordas (Bruta) (m2) = Área da Superfície das Bordas da Laje (Bruta) (m2) = Área da Superfície das Bordas da Laje (Bruta, com as bordas dos furos) (m2) = Área da Superfície da Face (Geral) (m2) | Concreto Armado Moldado in Loco - Estrutural, Massa (kg)
APTO4-LAJE-002 | Primeiro Pavimento | Laje -002 | 248.104 (kgCO₂) | 2388.77 | 14980 | 3.5598 | 0.427176 | 1355 | 1235 | 1.7976 | 1025.22
APTO4-LAJE-003 | Primeiro Pavimento | Laje -003 | 199.052 (kgCO₂) | 1916.49 | 12220 | 2.856 | 0.34272 | 1355 | 1235 | 1.4664 | 822.528
APTO2-LAJE-003 | Primeiro Pavimento | Laje -003 | 199.052 (kgCO₂) | 1916.49 | 12220 | 2.856 | 0.34272 | 1355 | 1235 | 1.4664 | 822.528
APTO2-LAJE-002 | Primeiro Pavimento | Laje -002 | 248.104 (kgCO₂) | 2388.77 | 14980 | 3.5598 | 0.427176 | 1355 | 1235 | 1.7976 | 1025.22
APTO3-LAJE-003 | Primeiro Pavimento | Laje -003 | 199.052 (kgCO₂) | 1916.49 | 12220 | 2.856 | 0.34272 | 1355 | 1235 | 1.4664 | 822.528
APTO3-LAJE-002 | Primeiro Pavimento | Laje -002 | 248.104 (kgCO₂) | 2388.77 | 14980 | 3.5598 | 0.427176 | 1355 | 1235 | 1.7976 | 1025.22
APTO1-LAJE-002 | Primeiro Pavimento | Laje -002 | 248.104 (kgCO₂) | 2388.77 | 14980 | 3.5598 | 0.427176 | 1355 | 1235 | 1.7976 | 1025.22
APTO1-LAJE-003 | Primeiro Pavimento | Laje -003 | 199.052 (kgCO₂) | 1916.49 | 12220 | 2.856 | 0.34272 | 1355 | 1235 | 1.4664 | 822.528
APTO5-LAJE-003 | Segundo Pavimento | Laje -003 | 199.052 (kgCO₂) | 1916.49 | 12220 | 2.856 | 0.34272 | 4005 | 3885 | 1.4664 | 822.528
APTO5-LAJE-002 | Segundo Pavimento | Laje -002 | 248.104 (kgCO₂) | 2388.77 | 14980 | 3.5598 | 0.427176 | 4005 | 3885 | 1.7976 | 1025.22
APTO6-LAJE-003 | Segundo Pavimento | Laje -003 | 199.052 (kgCO₂) | 1916.49 | 12220 | 2.856 | 0.34272 | 4005 | 3885 | 1.4664 | 822.528
APTO6-LAJE-002 | Segundo Pavimento | Laje -002 | 248.104 (kgCO₂) | 2388.77 | 14980 | 3.5598 | 0.427176 | 4005 | 3885 | 1.7976 | 1025.22
APTO7-LAJE-003 | Segundo Pavimento | Laje -003 | 199.052 (kgCO₂) | 1916.49 | 12220 | 2.856 | 0.34272 | 4005 | 3885 | 1.4664 | 822.528
APTO7-LAJE-002 | Segundo Pavimento | Laje -002 | 248.104 (kgCO₂) | 2388.77 | 14980 | 3.5598 | 0.427176 | 4005 | 3885 | 1.7976 | 1025.22
APTO8-LAJE-003 | Segundo Pavimento | Laje -003 | 199.052 (kgCO₂) | 1916.49 | 12220 | 2.856 | 0.34272 | 4005 | 3885 | 1.4664 | 822.528
APTO8-LAJE-002 | Segundo Pavimento | Laje -002 | 248.104 (kgCO₂) | 2388.77 | 14980 | 3.5598 | 0.427176 | 4005 | 3885 | 1.7976 | 1025.22
APTO9-LAJE-003 | Terceiro Pavimento | Laje -003 | 199.052 (kgCO₂) | 1916.49 | 12220 | 2.856 | 0.34272 | 6655 | 6535 | 1.4664 | 822.528
APTO9-LAJE-002 | Terceiro Pavimento | Laje -002 | 248.104 (kgCO₂) | 2388.77 | 14980 | 3.5598 | 0.427176 | 6655 | 6535 | 1.7976 | 1025.22
APTO10-LAJE-003 | Terceiro Pavimento | Laje -003 | 199.052 (kgCO₂) | 1916.49 | 12220 | 2.856 | 0.34272 | 6655 | 6535 | 1.4664 | 822.528
APTO10-LAJE-002 | Terceiro Pavimento | Laje -002 | 248.104 (kgCO₂) | 2388.77 | 14980 | 3.5598 | 0.427176 | 6655 | 6535 | 1.7976 | 1025.22
APTO11-LAJE-003 | Terceiro Pavimento | Laje -003 | 199.052 (kgCO₂) | 1916.49 | 12220 | 2.856 | 0.34272 | 6655 | 6535 | 1.4664 | 822.528
APTO11-LAJE-002 | Terceiro Pavimento | Laje -002 | 248.104 (kgCO₂) | 2388.77 | 14980 | 3.5598 | 0.427176 | 6655 | 6535 | 1.7976 | 1025.22
APTO12-LAJE-003 | Terceiro Pavimento | Laje -003 | 199.052 (kgCO₂) | 1916.49 | 12220 | 2.856 | 0.34272 | 6655 | 6535 | 1.4664 | 822.528
APTO12-LAJE-002 | Terceiro Pavimento | Laje -002 | 248.104 (kgCO₂) | 2388.77 | 14980 | 3.5598 | 0.427176 | 6655 | 6535 | 1.7976 | 1025.22

# IfcSlab: Concreto Armado Moldado in Loco - Estrutural 150 (18)
Type - PredefinedType: FLOOR
Classification: Laje (Classificação ARCHICAD); 3E 12 06 08 Laje (NBR 15965-5 3E); Material: Concreto Armado Moldado in Loco - Estrutural 150 mm
PISOS (Expressão) - Índice de Perda (%): 10
ESTRUTURA (Expressão) - Custo por Volume (m3): 0; Estimativa de Custo Total por Volume: 0; Estimativa de Custo Total por Volume (R$): 0,00 R$
SUPERFÍCIES (Mapas) - Superfície do Topo (Geral): Concreto - 03; Superfície da Face (Geral): Concreto - 03; Superfície da Base (Geral): Concreto - 03
AC_Pset_RenovationAndPhasing - Renovation Status: Existing
Pset_SlabCommon - LoadBearing: yes
Component Properties - Concreto Armado Moldado in Loco - Estrutural, Tipo de Componente: Nenhum
BaseQuantities - Width: 150 mm
ArchiCADQuantities - Altura: 150 mm; Espessura: 150 mm; Perímetro Furos da Planta: 0 mm
Component Quantities - Concreto Armado Moldado in Loco - Estrutural, Espessura do Componente: 150 mm
Name | In | ID Dinâmico por Classificação | IsExternal | Concreto Armado Moldado in Loco - Estrutural, Carbono Incorporado | Concreto Armado Moldado in Loco - Estrutural, Energia Incorporada (MJ) | Perimeter (mm) = Perímetro na Planta (mm) | GrossArea (m2) = Área da Superfície da Base (Bruta) (m2) = Área da Superfície do Topo (Bruta) (m2) = Área da Superfície da Base da Laje (Bruta) (m2) = Área da Superfície da Base da Laje (Bruta, com os furos) (m2) = Área da Superfície do Topo da Laje (Bruta) (m2) = Área da Superfície do Topo da Laje (Bruta, com os furos) (m2) | NetArea (m2) = Área (m2) = Área da Superfície (m2) = Área da Superfície do Topo (Líquida) (m2) = Área da Superfície do Topo (Condicional) (m2) = Área da Superfície da Base (Líquida) (m2) = Área da Superfície da Base (Condicional) (m2) = Área da Superfície do Topo da Laje (Condicional) (m2) = Área da Superfície do Topo (Geral) (m2) = Área da Superfície da Base (Geral) (m2) = Área Condicional da Superfície do Topo (Geral) (m2) = Área Condicional da Superfície da Base (Geral) (m2) = Concreto Armado Moldado in Loco - Estrutural, Área de Componente Projetada (Líquida) (m2) = Concreto Armado Moldado in Loco - Estrutural, Área de Componente Projetada (Bruta) (m2) = Concreto Armado Moldado in Loco - Estrutural, Área de Componente Projetada (Condicional) (m2) | GrossVolume (m3) = Volume (Bruto) (m3) | NetVolume (m3) = Volume (Líquido) (m3) = Volume (Condicional) (m3) = Concreto Armado Moldado in Loco - Estrutural, Volume Componente (Líquido) (m3) = Concreto Armado Moldado in Loco - Estrutural, Volume do componente (Bruto) (m3) = Concreto Armado Moldado in Loco - Estrutural, Volume Componente (Condicional) (m3) | Elevação à Origem do Projeto (mm) = Elevação ao 1º Nível de Referência (mm) = Elevação ao 2º Nível de Referência (mm) = Elevação ao Nível do Mar (mm) = Elevação do Topo ao Primeiro Nível de Referência (mm) = Elevação do Topo À Cota Zero (mm) = Elevação do Topo Ao Nível do Mar (mm) = Elevação do Topo Ao Segundo Nível de Referência (mm) = Topo da Elevação (mm) | Elevação ao Piso (mm) = Afastamento da Origem (mm) = Elevação do Topo Ao Piso de Origem (mm) | Elevação da Base Ao Primeiro Nível de Referência (mm) = Elevação da Base À Cota Zero (mm) = Elevação da Base Ao Nível do Mar (mm) = Elevação da Base Ao Segundo Nível de Referência (mm) = Elevação da Base (mm) | Elevação da Base Ao Piso de Origem (mm) | Área da Superfície da Borda (Líquida) (m2) = Área da Superfície da Face (Geral) (m2) | Área da Superfície das Bordas (Bruta) (m2) = Área da Superfície das Bordas da Laje (Bruta) (m2) = Área da Superfície das Bordas da Laje (Bruta, com as bordas dos furos) (m2) | Área de Superfície dos Furos (m2) | Concreto Armado Moldado in Loco - Estrutural, Massa (kg)
LAJE-015 | Pavimento Terreo | Laje -015 | yes | 1893.59 (kgCO₂) | 18231.7 | 33304.1 | 21.7354 | 21.7354 | 3.26031 | 3.26031 | -2700 | -50 | -2850 | -200 | 4.99561 | 4.99561 | 0 | 7824.75
LAJE-009 | Pavimento Terreo | Laje -009 | yes | 10179.7 (kgCO₂) | 98011 | 45270 | 116.847 | 116.847 | 17.527 | 17.527 | -2650 | 0 | -2800 | -150 | 6.7905 | 6.7905 | 0 | 42064.8
LAJE-011 | Pavimento Terreo | Laje -011 | yes | 10224.8 (kgCO₂) | 98445.4 | 45412 | 117.365 | 117.365 | 17.6047 | 17.6047 | -2650 | 0 | -2800 | -150 | 6.81181 | 6.81181 | 0 | 42251.2
APTO4-LAJE-000 | Primeiro Pavimento | Laje -000 | no | 5101.89 (kgCO₂) | 49121.5 | 30770 | 58.8317 | 58.5617 | 8.82475 | 8.78425 | 0 | 0 | -150 | -150 | 4.4355 | 4.6155 | 0.27 | 21082.2
APTO2-LAJE-000 | Primeiro Pavimento | Laje -000 | no | 5101.89 (kgCO₂) | 49121.5 | 30770 | 58.8317 | 58.5617 | 8.82475 | 8.78425 | 0 | 0 | -150 | -150 | 4.4355 | 4.6155 | 0.27 | 21082.2
APTO3-LAJE-000 | Primeiro Pavimento | Laje -000 | no | 5101.89 (kgCO₂) | 49121.5 | 30770 | 58.8317 | 58.5617 | 8.82475 | 8.78425 | 0 | 0 | -150 | -150 | 4.4355 | 4.6155 | 0.27 | 21082.2
APTO1-LAJE-000 | Primeiro Pavimento | Laje -000 | no | 5101.89 (kgCO₂) | 49121.5 | 30770 | 58.8317 | 58.5617 | 8.82475 | 8.78425 | 0 | 0 | -150 | -150 | 4.4355 | 4.6155 | 0.27 | 21082.2
APTO5-LAJE-000 | Segundo Pavimento | Laje -000 | no | 5101.89 (kgCO₂) | 49121.5 | 30770 | 58.8317 | 58.5617 | 8.82475 | 8.78425 | 2650 | 0 | 2500 | -150 | 4.4355 | 4.6155 | 0.27 | 21082.2
APTO6-LAJE-000 | Segundo Pavimento | Laje -000 | no | 5101.89 (kgCO₂) | 49121.5 | 30770 | 58.8317 | 58.5617 | 8.82475 | 8.78425 | 2650 | 0 | 2500 | -150 | 4.4355 | 4.6155 | 0.27 | 21082.2
APTO7-LAJE-000 | Segundo Pavimento | Laje -000 | no | 5101.89 (kgCO₂) | 49121.5 | 30770 | 58.8317 | 58.5617 | 8.82475 | 8.78425 | 2650 | 0 | 2500 | -150 | 4.4355 | 4.6155 | 0.27 | 21082.2
APTO8-LAJE-000 | Segundo Pavimento | Laje -000 | no | 5101.89 (kgCO₂) | 49121.5 | 30770 | 58.8317 | 58.5617 | 8.82475 | 8.78425 | 2650 | 0 | 2500 | -150 | 4.4355 | 4.6155 | 0.27 | 21082.2
APTO9-LAJE-000 | Terceiro Pavimento | Laje -000 | no | 5101.89 (kgCO₂) | 49121.5 | 30770 | 58.8317 | 58.5617 | 8.82475 | 8.78425 | 5300 | 0 | 5150 | -150 | 4.4355 | 4.6155 | 0.27 | 21082.2
APTO10-LAJE-000 | Terceiro Pavimento | Laje -000 | no | 5101.89 (kgCO₂) | 49121.5 | 30770 | 58.8317 | 58.5617 | 8.82475 | 8.78425 | 5300 | 0 | 5150 | -150 | 4.4355 | 4.6155 | 0.27 | 21082.2
APTO11-LAJE-000 | Terceiro Pavimento | Laje -000 | no | 5101.89 (kgCO₂) | 49121.5 | 30770 | 58.8317 | 58.5617 | 8.82475 | 8.78425 | 5300 | 0 | 5150 | -150 | 4.4355 | 4.6155 | 0.27 | 21082.2
APTO12-LAJE-000 | Terceiro Pavimento | Laje -000 | no | 5101.89 (kgCO₂) | 49121.5 | 30770 | 58.8317 | 58.5617 | 8.82475 | 8.78425 | 5300 | 0 | 5150 | -150 | 4.4355 | 4.6155 | 0.27 | 21082.2
LAJE-010 | Pavimento Cobertura | Laje -010 | yes | 10132.6 (kgCO₂) | 97558 | 45270 | 116.847 | 116.307 | 17.527 | 17.446 | 7950 | 0 | 7800 | -150 | 6.7905 | 6.7905 | 0.54 | 41870.4
LAJE-016 | Pavimento Cobertura | Laje -016 | yes | 2578.13 (kgCO₂) | 24822.5 | 26704.1 | 29.5929 | 29.5929 | 4.43894 | 4.43894 | 7950 | 0 | 7800 | -150 | 4.00561 | 4.00561 | 0 | 10653.4
LAJE-012 | Pavimento Cobertura | Laje -012 | yes | 10177.8 (kgCO₂) | 97992.4 | 45412 | 117.365 | 116.825 | 17.6047 | 17.5237 | 7950 | 0 | 7800 | -150 | 6.81181 | 6.81181 | 0.54 | 42056.8

# IfcSlab: Concreto Armado Moldado in Loco - Estrutural 180 (6)
Type - PredefinedType: FLOOR
Classification: Laje (Classificação ARCHICAD); 3E 08 06 04 06 Patamar de escada (NBR 15965-5 3E); Material: Concreto Armado Moldado in Loco - Estrutural 180 mm
PISOS (Expressão) - Índice de Perda (%): 10
ESTRUTURA (Expressão) - Custo por Volume (m3): 0; Estimativa de Custo Total por Volume: 0; Estimativa de Custo Total por Volume (R$): 0,00 R$
SUPERFÍCIES (Mapas) - Superfície do Topo (Geral): Concreto - 03; Superfície da Face (Geral): Concreto - 03; Superfície da Base (Geral): Concreto - 03; Área da Superfície da Face (Geral): 0.999 m2
AC_Pset_RenovationAndPhasing - Renovation Status: Existing
Pset_SlabCommon - LoadBearing: yes; IsExternal: yes
Component Properties - Concreto Armado Moldado in Loco - Estrutural, Tipo de Componente: Nenhum
BaseQuantities - Width: 180 mm; Perimeter: 5550 mm
ArchiCADQuantities - Altura: 180 mm; Espessura: 180 mm; Perímetro na Planta: 5550 mm; Perímetro Furos da Planta: 0 mm; Área da Superfície da Borda (Líquida): 0.999 m2; Área da Superfície das Bordas (Bruta): 0.999 m2; Área da Superfície das Bordas da Laje (Bruta): 0.999 m2; Área da Superfície das Bordas da Laje (Bruta, com as bordas dos furos): 0.999 m2; Área de Superfície dos Furos: 0 m2
Component Quantities - Concreto Armado Moldado in Loco - Estrutural, Espessura do Componente: 180 mm
Name | In | ID Dinâmico por Classificação | Concreto Armado Moldado in Loco - Estrutural, Carbono Incorporado | Concreto Armado Moldado in Loco - Estrutural, Energia Incorporada (MJ) | GrossArea (m2) = NetArea (m2) = Área (m2) = Área da Superfície (m2) = Área da Superfície do Topo (Líquida) (m2) = Área da Superfície do Topo (Condicional) (m2) = Área da Superfície da Base (Líquida) (m2) = Área da Superfície da Base (Condicional) (m2) = Área da Superfície da Base (Bruta) (m2) = Área da Superfície do Topo (Bruta) (m2) = Área da Superfície do Topo da Laje (Condicional) (m2) = Área da Superfície da Base da Laje (Bruta) (m2) = Área da Superfície da Base da Laje (Bruta, com os furos) (m2) = Área da Superfície do Topo da Laje (Bruta) (m2) = Área da Superfície do Topo da Laje (Bruta, com os furos) (m2) = Área da Superfície do Topo (Geral) (m2) = Área da Superfície da Base (Geral) (m2) = Área Condicional da Superfície do Topo (Geral) (m2) = Área Condicional da Superfície da Base (Geral) (m2) = Concreto Armado Moldado in Loco - Estrutural, Área de Componente Projetada (Líquida) (m2) = Concreto Armado Moldado in Loco - Estrutural, Área de Componente Projetada (Bruta) (m2) = Concreto Armado Moldado in Loco - Estrutural, Área de Componente Projetada (Condicional) (m2) | GrossVolume (m3) = NetVolume (m3) = Volume (Líquido) (m3) = Volume (Condicional) (m3) = Volume (Bruto) (m3) = Concreto Armado Moldado in Loco - Estrutural, Volume Componente (Líquido) (m3) = Concreto Armado Moldado in Loco - Estrutural, Volume do componente (Bruto) (m3) = Concreto Armado Moldado in Loco - Estrutural, Volume Componente (Condicional) (m3) | Elevação à Origem do Projeto (mm) = Elevação ao 1º Nível de Referência (mm) = Elevação ao 2º Nível de Referência (mm) = Elevação ao Nível do Mar (mm) | Elevação ao Piso (mm) = Afastamento da Origem (mm) | Elevação do Topo ao Primeiro Nível de Referência (mm) = Elevação do Topo À Cota Zero (mm) = Elevação do Topo Ao Nível do Mar (mm) = Elevação do Topo Ao Segundo Nível de Referência (mm) = Topo da Elevação (mm) | Elevação do Topo Ao Piso de Origem (mm) | Elevação da Base Ao Primeiro Nível de Referência (mm) = Elevação da Base À Cota Zero (mm) = Elevação da Base Ao Nível do Mar (mm) = Elevação da Base Ao Segundo Nível de Referência (mm) = Elevação da Base (mm) | Elevação da Base Ao Piso de Origem (mm) | Concreto Armado Moldado in Loco - Estrutural, Massa (kg)
LAJE-013 | Pavimento Terreo | Laje -013 | 195.116 (kgCO₂) | 1878.59 | 1.86635 | 0.335943 | -1080 | 1570 | -900 | 1750 | -1080 | 1570 | 806.263
LAJE-014 | Pavimento Terreo | Laje -014 | 190.145 (kgCO₂) | 1830.73 | 1.8188 | 0.327384 | -2110.57 | 539.429 | -1930.57 | 719.429 | -2110.57 | 539.429 | 785.722
CIRC1-LAJE-005 | Primeiro Pavimento | Laje -005 | 195.116 (kgCO₂) | 1878.59 | 1.86635 | 0.335943 | 1710.57 | 1710.57 | 1710.57 | 1710.57 | 1530.57 | 1530.57 | 806.263
CIRC1-LAJE-006 | Primeiro Pavimento | Laje -006 | 190.145 (kgCO₂) | 1830.73 | 1.8188 | 0.327384 | 680 | 680 | 680 | 680 | 500 | 500 | 785.722
CIRC2-LAJE-005 | Segundo Pavimento | Laje -005 | 195.116 (kgCO₂) | 1878.59 | 1.86635 | 0.335943 | 4360.57 | 1710.57 | 4360.57 | 1710.57 | 4180.57 | 1530.57 | 806.263
CIRC2-LAJE-006 | Segundo Pavimento | Laje -006 | 190.145 (kgCO₂) | 1830.73 | 1.8188 | 0.327384 | 3330 | 680 | 3330 | 680 | 3150 | 500 | 785.722

# IfcStair (9)
Classification: Escada (Classificação ARCHICAD); 3E 08 06 04 Escada (NBR 15965-5 3E)
Pset_StairCommon - RequiredHeadroom: 2200 mm; IsExternal: yes
DESCRIÇÃO DA ESCADA (Expressão) - Abreviação da Largura da Escada: L; Abreviação da Altura do Espelho: E; Abreviação da Profundidade do Piso: P
AC_Pset_RenovationAndPhasing - Renovation Status: Existing
ArchiCADQuantities - Largura Piso Padrão: 270 mm; Dimensão da Altura Livre Obrigatória: 2200 mm; Piso Mínimo (pela Regra): 270 mm; Piso Máximo (pela Regra): 270 mm
Name | In | NumberOfRiser = Número De Espelhos (total) | NumberOfTreads = Número De Pisos (total) | RiserHeight (mm) = Altura do Espelho Padrão (mm) | Localização do Produto no Projeto | ID Dinâmico por Classificação | Info 2E + P | Length (mm) = Comprimento Linha de Subida (mm) | Height (mm) = Altura (mm) | GrossVolume (m3) = NetVolume (m3) = Volume (Líquido) (m3) | Área (m2) = Área da Superfície do Topo (Líquida) (m2) | Elevação à Origem do Projeto (mm) = Elevação ao 1º Nível de Referência (mm) = Elevação ao 2º Nível de Referência (mm) = Elevação ao Nível do Mar (mm) = Elevação da Base Ao Primeiro Nível de Referência (mm) = Elevação da Base À Cota Zero (mm) = Elevação da Base Ao Nível do Mar (mm) = Elevação da Base Ao Segundo Nível de Referência (mm) | Elevação ao Piso (mm) = Afastamento da Origem (mm) = Elevação da Base Ao Piso de Origem (mm) | Afastamento do Topo (mm) | Elevação do Topo ao Primeiro Nível de Referência (mm) = Elevação do Topo À Cota Zero (mm) = Elevação do Topo Ao Nível do Mar (mm) = Elevação do Topo Ao Segundo Nível de Referência (mm) | Elevação do Topo Ao Piso de Origem (mm) | Largura da Escada Padrão (mm) | Área de Superfície Frontal da Escada (m2) | Altura Máxima do Espelho (pela Regra) (mm) | Resultado 2E + P (mm) | Altura Mínima do Espelho (pela Regra) (mm)
ESCADA-005 | Pavimento Terreo | 5 | 5 | 159.952 | Projeto: CECAP GuarulhosLocal: Piso: Pavimento Terreo Cômodo: ESCADA | Escada -005 | 2 x 0,16 ( E ) + 0,27 ( P ) = 0,59 | 1350 | 799.762 | 0.330787 | 1.512 | -939.429 | 1710.57 | 0 | -239.667 | 2410.33 | 1120 | 1.03573 | 180 | 589.905
ESCADA-003 | Pavimento Terreo | 6 | 6 | 175.619 | Projeto: CECAP GuarulhosLocal: Piso: Pavimento Terreo Cômodo: ESCADA | Escada -003 | 2 x 0,18 ( E ) + 0,27 ( P ) = 0,62 | 1620 | 1053.71 | 0.375676 | 1.5795 | -1930.57 | 719.429 | -3526.86 | -976.857 | 1673.14 | 975 | 1.17362 | 180 | 621.238 | 170
ESCADA-004 | Pavimento Terreo | 4 | 3 | 182.5 | Projeto: CECAP GuarulhosLocal: Piso: Pavimento Terreo Cômodo: ESCADA | Escada -004 | 2 x 0,18 ( E ) + 0,27 ( P ) = 0,64 | 810 | 730 | 0.277421 | 0.9072 | -2700 | -50 | -1970 | -2070 | 580 | 1120 | 0.9016 |  | 635 | 170
CIRC1-ESCADA-002 | Primeiro Pavimento | 5 | 5 | 159.952 | Projeto: CECAP GuarulhosLocal: Piso: Primeiro Pavimento Cômodo: ESCADA | Escada -002 | 2 x 0,16 ( E ) + 0,27 ( P ) = 0,59 | 1350 | 799.762 | 0.330787 | 1.512 | 1710.57 | 1710.57 | 0 | 2410.33 | 2410.33 | 1120 | 1.03573 | 180 | 589.905
CIRC1-ESCADA-000 | Primeiro Pavimento | 6 | 6 | 176.762 | Projeto: CECAP GuarulhosLocal: Piso: Primeiro Pavimento Cômodo: ESCADA | Escada -000 | 2 x 0,18 ( E ) + 0,27 ( P ) = 0,62 | 1620 | 1060.57 | 0.3772 | 1.5795 | 680 | 680 | -939.429 | 1640.57 | 1640.57 | 975 | 1.18031 | 180 | 623.524 | 170
CIRC1-ESCADA-001 | Primeiro Pavimento | 4 | 3 | 182.5 | Projeto: CECAP GuarulhosLocal: Piso: Primeiro Pavimento Cômodo: ESCADA | Escada -001 | 2 x 0,18 ( E ) + 0,27 ( P ) = 0,64 | 810 | 730 | 0.277421 | 0.9072 | -50 | -50 | -1970 | 580 | 580 | 1120 | 0.9016 |  | 635 | 170
CIRC2-ESCADA-002 | Segundo Pavimento | 5 | 5 | 159.952 | Projeto: CECAP GuarulhosLocal: Piso: Segundo Pavimento Cômodo: ESCADA | Escada -002 | 2 x 0,16 ( E ) + 0,27 ( P ) = 0,59 | 1350 | 799.762 | 0.330787 | 1.512 | 4360.57 | 1710.57 | 0 | 5060.33 | 2410.33 | 1120 | 1.03573 | 180 | 589.905
CIRC2-ESCADA-000 | Segundo Pavimento | 6 | 6 | 176.762 | Projeto: CECAP GuarulhosLocal: Piso: Segundo Pavimento Cômodo: ESCADA | Escada -000 | 2 x 0,18 ( E ) + 0,27 ( P ) = 0,62 | 1620 | 1060.57 | 0.3772 | 1.5795 | 3330 | 680 | -939.429 | 4290.57 | 1640.57 | 975 | 1.18031 | 180 | 623.524 | 170
CIRC2-ESCADA-001 | Segundo Pavimento | 4 | 3 | 182.5 | Projeto: CECAP GuarulhosLocal: Piso: Segundo Pavimento Cômodo: ESCADA | Escada -001 | 2 x 0,18 ( E ) + 0,27 ( P ) = 0,64 | 810 | 730 | 0.277421 | 0.9072 | 2600 | -50 | -1970 | 3230 | 580 | 1120 | 0.9016 |  | 635 | 170

# IfcWall: IfcWall (9)
Classification: Parede (Classificação ARCHICAD); Material: Concreto
EXPRESSÕES DE TEXTO (Expressão) - ID Dinâmico por Classificação: Parede - Barra Superior - 001
AC_Pset_RenovationAndPhasing - Renovation Status: Existing
ArchiCADQuantities - Altura: 1250 mm; Largura: 205.112 mm; Espessura: 205.112 mm
ALVENARIAS (Expressão) - Espessura da Argamassa: 10 mm
Name | In | GrossVolume (m3) = NetVolume (m3) = Volume (Líquido) (m3) | Length (mm) = Comprimento 3D (mm) | Elevação à Origem do Projeto (mm) = Elevação ao 1º Nível de Referência (mm) = Elevação ao 2º Nível de Referência (mm) = Elevação ao Nível do Mar (mm) = Elevação do Topo ao Primeiro Nível de Referência (mm) = Elevação do Topo À Cota Zero (mm) = Elevação do Topo Ao Nível do Mar (mm) = Elevação do Topo Ao Segundo Nível de Referência (mm) | Elevação ao Piso (mm) = Afastamento da Origem (mm) = Elevação do Topo Ao Piso de Origem (mm) | Elevação da Base Ao Primeiro Nível de Referência (mm) = Elevação da Base À Cota Zero (mm) = Elevação da Base Ao Nível do Mar (mm) = Elevação da Base Ao Segundo Nível de Referência (mm) | Elevação da Base Ao Piso de Origem (mm)
GC - Barra Superior - 001 | Pavimento Terreo | 0.40139 | 1782.59 | -900 | 1750 | -2150 | 500 | Component Properties - Concreto, Carbono Incorporado: 77.3078 (kgCO₂); Concreto, Energia Incorporada: 534.652 MJ; Component Quantities - Concreto, Massa: 722.503 kg; Concreto, Volume Componente (Líquido): 0.40139 m3; Concreto, Volume do componente (Bruto): 0.40139 m3
GC - Barra Superior - 001 | Pavimento Terreo | 0.433619 | 2120.99 | 130.571 | 2780.57 | -2150 | 500 | Component Properties - Concreto, Carbono Incorporado: 83.515 (kgCO₂); Concreto, Energia Incorporada: 577.58 MJ; Component Quantities - Concreto, Massa: 780.514 kg; Concreto, Volume Componente (Líquido): 0.433619 m3; Concreto, Volume do componente (Bruto): 0.433619 m3
GC - Barra Superior - 001 | Pavimento Terreo | 0.361985 | 1630 | 130.571 | 2780.57 | -1119.43 | 1530.57 | Component Properties - Concreto, Carbono Incorporado: 69.7184 (kgCO₂); Concreto, Energia Incorporada: 482.165 MJ; Component Quantities - Concreto, Massa: 651.574 kg; Concreto, Volume Componente (Líquido): 0.361985 m3; Concreto, Volume do componente (Bruto): 0.361985 m3
CIRC1-GC - Barra Superior - 001 | Primeiro Pavimento | 0.40139 | 1782.59 | 1750 | 1750 | 500 | 500
CIRC1-GC - Barra Superior - 001 | Primeiro Pavimento | 0.433619 | 2120.99 | 2780.57 | 2780.57 | 500 | 500
CIRC1-GC - Barra Superior - 001 | Primeiro Pavimento | 0.361985 | 1630 | 2780.57 | 2780.57 | 1530.57 | 1530.57
CIRC2-GC - Barra Superior - 001 | Segundo Pavimento | 0.40139 | 1782.59 | 4400 | 1750 | 3150 | 500
CIRC2-GC - Barra Superior - 001 | Segundo Pavimento | 0.433619 | 2120.99 | 5430.57 | 2780.57 | 3150 | 500
CIRC2-GC - Barra Superior - 001 | Segundo Pavimento | 0.361985 | 1630 | 5430.57 | 2780.57 | 4180.57 | 1530.57

# IfcWallStandardCase: Concreto Armado Moldado in Loco - Estrutural 190 (12)
Classification: Parede (Classificação ARCHICAD); 3E 14 02 00 Parede (NBR 15965-5 3E); Material: Concreto Armado Moldado in Loco - Estrutural 190 mm
Pset_WallCommon - AcousticRating: 0,00; IsExternal: yes
CLASSIFICAÇÕES GERAIS - Transmissão Sonora: 0
SUPERFÍCIES (Mapas) - Superfície da Face (Geral): Concreto - 03
AC_Pset_RenovationAndPhasing - Renovation Status: Existing
Component Properties - Concreto Armado Moldado in Loco - Estrutural, Tipo de Componente: Nenhum
BaseQuantities - Width: 190 mm
ArchiCADQuantities - Altura: 2700 mm; Largura: 190 mm; Elevação ao Piso: -50 mm; Afastamento da Origem: -50 mm; Afastamento do Topo: 0 mm; Espessura: 190 mm; Espessura da Camada de Isolamento: 0 mm; Elevação da Base Ao Piso de Origem: -50 mm; Número de Portas: 0; Número de Furos (Número de Aberturas Vazias): 0; Número de Janelas: 0; Número de Pilares: 0; Volume dos Pilares: 0 m3; Altura Máxima da Camada da Parede na Face Interna: 0 mm; Altura Mínima da Camada da Parede na Face Interna: 0 mm; Altura mínima da parede: 0 mm; Altura Máxima da Camada da Parede na Face Externa: 0 mm; Altura Mínima da Camada da Parede na Face Externa: 0 mm; Espessura da Camada de Ar: 0 mm; Área das Portas: 0 m2; Soma das Larguras das Portas: 0 mm; Espessura do Componente na Face Interna da Parede: 0 mm; Espessura do Componentena na Face Externa da Parede: 0 mm; Área das Janelas: 0 m2; Soma das Larguras das Janelas: 0 mm; Área Analítica da Superfície das Aberturas da Face Interna: 0 m2; Área Analítica da Superfície das Aberturas da Face Externa: 0 m2; Volume Analítico das Aberturas: 0 m3; Espessura da Parede na Terminação: 190 mm; Área de Superfície do Vão na Parede: 0 m2
ALVENARIAS (Expressão) - Espessura da Argamassa: 10 mm
Component Quantities - Concreto Armado Moldado in Loco - Estrutural, Espessura do Componente: 190 mm; Concreto Armado Moldado in Loco - Estrutural, Altura do Componente Retangular: 2700 mm; Concreto Armado Moldado in Loco - Estrutural, Largura do Componente Retangular: 190 mm; Concreto Armado Moldado in Loco - Estrutural, Área de Seção Transversal do Componente: 0.513 m2
Name | In | ID Dinâmico por Classificação | Concreto Armado Moldado in Loco - Estrutural, Carbono Incorporado | Concreto Armado Moldado in Loco - Estrutural, Energia Incorporada (MJ) | Length (mm) = Comprimento Médio da Parede (mm) = Comprimento da parede no centro (mm) | Height (mm) = Altura máxima da parede (mm) | GrossFootprintArea (m2) = NetFootprintArea (m2) = Área (m2) = Área da Superfície do Topo (Líquida) (m2) | GrossSideArea (m2) = NetSideArea (m2) | GrossVolume (m3) = NetVolume (m3) = Volume (Líquido) (m3) = Volume (Condicional) (m3) = Concreto Armado Moldado in Loco - Estrutural, Volume Componente (Líquido) (m3) = Concreto Armado Moldado in Loco - Estrutural, Volume do componente (Bruto) (m3) = Concreto Armado Moldado in Loco - Estrutural, Volume Componente (Condicional) (m3) | Elevação à Origem do Projeto (mm) = Elevação ao 1º Nível de Referência (mm) = Elevação ao 2º Nível de Referência (mm) = Elevação ao Nível do Mar (mm) = Elevação da Base Ao Primeiro Nível de Referência (mm) = Elevação da Base À Cota Zero (mm) = Elevação da Base Ao Nível do Mar (mm) = Elevação da Base Ao Segundo Nível de Referência (mm) | Área da Superfície (m2) = Área da Superfície da Base (Líquida) (m2) = Área da Superfície da Face Externa da Parede (Líquida) (m2) = Área da Superfície da Face Externa da Parede (Condicional) (m2) = Concreto Armado Moldado in Loco - Estrutural, Área de Componente Projetada (Líquida) (m2) = Concreto Armado Moldado in Loco - Estrutural, Área de Componente Projetada (Bruta) (m2) = Concreto Armado Moldado in Loco - Estrutural, Área de Componente Projetada (Condicional) (m2) | Comprimento 3D (mm) | Volume (Bruto) (m3) | Perímetro na Planta (mm) | Elevação do Topo ao Primeiro Nível de Referência (mm) = Elevação do Topo À Cota Zero (mm) = Elevação do Topo Ao Nível do Mar (mm) = Elevação do Topo Ao Segundo Nível de Referência (mm) | Elevação do Topo Ao Piso de Origem (mm) | Área da Superfície da Borda (Líquida) (m2) = Área da Superfície da Face (Geral) (m2) | Área da Superfície da Face Interna da Parede (Líquida) (m2) = Área da Superfície da Face Interna da Parede (Condicional) (m2) | Comprimento da Linha de Referência (mm) = Comprimento da Face Externa da Parede (Condicional) (mm) = Comprimento da Parede na Face Externa (mm) | Comprimento da Face Interna da Parede (Condicional) (mm) = Comprimento da Parede na Face Interna (mm) | Área da Superfície da Face Interna da Parede (Bruta) (m2) = Área da Superfície da Face Externa da Parede (Bruta) (m2) | Concreto Armado Moldado in Loco - Estrutural, Massa (kg)
PAREDE-043 | Pavimento Terreo | Parede -043 | 362.164 (kgCO₂) | 3486.95 | 1155 | 2650 | 0.2375 | 3.2819 | 0.623561 | -2700 | 3.2819 | 1250 | 0.64125 | 2768.7 | -50 | 2600 | 0.741 | 3.2819 | 1060 | 1250 | 3.375 | 1496.55
PAREDE-042 | Pavimento Terreo | Parede -042 | 309.979 (kgCO₂) | 2984.51 | 1155 | 2650 | 0.2014 | 2.809 | 0.53371 | -2700 | 2.809 | 1060 | 0.64125 | 2768.7 | -50 | 2600 | 0.7049 | 2.809 | 1060 | 1250 | 3.375 | 1280.9
PAREDE-041 | Pavimento Terreo | Parede -041 | 552.859 (kgCO₂) | 5322.99 | 1910 | 2650 | 0.3629 | 5.0327 | 0.951893 | -2700 | 5.0615 | 1910 | 1.0773 | 4357.4 | -50 | 2600 | 0.3629 | 5.0039 | 1720 | 2100 | 5.67 | 2284.54
CIRC1-PAREDE-023 | Primeiro Pavimento | Parede -023 | 309.979 (kgCO₂) | 2984.51 | 1155 | 2650 | 0.2014 | 2.809 | 0.53371 | -50 | 2.809 | 1060 | 0.64125 | 2768.7 | 2600 | 2600 | 0.7049 | 2.809 | 1060 | 1250 | 3.375 | 1280.9
CIRC1-PAREDE-022 | Primeiro Pavimento | Parede -022 | 552.859 (kgCO₂) | 5322.99 | 1910 | 2650 | 0.3629 | 5.0327 | 0.951893 | -50 | 5.0615 | 1910 | 1.0773 | 4357.4 | 2600 | 2600 | 0.3629 | 5.0039 | 1720 | 2100 | 5.67 | 2284.54
CIRC1-PAREDE-024 | Primeiro Pavimento | Parede -024 | 362.164 (kgCO₂) | 3486.95 | 1155 | 2650 | 0.2375 | 3.2819 | 0.623561 | -50 | 3.2819 | 1250 | 0.64125 | 2768.7 | 2600 | 2600 | 0.741 | 3.2819 | 1060 | 1250 | 3.375 | 1496.55
CIRC2-PAREDE-022 | Segundo Pavimento | Parede -022 | 552.859 (kgCO₂) | 5322.99 | 1910 | 2650 | 0.3629 | 5.0327 | 0.951893 | 2600 | 5.0615 | 1910 | 1.0773 | 4357.4 | 5250 | 2600 | 0.3629 | 5.0039 | 1720 | 2100 | 5.67 | 2284.54
CIRC2-PAREDE-023 | Segundo Pavimento | Parede -023 | 309.979 (kgCO₂) | 2984.51 | 1155 | 2650 | 0.2014 | 2.809 | 0.53371 | 2600 | 2.809 | 1060 | 0.64125 | 2768.7 | 5250 | 2600 | 0.7049 | 2.809 | 1060 | 1250 | 3.375 | 1280.9
CIRC2-PAREDE-024 | Segundo Pavimento | Parede -024 | 362.164 (kgCO₂) | 3486.95 | 1155 | 2650 | 0.2375 | 3.2819 | 0.623561 | 2600 | 3.2819 | 1250 | 0.64125 | 2768.7 | 5250 | 2600 | 0.741 | 3.2819 | 1060 | 1250 | 3.375 | 1496.55
CIRC3-PAREDE-033 | Terceiro Pavimento | Parede -033 | 298.281 (kgCO₂) | 2871.88 | 1155 | 2550 | 0.2014 | 2.703 | 0.51357 | 5250 | 2.703 | 1060 | 0.64125 | 2768.7 | 7800 | 2500 | 0.6859 | 2.703 | 1060 | 1250 | 3.375 | 1232.57
CIRC3-PAREDE-034 | Terceiro Pavimento | Parede -034 | 351.747 (kgCO₂) | 3386.66 | 1155 | 2550 | 0.2375 | 3.1875 | 0.605625 | 5250 | 3.1875 | 1250 | 0.64125 | 2768.7 | 7800 | 2500 | 0.722 | 3.1875 | 1060 | 1250 | 3.375 | 1453.5
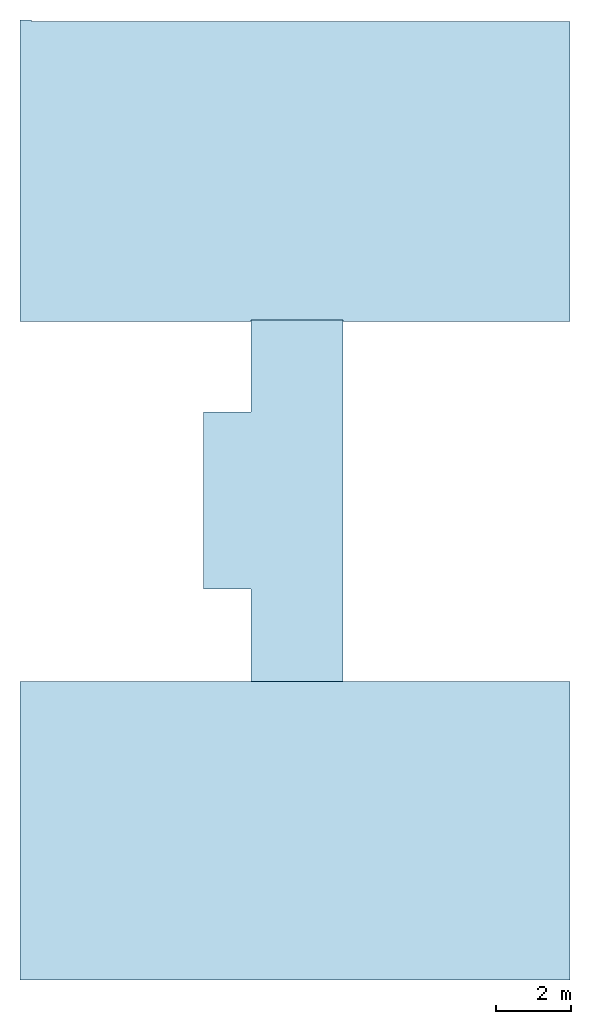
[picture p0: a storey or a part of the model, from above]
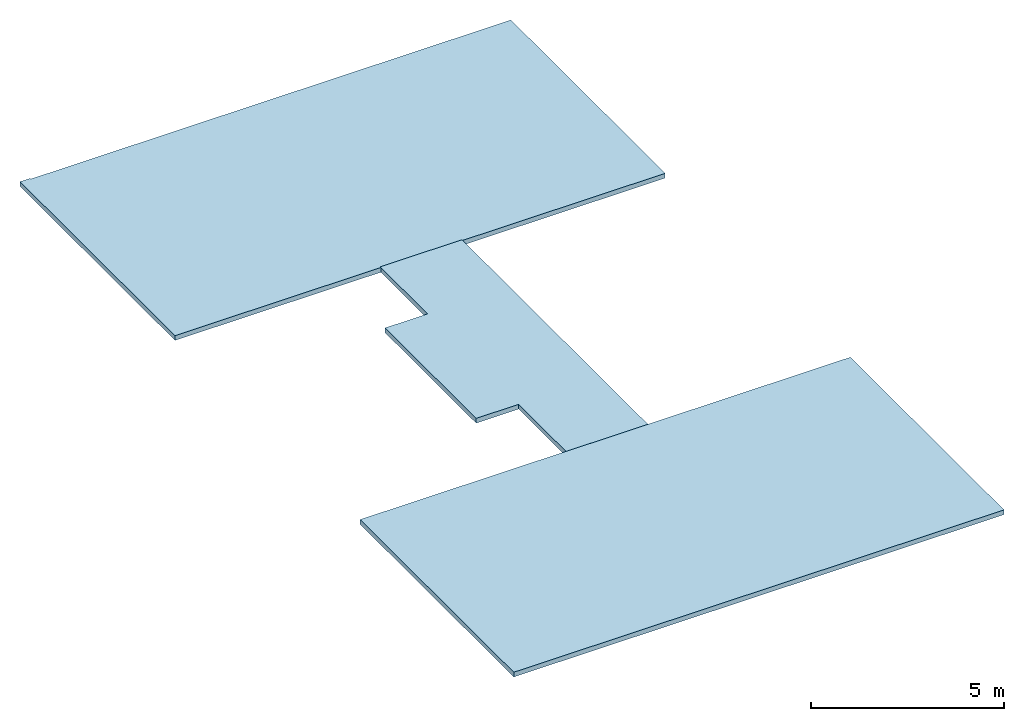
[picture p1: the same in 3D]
Properties of the parts of a building model (IFC2X3), part 7 of 7

# IfcWallStandardCase: GENÉRICO - VEDAÇÃO EXTERNA 40 (72)
Name | In | ID Dinâmico por Classificação | GENÉRICO - VEDAÇÃO EXTERNA, Carbono Incorporado | GENÉRICO - VEDAÇÃO EXTERNA, Energia Incorporada (MJ) | Length (mm) = Comprimento 3D (mm) = Comprimento Médio da Parede (mm) = Comprimento da parede no centro (mm) = Comprimento da Parede na Face Interna (mm) = Comprimento da Parede na Face Externa (mm) | Height (mm) = Elevação do Topo Ao Piso de Origem (mm) = Altura máxima da parede (mm) | GrossFootprintArea (m2) = NetFootprintArea (m2) = Área (m2) = Área da Superfície do Topo (Líquida) (m2) | GrossSideArea (m2) = Área da Superfície da Face Interna da Parede (Condicional) (m2) = Área da Superfície da Face Externa da Parede (Condicional) (m2) = GENÉRICO - VEDAÇÃO EXTERNA, Área de Componente Projetada (Bruta) (m2) = GENÉRICO - VEDAÇÃO EXTERNA, Área de Componente Projetada (Condicional) (m2) | NetSideArea (m2) = Área da Superfície (m2) = Área da Superfície da Base (Líquida) (m2) = Área da Superfície da Face Interna da Parede (Líquida) (m2) = Área da Superfície da Face Externa da Parede (Líquida) (m2) = GENÉRICO - VEDAÇÃO EXTERNA, Área de Componente Projetada (Líquida) (m2) | GrossVolume (m3) = Volume (Condicional) (m3) = GENÉRICO - VEDAÇÃO EXTERNA, Volume do componente (Bruto) (m3) = GENÉRICO - VEDAÇÃO EXTERNA, Volume Componente (Condicional) (m3) | NetVolume (m3) = Volume (Líquido) (m3) = GENÉRICO - VEDAÇÃO EXTERNA, Volume Componente (Líquido) (m3) | Altura (mm) = GENÉRICO - VEDAÇÃO EXTERNA, Altura do Componente Retangular (mm) | Elevação à Origem do Projeto (mm) = Elevação ao 1º Nível de Referência (mm) = Elevação ao 2º Nível de Referência (mm) = Elevação ao Nível do Mar (mm) = Elevação da Base Ao Primeiro Nível de Referência (mm) = Elevação da Base À Cota Zero (mm) = Elevação da Base Ao Nível do Mar (mm) = Elevação da Base Ao Segundo Nível de Referência (mm) | Afastamento do Topo (mm) | Volume (Bruto) (m3) | Perímetro na Planta (mm) | Elevação do Topo ao Primeiro Nível de Referência (mm) = Elevação do Topo À Cota Zero (mm) = Elevação do Topo Ao Nível do Mar (mm) = Elevação do Topo Ao Segundo Nível de Referência (mm) | Área da Superfície da Borda (Líquida) (m2) = Área da Superfície da Face (Geral) (m2) | Número de Portas | Altura mínima da parede (mm) | Área das Portas (m2) | Soma das Larguras das Portas (mm) | Área Analítica da Superfície das Aberturas da Face Interna (m2) | Área Analítica da Superfície das Aberturas da Face Externa (m2) | Volume Analítico das Aberturas (m3) | Comprimento da Linha de Referência (mm) | Comprimento da Face Interna da Parede (Condicional) (mm) = Comprimento da Face Externa da Parede (Condicional) (mm) | Área da Superfície da Face Interna da Parede (Bruta) (m2) = Área da Superfície da Face Externa da Parede (Bruta) (m2) | GENÉRICO - VEDAÇÃO EXTERNA, Massa (kg) | GENÉRICO - VEDAÇÃO EXTERNA, Área de Seção Transversal do Componente (m2)
APTO6-PAREDE-011 | Segundo Pavimento | Parede -011 | 46.656 (kgCO₂) | 583.2 | 1350 | 2500 | 0.054 | 3.375 | 3.375 | 0.135 | 0.135 | 2650 | 2650 | 0 | 0.17278 | 2780 | 5150 | 0.054 | 0 | 0 | 0 | 0 | 0 | 0 | 0 | 1440 | 1350 | 4.3195 | 129.6 | 0.106
APTO6-PAREDE-005 | Segundo Pavimento | Parede -005 | 117.62 (kgCO₂) | 1470.25 | 3465 | 2500 | 0.1386 | 8.50837 | 8.50837 | 0.340335 | 0.340335 | 2620 | 2650 | -30 | 0.363132 | 7010 | 5150 | 0.2974 | 0 | 3.55271e-12 | 0 | 0 | 1.24345e-14 | 1.42109e-14 | 4.996e-16 | 3465 | 3465 | 9.0783 | 326.721 | 0.1048
APTO6-PAREDE-010 | Segundo Pavimento | Parede -010 | 46.656 (kgCO₂) | 583.2 | 1350 | 2500 | 0.054 | 3.375 | 3.375 | 0.135 | 0.135 | 2650 | 2650 | 0 | 0.17278 | 2780 | 5150 | 0.054 | 0 | 0 | 0 | 0 | 0 | 0 | 0 | 1440 | 1350 | 4.3195 | 129.6 | 0.106
APTO6-PAREDE-007 | Segundo Pavimento | Parede -007 | 117.62 (kgCO₂) | 1470.25 | 3465 | 2500 | 0.1386 | 8.50837 | 8.50837 | 0.340335 | 0.340335 | 2650 | 2650 | 0 | 0.36729 | 7010 | 5150 | 0.2974 | 0 | 3.55271e-12 | 0 | 0 | 1.24345e-14 | 1.59872e-14 | -2.22045e-16 | 3465 | 3465 | 9.18225 | 326.721 | 0.106
APTO6-PAREDE-006 | Segundo Pavimento | Parede -006 | 77.3315 (kgCO₂) | 966.644 | 5120 | 2200 | 0.0968001 | 11.264 | 5.594 | 0.45056 | 0.22376 | 2650 | 2650 | 0 | 0.561492 | 10320 | 4850 | 0.1008 | 3 | 0 | 5.67 | 2700 | 5.67 | 5.67 | 0.2268 | 5120 | 2420 | 14.0373 | 214.81 | 0.106
APTO7-PAREDE-003 | Segundo Pavimento | Parede -003 | 127.54 (kgCO₂) | 1594.25 | 3750 | 2500 | 0.15 | 9.226 | 9.226 | 0.36904 | 0.36904 | 2620 | 2650 | -30 | 0.393 | 7580 | 5150 | 0.3212 | 0 | 3.55271e-12 | 0 | 0 | 7.10543e-15 | 5.32907e-15 | 5.55112e-17 | 3750 | 3750 | 9.825 | 354.278 | 0.1048
APTO7-PAREDE-011 | Segundo Pavimento | Parede -011 | 46.656 (kgCO₂) | 583.2 | 1350 | 2500 | 0.054 | 3.375 | 3.375 | 0.135 | 0.135 | 2650 | 2650 | 0 | 0.17278 | 2780 | 5150 | 0.054 | 0 | 0 | 0 | 0 | 0 | 0 | 0 | 1440 | 1350 | 4.3195 | 129.6 | 0.106
APTO7-PAREDE-005 | Segundo Pavimento | Parede -005 | 117.62 (kgCO₂) | 1470.25 | 3465 | 2500 | 0.1386 | 8.50837 | 8.50837 | 0.340335 | 0.340335 | 2620 | 2650 | -30 | 0.363132 | 7010 | 5150 | 0.2974 | 0 | 3.55271e-12 | 0 | 0 | 3.55271e-15 | 5.32907e-15 | -3.88578e-16 | 3465 | 3465 | 9.0783 | 326.721 | 0.1048
APTO7-PAREDE-010 | Segundo Pavimento | Parede -010 | 46.656 (kgCO₂) | 583.2 | 1350 | 2500 | 0.054 | 3.375 | 3.375 | 0.135 | 0.135 | 2650 | 2650 | 0 | 0.17278 | 2780 | 5150 | 0.054 | 0 | 0 | 0 | 0 | 0 | 0 | 0 | 1440 | 1350 | 4.3195 | 129.6 | 0.106
APTO7-PAREDE-007 | Segundo Pavimento | Parede -007 | 117.62 (kgCO₂) | 1470.25 | 3465 | 2500 | 0.1386 | 8.50837 | 8.50837 | 0.340335 | 0.340335 | 2650 | 2650 | 0 | 0.36729 | 7010 | 5150 | 0.2974 | 0 | 3.55271e-12 | 0 | 0 | 7.10543e-15 | 7.10543e-15 | -1.27676e-15 | 3465 | 3465 | 9.18225 | 326.721 | 0.106
APTO7-PAREDE-006 | Segundo Pavimento | Parede -006 | 77.3315 (kgCO₂) | 966.643 | 5120 | 2200 | 0.0968 | 11.264 | 5.594 | 0.45056 | 0.22376 | 2650 | 2650 | 0 | 0.54272 | 10320 | 4850 | 0.1888 | 3 | 2200 | 5.67 | 2700 | 5.67 | 5.67 | 0.2268 | 5120 | 2420 | 13.568 | 214.81 | 0.106
APTO8-PAREDE-003 | Segundo Pavimento | Parede -003 | 127.54 (kgCO₂) | 1594.25 | 3750 | 2500 | 0.15 | 9.226 | 9.226 | 0.36904 | 0.36904 | 2620 | 2650 | -30 | 0.393 | 7580 | 5150 | 0.3212 | 0 | 3.55271e-12 | 0 | 0 | 7.10543e-15 | 8.88178e-15 | 1.11022e-16 | 3750 | 3750 | 9.825 | 354.278 | 0.1048
APTO8-PAREDE-011 | Segundo Pavimento | Parede -011 | 46.656 (kgCO₂) | 583.2 | 1350 | 2500 | 0.054 | 3.375 | 3.375 | 0.135 | 0.135 | 2650 | 2650 | 0 | 0.17278 | 2780 | 5150 | 0.054 | 0 | 0 | 0 | 0 | 0 | 0 | 0 | 1440 | 1350 | 4.3195 | 129.6 | 0.106
APTO8-PAREDE-005 | Segundo Pavimento | Parede -005 | 117.62 (kgCO₂) | 1470.25 | 3465 | 2500 | 0.1386 | 8.50837 | 8.50837 | 0.340335 | 0.340335 | 2620 | 2650 | -30 | 0.363132 | 7010 | 5150 | 0.2974 | 0 | 3.55271e-12 | 0 | 0 | 5.32907e-15 | 5.32907e-15 | -1.66533e-16 | 3465 | 3465 | 9.0783 | 326.721 | 0.1048
APTO8-PAREDE-010 | Segundo Pavimento | Parede -010 | 46.656 (kgCO₂) | 583.2 | 1350 | 2500 | 0.054 | 3.375 | 3.375 | 0.135 | 0.135 | 2650 | 2650 | 0 | 0.17278 | 2780 | 5150 | 0.054 | 0 | 0 | 0 | 0 | 0 | 0 | 0 | 1440 | 1350 | 4.3195 | 129.6 | 0.106
APTO8-PAREDE-007 | Segundo Pavimento | Parede -007 | 117.62 (kgCO₂) | 1470.25 | 3465 | 2500 | 0.1386 | 8.50837 | 8.50837 | 0.340335 | 0.340335 | 2650 | 2650 | 0 | 0.36729 | 7010 | 5150 | 0.2974 | 0 | 3.55271e-12 | 0 | 0 | 7.10543e-15 | 7.10543e-15 | -2.77556e-16 | 3465 | 3465 | 9.18225 | 326.721 | 0.106
APTO8-PAREDE-006 | Segundo Pavimento | Parede -006 | 77.3315 (kgCO₂) | 966.644 | 5120 | 2200 | 0.0968001 | 11.264 | 5.594 | 0.45056 | 0.22376 | 2650 | 2650 | 0 | 0.56172 | 10320 | 4850 | 0.1008 | 3 | 0 | 5.67 | 2700 | 5.67 | 5.67 | 0.2268 | 5120 | 2420 | 14.043 | 214.81 | 0.106
APTO9-PAREDE-003 | Terceiro Pavimento | Parede -003 | 127.54 (kgCO₂) | 1594.25 | 3750 | 2500 | 0.15 | 9.226 | 9.226 | 0.36904 | 0.36904 | 2620 | 5300 | -30 | 0.393 | 7580 | 7800 | 0.3212 | 0 | 4.44089e-12 | 0 | 0 | 1.24345e-14 | 1.24345e-14 | 4.996e-16 | 3750 | 3750 | 9.825 | 354.278 | 0.1048
APTO9-PAREDE-011 | Terceiro Pavimento | Parede -011 | 46.656 (kgCO₂) | 583.2 | 1350 | 2500 | 0.054 | 3.375 | 3.375 | 0.135 | 0.135 | 2650 | 5300 | 0 | 0.17278 | 2780 | 7800 | 0.054 | 0 | 0 | 0 | 0 | 0 | 0 | 0 | 1440 | 1350 | 4.3195 | 129.6 | 0.106
APTO9-PAREDE-005 | Terceiro Pavimento | Parede -005 | 117.62 (kgCO₂) | 1470.25 | 3465 | 2500 | 0.1386 | 8.50837 | 8.50837 | 0.340335 | 0.340335 | 2620 | 5300 | -30 | 0.363132 | 7010 | 7800 | 0.2974 | 0 | 4.44089e-12 | 0 | 0 | 1.06581e-14 | 1.06581e-14 | -5.60663e-15 | 3465 | 3465 | 9.0783 | 326.721 | 0.1048
APTO9-PAREDE-010 | Terceiro Pavimento | Parede -010 | 46.656 (kgCO₂) | 583.2 | 1350 | 2500 | 0.054 | 3.375 | 3.375 | 0.135 | 0.135 | 2650 | 5300 | 0 | 0.17278 | 2780 | 7800 | 0.054 | 0 | 0 | 0 | 0 | 0 | 0 | 0 | 1440 | 1350 | 4.3195 | 129.6 | 0.106
APTO9-PAREDE-007 | Terceiro Pavimento | Parede -007 | 117.62 (kgCO₂) | 1470.25 | 3465 | 2500 | 0.1386 | 8.50837 | 8.50837 | 0.340335 | 0.340335 | 2650 | 5300 | 0 | 0.36729 | 7010 | 7800 | 0.2974 | 0 | 4.44089e-12 | 0 | 0 | 7.10543e-15 | 1.06581e-14 | 3.33067e-16 | 3465 | 3465 | 9.18225 | 326.721 | 0.106
APTO9-PAREDE-006 | Terceiro Pavimento | Parede -006 | 77.3315 (kgCO₂) | 966.643 | 5120 | 2200 | 0.0968 | 11.264 | 5.594 | 0.45056 | 0.22376 | 2650 | 5300 | 0 | 0.54272 | 10320 | 7500 | 0.1888 | 3 | 2200 | 5.67 | 2700 | 5.67 | 5.67 | 0.2268 | 5120 | 2420 | 13.568 | 214.81 | 0.106
APTO10-PAREDE-003 | Terceiro Pavimento | Parede -003 | 127.54 (kgCO₂) | 1594.25 | 3750 | 2500 | 0.15 | 9.226 | 9.226 | 0.36904 | 0.36904 | 2620 | 5300 | -30 | 0.393 | 7580 | 7800 | 0.3212 | 0 | 4.44089e-12 | 0 | 0 | 1.24345e-14 | 1.06581e-14 | 3.88578e-16 | 3750 | 3750 | 9.825 | 354.278 | 0.1048
APTO10-PAREDE-011 | Terceiro Pavimento | Parede -011 | 46.656 (kgCO₂) | 583.2 | 1350 | 2500 | 0.054 | 3.375 | 3.375 | 0.135 | 0.135 | 2650 | 5300 | 0 | 0.17278 | 2780 | 7800 | 0.054 | 0 | 0 | 0 | 0 | 0 | 0 | 0 | 1440 | 1350 | 4.3195 | 129.6 | 0.106
APTO10-PAREDE-005 | Terceiro Pavimento | Parede -005 | 117.62 (kgCO₂) | 1470.25 | 3465 | 2500 | 0.1386 | 8.50837 | 8.50837 | 0.340335 | 0.340335 | 2620 | 5300 | -30 | 0.363132 | 7010 | 7800 | 0.2974 | 0 | 4.44089e-12 | 0 | 0 | 1.24345e-14 | 1.06581e-14 | 1.22125e-15 | 3465 | 3465 | 9.0783 | 326.721 | 0.1048
APTO10-PAREDE-010 | Terceiro Pavimento | Parede -010 | 46.656 (kgCO₂) | 583.2 | 1350 | 2500 | 0.054 | 3.375 | 3.375 | 0.135 | 0.135 | 2650 | 5300 | 0 | 0.17278 | 2780 | 7800 | 0.054 | 0 | 0 | 0 | 0 | 0 | 0 | 0 | 1440 | 1350 | 4.3195 | 129.6 | 0.106
APTO10-PAREDE-007 | Terceiro Pavimento | Parede -007 | 117.62 (kgCO₂) | 1470.25 | 3465 | 2500 | 0.1386 | 8.50837 | 8.50837 | 0.340335 | 0.340335 | 2650 | 5300 | 0 | 0.36729 | 7010 | 7800 | 0.2974 | 0 | 4.44089e-12 | 0 | 0 | 1.24345e-14 | 1.06581e-14 | 1.09357e-14 | 3465 | 3465 | 9.18225 | 326.721 | 0.106
APTO10-PAREDE-006 | Terceiro Pavimento | Parede -006 | 77.3315 (kgCO₂) | 966.644 | 5120 | 2200 | 0.0968001 | 11.264 | 5.594 | 0.45056 | 0.22376 | 2650 | 5300 | 0 | 0.561492 | 10320 | 7500 | 0.1008 | 3 | 0 | 5.67 | 2700 | 5.67 | 5.67 | 0.2268 | 5120 | 2420 | 14.0373 | 214.81 | 0.106
APTO11-PAREDE-003 | Terceiro Pavimento | Parede -003 | 127.54 (kgCO₂) | 1594.25 | 3750 | 2500 | 0.15 | 9.226 | 9.226 | 0.36904 | 0.36904 | 2620 | 5300 | -30 | 0.393 | 7580 | 7800 | 0.3212 | 0 | 4.44089e-12 | 0 | 0 | 3.55271e-15 | 3.55271e-15 | 1.11022e-16 | 3750 | 3750 | 9.825 | 354.278 | 0.1048
APTO11-PAREDE-011 | Terceiro Pavimento | Parede -011 | 46.656 (kgCO₂) | 583.2 | 1350 | 2500 | 0.054 | 3.375 | 3.375 | 0.135 | 0.135 | 2650 | 5300 | 0 | 0.17278 | 2780 | 7800 | 0.054 | 0 | 0 | 0 | 0 | 0 | 0 | 0 | 1440 | 1350 | 4.3195 | 129.6 | 0.106
APTO11-PAREDE-005 | Terceiro Pavimento | Parede -005 | 117.62 (kgCO₂) | 1470.25 | 3465 | 2620 | 0.1386 | 8.50841 | 8.50841 | 0.340336 | 0.340336 | 2620 | 5300 | -30 | 0.363132 | 7010 | 7920 | 0.302214 | 0 | 4.44089e-12 | 0 | 0 | 5.32907e-15 | 3.55271e-15 | 8.32667e-16 | 3465 | 3465 | 9.0783 | 326.723 | 0.1048
APTO11-PAREDE-010 | Terceiro Pavimento | Parede -010 | 46.656 (kgCO₂) | 583.2 | 1350 | 2500 | 0.054 | 3.375 | 3.375 | 0.135 | 0.135 | 2650 | 5300 | 0 | 0.17278 | 2780 | 7800 | 0.054 | 0 | 0 | 0 | 0 | 0 | 0 | 0 | 1440 | 1350 | 4.3195 | 129.6 | 0.106
APTO11-PAREDE-007 | Terceiro Pavimento | Parede -007 | 117.622 (kgCO₂) | 1470.27 | 3465 | 2650 | 0.1386 | 8.50853 | 8.50853 | 0.340341 | 0.340341 | 2650 | 5300 | 0 | 0.36729 | 7010 | 7950 | 0.303443 | 0 | 4.44089e-12 | 0 | 0 | 3.55271e-15 | 5.32907e-15 | 3.33067e-16 | 3465 | 3465 | 9.18225 | 326.727 | 0.106
APTO11-PAREDE-006 | Terceiro Pavimento | Parede -006 | 77.3315 (kgCO₂) | 966.643 | 5120 | 2200 | 0.0968 | 11.264 | 5.594 | 0.45056 | 0.22376 | 2650 | 5300 | 0 | 0.54272 | 10320 | 7500 | 0.1888 | 3 | 2200 | 5.67 | 2700 | 5.67 | 5.67 | 0.2268 | 5120 | 2420 | 13.568 | 214.81 | 0.106
APTO12-PAREDE-003 | Terceiro Pavimento | Parede -003 | 127.54 (kgCO₂) | 1594.25 | 3750 | 2500 | 0.15 | 9.226 | 9.226 | 0.36904 | 0.36904 | 2620 | 5300 | -30 | 0.393 | 7580 | 7800 | 0.3212 | 0 | 4.44089e-12 | 0 | 0 | 5.32907e-15 | 5.32907e-15 | 0 | 3750 | 3750 | 9.825 | 354.278 | 0.1048
APTO12-PAREDE-011 | Terceiro Pavimento | Parede -011 | 46.656 (kgCO₂) | 583.2 | 1350 | 2500 | 0.054 | 3.375 | 3.375 | 0.135 | 0.135 | 2650 | 5300 | 0 | 0.17278 | 2780 | 7800 | 0.054 | 0 | 0 | 0 | 0 | 0 | 0 | 0 | 1440 | 1350 | 4.3195 | 129.6 | 0.106
APTO12-PAREDE-005 | Terceiro Pavimento | Parede -005 | 117.62 (kgCO₂) | 1470.25 | 3465 | 2500 | 0.1386 | 8.50837 | 8.50837 | 0.340335 | 0.340335 | 2620 | 5300 | -30 | 0.363132 | 7010 | 7800 | 0.2974 | 0 | 4.44089e-12 | 0 | 0 | 3.55271e-15 | 3.55271e-15 | -2.77556e-16 | 3465 | 3465 | 9.0783 | 326.721 | 0.1048
APTO12-PAREDE-010 | Terceiro Pavimento | Parede -010 | 46.656 (kgCO₂) | 583.2 | 1350 | 2500 | 0.054 | 3.375 | 3.375 | 0.135 | 0.135 | 2650 | 5300 | 0 | 0.17278 | 2780 | 7800 | 0.054 | 0 | 0 | 0 | 0 | 0 | 0 | 0 | 1440 | 1350 | 4.3195 | 129.6 | 0.106
APTO12-PAREDE-007 | Terceiro Pavimento | Parede -007 | 117.62 (kgCO₂) | 1470.25 | 3465 | 2500 | 0.1386 | 8.50837 | 8.50837 | 0.340335 | 0.340335 | 2650 | 5300 | 0 | 0.36729 | 7010 | 7800 | 0.2974 | 0 | 4.44089e-12 | 0 | 0 | 3.55271e-15 | 3.55271e-15 | -3.33067e-16 | 3465 | 3465 | 9.18225 | 326.721 | 0.106
APTO12-PAREDE-006 | Terceiro Pavimento | Parede -006 | 77.3315 (kgCO₂) | 966.644 | 5120 | 2200 | 0.0968001 | 11.264 | 5.594 | 0.45056 | 0.22376 | 2650 | 5300 | 0 | 0.56172 | 10320 | 7500 | 0.1008 | 3 | 0 | 5.67 | 2700 | 5.67 | 5.67 | 0.2268 | 5120 | 2420 | 14.043 | 214.81 | 0.106

# IfcWallStandardCase: GENÉRICO - VEDAÇÃO EXTERNA 75 (10)
Classification: Parede (Classificação ARCHICAD); 3E 08 04 10 Guarda-corpo (NBR 15965-5 3E); Material: GENÉRICO - VEDAÇÃO EXTERNA 75 mm
Pset_WallCommon - AcousticRating: 0,00; IsExternal: yes
CLASSIFICAÇÕES GERAIS - Transmissão Sonora: 0
SUPERFÍCIES (Mapas) - Superfície da Face (Geral): Pintura - Sienna Areia
AC_Pset_RenovationAndPhasing - Renovation Status: Existing
Component Properties - GENÉRICO - VEDAÇÃO EXTERNA, Tipo de Componente: Nenhum
BaseQuantities - Height: 1050 mm; Width: 75 mm
ArchiCADQuantities - Altura: 1050 mm; Largura: 75 mm; Espessura: 75 mm; Espessura da Camada de Isolamento: 0 mm; Número de Portas: 0; Número de Furos (Número de Aberturas Vazias): 0; Número de Janelas: 0; Número de Pilares: 0; Volume dos Pilares: 0 m3; Altura Máxima da Camada da Parede na Face Interna: 0 mm; Altura Mínima da Camada da Parede na Face Interna: 0 mm; Altura máxima da parede: 1050 mm; Altura Máxima da Camada da Parede na Face Externa: 0 mm; Altura Mínima da Camada da Parede na Face Externa: 0 mm; Espessura da Camada de Ar: 0 mm; Área das Portas: 0 m2; Soma das Larguras das Portas: 0 mm; Espessura do Componente na Face Interna da Parede: 0 mm; Espessura do Componentena na Face Externa da Parede: 0 mm; Área das Janelas: 0 m2; Soma das Larguras das Janelas: 0 mm; Área Analítica da Superfície das Aberturas da Face Interna: 0 m2; Área Analítica da Superfície das Aberturas da Face Externa: 0 m2; Volume Analítico das Aberturas: 0 m3; Espessura da Parede na Terminação: 75 mm; Área de Superfície do Vão na Parede: 0 m2
ALVENARIAS (Expressão) - Espessura da Argamassa: 10 mm
Component Quantities - GENÉRICO - VEDAÇÃO EXTERNA, Espessura do Componente: 75 mm; GENÉRICO - VEDAÇÃO EXTERNA, Altura do Componente Retangular: 1050 mm; GENÉRICO - VEDAÇÃO EXTERNA, Largura do Componente Retangular: 75 mm; GENÉRICO - VEDAÇÃO EXTERNA, Área de Seção Transversal do Componente: 0.07875 m2
Name | In | ID Dinâmico por Classificação | GENÉRICO - VEDAÇÃO EXTERNA, Carbono Incorporado | GENÉRICO - VEDAÇÃO EXTERNA, Energia Incorporada (MJ) | Length (mm) = Comprimento 3D (mm) = Comprimento Médio da Parede (mm) = Comprimento da Linha de Referência (mm) = Comprimento da Face Interna da Parede (Condicional) (mm) = Comprimento da Face Externa da Parede (Condicional) (mm) = Comprimento da parede no centro (mm) = Comprimento da Parede na Face Interna (mm) = Comprimento da Parede na Face Externa (mm) | GrossFootprintArea (m2) = NetFootprintArea (m2) = Área (m2) = Área da Superfície do Topo (Líquida) (m2) | GrossSideArea (m2) = NetSideArea (m2) = Área da Superfície (m2) = Área da Superfície da Base (Líquida) (m2) = Área da Superfície da Face Interna da Parede (Líquida) (m2) = Área da Superfície da Face Externa da Parede (Líquida) (m2) = Área da Superfície da Face Interna da Parede (Condicional) (m2) = Área da Superfície da Face Externa da Parede (Condicional) (m2) = GENÉRICO - VEDAÇÃO EXTERNA, Área de Componente Projetada (Líquida) (m2) = GENÉRICO - VEDAÇÃO EXTERNA, Área de Componente Projetada (Bruta) (m2) = GENÉRICO - VEDAÇÃO EXTERNA, Área de Componente Projetada (Condicional) (m2) | GrossVolume (m3) = NetVolume (m3) = Volume (Líquido) (m3) = Volume (Condicional) (m3) = GENÉRICO - VEDAÇÃO EXTERNA, Volume Componente (Líquido) (m3) = GENÉRICO - VEDAÇÃO EXTERNA, Volume do componente (Bruto) (m3) = GENÉRICO - VEDAÇÃO EXTERNA, Volume Componente (Condicional) (m3) | Elevação à Origem do Projeto (mm) = Elevação ao 1º Nível de Referência (mm) = Elevação ao 2º Nível de Referência (mm) = Elevação ao Nível do Mar (mm) = Elevação da Base Ao Primeiro Nível de Referência (mm) = Elevação da Base À Cota Zero (mm) = Elevação da Base Ao Nível do Mar (mm) = Elevação da Base Ao Segundo Nível de Referência (mm) | Elevação ao Piso (mm) = Afastamento da Origem (mm) = Elevação da Base Ao Piso de Origem (mm) | Afastamento do Topo (mm) | Volume (Bruto) (m3) | Perímetro na Planta (mm) | Elevação do Topo ao Primeiro Nível de Referência (mm) = Elevação do Topo À Cota Zero (mm) = Elevação do Topo Ao Nível do Mar (mm) = Elevação do Topo Ao Segundo Nível de Referência (mm) | Elevação do Topo Ao Piso de Origem (mm) | Área da Superfície da Borda (Líquida) (m2) = Área da Superfície da Face (Geral) (m2) | Altura mínima da parede (mm) | Área da Superfície da Face Interna da Parede (Bruta) (m2) = Área da Superfície da Face Externa da Parede (Bruta) (m2) | GENÉRICO - VEDAÇÃO EXTERNA, Massa (kg)
CIRC1-PAREDE-027 | Primeiro Pavimento | Parede -027 | 262.09 (kgCO₂) | 3276.13 | 9630 | 0.72225 | 10.1115 | 0.758363 | -50 | -50 | -1650 | 0.758363 | 19410 | 1000 | 1000 | 1.602 | 1050 | 10.1115 | 728.028
CIRC1-PAREDE-025 | Primeiro Pavimento | Parede -025 | 66.8153 (kgCO₂) | 835.191 | 2455 | 0.184125 | 2.57775 | 0.193331 | -50 | -50 | -1650 | 0.193331 | 5060 | 1000 | 1000 | 0.52575 | 1050 | 2.57775 | 185.598
CIRC1-PAREDE-028 | Primeiro Pavimento | Parede -028 | 66.8153 (kgCO₂) | 835.191 | 2455 | 0.184125 | 2.57775 | 0.193331 | -50 | -50 | -1650 | 0.208294 | 5060 | 1000 | 1000 | 0.447 | 0 | 2.77725 | 185.598
PAREDE-040 | Segundo Pavimento | Parede -040 | 30.4819 (kgCO₂) | 381.024 | 1120 | 0.084 | 1.176 | 0.0882 | 5250 | 2600 | 0 | 0.103163 | 2390 | 6300 | 3650 | 0.24675 | 0 | 1.3755 | 84.672
CIRC2-PAREDE-027 | Segundo Pavimento | Parede -027 | 262.09 (kgCO₂) | 3276.13 | 9630 | 0.72225 | 10.1115 | 0.758363 | 2600 | -50 | -1650 | 0.758363 | 19410 | 3650 | 1000 | 1.602 | 1050 | 10.1115 | 728.028
CIRC2-PAREDE-028 | Segundo Pavimento | Parede -028 | 66.8153 (kgCO₂) | 835.191 | 2455 | 0.184125 | 2.57775 | 0.193331 | 2600 | -50 | -1650 | 0.208294 | 5060 | 3650 | 1000 | 0.447 | 0 | 2.77725 | 185.598
CIRC2-PAREDE-025 | Segundo Pavimento | Parede -025 | 66.8153 (kgCO₂) | 835.191 | 2455 | 0.184125 | 2.57775 | 0.193331 | 2600 | -50 | -1650 | 0.193331 | 5060 | 3650 | 1000 | 0.52575 | 1050 | 2.57775 | 185.598
CIRC3-PAREDE-036 | Terceiro Pavimento | Parede -036 | 262.09 (kgCO₂) | 3276.13 | 9630 | 0.72225 | 10.1115 | 0.758363 | 5250 | -50 | -1650 | 0.758363 | 19410 | 6300 | 1000 | 1.602 | 1050 | 10.1115 | 728.028
CIRC3-PAREDE-035 | Terceiro Pavimento | Parede -035 | 66.8153 (kgCO₂) | 835.191 | 2455 | 0.184125 | 2.57775 | 0.193331 | 5250 | -50 | -1650 | 0.193331 | 5060 | 6300 | 1000 | 0.52575 | 1050 | 2.57775 | 185.598
CIRC3-PAREDE-037 | Terceiro Pavimento | Parede -037 | 66.8153 (kgCO₂) | 835.191 | 2455 | 0.184125 | 2.57775 | 0.193331 | 5250 | -50 | -1650 | 0.208294 | 5060 | 6300 | 1000 | 0.447 | 0 | 2.77725 | 185.598

# IfcWallStandardCase: GENÉRICO - VEDAÇÃO EXTERNA 90 (36)
Classification: Parede (Classificação ARCHICAD); 3E 14 02 00 Parede (NBR 15965-5 3E); Material: GENÉRICO - VEDAÇÃO EXTERNA 90 mm
Pset_WallCommon - AcousticRating: 0,00
CLASSIFICAÇÕES GERAIS - Transmissão Sonora: 0
SUPERFÍCIES (Mapas) - Superfície da Face (Geral): Pintura - Sienna Areia
AC_Pset_RenovationAndPhasing - Renovation Status: Existing
Component Properties - GENÉRICO - VEDAÇÃO EXTERNA, Tipo de Componente: Nenhum
BaseQuantities - Width: 90 mm
ArchiCADQuantities - Largura: 90 mm; Elevação ao Piso: 0 mm; Afastamento da Origem: 0 mm; Espessura: 90 mm; Espessura da Camada de Isolamento: 0 mm; Elevação da Base Ao Piso de Origem: 0 mm; Número de Furos (Número de Aberturas Vazias): 0; Número de Janelas: 0; Número de Pilares: 0; Volume dos Pilares: 0 m3; Altura Máxima da Camada da Parede na Face Interna: 0 mm; Altura Mínima da Camada da Parede na Face Interna: 0 mm; Altura Máxima da Camada da Parede na Face Externa: 0 mm; Altura Mínima da Camada da Parede na Face Externa: 0 mm; Espessura da Camada de Ar: 0 mm; Espessura do Componente na Face Interna da Parede: 0 mm; Espessura do Componentena na Face Externa da Parede: 0 mm; Área das Janelas: 0 m2; Soma das Larguras das Janelas: 0 mm; Espessura da Parede na Terminação: 90 mm; Área de Superfície do Vão na Parede: 0 m2
ALVENARIAS (Expressão) - Espessura da Argamassa: 10 mm
Component Quantities - GENÉRICO - VEDAÇÃO EXTERNA, Espessura do Componente: 90 mm; GENÉRICO - VEDAÇÃO EXTERNA, Largura do Componente Retangular: 90 mm
Name | In | IsExternal | ID Dinâmico por Classificação | GENÉRICO - VEDAÇÃO EXTERNA, Carbono Incorporado | GENÉRICO - VEDAÇÃO EXTERNA, Energia Incorporada (MJ) | Length (mm) = Comprimento 3D (mm) = Comprimento Médio da Parede (mm) = Comprimento da Linha de Referência (mm) = Comprimento da parede no centro (mm) = Comprimento da Parede na Face Interna (mm) = Comprimento da Parede na Face Externa (mm) | Height (mm) = Elevação do Topo Ao Piso de Origem (mm) = Altura máxima da parede (mm) | GrossFootprintArea (m2) = NetFootprintArea (m2) = Área (m2) = Área da Superfície do Topo (Líquida) (m2) | GrossSideArea (m2) = Área da Superfície da Face Interna da Parede (Condicional) (m2) = Área da Superfície da Face Externa da Parede (Condicional) (m2) = GENÉRICO - VEDAÇÃO EXTERNA, Área de Componente Projetada (Bruta) (m2) = GENÉRICO - VEDAÇÃO EXTERNA, Área de Componente Projetada (Condicional) (m2) | NetSideArea (m2) = Área da Superfície (m2) = Área da Superfície da Base (Líquida) (m2) = Área da Superfície da Face Interna da Parede (Líquida) (m2) = Área da Superfície da Face Externa da Parede (Líquida) (m2) = GENÉRICO - VEDAÇÃO EXTERNA, Área de Componente Projetada (Líquida) (m2) | GrossVolume (m3) = Volume (Condicional) (m3) = GENÉRICO - VEDAÇÃO EXTERNA, Volume do componente (Bruto) (m3) = GENÉRICO - VEDAÇÃO EXTERNA, Volume Componente (Condicional) (m3) | NetVolume (m3) = Volume (Líquido) (m3) = GENÉRICO - VEDAÇÃO EXTERNA, Volume Componente (Líquido) (m3) | Altura (mm) = GENÉRICO - VEDAÇÃO EXTERNA, Altura do Componente Retangular (mm) | Elevação à Origem do Projeto (mm) = Elevação ao 1º Nível de Referência (mm) = Elevação ao 2º Nível de Referência (mm) = Elevação ao Nível do Mar (mm) = Elevação da Base Ao Primeiro Nível de Referência (mm) = Elevação da Base À Cota Zero (mm) = Elevação da Base Ao Nível do Mar (mm) = Elevação da Base Ao Segundo Nível de Referência (mm) | Afastamento do Topo (mm) | Volume (Bruto) (m3) | Perímetro na Planta (mm) | Elevação do Topo ao Primeiro Nível de Referência (mm) = Elevação do Topo À Cota Zero (mm) = Elevação do Topo Ao Nível do Mar (mm) = Elevação do Topo Ao Segundo Nível de Referência (mm) | Área da Superfície da Borda (Líquida) (m2) = Área da Superfície da Face (Geral) (m2) | Número de Portas | Altura mínima da parede (mm) | Área das Portas (m2) | Soma das Larguras das Portas (mm) | Área Analítica da Superfície das Aberturas da Face Interna (m2) | Área Analítica da Superfície das Aberturas da Face Externa (m2) | Volume Analítico das Aberturas (m3) | Comprimento da Face Interna da Parede (Condicional) (mm) = Comprimento da Face Externa da Parede (Condicional) (mm) | Área da Superfície da Face Interna da Parede (Bruta) (m2) = Área da Superfície da Face Externa da Parede (Bruta) (m2) | GENÉRICO - VEDAÇÃO EXTERNA, Massa (kg) | GENÉRICO - VEDAÇÃO EXTERNA, Área de Seção Transversal do Componente (m2)
APTO4-PAREDE-012 | Primeiro Pavimento | no | Parede -012 | 229.485 (kgCO₂) | 2868.57 | 3580 | 2500 | 0.2583 | 8.869 | 7.378 | 0.79821 | 0.66402 | 2500 | 0 | -150 | 0.82575 | 7340 | 2500 | 0.7812 | 1 | 2100 | 1.491 | 710 | 1.491 | 1.491 | 0.13419 | 2870 | 9.175 | 637.459 | 0.225
APTO4-PAREDE-014 | Primeiro Pavimento | yes | Parede -014 | 622.08 (kgCO₂) | 7776 | 8000 | 2500 | 0.72 | 20 | 20 | 1.8 | 1.8 | 2650 | 0 | 0 | 1.908 | 16180 | 2500 | 1.17 | 0 | 2500 | 0 | 0 | 0 | 0 | 0 | 8000 | 21.2 | 1728 | 0.2385
APTO4-PAREDE-019 | Primeiro Pavimento | no | Parede -019 | 128.646 (kgCO₂) | 1608.08 | 1880 | 2200 | 0.1692 | 4.136 | 4.136 | 0.37224 | 0.37224 | 2650 | 0 | 0 | 0.493695 | 3940 | 2200 | 0.3672 | 0 | 0 | 0 | 0 | 0 | 0 | 0 | 1880 | 5.4855 | 357.35 | 0.2385
APTO2-PAREDE-019 | Primeiro Pavimento | no | Parede -019 | 128.646 (kgCO₂) | 1608.08 | 1880 | 2200 | 0.1692 | 4.136 | 4.136 | 0.37224 | 0.37224 | 2650 | 0 | 0 | 0.493695 | 3940 | 2200 | 0.3672 | 0 | 0 | 0 | 0 | 1.77636e-15 | 1.77636e-15 | 1.11022e-16 | 1880 | 5.4855 | 357.35 | 0.2385
APTO2-PAREDE-014 | Primeiro Pavimento | yes | Parede -014 | 622.08 (kgCO₂) | 7776 | 8000 | 2500 | 0.72 | 20 | 20 | 1.8 | 1.8 | 2650 | 0 | 0 | 1.908 | 16180 | 2500 | 1.17 | 0 | 2500 | 0 | 0 | 0 | 0 | 0 | 8000 | 21.2 | 1728 | 0.2385
APTO2-PAREDE-012 | Primeiro Pavimento | no | Parede -012 | 229.485 (kgCO₂) | 2868.57 | 3580 | 2500 | 0.2583 | 8.869 | 7.378 | 0.79821 | 0.66402 | 2500 | 0 | -150 | 0.82575 | 7340 | 2500 | 0.7812 | 1 | 2100 | 1.491 | 710 | 1.491 | 1.491 | 0.13419 | 2870 | 9.175 | 637.459 | 0.225
APTO3-PAREDE-019 | Primeiro Pavimento | no | Parede -019 | 128.646 (kgCO₂) | 1608.08 | 1880 | 2200 | 0.1692 | 4.136 | 4.136 | 0.37224 | 0.37224 | 2650 | 0 | 0 | 0.493695 | 3940 | 2200 | 0.3672 | 0 | 0 | 0 | 0 | 0 | 0 | 0 | 1880 | 5.4855 | 357.35 | 0.2385
APTO3-PAREDE-014 | Primeiro Pavimento | yes | Parede -014 | 622.08 (kgCO₂) | 7776 | 8000 | 2500 | 0.72 | 20 | 20 | 1.8 | 1.8 | 2650 | 0 | 0 | 1.908 | 16180 | 2500 | 1.17 | 0 | 2500 | 0 | 0 | 0 | 0 | 0 | 8000 | 21.2 | 1728 | 0.2385
APTO3-PAREDE-012 | Primeiro Pavimento | no | Parede -012 | 229.485 (kgCO₂) | 2868.57 | 3580 | 2500 | 0.2583 | 8.869 | 7.378 | 0.79821 | 0.66402 | 2500 | 0 | -150 | 0.82575 | 7340 | 2500 | 0.7812 | 1 | 2100 | 1.491 | 710 | 1.491 | 1.491 | 0.13419 | 2870 | 9.175 | 637.459 | 0.225
APTO1-PAREDE-012 | Primeiro Pavimento | no | Parede -012 | 229.485 (kgCO₂) | 2868.57 | 3580 | 2500 | 0.2583 | 8.869 | 7.378 | 0.79821 | 0.66402 | 2500 | 0 | -150 | 0.82575 | 7340 | 2500 | 0.7812 | 1 | 2100 | 1.491 | 710 | 1.491 | 1.491 | 0.13419 | 2870 | 9.175 | 637.459 | 0.225
APTO1-PAREDE-014 | Primeiro Pavimento | yes | Parede -014 | 622.08 (kgCO₂) | 7776 | 8000 | 2500 | 0.72 | 20 | 20 | 1.8 | 1.8 | 2650 | 0 | 0 | 1.908 | 16180 | 2500 | 1.17 | 0 | 2500 | 0 | 0 | 0 | 0 | 0 | 8000 | 21.2 | 1728 | 0.2385
APTO1-PAREDE-019 | Primeiro Pavimento | no | Parede -019 | 128.646 (kgCO₂) | 1608.08 | 1880 | 2200 | 0.1692 | 4.136 | 4.136 | 0.37224 | 0.37224 | 2650 | 0 | 0 | 0.493695 | 3940 | 2200 | 0.3672 | 0 | 0 | 0 | 0 | 1.77636e-15 | 3.55271e-15 | 1.66533e-16 | 1880 | 5.4855 | 357.35 | 0.2385
APTO5-PAREDE-019 | Segundo Pavimento | no | Parede -019 | 128.646 (kgCO₂) | 1608.08 | 1880 | 2200 | 0.1692 | 4.136 | 4.136 | 0.37224 | 0.37224 | 2650 | 2650 | 0 | 0.493695 | 3940 | 4850 | 0.3672 | 0 | 0 | 0 | 0 | 8.88178e-16 | 2.66454e-15 | 1.66533e-16 | 1880 | 5.4855 | 357.35 | 0.2385
APTO5-PAREDE-014 | Segundo Pavimento | yes | Parede -014 | 622.08 (kgCO₂) | 7776 | 8000 | 2500 | 0.72 | 20 | 20 | 1.8 | 1.8 | 2650 | 2650 | 0 | 1.908 | 16180 | 5150 | 1.17 | 0 | 2500 | 0 | 0 | 0 | 0 | 0 | 8000 | 21.2 | 1728 | 0.2385
APTO5-PAREDE-012 | Segundo Pavimento | no | Parede -012 | 229.485 (kgCO₂) | 2868.57 | 3580 | 2500 | 0.2583 | 8.869 | 7.378 | 0.79821 | 0.66402 | 2500 | 2650 | -150 | 0.82575 | 7340 | 5150 | 0.7812 | 1 | 2100 | 1.491 | 710 | 1.491 | 1.491 | 0.13419 | 2870 | 9.175 | 637.459 | 0.225
APTO6-PAREDE-019 | Segundo Pavimento | no | Parede -019 | 128.646 (kgCO₂) | 1608.08 | 1880 | 2200 | 0.1692 | 4.136 | 4.136 | 0.37224 | 0.37224 | 2650 | 2650 | 0 | 0.493695 | 3940 | 4850 | 0.3672 | 0 | 0 | 0 | 0 | 4.44089e-15 | 8.88178e-16 | 1.66533e-16 | 1880 | 5.4855 | 357.35 | 0.2385
APTO6-PAREDE-014 | Segundo Pavimento | yes | Parede -014 | 622.08 (kgCO₂) | 7776 | 8000 | 2500 | 0.72 | 20 | 20 | 1.8 | 1.8 | 2650 | 2650 | 0 | 1.908 | 16180 | 5150 | 1.17 | 0 | 2500 | 0 | 0 | 0 | 0 | 0 | 8000 | 21.2 | 1728 | 0.2385
APTO6-PAREDE-012 | Segundo Pavimento | no | Parede -012 | 229.485 (kgCO₂) | 2868.57 | 3580 | 2500 | 0.2583 | 8.869 | 7.378 | 0.79821 | 0.66402 | 2500 | 2650 | -150 | 0.82575 | 7340 | 5150 | 0.7812 | 1 | 2100 | 1.491 | 710 | 1.491 | 1.491 | 0.13419 | 2870 | 9.175 | 637.459 | 0.225
APTO7-PAREDE-019 | Segundo Pavimento | no | Parede -019 | 128.646 (kgCO₂) | 1608.08 | 1880 | 2200 | 0.1692 | 4.136 | 4.136 | 0.37224 | 0.37224 | 2650 | 2650 | 0 | 0.493695 | 3940 | 4850 | 0.3672 | 0 | 0 | 0 | 0 | 0 | 0 | 0 | 1880 | 5.4855 | 357.35 | 0.2385
APTO7-PAREDE-014 | Segundo Pavimento | yes | Parede -014 | 622.08 (kgCO₂) | 7776 | 8000 | 2500 | 0.72 | 20 | 20 | 1.8 | 1.8 | 2650 | 2650 | 0 | 1.908 | 16180 | 5150 | 1.17 | 0 | 2500 | 0 | 0 | 0 | 0 | 0 | 8000 | 21.2 | 1728 | 0.2385
APTO7-PAREDE-012 | Segundo Pavimento | no | Parede -012 | 229.485 (kgCO₂) | 2868.57 | 3580 | 2500 | 0.2583 | 8.869 | 7.378 | 0.79821 | 0.66402 | 2500 | 2650 | -150 | 0.82575 | 7340 | 5150 | 0.7812 | 1 | 2100 | 1.491 | 710 | 1.491 | 1.491 | 0.13419 | 2870 | 9.175 | 637.459 | 0.225
APTO8-PAREDE-019 | Segundo Pavimento | no | Parede -019 | 128.646 (kgCO₂) | 1608.08 | 1880 | 2200 | 0.1692 | 4.136 | 4.136 | 0.37224 | 0.37224 | 2650 | 2650 | 0 | 0.493695 | 3940 | 4850 | 0.3672 | 0 | 0 | 0 | 0 | 0 | 0 | 0 | 1880 | 5.4855 | 357.35 | 0.2385
APTO8-PAREDE-014 | Segundo Pavimento | yes | Parede -014 | 622.08 (kgCO₂) | 7776 | 8000 | 2500 | 0.72 | 20 | 20 | 1.8 | 1.8 | 2650 | 2650 | 0 | 1.908 | 16180 | 5150 | 1.17 | 0 | 2500 | 0 | 0 | 0 | 0 | 0 | 8000 | 21.2 | 1728 | 0.2385
APTO8-PAREDE-012 | Segundo Pavimento | no | Parede -012 | 229.485 (kgCO₂) | 2868.57 | 3580 | 2500 | 0.2583 | 8.869 | 7.378 | 0.79821 | 0.66402 | 2500 | 2650 | -150 | 0.82575 | 7340 | 5150 | 0.7812 | 1 | 2100 | 1.491 | 710 | 1.491 | 1.491 | 0.13419 | 2870 | 9.175 | 637.459 | 0.225
APTO9-PAREDE-019 | Terceiro Pavimento | no | Parede -019 | 128.646 (kgCO₂) | 1608.08 | 1880 | 2200 | 0.1692 | 4.136 | 4.136 | 0.37224 | 0.37224 | 2650 | 5300 | 0 | 0.493695 | 3940 | 7500 | 0.3672 | 0 | 0 | 0 | 0 | 8.88178e-16 | 2.66454e-15 | 1.11022e-16 | 1880 | 5.4855 | 357.35 | 0.2385
APTO9-PAREDE-014 | Terceiro Pavimento | yes | Parede -014 | 622.243 (kgCO₂) | 7778.04 | 8000 | 2650 | 0.72 | 20.0053 | 20.0053 | 1.80047 | 1.80047 | 2650 | 5300 | 0 | 1.908 | 16180 | 7950 | 1.18665 | 0 | 2500 | 0 | 0 | 0 | 0 | 0 | 8000 | 21.2 | 1728.45 | 0.2385
APTO9-PAREDE-012 | Terceiro Pavimento | no | Parede -012 | 229.485 (kgCO₂) | 2868.57 | 3580 | 2500 | 0.2583 | 8.869 | 7.378 | 0.79821 | 0.66402 | 2500 | 5300 | -150 | 0.82575 | 7340 | 7800 | 0.7812 | 1 | 2100 | 1.491 | 710 | 1.491 | 1.491 | 0.13419 | 2870 | 9.175 | 637.459 | 0.225
APTO10-PAREDE-019 | Terceiro Pavimento | no | Parede -019 | 128.646 (kgCO₂) | 1608.08 | 1880 | 2200 | 0.1692 | 4.136 | 4.136 | 0.37224 | 0.37224 | 2650 | 5300 | 0 | 0.493695 | 3940 | 7500 | 0.3672 | 0 | 0 | 0 | 0 | 8.88178e-16 | 8.88178e-16 | 1.11022e-16 | 1880 | 5.4855 | 357.35 | 0.2385
APTO10-PAREDE-014 | Terceiro Pavimento | yes | Parede -014 | 659.405 (kgCO₂) | 8242.56 | 8000 | 2650 | 0.72 | 21.2 | 21.2 | 1.908 | 1.908 | 2650 | 5300 | 0 | 1.908 | 16180 | 7950 | 1.917 | 0 | 2650 | 0 | 0 | 0 | 0 | 0 | 8000 | 21.2 | 1831.68 | 0.2385
APTO10-PAREDE-012 | Terceiro Pavimento | no | Parede -012 | 229.485 (kgCO₂) | 2868.57 | 3580 | 2500 | 0.2583 | 8.869 | 7.378 | 0.79821 | 0.66402 | 2500 | 5300 | -150 | 0.82575 | 7340 | 7800 | 0.7812 | 1 | 2100 | 1.491 | 710 | 1.491 | 1.491 | 0.13419 | 2870 | 9.175 | 637.459 | 0.225
APTO11-PAREDE-019 | Terceiro Pavimento | no | Parede -019 | 128.646 (kgCO₂) | 1608.08 | 1880 | 2200 | 0.1692 | 4.136 | 4.136 | 0.37224 | 0.37224 | 2650 | 5300 | 0 | 0.493695 | 3940 | 7500 | 0.3672 | 0 | 0 | 0 | 0 | 0 | 0 | 0 | 1880 | 5.4855 | 357.35 | 0.2385
APTO11-PAREDE-014 | Terceiro Pavimento | yes | Parede -014 | 622.08 (kgCO₂) | 7776 | 8000 | 2500 | 0.72 | 20 | 20 | 1.8 | 1.8 | 2650 | 5300 | 0 | 1.908 | 16180 | 7800 | 1.17 | 0 | 2500 | 0 | 0 | 0 | 0 | 0 | 8000 | 21.2 | 1728 | 0.2385
APTO11-PAREDE-012 | Terceiro Pavimento | no | Parede -012 | 229.485 (kgCO₂) | 2868.57 | 3580 | 2500 | 0.2583 | 8.869 | 7.378 | 0.79821 | 0.66402 | 2500 | 5300 | -150 | 0.82575 | 7340 | 7800 | 0.7812 | 1 | 2100 | 1.491 | 710 | 1.491 | 1.491 | 0.13419 | 2870 | 9.175 | 637.459 | 0.225
APTO12-PAREDE-019 | Terceiro Pavimento | no | Parede -019 | 128.646 (kgCO₂) | 1608.08 | 1880 | 2200 | 0.1692 | 4.136 | 4.136 | 0.37224 | 0.37224 | 2650 | 5300 | 0 | 0.493695 | 3940 | 7500 | 0.3672 | 0 | 0 | 0 | 0 | 0 | 0 | 0 | 1880 | 5.4855 | 357.35 | 0.2385
APTO12-PAREDE-014 | Terceiro Pavimento | yes | Parede -014 | 659.405 (kgCO₂) | 8242.56 | 8000 | 2650 | 0.72 | 21.2 | 21.2 | 1.908 | 1.908 | 2650 | 5300 | 0 | 1.908 | 16180 | 7950 | 1.917 | 0 | 2650 | 0 | 0 | 0 | 0 | 0 | 8000 | 21.2 | 1831.68 | 0.2385
APTO12-PAREDE-012 | Terceiro Pavimento | no | Parede -012 | 229.485 (kgCO₂) | 2868.57 | 3580 | 2500 | 0.2583 | 8.869 | 7.378 | 0.79821 | 0.66402 | 2500 | 5300 | -150 | 0.82575 | 7340 | 7800 | 0.7812 | 1 | 2100 | 1.491 | 710 | 1.491 | 1.491 | 0.13419 | 2870 | 9.175 | 637.459 | 0.225

# IfcWindow: Tipo de Parede Cortina (24)
Type - ParameterTakesPrecedence: no; Sizeable: no
Classification: Janela (Classificação ARCHICAD); 3E 20 04 02 06 Janela basculante (NBR 15965-5 3E)
Pset_ManufacturerTypeInformation - ProductionYear: DD/MM/YYYY
INFORMAÇÕES DO PRODUTO - Data de Aquisição: DD/MM/YYYY
FABRICAÇÃO - Data de Fabricação: DD/MM/YYYY; Site do Produto: www.graphisoft.com
GARANTIA - Ínicio da Garantia: DD/MM/YYYY; Fim da Garantia: DD/MM/YYYY
AC_Pset_RenovationAndPhasing - Renovation Status: Existing
Pset_WindowCommon - IsExternal: yes
BaseQuantities - Width: 50 mm; Height: 845 mm
ArchiCADQuantities - Altura: 845 mm; Espessura: 50 mm; Comprimento Total das Estruturas Pertencentes ao Eixo Secundário: 0 mm; Comprimento Total da Estrutura Personalizada: 0 mm; Área Total da Superfície dos painéis de revestimento Leste: 0 m2; Área Total dos Painéis de Revestimento Oeste: 0 m2; Área Total da Superfície dos painéis de revestimento Nordeste: 0 m2; Área Total dos Painéis de Revestimento Noroeste: 0 m2; Área Total da Superfície dos painéis de revestimento Sudeste: 0 m2; Área Total dos Painéis de Revestimento Sudoeste: 0 m2
Name | In | Localização do Produto no Projeto | ID de Aberturas com Master ID | ID Dinâmico por Classificação | GrossArea (m2) = Area (m2) = Área da Superfície (m2) = Área da Superfície da Base (Líquida) (m2) = Área de Superfície Incluindo Contorno (m2) | NetVolume (m3) | Elevação à Origem do Projeto (mm) = Elevação ao 1º Nível de Referência (mm) = Elevação ao 2º Nível de Referência (mm) = Elevação ao Nível do Mar (mm) = Elevação da Base Ao Primeiro Nível de Referência (mm) = Elevação da Base À Cota Zero (mm) = Elevação da Base Ao Nível do Mar (mm) = Elevação da Base Ao Segundo Nível de Referência (mm) | Elevação ao Piso (mm) = Afastamento da Origem (mm) = Elevação da Base Ao Piso de Origem (mm) | Elevação do Topo ao Primeiro Nível de Referência (mm) = Elevação do Topo À Cota Zero (mm) = Elevação do Topo Ao Nível do Mar (mm) = Elevação do Topo Ao Segundo Nível de Referência (mm) | Elevação do Topo Ao Piso de Origem (mm) | Número de Paineis | Comprimento de Estruturas Total (mm) | Área Total da Superfície de Painel (m2) | Comprimento (mm) | Comprimento Total do Contorno da Estrutura (mm) | Comprimento Total das Estruturas Pertencentes ao Eixo Principal (mm) | Área Total dos Painéis de Revestimento Norte (m2) | Área Total dos Painéis de Revestimento Sul (m2)
APTO4-JANELA-001 | Primeiro Pavimento | Projeto: CECAP GuarulhosLocal: Piso: Primeiro Pavimento Cômodo: | APTO4-001 | Janela -001 | 5.915 | 0.29575 | 1355.02 | 1355.02 | 2200.02 | 2200.02 | 11 | 24140 | 5.50517 | 7000 | 15690 | 8450 | 5.50517 | 0
APTO4-JANELA-000 | Primeiro Pavimento | Projeto: CECAP GuarulhosLocal: Piso: Primeiro Pavimento Cômodo: | APTO4-000 | Janela -000 | 4.74045 | 0.237023 | 1355 | 1355 | 2200 | 2200 | 9 | 19670 | 4.41512 | 5610 | 12910 | 6760 | 0 | 4.41512
APTO3-JANELA-001 | Primeiro Pavimento | Projeto: CECAP GuarulhosLocal: Piso: Primeiro Pavimento Cômodo: | APTO3-001 | Janela -001 | 5.915 | 0.29575 | 1355.02 | 1355.02 | 2200.02 | 2200.02 | 11 | 24140 | 5.50517 | 7000 | 15690 | 8450 | 5.50517 | 0
APTO2-JANELA-000 | Primeiro Pavimento | Projeto: CECAP GuarulhosLocal: Piso: Primeiro Pavimento Cômodo: | APTO2-000 | Janela -000 | 4.74045 | 0.237023 | 1355 | 1355 | 2200 | 2200 | 9 | 19670 | 4.41512 | 5610 | 12910 | 6760 | 4.41512 | 0
APTO2-JANELA-001 | Primeiro Pavimento | Projeto: CECAP GuarulhosLocal: Piso: Primeiro Pavimento Cômodo: | APTO2-001 | Janela -001 | 5.915 | 0.29575 | 1355.02 | 1355.02 | 2200.02 | 2200.02 | 11 | 24140 | 5.50517 | 7000 | 15690 | 8450 | 0 | 5.50517
APTO3-JANELA-000 | Primeiro Pavimento | Projeto: CECAP GuarulhosLocal: Piso: Primeiro Pavimento Cômodo: | APTO3-000 | Janela -000 | 4.74045 | 0.237023 | 1355 | 1355 | 2200 | 2200 | 9 | 19670 | 4.41512 | 5610 | 12910 | 6760 | 0 | 4.41512
APTO1-JANELA-001 | Primeiro Pavimento | Projeto: CECAP GuarulhosLocal: Piso: Primeiro Pavimento Cômodo: | APTO1-001 | Janela -001 | 5.915 | 0.29575 | 1355.02 | 1355.02 | 2200.02 | 2200.02 | 11 | 24140 | 5.50517 | 7000 | 15690 | 8450 | 0 | 5.50517
APTO1-JANELA-000 | Primeiro Pavimento | Projeto: CECAP GuarulhosLocal: Piso: Primeiro Pavimento Cômodo: | APTO1-000 | Janela -000 | 4.74045 | 0.237023 | 1355 | 1355 | 2200 | 2200 | 9 | 19670 | 4.41512 | 5610 | 12910 | 6760 | 4.41512 | 0
APTO5-JANELA-001 | Segundo Pavimento | Projeto: CECAP GuarulhosLocal: Piso: Segundo Pavimento Cômodo: | APTO5-001 | Janela -001 | 5.915 | 0.29575 | 4005.02 | 1355.02 | 4850.02 | 2200.02 | 11 | 24140 | 5.50517 | 7000 | 15690 | 8450 | 0 | 5.50517
APTO5-JANELA-000 | Segundo Pavimento | Projeto: CECAP GuarulhosLocal: Piso: Segundo Pavimento Cômodo: | APTO5-000 | Janela -000 | 4.74045 | 0.237023 | 4005 | 1355 | 4850 | 2200 | 9 | 19670 | 4.41512 | 5610 | 12910 | 6760 | 4.41512 | 0
APTO6-JANELA-000 | Segundo Pavimento | Projeto: CECAP GuarulhosLocal: Piso: Segundo Pavimento Cômodo: | APTO6-000 | Janela -000 | 4.74045 | 0.237023 | 4005 | 1355 | 4850 | 2200 | 9 | 19670 | 4.41512 | 5610 | 12910 | 6760 | 4.41512 | 0
APTO6-JANELA-001 | Segundo Pavimento | Projeto: CECAP GuarulhosLocal: Piso: Segundo Pavimento Cômodo: | APTO6-001 | Janela -001 | 5.915 | 0.29575 | 4005.02 | 1355.02 | 4850.02 | 2200.02 | 11 | 24140 | 5.50517 | 7000 | 15690 | 8450 | 0 | 5.50517
APTO7-JANELA-000 | Segundo Pavimento | Projeto: CECAP GuarulhosLocal: Piso: Segundo Pavimento Cômodo: | APTO7-000 | Janela -000 | 4.74045 | 0.237023 | 4005 | 1355 | 4850 | 2200 | 9 | 19670 | 4.41512 | 5610 | 12910 | 6760 | 0 | 4.41512
APTO7-JANELA-001 | Segundo Pavimento | Projeto: CECAP GuarulhosLocal: Piso: Segundo Pavimento Cômodo: | APTO7-001 | Janela -001 | 5.915 | 0.29575 | 4005.02 | 1355.02 | 4850.02 | 2200.02 | 11 | 24140 | 5.50517 | 7000 | 15690 | 8450 | 5.50517 | 0
APTO8-JANELA-000 | Segundo Pavimento | Projeto: CECAP GuarulhosLocal: Piso: Segundo Pavimento Cômodo: | APTO8-000 | Janela -000 | 4.74045 | 0.237023 | 4005 | 1355 | 4850 | 2200 | 9 | 19670 | 4.41512 | 5610 | 12910 | 6760 | 0 | 4.41512
APTO8-JANELA-001 | Segundo Pavimento | Projeto: CECAP GuarulhosLocal: Piso: Segundo Pavimento Cômodo: | APTO8-001 | Janela -001 | 5.915 | 0.29575 | 4005.02 | 1355.02 | 4850.02 | 2200.02 | 11 | 24140 | 5.50517 | 7000 | 15690 | 8450 | 5.50517 | 0
APTO9-JANELA-000 | Terceiro Pavimento | Projeto: CECAP GuarulhosLocal: Piso: Terceiro Pavimento Cômodo: | APTO9-000 | Janela -000 | 4.74045 | 0.237023 | 6655 | 1355 | 7500 | 2200 | 9 | 19670 | 4.41512 | 5610 | 12910 | 6760 | 4.41512 | 0
APTO9-JANELA-001 | Terceiro Pavimento | Projeto: CECAP GuarulhosLocal: Piso: Terceiro Pavimento Cômodo: | APTO9-001 | Janela -001 | 5.915 | 0.29575 | 6655.02 | 1355.02 | 7500.02 | 2200.02 | 11 | 24140 | 5.50517 | 7000 | 15690 | 8450 | 0 | 5.50517
APTO10-JANELA-000 | Terceiro Pavimento | Projeto: CECAP GuarulhosLocal: Piso: Terceiro Pavimento Cômodo: | APTO10-000 | Janela -000 | 4.74045 | 0.237023 | 6655 | 1355 | 7500 | 2200 | 9 | 19670 | 4.41512 | 5610 | 12910 | 6760 | 4.41512 | 0
APTO10-JANELA-001 | Terceiro Pavimento | Projeto: CECAP GuarulhosLocal: Piso: Terceiro Pavimento Cômodo: | APTO10-001 | Janela -001 | 5.915 | 0.29575 | 6655.02 | 1355.02 | 7500.02 | 2200.02 | 11 | 24140 | 5.50517 | 7000 | 15690 | 8450 | 0 | 5.50517
APTO11-JANELA-000 | Terceiro Pavimento | Projeto: CECAP GuarulhosLocal: Piso: Terceiro Pavimento Cômodo: | APTO11-000 | Janela -000 | 4.74045 | 0.237023 | 6655 | 1355 | 7500 | 2200 | 9 | 19670 | 4.41512 | 5610 | 12910 | 6760 | 0 | 4.41512
APTO11-JANELA-001 | Terceiro Pavimento | Projeto: CECAP GuarulhosLocal: Piso: Terceiro Pavimento Cômodo: | APTO11-001 | Janela -001 | 5.915 | 0.29575 | 6655.02 | 1355.02 | 7500.02 | 2200.02 | 11 | 24140 | 5.50517 | 7000 | 15690 | 8450 | 5.50517 | 0
APTO12-JANELA-000 | Terceiro Pavimento | Projeto: CECAP GuarulhosLocal: Piso: Terceiro Pavimento Cômodo: | APTO12-000 | Janela -000 | 4.74045 | 0.237023 | 6655 | 1355 | 7500 | 2200 | 9 | 19670 | 4.41512 | 5610 | 12910 | 6760 | 0 | 4.41512
APTO12-JANELA-001 | Terceiro Pavimento | Projeto: CECAP GuarulhosLocal: Piso: Terceiro Pavimento Cômodo: | APTO12-001 | Janela -001 | 5.915 | 0.29575 | 6655.02 | 1355.02 | 7500.02 | 2200.02 | 11 | 24140 | 5.50517 | 7000 | 15690 | 8450 | 5.50517 | 0
